VERSION 5.8 ;
BUSBITCHARS "[]" ;
DIVIDERCHAR "/" ;
UNITS
    DATABASE MICRONS 1000 ;
END UNITS

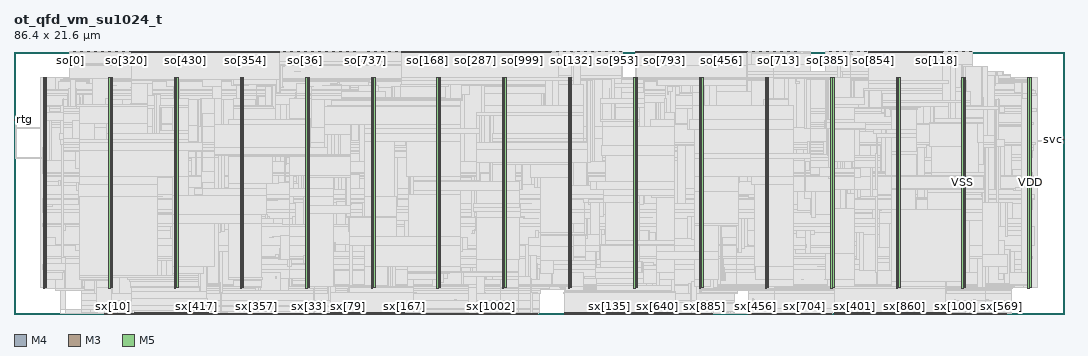
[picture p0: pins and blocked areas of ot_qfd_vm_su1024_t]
MACRO ot_qfd_vm_su1024_t
  FOREIGN ot_qfd_vm_su1024_t 0 0 ;
  CLASS BLOCK ;
  SIZE 86.4 BY 21.6 ;
  PIN clk
    DIRECTION INPUT ;
    USE SIGNAL ;
    PORT
      LAYER M4 ;
        RECT  0 15.888 0.084 15.912 ;
    END
  END clk
  PIN rtg
    DIRECTION INPUT ;
    USE SIGNAL ;
    PORT
      LAYER M4 ;
        RECT  0 15.984 0.084 16.008 ;
    END
  END rtg
  PIN so[0]
    DIRECTION OUTPUT ;
    USE SIGNAL ;
    PORT
      LAYER M3 ;
        RECT  4.644 21.563 4.662 21.6 ;
    END
  END so[0]
  PIN so[1000]
    DIRECTION OUTPUT ;
    USE SIGNAL ;
    PORT
      LAYER M5 ;
        RECT  41.904 21.516 41.928 21.6 ;
    END
  END so[1000]
  PIN so[1001]
    DIRECTION OUTPUT ;
    USE SIGNAL ;
    PORT
      LAYER M5 ;
        RECT  42 21.516 42.024 21.6 ;
    END
  END so[1001]
  PIN so[1002]
    DIRECTION OUTPUT ;
    USE SIGNAL ;
    PORT
      LAYER M5 ;
        RECT  42.096 21.516 42.12 21.6 ;
    END
  END so[1002]
  PIN so[1003]
    DIRECTION OUTPUT ;
    USE SIGNAL ;
    PORT
      LAYER M5 ;
        RECT  42.192 21.516 42.216 21.6 ;
    END
  END so[1003]
  PIN so[1004]
    DIRECTION OUTPUT ;
    USE SIGNAL ;
    PORT
      LAYER M5 ;
        RECT  42.288 21.516 42.312 21.6 ;
    END
  END so[1004]
  PIN so[1005]
    DIRECTION OUTPUT ;
    USE SIGNAL ;
    PORT
      LAYER M5 ;
        RECT  42.384 21.516 42.408 21.6 ;
    END
  END so[1005]
  PIN so[1006]
    DIRECTION OUTPUT ;
    USE SIGNAL ;
    PORT
      LAYER M5 ;
        RECT  42.48 21.516 42.504 21.6 ;
    END
  END so[1006]
  PIN so[1007]
    DIRECTION OUTPUT ;
    USE SIGNAL ;
    PORT
      LAYER M5 ;
        RECT  42.576 21.516 42.6 21.6 ;
    END
  END so[1007]
  PIN so[1008]
    DIRECTION OUTPUT ;
    USE SIGNAL ;
    PORT
      LAYER M5 ;
        RECT  42.672 21.516 42.696 21.6 ;
    END
  END so[1008]
  PIN so[1009]
    DIRECTION OUTPUT ;
    USE SIGNAL ;
    PORT
      LAYER M5 ;
        RECT  42.768 21.516 42.792 21.6 ;
    END
  END so[1009]
  PIN so[100]
    DIRECTION OUTPUT ;
    USE SIGNAL ;
    PORT
      LAYER M3 ;
        RECT  74.628 21.563 74.646 21.6 ;
    END
  END so[100]
  PIN so[1010]
    DIRECTION OUTPUT ;
    USE SIGNAL ;
    PORT
      LAYER M5 ;
        RECT  42.864 21.516 42.888 21.6 ;
    END
  END so[1010]
  PIN so[1011]
    DIRECTION OUTPUT ;
    USE SIGNAL ;
    PORT
      LAYER M5 ;
        RECT  42.96 21.516 42.984 21.6 ;
    END
  END so[1011]
  PIN so[1012]
    DIRECTION OUTPUT ;
    USE SIGNAL ;
    PORT
      LAYER M5 ;
        RECT  43.056 21.516 43.08 21.6 ;
    END
  END so[1012]
  PIN so[1013]
    DIRECTION OUTPUT ;
    USE SIGNAL ;
    PORT
      LAYER M5 ;
        RECT  43.152 21.516 43.176 21.6 ;
    END
  END so[1013]
  PIN so[1014]
    DIRECTION OUTPUT ;
    USE SIGNAL ;
    PORT
      LAYER M5 ;
        RECT  43.248 21.516 43.272 21.6 ;
    END
  END so[1014]
  PIN so[1015]
    DIRECTION OUTPUT ;
    USE SIGNAL ;
    PORT
      LAYER M5 ;
        RECT  43.344 21.516 43.368 21.6 ;
    END
  END so[1015]
  PIN so[1016]
    DIRECTION OUTPUT ;
    USE SIGNAL ;
    PORT
      LAYER M5 ;
        RECT  43.44 21.516 43.464 21.6 ;
    END
  END so[1016]
  PIN so[1017]
    DIRECTION OUTPUT ;
    USE SIGNAL ;
    PORT
      LAYER M5 ;
        RECT  43.536 21.516 43.56 21.6 ;
    END
  END so[1017]
  PIN so[1018]
    DIRECTION OUTPUT ;
    USE SIGNAL ;
    PORT
      LAYER M5 ;
        RECT  43.632 21.516 43.656 21.6 ;
    END
  END so[1018]
  PIN so[1019]
    DIRECTION OUTPUT ;
    USE SIGNAL ;
    PORT
      LAYER M5 ;
        RECT  43.728 21.516 43.752 21.6 ;
    END
  END so[1019]
  PIN so[101]
    DIRECTION OUTPUT ;
    USE SIGNAL ;
    PORT
      LAYER M3 ;
        RECT  74.7 21.563 74.718 21.6 ;
    END
  END so[101]
  PIN so[1020]
    DIRECTION OUTPUT ;
    USE SIGNAL ;
    PORT
      LAYER M5 ;
        RECT  43.824 21.516 43.848 21.6 ;
    END
  END so[1020]
  PIN so[1021]
    DIRECTION OUTPUT ;
    USE SIGNAL ;
    PORT
      LAYER M5 ;
        RECT  43.92 21.516 43.944 21.6 ;
    END
  END so[1021]
  PIN so[1022]
    DIRECTION OUTPUT ;
    USE SIGNAL ;
    PORT
      LAYER M5 ;
        RECT  44.016 21.516 44.04 21.6 ;
    END
  END so[1022]
  PIN so[1023]
    DIRECTION OUTPUT ;
    USE SIGNAL ;
    PORT
      LAYER M5 ;
        RECT  44.112 21.516 44.136 21.6 ;
    END
  END so[1023]
  PIN so[102]
    DIRECTION OUTPUT ;
    USE SIGNAL ;
    PORT
      LAYER M3 ;
        RECT  74.772 21.563 74.79 21.6 ;
    END
  END so[102]
  PIN so[103]
    DIRECTION OUTPUT ;
    USE SIGNAL ;
    PORT
      LAYER M3 ;
        RECT  74.844 21.563 74.862 21.6 ;
    END
  END so[103]
  PIN so[104]
    DIRECTION OUTPUT ;
    USE SIGNAL ;
    PORT
      LAYER M3 ;
        RECT  74.916 21.563 74.934 21.6 ;
    END
  END so[104]
  PIN so[105]
    DIRECTION OUTPUT ;
    USE SIGNAL ;
    PORT
      LAYER M3 ;
        RECT  74.988 21.563 75.006 21.6 ;
    END
  END so[105]
  PIN so[106]
    DIRECTION OUTPUT ;
    USE SIGNAL ;
    PORT
      LAYER M3 ;
        RECT  75.06 21.563 75.078 21.6 ;
    END
  END so[106]
  PIN so[107]
    DIRECTION OUTPUT ;
    USE SIGNAL ;
    PORT
      LAYER M3 ;
        RECT  75.132 21.563 75.15 21.6 ;
    END
  END so[107]
  PIN so[108]
    DIRECTION OUTPUT ;
    USE SIGNAL ;
    PORT
      LAYER M3 ;
        RECT  75.204 21.563 75.222 21.6 ;
    END
  END so[108]
  PIN so[109]
    DIRECTION OUTPUT ;
    USE SIGNAL ;
    PORT
      LAYER M3 ;
        RECT  75.276 21.563 75.294 21.6 ;
    END
  END so[109]
  PIN so[10]
    DIRECTION OUTPUT ;
    USE SIGNAL ;
    PORT
      LAYER M3 ;
        RECT  5.364 21.563 5.382 21.6 ;
    END
  END so[10]
  PIN so[110]
    DIRECTION OUTPUT ;
    USE SIGNAL ;
    PORT
      LAYER M3 ;
        RECT  75.348 21.563 75.366 21.6 ;
    END
  END so[110]
  PIN so[111]
    DIRECTION OUTPUT ;
    USE SIGNAL ;
    PORT
      LAYER M3 ;
        RECT  75.42 21.563 75.438 21.6 ;
    END
  END so[111]
  PIN so[112]
    DIRECTION OUTPUT ;
    USE SIGNAL ;
    PORT
      LAYER M3 ;
        RECT  75.492 21.563 75.51 21.6 ;
    END
  END so[112]
  PIN so[113]
    DIRECTION OUTPUT ;
    USE SIGNAL ;
    PORT
      LAYER M3 ;
        RECT  75.564 21.563 75.582 21.6 ;
    END
  END so[113]
  PIN so[114]
    DIRECTION OUTPUT ;
    USE SIGNAL ;
    PORT
      LAYER M3 ;
        RECT  75.636 21.563 75.654 21.6 ;
    END
  END so[114]
  PIN so[115]
    DIRECTION OUTPUT ;
    USE SIGNAL ;
    PORT
      LAYER M3 ;
        RECT  75.708 21.563 75.726 21.6 ;
    END
  END so[115]
  PIN so[116]
    DIRECTION OUTPUT ;
    USE SIGNAL ;
    PORT
      LAYER M3 ;
        RECT  75.78 21.563 75.798 21.6 ;
    END
  END so[116]
  PIN so[117]
    DIRECTION OUTPUT ;
    USE SIGNAL ;
    PORT
      LAYER M3 ;
        RECT  75.852 21.563 75.87 21.6 ;
    END
  END so[117]
  PIN so[118]
    DIRECTION OUTPUT ;
    USE SIGNAL ;
    PORT
      LAYER M3 ;
        RECT  75.924 21.563 75.942 21.6 ;
    END
  END so[118]
  PIN so[119]
    DIRECTION OUTPUT ;
    USE SIGNAL ;
    PORT
      LAYER M3 ;
        RECT  75.996 21.563 76.014 21.6 ;
    END
  END so[119]
  PIN so[11]
    DIRECTION OUTPUT ;
    USE SIGNAL ;
    PORT
      LAYER M3 ;
        RECT  5.436 21.563 5.454 21.6 ;
    END
  END so[11]
  PIN so[120]
    DIRECTION OUTPUT ;
    USE SIGNAL ;
    PORT
      LAYER M3 ;
        RECT  76.068 21.563 76.086 21.6 ;
    END
  END so[120]
  PIN so[121]
    DIRECTION OUTPUT ;
    USE SIGNAL ;
    PORT
      LAYER M3 ;
        RECT  76.14 21.563 76.158 21.6 ;
    END
  END so[121]
  PIN so[122]
    DIRECTION OUTPUT ;
    USE SIGNAL ;
    PORT
      LAYER M3 ;
        RECT  76.212 21.563 76.23 21.6 ;
    END
  END so[122]
  PIN so[123]
    DIRECTION OUTPUT ;
    USE SIGNAL ;
    PORT
      LAYER M3 ;
        RECT  76.284 21.563 76.302 21.6 ;
    END
  END so[123]
  PIN so[124]
    DIRECTION OUTPUT ;
    USE SIGNAL ;
    PORT
      LAYER M3 ;
        RECT  76.356 21.563 76.374 21.6 ;
    END
  END so[124]
  PIN so[125]
    DIRECTION OUTPUT ;
    USE SIGNAL ;
    PORT
      LAYER M3 ;
        RECT  76.428 21.563 76.446 21.6 ;
    END
  END so[125]
  PIN so[126]
    DIRECTION OUTPUT ;
    USE SIGNAL ;
    PORT
      LAYER M3 ;
        RECT  76.5 21.563 76.518 21.6 ;
    END
  END so[126]
  PIN so[127]
    DIRECTION OUTPUT ;
    USE SIGNAL ;
    PORT
      LAYER M3 ;
        RECT  76.572 21.563 76.59 21.6 ;
    END
  END so[127]
  PIN so[128]
    DIRECTION OUTPUT ;
    USE SIGNAL ;
    PORT
      LAYER M3 ;
        RECT  45.54 21.563 45.558 21.6 ;
    END
  END so[128]
  PIN so[129]
    DIRECTION OUTPUT ;
    USE SIGNAL ;
    PORT
      LAYER M3 ;
        RECT  45.612 21.563 45.63 21.6 ;
    END
  END so[129]
  PIN so[12]
    DIRECTION OUTPUT ;
    USE SIGNAL ;
    PORT
      LAYER M3 ;
        RECT  5.508 21.563 5.526 21.6 ;
    END
  END so[12]
  PIN so[130]
    DIRECTION OUTPUT ;
    USE SIGNAL ;
    PORT
      LAYER M3 ;
        RECT  45.684 21.563 45.702 21.6 ;
    END
  END so[130]
  PIN so[131]
    DIRECTION OUTPUT ;
    USE SIGNAL ;
    PORT
      LAYER M3 ;
        RECT  45.756 21.563 45.774 21.6 ;
    END
  END so[131]
  PIN so[132]
    DIRECTION OUTPUT ;
    USE SIGNAL ;
    PORT
      LAYER M3 ;
        RECT  45.828 21.563 45.846 21.6 ;
    END
  END so[132]
  PIN so[133]
    DIRECTION OUTPUT ;
    USE SIGNAL ;
    PORT
      LAYER M3 ;
        RECT  45.9 21.563 45.918 21.6 ;
    END
  END so[133]
  PIN so[134]
    DIRECTION OUTPUT ;
    USE SIGNAL ;
    PORT
      LAYER M3 ;
        RECT  45.972 21.563 45.99 21.6 ;
    END
  END so[134]
  PIN so[135]
    DIRECTION OUTPUT ;
    USE SIGNAL ;
    PORT
      LAYER M3 ;
        RECT  46.044 21.563 46.062 21.6 ;
    END
  END so[135]
  PIN so[136]
    DIRECTION OUTPUT ;
    USE SIGNAL ;
    PORT
      LAYER M3 ;
        RECT  46.116 21.563 46.134 21.6 ;
    END
  END so[136]
  PIN so[137]
    DIRECTION OUTPUT ;
    USE SIGNAL ;
    PORT
      LAYER M3 ;
        RECT  46.188 21.563 46.206 21.6 ;
    END
  END so[137]
  PIN so[138]
    DIRECTION OUTPUT ;
    USE SIGNAL ;
    PORT
      LAYER M3 ;
        RECT  46.26 21.563 46.278 21.6 ;
    END
  END so[138]
  PIN so[139]
    DIRECTION OUTPUT ;
    USE SIGNAL ;
    PORT
      LAYER M3 ;
        RECT  46.332 21.563 46.35 21.6 ;
    END
  END so[139]
  PIN so[13]
    DIRECTION OUTPUT ;
    USE SIGNAL ;
    PORT
      LAYER M3 ;
        RECT  5.58 21.563 5.598 21.6 ;
    END
  END so[13]
  PIN so[140]
    DIRECTION OUTPUT ;
    USE SIGNAL ;
    PORT
      LAYER M3 ;
        RECT  46.404 21.563 46.422 21.6 ;
    END
  END so[140]
  PIN so[141]
    DIRECTION OUTPUT ;
    USE SIGNAL ;
    PORT
      LAYER M3 ;
        RECT  46.476 21.563 46.494 21.6 ;
    END
  END so[141]
  PIN so[142]
    DIRECTION OUTPUT ;
    USE SIGNAL ;
    PORT
      LAYER M3 ;
        RECT  46.548 21.563 46.566 21.6 ;
    END
  END so[142]
  PIN so[143]
    DIRECTION OUTPUT ;
    USE SIGNAL ;
    PORT
      LAYER M3 ;
        RECT  46.62 21.563 46.638 21.6 ;
    END
  END so[143]
  PIN so[144]
    DIRECTION OUTPUT ;
    USE SIGNAL ;
    PORT
      LAYER M3 ;
        RECT  46.692 21.563 46.71 21.6 ;
    END
  END so[144]
  PIN so[145]
    DIRECTION OUTPUT ;
    USE SIGNAL ;
    PORT
      LAYER M3 ;
        RECT  46.764 21.563 46.782 21.6 ;
    END
  END so[145]
  PIN so[146]
    DIRECTION OUTPUT ;
    USE SIGNAL ;
    PORT
      LAYER M3 ;
        RECT  46.836 21.563 46.854 21.6 ;
    END
  END so[146]
  PIN so[147]
    DIRECTION OUTPUT ;
    USE SIGNAL ;
    PORT
      LAYER M3 ;
        RECT  46.908 21.563 46.926 21.6 ;
    END
  END so[147]
  PIN so[148]
    DIRECTION OUTPUT ;
    USE SIGNAL ;
    PORT
      LAYER M3 ;
        RECT  46.98 21.563 46.998 21.6 ;
    END
  END so[148]
  PIN so[149]
    DIRECTION OUTPUT ;
    USE SIGNAL ;
    PORT
      LAYER M3 ;
        RECT  47.052 21.563 47.07 21.6 ;
    END
  END so[149]
  PIN so[14]
    DIRECTION OUTPUT ;
    USE SIGNAL ;
    PORT
      LAYER M3 ;
        RECT  5.652 21.563 5.67 21.6 ;
    END
  END so[14]
  PIN so[150]
    DIRECTION OUTPUT ;
    USE SIGNAL ;
    PORT
      LAYER M3 ;
        RECT  47.124 21.563 47.142 21.6 ;
    END
  END so[150]
  PIN so[151]
    DIRECTION OUTPUT ;
    USE SIGNAL ;
    PORT
      LAYER M3 ;
        RECT  47.196 21.563 47.214 21.6 ;
    END
  END so[151]
  PIN so[152]
    DIRECTION OUTPUT ;
    USE SIGNAL ;
    PORT
      LAYER M3 ;
        RECT  47.268 21.563 47.286 21.6 ;
    END
  END so[152]
  PIN so[153]
    DIRECTION OUTPUT ;
    USE SIGNAL ;
    PORT
      LAYER M3 ;
        RECT  47.34 21.563 47.358 21.6 ;
    END
  END so[153]
  PIN so[154]
    DIRECTION OUTPUT ;
    USE SIGNAL ;
    PORT
      LAYER M3 ;
        RECT  47.412 21.563 47.43 21.6 ;
    END
  END so[154]
  PIN so[155]
    DIRECTION OUTPUT ;
    USE SIGNAL ;
    PORT
      LAYER M3 ;
        RECT  47.484 21.563 47.502 21.6 ;
    END
  END so[155]
  PIN so[156]
    DIRECTION OUTPUT ;
    USE SIGNAL ;
    PORT
      LAYER M3 ;
        RECT  47.556 21.563 47.574 21.6 ;
    END
  END so[156]
  PIN so[157]
    DIRECTION OUTPUT ;
    USE SIGNAL ;
    PORT
      LAYER M3 ;
        RECT  47.628 21.563 47.646 21.6 ;
    END
  END so[157]
  PIN so[158]
    DIRECTION OUTPUT ;
    USE SIGNAL ;
    PORT
      LAYER M3 ;
        RECT  47.7 21.563 47.718 21.6 ;
    END
  END so[158]
  PIN so[159]
    DIRECTION OUTPUT ;
    USE SIGNAL ;
    PORT
      LAYER M3 ;
        RECT  47.772 21.563 47.79 21.6 ;
    END
  END so[159]
  PIN so[15]
    DIRECTION OUTPUT ;
    USE SIGNAL ;
    PORT
      LAYER M3 ;
        RECT  5.724 21.563 5.742 21.6 ;
    END
  END so[15]
  PIN so[160]
    DIRECTION OUTPUT ;
    USE SIGNAL ;
    PORT
      LAYER M3 ;
        RECT  33.444 21.563 33.462 21.6 ;
    END
  END so[160]
  PIN so[161]
    DIRECTION OUTPUT ;
    USE SIGNAL ;
    PORT
      LAYER M3 ;
        RECT  33.516 21.563 33.534 21.6 ;
    END
  END so[161]
  PIN so[162]
    DIRECTION OUTPUT ;
    USE SIGNAL ;
    PORT
      LAYER M3 ;
        RECT  33.588 21.563 33.606 21.6 ;
    END
  END so[162]
  PIN so[163]
    DIRECTION OUTPUT ;
    USE SIGNAL ;
    PORT
      LAYER M3 ;
        RECT  33.66 21.563 33.678 21.6 ;
    END
  END so[163]
  PIN so[164]
    DIRECTION OUTPUT ;
    USE SIGNAL ;
    PORT
      LAYER M3 ;
        RECT  33.732 21.563 33.75 21.6 ;
    END
  END so[164]
  PIN so[165]
    DIRECTION OUTPUT ;
    USE SIGNAL ;
    PORT
      LAYER M3 ;
        RECT  33.804 21.563 33.822 21.6 ;
    END
  END so[165]
  PIN so[166]
    DIRECTION OUTPUT ;
    USE SIGNAL ;
    PORT
      LAYER M3 ;
        RECT  33.876 21.563 33.894 21.6 ;
    END
  END so[166]
  PIN so[167]
    DIRECTION OUTPUT ;
    USE SIGNAL ;
    PORT
      LAYER M3 ;
        RECT  33.948 21.563 33.966 21.6 ;
    END
  END so[167]
  PIN so[168]
    DIRECTION OUTPUT ;
    USE SIGNAL ;
    PORT
      LAYER M3 ;
        RECT  34.02 21.563 34.038 21.6 ;
    END
  END so[168]
  PIN so[169]
    DIRECTION OUTPUT ;
    USE SIGNAL ;
    PORT
      LAYER M3 ;
        RECT  34.092 21.563 34.11 21.6 ;
    END
  END so[169]
  PIN so[16]
    DIRECTION OUTPUT ;
    USE SIGNAL ;
    PORT
      LAYER M3 ;
        RECT  5.796 21.563 5.814 21.6 ;
    END
  END so[16]
  PIN so[170]
    DIRECTION OUTPUT ;
    USE SIGNAL ;
    PORT
      LAYER M3 ;
        RECT  34.164 21.563 34.182 21.6 ;
    END
  END so[170]
  PIN so[171]
    DIRECTION OUTPUT ;
    USE SIGNAL ;
    PORT
      LAYER M3 ;
        RECT  34.236 21.563 34.254 21.6 ;
    END
  END so[171]
  PIN so[172]
    DIRECTION OUTPUT ;
    USE SIGNAL ;
    PORT
      LAYER M3 ;
        RECT  34.308 21.563 34.326 21.6 ;
    END
  END so[172]
  PIN so[173]
    DIRECTION OUTPUT ;
    USE SIGNAL ;
    PORT
      LAYER M3 ;
        RECT  34.38 21.563 34.398 21.6 ;
    END
  END so[173]
  PIN so[174]
    DIRECTION OUTPUT ;
    USE SIGNAL ;
    PORT
      LAYER M3 ;
        RECT  34.452 21.563 34.47 21.6 ;
    END
  END so[174]
  PIN so[175]
    DIRECTION OUTPUT ;
    USE SIGNAL ;
    PORT
      LAYER M3 ;
        RECT  34.524 21.563 34.542 21.6 ;
    END
  END so[175]
  PIN so[176]
    DIRECTION OUTPUT ;
    USE SIGNAL ;
    PORT
      LAYER M3 ;
        RECT  34.596 21.563 34.614 21.6 ;
    END
  END so[176]
  PIN so[177]
    DIRECTION OUTPUT ;
    USE SIGNAL ;
    PORT
      LAYER M3 ;
        RECT  34.668 21.563 34.686 21.6 ;
    END
  END so[177]
  PIN so[178]
    DIRECTION OUTPUT ;
    USE SIGNAL ;
    PORT
      LAYER M3 ;
        RECT  34.74 21.563 34.758 21.6 ;
    END
  END so[178]
  PIN so[179]
    DIRECTION OUTPUT ;
    USE SIGNAL ;
    PORT
      LAYER M3 ;
        RECT  34.812 21.563 34.83 21.6 ;
    END
  END so[179]
  PIN so[17]
    DIRECTION OUTPUT ;
    USE SIGNAL ;
    PORT
      LAYER M3 ;
        RECT  5.868 21.563 5.886 21.6 ;
    END
  END so[17]
  PIN so[180]
    DIRECTION OUTPUT ;
    USE SIGNAL ;
    PORT
      LAYER M3 ;
        RECT  34.884 21.563 34.902 21.6 ;
    END
  END so[180]
  PIN so[181]
    DIRECTION OUTPUT ;
    USE SIGNAL ;
    PORT
      LAYER M3 ;
        RECT  34.956 21.563 34.974 21.6 ;
    END
  END so[181]
  PIN so[182]
    DIRECTION OUTPUT ;
    USE SIGNAL ;
    PORT
      LAYER M3 ;
        RECT  35.028 21.563 35.046 21.6 ;
    END
  END so[182]
  PIN so[183]
    DIRECTION OUTPUT ;
    USE SIGNAL ;
    PORT
      LAYER M3 ;
        RECT  35.1 21.563 35.118 21.6 ;
    END
  END so[183]
  PIN so[184]
    DIRECTION OUTPUT ;
    USE SIGNAL ;
    PORT
      LAYER M3 ;
        RECT  35.172 21.563 35.19 21.6 ;
    END
  END so[184]
  PIN so[185]
    DIRECTION OUTPUT ;
    USE SIGNAL ;
    PORT
      LAYER M3 ;
        RECT  35.244 21.563 35.262 21.6 ;
    END
  END so[185]
  PIN so[186]
    DIRECTION OUTPUT ;
    USE SIGNAL ;
    PORT
      LAYER M3 ;
        RECT  35.316 21.563 35.334 21.6 ;
    END
  END so[186]
  PIN so[187]
    DIRECTION OUTPUT ;
    USE SIGNAL ;
    PORT
      LAYER M3 ;
        RECT  35.388 21.563 35.406 21.6 ;
    END
  END so[187]
  PIN so[188]
    DIRECTION OUTPUT ;
    USE SIGNAL ;
    PORT
      LAYER M3 ;
        RECT  35.46 21.563 35.478 21.6 ;
    END
  END so[188]
  PIN so[189]
    DIRECTION OUTPUT ;
    USE SIGNAL ;
    PORT
      LAYER M3 ;
        RECT  35.532 21.563 35.55 21.6 ;
    END
  END so[189]
  PIN so[18]
    DIRECTION OUTPUT ;
    USE SIGNAL ;
    PORT
      LAYER M3 ;
        RECT  5.94 21.563 5.958 21.6 ;
    END
  END so[18]
  PIN so[190]
    DIRECTION OUTPUT ;
    USE SIGNAL ;
    PORT
      LAYER M3 ;
        RECT  35.604 21.563 35.622 21.6 ;
    END
  END so[190]
  PIN so[191]
    DIRECTION OUTPUT ;
    USE SIGNAL ;
    PORT
      LAYER M3 ;
        RECT  35.676 21.563 35.694 21.6 ;
    END
  END so[191]
  PIN so[192]
    DIRECTION OUTPUT ;
    USE SIGNAL ;
    PORT
      LAYER M5 ;
        RECT  70.32 21.516 70.344 21.6 ;
    END
  END so[192]
  PIN so[193]
    DIRECTION OUTPUT ;
    USE SIGNAL ;
    PORT
      LAYER M5 ;
        RECT  70.416 21.516 70.44 21.6 ;
    END
  END so[193]
  PIN so[194]
    DIRECTION OUTPUT ;
    USE SIGNAL ;
    PORT
      LAYER M5 ;
        RECT  70.512 21.516 70.536 21.6 ;
    END
  END so[194]
  PIN so[195]
    DIRECTION OUTPUT ;
    USE SIGNAL ;
    PORT
      LAYER M5 ;
        RECT  70.608 21.516 70.632 21.6 ;
    END
  END so[195]
  PIN so[196]
    DIRECTION OUTPUT ;
    USE SIGNAL ;
    PORT
      LAYER M5 ;
        RECT  70.704 21.516 70.728 21.6 ;
    END
  END so[196]
  PIN so[197]
    DIRECTION OUTPUT ;
    USE SIGNAL ;
    PORT
      LAYER M5 ;
        RECT  70.8 21.516 70.824 21.6 ;
    END
  END so[197]
  PIN so[198]
    DIRECTION OUTPUT ;
    USE SIGNAL ;
    PORT
      LAYER M5 ;
        RECT  70.896 21.516 70.92 21.6 ;
    END
  END so[198]
  PIN so[199]
    DIRECTION OUTPUT ;
    USE SIGNAL ;
    PORT
      LAYER M5 ;
        RECT  70.992 21.516 71.016 21.6 ;
    END
  END so[199]
  PIN so[19]
    DIRECTION OUTPUT ;
    USE SIGNAL ;
    PORT
      LAYER M3 ;
        RECT  6.012 21.563 6.03 21.6 ;
    END
  END so[19]
  PIN so[1]
    DIRECTION OUTPUT ;
    USE SIGNAL ;
    PORT
      LAYER M3 ;
        RECT  4.716 21.563 4.734 21.6 ;
    END
  END so[1]
  PIN so[200]
    DIRECTION OUTPUT ;
    USE SIGNAL ;
    PORT
      LAYER M5 ;
        RECT  71.088 21.516 71.112 21.6 ;
    END
  END so[200]
  PIN so[201]
    DIRECTION OUTPUT ;
    USE SIGNAL ;
    PORT
      LAYER M5 ;
        RECT  71.184 21.516 71.208 21.6 ;
    END
  END so[201]
  PIN so[202]
    DIRECTION OUTPUT ;
    USE SIGNAL ;
    PORT
      LAYER M5 ;
        RECT  71.28 21.516 71.304 21.6 ;
    END
  END so[202]
  PIN so[203]
    DIRECTION OUTPUT ;
    USE SIGNAL ;
    PORT
      LAYER M5 ;
        RECT  71.376 21.516 71.4 21.6 ;
    END
  END so[203]
  PIN so[204]
    DIRECTION OUTPUT ;
    USE SIGNAL ;
    PORT
      LAYER M5 ;
        RECT  71.472 21.516 71.496 21.6 ;
    END
  END so[204]
  PIN so[205]
    DIRECTION OUTPUT ;
    USE SIGNAL ;
    PORT
      LAYER M5 ;
        RECT  71.568 21.516 71.592 21.6 ;
    END
  END so[205]
  PIN so[206]
    DIRECTION OUTPUT ;
    USE SIGNAL ;
    PORT
      LAYER M5 ;
        RECT  71.664 21.516 71.688 21.6 ;
    END
  END so[206]
  PIN so[207]
    DIRECTION OUTPUT ;
    USE SIGNAL ;
    PORT
      LAYER M5 ;
        RECT  71.76 21.516 71.784 21.6 ;
    END
  END so[207]
  PIN so[208]
    DIRECTION OUTPUT ;
    USE SIGNAL ;
    PORT
      LAYER M5 ;
        RECT  71.856 21.516 71.88 21.6 ;
    END
  END so[208]
  PIN so[209]
    DIRECTION OUTPUT ;
    USE SIGNAL ;
    PORT
      LAYER M5 ;
        RECT  71.952 21.516 71.976 21.6 ;
    END
  END so[209]
  PIN so[20]
    DIRECTION OUTPUT ;
    USE SIGNAL ;
    PORT
      LAYER M3 ;
        RECT  6.084 21.563 6.102 21.6 ;
    END
  END so[20]
  PIN so[210]
    DIRECTION OUTPUT ;
    USE SIGNAL ;
    PORT
      LAYER M5 ;
        RECT  72.048 21.516 72.072 21.6 ;
    END
  END so[210]
  PIN so[211]
    DIRECTION OUTPUT ;
    USE SIGNAL ;
    PORT
      LAYER M5 ;
        RECT  72.144 21.516 72.168 21.6 ;
    END
  END so[211]
  PIN so[212]
    DIRECTION OUTPUT ;
    USE SIGNAL ;
    PORT
      LAYER M5 ;
        RECT  72.24 21.516 72.264 21.6 ;
    END
  END so[212]
  PIN so[213]
    DIRECTION OUTPUT ;
    USE SIGNAL ;
    PORT
      LAYER M5 ;
        RECT  72.336 21.516 72.36 21.6 ;
    END
  END so[213]
  PIN so[214]
    DIRECTION OUTPUT ;
    USE SIGNAL ;
    PORT
      LAYER M5 ;
        RECT  72.432 21.516 72.456 21.6 ;
    END
  END so[214]
  PIN so[215]
    DIRECTION OUTPUT ;
    USE SIGNAL ;
    PORT
      LAYER M5 ;
        RECT  72.528 21.516 72.552 21.6 ;
    END
  END so[215]
  PIN so[216]
    DIRECTION OUTPUT ;
    USE SIGNAL ;
    PORT
      LAYER M5 ;
        RECT  72.624 21.516 72.648 21.6 ;
    END
  END so[216]
  PIN so[217]
    DIRECTION OUTPUT ;
    USE SIGNAL ;
    PORT
      LAYER M5 ;
        RECT  72.72 21.516 72.744 21.6 ;
    END
  END so[217]
  PIN so[218]
    DIRECTION OUTPUT ;
    USE SIGNAL ;
    PORT
      LAYER M5 ;
        RECT  72.816 21.516 72.84 21.6 ;
    END
  END so[218]
  PIN so[219]
    DIRECTION OUTPUT ;
    USE SIGNAL ;
    PORT
      LAYER M5 ;
        RECT  72.912 21.516 72.936 21.6 ;
    END
  END so[219]
  PIN so[21]
    DIRECTION OUTPUT ;
    USE SIGNAL ;
    PORT
      LAYER M3 ;
        RECT  6.156 21.563 6.174 21.6 ;
    END
  END so[21]
  PIN so[220]
    DIRECTION OUTPUT ;
    USE SIGNAL ;
    PORT
      LAYER M5 ;
        RECT  73.008 21.516 73.032 21.6 ;
    END
  END so[220]
  PIN so[221]
    DIRECTION OUTPUT ;
    USE SIGNAL ;
    PORT
      LAYER M5 ;
        RECT  73.104 21.516 73.128 21.6 ;
    END
  END so[221]
  PIN so[222]
    DIRECTION OUTPUT ;
    USE SIGNAL ;
    PORT
      LAYER M5 ;
        RECT  73.2 21.516 73.224 21.6 ;
    END
  END so[222]
  PIN so[223]
    DIRECTION OUTPUT ;
    USE SIGNAL ;
    PORT
      LAYER M5 ;
        RECT  73.296 21.516 73.32 21.6 ;
    END
  END so[223]
  PIN so[224]
    DIRECTION OUTPUT ;
    USE SIGNAL ;
    PORT
      LAYER M5 ;
        RECT  31.92 21.516 31.944 21.6 ;
    END
  END so[224]
  PIN so[225]
    DIRECTION OUTPUT ;
    USE SIGNAL ;
    PORT
      LAYER M5 ;
        RECT  32.016 21.516 32.04 21.6 ;
    END
  END so[225]
  PIN so[226]
    DIRECTION OUTPUT ;
    USE SIGNAL ;
    PORT
      LAYER M5 ;
        RECT  32.112 21.516 32.136 21.6 ;
    END
  END so[226]
  PIN so[227]
    DIRECTION OUTPUT ;
    USE SIGNAL ;
    PORT
      LAYER M5 ;
        RECT  32.208 21.516 32.232 21.6 ;
    END
  END so[227]
  PIN so[228]
    DIRECTION OUTPUT ;
    USE SIGNAL ;
    PORT
      LAYER M5 ;
        RECT  32.304 21.516 32.328 21.6 ;
    END
  END so[228]
  PIN so[229]
    DIRECTION OUTPUT ;
    USE SIGNAL ;
    PORT
      LAYER M5 ;
        RECT  32.4 21.516 32.424 21.6 ;
    END
  END so[229]
  PIN so[22]
    DIRECTION OUTPUT ;
    USE SIGNAL ;
    PORT
      LAYER M3 ;
        RECT  6.228 21.563 6.246 21.6 ;
    END
  END so[22]
  PIN so[230]
    DIRECTION OUTPUT ;
    USE SIGNAL ;
    PORT
      LAYER M5 ;
        RECT  32.496 21.516 32.52 21.6 ;
    END
  END so[230]
  PIN so[231]
    DIRECTION OUTPUT ;
    USE SIGNAL ;
    PORT
      LAYER M5 ;
        RECT  32.592 21.516 32.616 21.6 ;
    END
  END so[231]
  PIN so[232]
    DIRECTION OUTPUT ;
    USE SIGNAL ;
    PORT
      LAYER M5 ;
        RECT  32.688 21.516 32.712 21.6 ;
    END
  END so[232]
  PIN so[233]
    DIRECTION OUTPUT ;
    USE SIGNAL ;
    PORT
      LAYER M5 ;
        RECT  32.784 21.516 32.808 21.6 ;
    END
  END so[233]
  PIN so[234]
    DIRECTION OUTPUT ;
    USE SIGNAL ;
    PORT
      LAYER M5 ;
        RECT  32.88 21.516 32.904 21.6 ;
    END
  END so[234]
  PIN so[235]
    DIRECTION OUTPUT ;
    USE SIGNAL ;
    PORT
      LAYER M5 ;
        RECT  32.976 21.516 33 21.6 ;
    END
  END so[235]
  PIN so[236]
    DIRECTION OUTPUT ;
    USE SIGNAL ;
    PORT
      LAYER M5 ;
        RECT  33.072 21.516 33.096 21.6 ;
    END
  END so[236]
  PIN so[237]
    DIRECTION OUTPUT ;
    USE SIGNAL ;
    PORT
      LAYER M5 ;
        RECT  33.168 21.516 33.192 21.6 ;
    END
  END so[237]
  PIN so[238]
    DIRECTION OUTPUT ;
    USE SIGNAL ;
    PORT
      LAYER M5 ;
        RECT  33.264 21.516 33.288 21.6 ;
    END
  END so[238]
  PIN so[239]
    DIRECTION OUTPUT ;
    USE SIGNAL ;
    PORT
      LAYER M5 ;
        RECT  33.36 21.516 33.384 21.6 ;
    END
  END so[239]
  PIN so[23]
    DIRECTION OUTPUT ;
    USE SIGNAL ;
    PORT
      LAYER M3 ;
        RECT  6.3 21.563 6.318 21.6 ;
    END
  END so[23]
  PIN so[240]
    DIRECTION OUTPUT ;
    USE SIGNAL ;
    PORT
      LAYER M5 ;
        RECT  33.456 21.516 33.48 21.6 ;
    END
  END so[240]
  PIN so[241]
    DIRECTION OUTPUT ;
    USE SIGNAL ;
    PORT
      LAYER M5 ;
        RECT  33.552 21.516 33.576 21.6 ;
    END
  END so[241]
  PIN so[242]
    DIRECTION OUTPUT ;
    USE SIGNAL ;
    PORT
      LAYER M5 ;
        RECT  33.648 21.516 33.672 21.6 ;
    END
  END so[242]
  PIN so[243]
    DIRECTION OUTPUT ;
    USE SIGNAL ;
    PORT
      LAYER M5 ;
        RECT  33.744 21.516 33.768 21.6 ;
    END
  END so[243]
  PIN so[244]
    DIRECTION OUTPUT ;
    USE SIGNAL ;
    PORT
      LAYER M5 ;
        RECT  33.84 21.516 33.864 21.6 ;
    END
  END so[244]
  PIN so[245]
    DIRECTION OUTPUT ;
    USE SIGNAL ;
    PORT
      LAYER M5 ;
        RECT  33.936 21.516 33.96 21.6 ;
    END
  END so[245]
  PIN so[246]
    DIRECTION OUTPUT ;
    USE SIGNAL ;
    PORT
      LAYER M5 ;
        RECT  34.032 21.516 34.056 21.6 ;
    END
  END so[246]
  PIN so[247]
    DIRECTION OUTPUT ;
    USE SIGNAL ;
    PORT
      LAYER M5 ;
        RECT  34.128 21.516 34.152 21.6 ;
    END
  END so[247]
  PIN so[248]
    DIRECTION OUTPUT ;
    USE SIGNAL ;
    PORT
      LAYER M5 ;
        RECT  34.224 21.516 34.248 21.6 ;
    END
  END so[248]
  PIN so[249]
    DIRECTION OUTPUT ;
    USE SIGNAL ;
    PORT
      LAYER M5 ;
        RECT  34.32 21.516 34.344 21.6 ;
    END
  END so[249]
  PIN so[24]
    DIRECTION OUTPUT ;
    USE SIGNAL ;
    PORT
      LAYER M3 ;
        RECT  6.372 21.563 6.39 21.6 ;
    END
  END so[24]
  PIN so[250]
    DIRECTION OUTPUT ;
    USE SIGNAL ;
    PORT
      LAYER M5 ;
        RECT  34.416 21.516 34.44 21.6 ;
    END
  END so[250]
  PIN so[251]
    DIRECTION OUTPUT ;
    USE SIGNAL ;
    PORT
      LAYER M5 ;
        RECT  34.512 21.516 34.536 21.6 ;
    END
  END so[251]
  PIN so[252]
    DIRECTION OUTPUT ;
    USE SIGNAL ;
    PORT
      LAYER M5 ;
        RECT  34.608 21.516 34.632 21.6 ;
    END
  END so[252]
  PIN so[253]
    DIRECTION OUTPUT ;
    USE SIGNAL ;
    PORT
      LAYER M5 ;
        RECT  34.704 21.516 34.728 21.6 ;
    END
  END so[253]
  PIN so[254]
    DIRECTION OUTPUT ;
    USE SIGNAL ;
    PORT
      LAYER M5 ;
        RECT  34.8 21.516 34.824 21.6 ;
    END
  END so[254]
  PIN so[255]
    DIRECTION OUTPUT ;
    USE SIGNAL ;
    PORT
      LAYER M5 ;
        RECT  34.896 21.516 34.92 21.6 ;
    END
  END so[255]
  PIN so[256]
    DIRECTION OUTPUT ;
    USE SIGNAL ;
    PORT
      LAYER M5 ;
        RECT  34.992 21.516 35.016 21.6 ;
    END
  END so[256]
  PIN so[257]
    DIRECTION OUTPUT ;
    USE SIGNAL ;
    PORT
      LAYER M5 ;
        RECT  35.088 21.516 35.112 21.6 ;
    END
  END so[257]
  PIN so[258]
    DIRECTION OUTPUT ;
    USE SIGNAL ;
    PORT
      LAYER M5 ;
        RECT  35.184 21.516 35.208 21.6 ;
    END
  END so[258]
  PIN so[259]
    DIRECTION OUTPUT ;
    USE SIGNAL ;
    PORT
      LAYER M5 ;
        RECT  35.28 21.516 35.304 21.6 ;
    END
  END so[259]
  PIN so[25]
    DIRECTION OUTPUT ;
    USE SIGNAL ;
    PORT
      LAYER M3 ;
        RECT  6.444 21.563 6.462 21.6 ;
    END
  END so[25]
  PIN so[260]
    DIRECTION OUTPUT ;
    USE SIGNAL ;
    PORT
      LAYER M5 ;
        RECT  35.376 21.516 35.4 21.6 ;
    END
  END so[260]
  PIN so[261]
    DIRECTION OUTPUT ;
    USE SIGNAL ;
    PORT
      LAYER M5 ;
        RECT  35.472 21.516 35.496 21.6 ;
    END
  END so[261]
  PIN so[262]
    DIRECTION OUTPUT ;
    USE SIGNAL ;
    PORT
      LAYER M5 ;
        RECT  35.568 21.516 35.592 21.6 ;
    END
  END so[262]
  PIN so[263]
    DIRECTION OUTPUT ;
    USE SIGNAL ;
    PORT
      LAYER M5 ;
        RECT  35.664 21.516 35.688 21.6 ;
    END
  END so[263]
  PIN so[264]
    DIRECTION OUTPUT ;
    USE SIGNAL ;
    PORT
      LAYER M5 ;
        RECT  35.76 21.516 35.784 21.6 ;
    END
  END so[264]
  PIN so[265]
    DIRECTION OUTPUT ;
    USE SIGNAL ;
    PORT
      LAYER M5 ;
        RECT  35.856 21.516 35.88 21.6 ;
    END
  END so[265]
  PIN so[266]
    DIRECTION OUTPUT ;
    USE SIGNAL ;
    PORT
      LAYER M5 ;
        RECT  35.952 21.516 35.976 21.6 ;
    END
  END so[266]
  PIN so[267]
    DIRECTION OUTPUT ;
    USE SIGNAL ;
    PORT
      LAYER M5 ;
        RECT  36.048 21.516 36.072 21.6 ;
    END
  END so[267]
  PIN so[268]
    DIRECTION OUTPUT ;
    USE SIGNAL ;
    PORT
      LAYER M5 ;
        RECT  36.144 21.516 36.168 21.6 ;
    END
  END so[268]
  PIN so[269]
    DIRECTION OUTPUT ;
    USE SIGNAL ;
    PORT
      LAYER M5 ;
        RECT  36.24 21.516 36.264 21.6 ;
    END
  END so[269]
  PIN so[26]
    DIRECTION OUTPUT ;
    USE SIGNAL ;
    PORT
      LAYER M3 ;
        RECT  6.516 21.563 6.534 21.6 ;
    END
  END so[26]
  PIN so[270]
    DIRECTION OUTPUT ;
    USE SIGNAL ;
    PORT
      LAYER M5 ;
        RECT  36.336 21.516 36.36 21.6 ;
    END
  END so[270]
  PIN so[271]
    DIRECTION OUTPUT ;
    USE SIGNAL ;
    PORT
      LAYER M5 ;
        RECT  36.432 21.516 36.456 21.6 ;
    END
  END so[271]
  PIN so[272]
    DIRECTION OUTPUT ;
    USE SIGNAL ;
    PORT
      LAYER M5 ;
        RECT  36.528 21.516 36.552 21.6 ;
    END
  END so[272]
  PIN so[273]
    DIRECTION OUTPUT ;
    USE SIGNAL ;
    PORT
      LAYER M5 ;
        RECT  36.624 21.516 36.648 21.6 ;
    END
  END so[273]
  PIN so[274]
    DIRECTION OUTPUT ;
    USE SIGNAL ;
    PORT
      LAYER M5 ;
        RECT  36.72 21.516 36.744 21.6 ;
    END
  END so[274]
  PIN so[275]
    DIRECTION OUTPUT ;
    USE SIGNAL ;
    PORT
      LAYER M5 ;
        RECT  36.816 21.516 36.84 21.6 ;
    END
  END so[275]
  PIN so[276]
    DIRECTION OUTPUT ;
    USE SIGNAL ;
    PORT
      LAYER M5 ;
        RECT  36.912 21.516 36.936 21.6 ;
    END
  END so[276]
  PIN so[277]
    DIRECTION OUTPUT ;
    USE SIGNAL ;
    PORT
      LAYER M5 ;
        RECT  37.008 21.516 37.032 21.6 ;
    END
  END so[277]
  PIN so[278]
    DIRECTION OUTPUT ;
    USE SIGNAL ;
    PORT
      LAYER M5 ;
        RECT  37.104 21.516 37.128 21.6 ;
    END
  END so[278]
  PIN so[279]
    DIRECTION OUTPUT ;
    USE SIGNAL ;
    PORT
      LAYER M5 ;
        RECT  37.2 21.516 37.224 21.6 ;
    END
  END so[279]
  PIN so[27]
    DIRECTION OUTPUT ;
    USE SIGNAL ;
    PORT
      LAYER M3 ;
        RECT  6.588 21.563 6.606 21.6 ;
    END
  END so[27]
  PIN so[280]
    DIRECTION OUTPUT ;
    USE SIGNAL ;
    PORT
      LAYER M5 ;
        RECT  37.296 21.516 37.32 21.6 ;
    END
  END so[280]
  PIN so[281]
    DIRECTION OUTPUT ;
    USE SIGNAL ;
    PORT
      LAYER M5 ;
        RECT  37.392 21.516 37.416 21.6 ;
    END
  END so[281]
  PIN so[282]
    DIRECTION OUTPUT ;
    USE SIGNAL ;
    PORT
      LAYER M5 ;
        RECT  37.488 21.516 37.512 21.6 ;
    END
  END so[282]
  PIN so[283]
    DIRECTION OUTPUT ;
    USE SIGNAL ;
    PORT
      LAYER M5 ;
        RECT  37.584 21.516 37.608 21.6 ;
    END
  END so[283]
  PIN so[284]
    DIRECTION OUTPUT ;
    USE SIGNAL ;
    PORT
      LAYER M5 ;
        RECT  37.68 21.516 37.704 21.6 ;
    END
  END so[284]
  PIN so[285]
    DIRECTION OUTPUT ;
    USE SIGNAL ;
    PORT
      LAYER M5 ;
        RECT  37.776 21.516 37.8 21.6 ;
    END
  END so[285]
  PIN so[286]
    DIRECTION OUTPUT ;
    USE SIGNAL ;
    PORT
      LAYER M5 ;
        RECT  37.872 21.516 37.896 21.6 ;
    END
  END so[286]
  PIN so[287]
    DIRECTION OUTPUT ;
    USE SIGNAL ;
    PORT
      LAYER M5 ;
        RECT  37.968 21.516 37.992 21.6 ;
    END
  END so[287]
  PIN so[288]
    DIRECTION OUTPUT ;
    USE SIGNAL ;
    PORT
      LAYER M3 ;
        RECT  43.236 21.563 43.254 21.6 ;
    END
  END so[288]
  PIN so[289]
    DIRECTION OUTPUT ;
    USE SIGNAL ;
    PORT
      LAYER M3 ;
        RECT  43.308 21.563 43.326 21.6 ;
    END
  END so[289]
  PIN so[28]
    DIRECTION OUTPUT ;
    USE SIGNAL ;
    PORT
      LAYER M3 ;
        RECT  6.66 21.563 6.678 21.6 ;
    END
  END so[28]
  PIN so[290]
    DIRECTION OUTPUT ;
    USE SIGNAL ;
    PORT
      LAYER M3 ;
        RECT  43.38 21.563 43.398 21.6 ;
    END
  END so[290]
  PIN so[291]
    DIRECTION OUTPUT ;
    USE SIGNAL ;
    PORT
      LAYER M3 ;
        RECT  43.452 21.563 43.47 21.6 ;
    END
  END so[291]
  PIN so[292]
    DIRECTION OUTPUT ;
    USE SIGNAL ;
    PORT
      LAYER M3 ;
        RECT  43.524 21.563 43.542 21.6 ;
    END
  END so[292]
  PIN so[293]
    DIRECTION OUTPUT ;
    USE SIGNAL ;
    PORT
      LAYER M3 ;
        RECT  43.596 21.563 43.614 21.6 ;
    END
  END so[293]
  PIN so[294]
    DIRECTION OUTPUT ;
    USE SIGNAL ;
    PORT
      LAYER M3 ;
        RECT  43.668 21.563 43.686 21.6 ;
    END
  END so[294]
  PIN so[295]
    DIRECTION OUTPUT ;
    USE SIGNAL ;
    PORT
      LAYER M3 ;
        RECT  43.74 21.563 43.758 21.6 ;
    END
  END so[295]
  PIN so[296]
    DIRECTION OUTPUT ;
    USE SIGNAL ;
    PORT
      LAYER M3 ;
        RECT  43.812 21.563 43.83 21.6 ;
    END
  END so[296]
  PIN so[297]
    DIRECTION OUTPUT ;
    USE SIGNAL ;
    PORT
      LAYER M3 ;
        RECT  43.884 21.563 43.902 21.6 ;
    END
  END so[297]
  PIN so[298]
    DIRECTION OUTPUT ;
    USE SIGNAL ;
    PORT
      LAYER M3 ;
        RECT  43.956 21.563 43.974 21.6 ;
    END
  END so[298]
  PIN so[299]
    DIRECTION OUTPUT ;
    USE SIGNAL ;
    PORT
      LAYER M3 ;
        RECT  44.028 21.563 44.046 21.6 ;
    END
  END so[299]
  PIN so[29]
    DIRECTION OUTPUT ;
    USE SIGNAL ;
    PORT
      LAYER M3 ;
        RECT  6.732 21.563 6.75 21.6 ;
    END
  END so[29]
  PIN so[2]
    DIRECTION OUTPUT ;
    USE SIGNAL ;
    PORT
      LAYER M3 ;
        RECT  4.788 21.563 4.806 21.6 ;
    END
  END so[2]
  PIN so[300]
    DIRECTION OUTPUT ;
    USE SIGNAL ;
    PORT
      LAYER M3 ;
        RECT  44.1 21.563 44.118 21.6 ;
    END
  END so[300]
  PIN so[301]
    DIRECTION OUTPUT ;
    USE SIGNAL ;
    PORT
      LAYER M3 ;
        RECT  44.172 21.563 44.19 21.6 ;
    END
  END so[301]
  PIN so[302]
    DIRECTION OUTPUT ;
    USE SIGNAL ;
    PORT
      LAYER M3 ;
        RECT  44.244 21.563 44.262 21.6 ;
    END
  END so[302]
  PIN so[303]
    DIRECTION OUTPUT ;
    USE SIGNAL ;
    PORT
      LAYER M3 ;
        RECT  44.316 21.563 44.334 21.6 ;
    END
  END so[303]
  PIN so[304]
    DIRECTION OUTPUT ;
    USE SIGNAL ;
    PORT
      LAYER M3 ;
        RECT  44.388 21.563 44.406 21.6 ;
    END
  END so[304]
  PIN so[305]
    DIRECTION OUTPUT ;
    USE SIGNAL ;
    PORT
      LAYER M3 ;
        RECT  44.46 21.563 44.478 21.6 ;
    END
  END so[305]
  PIN so[306]
    DIRECTION OUTPUT ;
    USE SIGNAL ;
    PORT
      LAYER M3 ;
        RECT  44.532 21.563 44.55 21.6 ;
    END
  END so[306]
  PIN so[307]
    DIRECTION OUTPUT ;
    USE SIGNAL ;
    PORT
      LAYER M3 ;
        RECT  44.604 21.563 44.622 21.6 ;
    END
  END so[307]
  PIN so[308]
    DIRECTION OUTPUT ;
    USE SIGNAL ;
    PORT
      LAYER M3 ;
        RECT  44.676 21.563 44.694 21.6 ;
    END
  END so[308]
  PIN so[309]
    DIRECTION OUTPUT ;
    USE SIGNAL ;
    PORT
      LAYER M3 ;
        RECT  44.748 21.563 44.766 21.6 ;
    END
  END so[309]
  PIN so[30]
    DIRECTION OUTPUT ;
    USE SIGNAL ;
    PORT
      LAYER M3 ;
        RECT  6.804 21.563 6.822 21.6 ;
    END
  END so[30]
  PIN so[310]
    DIRECTION OUTPUT ;
    USE SIGNAL ;
    PORT
      LAYER M3 ;
        RECT  44.82 21.563 44.838 21.6 ;
    END
  END so[310]
  PIN so[311]
    DIRECTION OUTPUT ;
    USE SIGNAL ;
    PORT
      LAYER M3 ;
        RECT  44.892 21.563 44.91 21.6 ;
    END
  END so[311]
  PIN so[312]
    DIRECTION OUTPUT ;
    USE SIGNAL ;
    PORT
      LAYER M3 ;
        RECT  44.964 21.563 44.982 21.6 ;
    END
  END so[312]
  PIN so[313]
    DIRECTION OUTPUT ;
    USE SIGNAL ;
    PORT
      LAYER M3 ;
        RECT  45.036 21.563 45.054 21.6 ;
    END
  END so[313]
  PIN so[314]
    DIRECTION OUTPUT ;
    USE SIGNAL ;
    PORT
      LAYER M3 ;
        RECT  45.108 21.563 45.126 21.6 ;
    END
  END so[314]
  PIN so[315]
    DIRECTION OUTPUT ;
    USE SIGNAL ;
    PORT
      LAYER M3 ;
        RECT  45.18 21.563 45.198 21.6 ;
    END
  END so[315]
  PIN so[316]
    DIRECTION OUTPUT ;
    USE SIGNAL ;
    PORT
      LAYER M3 ;
        RECT  45.252 21.563 45.27 21.6 ;
    END
  END so[316]
  PIN so[317]
    DIRECTION OUTPUT ;
    USE SIGNAL ;
    PORT
      LAYER M3 ;
        RECT  45.324 21.563 45.342 21.6 ;
    END
  END so[317]
  PIN so[318]
    DIRECTION OUTPUT ;
    USE SIGNAL ;
    PORT
      LAYER M3 ;
        RECT  45.396 21.563 45.414 21.6 ;
    END
  END so[318]
  PIN so[319]
    DIRECTION OUTPUT ;
    USE SIGNAL ;
    PORT
      LAYER M3 ;
        RECT  45.468 21.563 45.486 21.6 ;
    END
  END so[319]
  PIN so[31]
    DIRECTION OUTPUT ;
    USE SIGNAL ;
    PORT
      LAYER M3 ;
        RECT  6.876 21.563 6.894 21.6 ;
    END
  END so[31]
  PIN so[320]
    DIRECTION OUTPUT ;
    USE SIGNAL ;
    PORT
      LAYER M3 ;
        RECT  9.252 21.563 9.27 21.6 ;
    END
  END so[320]
  PIN so[321]
    DIRECTION OUTPUT ;
    USE SIGNAL ;
    PORT
      LAYER M3 ;
        RECT  9.324 21.563 9.342 21.6 ;
    END
  END so[321]
  PIN so[322]
    DIRECTION OUTPUT ;
    USE SIGNAL ;
    PORT
      LAYER M3 ;
        RECT  9.396 21.563 9.414 21.6 ;
    END
  END so[322]
  PIN so[323]
    DIRECTION OUTPUT ;
    USE SIGNAL ;
    PORT
      LAYER M3 ;
        RECT  9.468 21.563 9.486 21.6 ;
    END
  END so[323]
  PIN so[324]
    DIRECTION OUTPUT ;
    USE SIGNAL ;
    PORT
      LAYER M3 ;
        RECT  9.54 21.563 9.558 21.6 ;
    END
  END so[324]
  PIN so[325]
    DIRECTION OUTPUT ;
    USE SIGNAL ;
    PORT
      LAYER M3 ;
        RECT  9.612 21.563 9.63 21.6 ;
    END
  END so[325]
  PIN so[326]
    DIRECTION OUTPUT ;
    USE SIGNAL ;
    PORT
      LAYER M3 ;
        RECT  9.684 21.563 9.702 21.6 ;
    END
  END so[326]
  PIN so[327]
    DIRECTION OUTPUT ;
    USE SIGNAL ;
    PORT
      LAYER M3 ;
        RECT  9.756 21.563 9.774 21.6 ;
    END
  END so[327]
  PIN so[328]
    DIRECTION OUTPUT ;
    USE SIGNAL ;
    PORT
      LAYER M3 ;
        RECT  9.828 21.563 9.846 21.6 ;
    END
  END so[328]
  PIN so[329]
    DIRECTION OUTPUT ;
    USE SIGNAL ;
    PORT
      LAYER M3 ;
        RECT  9.9 21.563 9.918 21.6 ;
    END
  END so[329]
  PIN so[32]
    DIRECTION OUTPUT ;
    USE SIGNAL ;
    PORT
      LAYER M3 ;
        RECT  23.652 21.563 23.67 21.6 ;
    END
  END so[32]
  PIN so[330]
    DIRECTION OUTPUT ;
    USE SIGNAL ;
    PORT
      LAYER M3 ;
        RECT  9.972 21.563 9.99 21.6 ;
    END
  END so[330]
  PIN so[331]
    DIRECTION OUTPUT ;
    USE SIGNAL ;
    PORT
      LAYER M3 ;
        RECT  10.044 21.563 10.062 21.6 ;
    END
  END so[331]
  PIN so[332]
    DIRECTION OUTPUT ;
    USE SIGNAL ;
    PORT
      LAYER M3 ;
        RECT  10.116 21.563 10.134 21.6 ;
    END
  END so[332]
  PIN so[333]
    DIRECTION OUTPUT ;
    USE SIGNAL ;
    PORT
      LAYER M3 ;
        RECT  10.188 21.563 10.206 21.6 ;
    END
  END so[333]
  PIN so[334]
    DIRECTION OUTPUT ;
    USE SIGNAL ;
    PORT
      LAYER M3 ;
        RECT  10.26 21.563 10.278 21.6 ;
    END
  END so[334]
  PIN so[335]
    DIRECTION OUTPUT ;
    USE SIGNAL ;
    PORT
      LAYER M3 ;
        RECT  10.332 21.563 10.35 21.6 ;
    END
  END so[335]
  PIN so[336]
    DIRECTION OUTPUT ;
    USE SIGNAL ;
    PORT
      LAYER M3 ;
        RECT  10.404 21.563 10.422 21.6 ;
    END
  END so[336]
  PIN so[337]
    DIRECTION OUTPUT ;
    USE SIGNAL ;
    PORT
      LAYER M3 ;
        RECT  10.476 21.563 10.494 21.6 ;
    END
  END so[337]
  PIN so[338]
    DIRECTION OUTPUT ;
    USE SIGNAL ;
    PORT
      LAYER M3 ;
        RECT  10.548 21.563 10.566 21.6 ;
    END
  END so[338]
  PIN so[339]
    DIRECTION OUTPUT ;
    USE SIGNAL ;
    PORT
      LAYER M3 ;
        RECT  10.62 21.563 10.638 21.6 ;
    END
  END so[339]
  PIN so[33]
    DIRECTION OUTPUT ;
    USE SIGNAL ;
    PORT
      LAYER M3 ;
        RECT  23.724 21.563 23.742 21.6 ;
    END
  END so[33]
  PIN so[340]
    DIRECTION OUTPUT ;
    USE SIGNAL ;
    PORT
      LAYER M3 ;
        RECT  10.692 21.563 10.71 21.6 ;
    END
  END so[340]
  PIN so[341]
    DIRECTION OUTPUT ;
    USE SIGNAL ;
    PORT
      LAYER M3 ;
        RECT  10.764 21.563 10.782 21.6 ;
    END
  END so[341]
  PIN so[342]
    DIRECTION OUTPUT ;
    USE SIGNAL ;
    PORT
      LAYER M3 ;
        RECT  10.836 21.563 10.854 21.6 ;
    END
  END so[342]
  PIN so[343]
    DIRECTION OUTPUT ;
    USE SIGNAL ;
    PORT
      LAYER M3 ;
        RECT  10.908 21.563 10.926 21.6 ;
    END
  END so[343]
  PIN so[344]
    DIRECTION OUTPUT ;
    USE SIGNAL ;
    PORT
      LAYER M3 ;
        RECT  10.98 21.563 10.998 21.6 ;
    END
  END so[344]
  PIN so[345]
    DIRECTION OUTPUT ;
    USE SIGNAL ;
    PORT
      LAYER M3 ;
        RECT  11.052 21.563 11.07 21.6 ;
    END
  END so[345]
  PIN so[346]
    DIRECTION OUTPUT ;
    USE SIGNAL ;
    PORT
      LAYER M3 ;
        RECT  11.124 21.563 11.142 21.6 ;
    END
  END so[346]
  PIN so[347]
    DIRECTION OUTPUT ;
    USE SIGNAL ;
    PORT
      LAYER M3 ;
        RECT  11.196 21.563 11.214 21.6 ;
    END
  END so[347]
  PIN so[348]
    DIRECTION OUTPUT ;
    USE SIGNAL ;
    PORT
      LAYER M3 ;
        RECT  11.268 21.563 11.286 21.6 ;
    END
  END so[348]
  PIN so[349]
    DIRECTION OUTPUT ;
    USE SIGNAL ;
    PORT
      LAYER M3 ;
        RECT  11.34 21.563 11.358 21.6 ;
    END
  END so[349]
  PIN so[34]
    DIRECTION OUTPUT ;
    USE SIGNAL ;
    PORT
      LAYER M3 ;
        RECT  23.796 21.563 23.814 21.6 ;
    END
  END so[34]
  PIN so[350]
    DIRECTION OUTPUT ;
    USE SIGNAL ;
    PORT
      LAYER M3 ;
        RECT  11.412 21.563 11.43 21.6 ;
    END
  END so[350]
  PIN so[351]
    DIRECTION OUTPUT ;
    USE SIGNAL ;
    PORT
      LAYER M3 ;
        RECT  11.484 21.563 11.502 21.6 ;
    END
  END so[351]
  PIN so[352]
    DIRECTION OUTPUT ;
    USE SIGNAL ;
    PORT
      LAYER M5 ;
        RECT  18.864 21.516 18.888 21.6 ;
    END
  END so[352]
  PIN so[353]
    DIRECTION OUTPUT ;
    USE SIGNAL ;
    PORT
      LAYER M5 ;
        RECT  18.96 21.516 18.984 21.6 ;
    END
  END so[353]
  PIN so[354]
    DIRECTION OUTPUT ;
    USE SIGNAL ;
    PORT
      LAYER M5 ;
        RECT  19.056 21.516 19.08 21.6 ;
    END
  END so[354]
  PIN so[355]
    DIRECTION OUTPUT ;
    USE SIGNAL ;
    PORT
      LAYER M5 ;
        RECT  19.152 21.516 19.176 21.6 ;
    END
  END so[355]
  PIN so[356]
    DIRECTION OUTPUT ;
    USE SIGNAL ;
    PORT
      LAYER M5 ;
        RECT  19.248 21.516 19.272 21.6 ;
    END
  END so[356]
  PIN so[357]
    DIRECTION OUTPUT ;
    USE SIGNAL ;
    PORT
      LAYER M5 ;
        RECT  19.344 21.516 19.368 21.6 ;
    END
  END so[357]
  PIN so[358]
    DIRECTION OUTPUT ;
    USE SIGNAL ;
    PORT
      LAYER M5 ;
        RECT  19.44 21.516 19.464 21.6 ;
    END
  END so[358]
  PIN so[359]
    DIRECTION OUTPUT ;
    USE SIGNAL ;
    PORT
      LAYER M5 ;
        RECT  19.536 21.516 19.56 21.6 ;
    END
  END so[359]
  PIN so[35]
    DIRECTION OUTPUT ;
    USE SIGNAL ;
    PORT
      LAYER M3 ;
        RECT  23.868 21.563 23.886 21.6 ;
    END
  END so[35]
  PIN so[360]
    DIRECTION OUTPUT ;
    USE SIGNAL ;
    PORT
      LAYER M5 ;
        RECT  19.632 21.516 19.656 21.6 ;
    END
  END so[360]
  PIN so[361]
    DIRECTION OUTPUT ;
    USE SIGNAL ;
    PORT
      LAYER M5 ;
        RECT  19.728 21.516 19.752 21.6 ;
    END
  END so[361]
  PIN so[362]
    DIRECTION OUTPUT ;
    USE SIGNAL ;
    PORT
      LAYER M5 ;
        RECT  19.824 21.516 19.848 21.6 ;
    END
  END so[362]
  PIN so[363]
    DIRECTION OUTPUT ;
    USE SIGNAL ;
    PORT
      LAYER M5 ;
        RECT  19.92 21.516 19.944 21.6 ;
    END
  END so[363]
  PIN so[364]
    DIRECTION OUTPUT ;
    USE SIGNAL ;
    PORT
      LAYER M5 ;
        RECT  20.016 21.516 20.04 21.6 ;
    END
  END so[364]
  PIN so[365]
    DIRECTION OUTPUT ;
    USE SIGNAL ;
    PORT
      LAYER M5 ;
        RECT  20.112 21.516 20.136 21.6 ;
    END
  END so[365]
  PIN so[366]
    DIRECTION OUTPUT ;
    USE SIGNAL ;
    PORT
      LAYER M5 ;
        RECT  20.208 21.516 20.232 21.6 ;
    END
  END so[366]
  PIN so[367]
    DIRECTION OUTPUT ;
    USE SIGNAL ;
    PORT
      LAYER M5 ;
        RECT  20.304 21.516 20.328 21.6 ;
    END
  END so[367]
  PIN so[368]
    DIRECTION OUTPUT ;
    USE SIGNAL ;
    PORT
      LAYER M5 ;
        RECT  20.4 21.516 20.424 21.6 ;
    END
  END so[368]
  PIN so[369]
    DIRECTION OUTPUT ;
    USE SIGNAL ;
    PORT
      LAYER M5 ;
        RECT  20.496 21.516 20.52 21.6 ;
    END
  END so[369]
  PIN so[36]
    DIRECTION OUTPUT ;
    USE SIGNAL ;
    PORT
      LAYER M3 ;
        RECT  23.94 21.563 23.958 21.6 ;
    END
  END so[36]
  PIN so[370]
    DIRECTION OUTPUT ;
    USE SIGNAL ;
    PORT
      LAYER M5 ;
        RECT  20.592 21.516 20.616 21.6 ;
    END
  END so[370]
  PIN so[371]
    DIRECTION OUTPUT ;
    USE SIGNAL ;
    PORT
      LAYER M5 ;
        RECT  20.688 21.516 20.712 21.6 ;
    END
  END so[371]
  PIN so[372]
    DIRECTION OUTPUT ;
    USE SIGNAL ;
    PORT
      LAYER M5 ;
        RECT  20.784 21.516 20.808 21.6 ;
    END
  END so[372]
  PIN so[373]
    DIRECTION OUTPUT ;
    USE SIGNAL ;
    PORT
      LAYER M5 ;
        RECT  20.88 21.516 20.904 21.6 ;
    END
  END so[373]
  PIN so[374]
    DIRECTION OUTPUT ;
    USE SIGNAL ;
    PORT
      LAYER M5 ;
        RECT  20.976 21.516 21 21.6 ;
    END
  END so[374]
  PIN so[375]
    DIRECTION OUTPUT ;
    USE SIGNAL ;
    PORT
      LAYER M5 ;
        RECT  21.072 21.516 21.096 21.6 ;
    END
  END so[375]
  PIN so[376]
    DIRECTION OUTPUT ;
    USE SIGNAL ;
    PORT
      LAYER M5 ;
        RECT  21.168 21.516 21.192 21.6 ;
    END
  END so[376]
  PIN so[377]
    DIRECTION OUTPUT ;
    USE SIGNAL ;
    PORT
      LAYER M5 ;
        RECT  21.264 21.516 21.288 21.6 ;
    END
  END so[377]
  PIN so[378]
    DIRECTION OUTPUT ;
    USE SIGNAL ;
    PORT
      LAYER M5 ;
        RECT  21.36 21.516 21.384 21.6 ;
    END
  END so[378]
  PIN so[379]
    DIRECTION OUTPUT ;
    USE SIGNAL ;
    PORT
      LAYER M5 ;
        RECT  21.456 21.516 21.48 21.6 ;
    END
  END so[379]
  PIN so[37]
    DIRECTION OUTPUT ;
    USE SIGNAL ;
    PORT
      LAYER M3 ;
        RECT  24.012 21.563 24.03 21.6 ;
    END
  END so[37]
  PIN so[380]
    DIRECTION OUTPUT ;
    USE SIGNAL ;
    PORT
      LAYER M5 ;
        RECT  21.552 21.516 21.576 21.6 ;
    END
  END so[380]
  PIN so[381]
    DIRECTION OUTPUT ;
    USE SIGNAL ;
    PORT
      LAYER M5 ;
        RECT  21.648 21.516 21.672 21.6 ;
    END
  END so[381]
  PIN so[382]
    DIRECTION OUTPUT ;
    USE SIGNAL ;
    PORT
      LAYER M5 ;
        RECT  21.744 21.516 21.768 21.6 ;
    END
  END so[382]
  PIN so[383]
    DIRECTION OUTPUT ;
    USE SIGNAL ;
    PORT
      LAYER M5 ;
        RECT  21.84 21.516 21.864 21.6 ;
    END
  END so[383]
  PIN so[384]
    DIRECTION OUTPUT ;
    USE SIGNAL ;
    PORT
      LAYER M3 ;
        RECT  66.852 21.563 66.87 21.6 ;
    END
  END so[384]
  PIN so[385]
    DIRECTION OUTPUT ;
    USE SIGNAL ;
    PORT
      LAYER M3 ;
        RECT  66.924 21.563 66.942 21.6 ;
    END
  END so[385]
  PIN so[386]
    DIRECTION OUTPUT ;
    USE SIGNAL ;
    PORT
      LAYER M3 ;
        RECT  66.996 21.563 67.014 21.6 ;
    END
  END so[386]
  PIN so[387]
    DIRECTION OUTPUT ;
    USE SIGNAL ;
    PORT
      LAYER M3 ;
        RECT  67.068 21.563 67.086 21.6 ;
    END
  END so[387]
  PIN so[388]
    DIRECTION OUTPUT ;
    USE SIGNAL ;
    PORT
      LAYER M3 ;
        RECT  67.14 21.563 67.158 21.6 ;
    END
  END so[388]
  PIN so[389]
    DIRECTION OUTPUT ;
    USE SIGNAL ;
    PORT
      LAYER M3 ;
        RECT  67.212 21.563 67.23 21.6 ;
    END
  END so[389]
  PIN so[38]
    DIRECTION OUTPUT ;
    USE SIGNAL ;
    PORT
      LAYER M3 ;
        RECT  24.084 21.563 24.102 21.6 ;
    END
  END so[38]
  PIN so[390]
    DIRECTION OUTPUT ;
    USE SIGNAL ;
    PORT
      LAYER M3 ;
        RECT  67.284 21.563 67.302 21.6 ;
    END
  END so[390]
  PIN so[391]
    DIRECTION OUTPUT ;
    USE SIGNAL ;
    PORT
      LAYER M3 ;
        RECT  67.356 21.563 67.374 21.6 ;
    END
  END so[391]
  PIN so[392]
    DIRECTION OUTPUT ;
    USE SIGNAL ;
    PORT
      LAYER M3 ;
        RECT  67.428 21.563 67.446 21.6 ;
    END
  END so[392]
  PIN so[393]
    DIRECTION OUTPUT ;
    USE SIGNAL ;
    PORT
      LAYER M3 ;
        RECT  67.5 21.563 67.518 21.6 ;
    END
  END so[393]
  PIN so[394]
    DIRECTION OUTPUT ;
    USE SIGNAL ;
    PORT
      LAYER M3 ;
        RECT  67.572 21.563 67.59 21.6 ;
    END
  END so[394]
  PIN so[395]
    DIRECTION OUTPUT ;
    USE SIGNAL ;
    PORT
      LAYER M3 ;
        RECT  67.644 21.563 67.662 21.6 ;
    END
  END so[395]
  PIN so[396]
    DIRECTION OUTPUT ;
    USE SIGNAL ;
    PORT
      LAYER M3 ;
        RECT  67.716 21.563 67.734 21.6 ;
    END
  END so[396]
  PIN so[397]
    DIRECTION OUTPUT ;
    USE SIGNAL ;
    PORT
      LAYER M3 ;
        RECT  67.788 21.563 67.806 21.6 ;
    END
  END so[397]
  PIN so[398]
    DIRECTION OUTPUT ;
    USE SIGNAL ;
    PORT
      LAYER M3 ;
        RECT  67.86 21.563 67.878 21.6 ;
    END
  END so[398]
  PIN so[399]
    DIRECTION OUTPUT ;
    USE SIGNAL ;
    PORT
      LAYER M3 ;
        RECT  67.932 21.563 67.95 21.6 ;
    END
  END so[399]
  PIN so[39]
    DIRECTION OUTPUT ;
    USE SIGNAL ;
    PORT
      LAYER M3 ;
        RECT  24.156 21.563 24.174 21.6 ;
    END
  END so[39]
  PIN so[3]
    DIRECTION OUTPUT ;
    USE SIGNAL ;
    PORT
      LAYER M3 ;
        RECT  4.86 21.563 4.878 21.6 ;
    END
  END so[3]
  PIN so[400]
    DIRECTION OUTPUT ;
    USE SIGNAL ;
    PORT
      LAYER M3 ;
        RECT  68.004 21.563 68.022 21.6 ;
    END
  END so[400]
  PIN so[401]
    DIRECTION OUTPUT ;
    USE SIGNAL ;
    PORT
      LAYER M3 ;
        RECT  68.076 21.563 68.094 21.6 ;
    END
  END so[401]
  PIN so[402]
    DIRECTION OUTPUT ;
    USE SIGNAL ;
    PORT
      LAYER M3 ;
        RECT  68.148 21.563 68.166 21.6 ;
    END
  END so[402]
  PIN so[403]
    DIRECTION OUTPUT ;
    USE SIGNAL ;
    PORT
      LAYER M3 ;
        RECT  68.22 21.563 68.238 21.6 ;
    END
  END so[403]
  PIN so[404]
    DIRECTION OUTPUT ;
    USE SIGNAL ;
    PORT
      LAYER M3 ;
        RECT  68.292 21.563 68.31 21.6 ;
    END
  END so[404]
  PIN so[405]
    DIRECTION OUTPUT ;
    USE SIGNAL ;
    PORT
      LAYER M3 ;
        RECT  68.364 21.563 68.382 21.6 ;
    END
  END so[405]
  PIN so[406]
    DIRECTION OUTPUT ;
    USE SIGNAL ;
    PORT
      LAYER M3 ;
        RECT  68.436 21.563 68.454 21.6 ;
    END
  END so[406]
  PIN so[407]
    DIRECTION OUTPUT ;
    USE SIGNAL ;
    PORT
      LAYER M3 ;
        RECT  68.508 21.563 68.526 21.6 ;
    END
  END so[407]
  PIN so[408]
    DIRECTION OUTPUT ;
    USE SIGNAL ;
    PORT
      LAYER M3 ;
        RECT  68.58 21.563 68.598 21.6 ;
    END
  END so[408]
  PIN so[409]
    DIRECTION OUTPUT ;
    USE SIGNAL ;
    PORT
      LAYER M3 ;
        RECT  68.652 21.563 68.67 21.6 ;
    END
  END so[409]
  PIN so[40]
    DIRECTION OUTPUT ;
    USE SIGNAL ;
    PORT
      LAYER M3 ;
        RECT  24.228 21.563 24.246 21.6 ;
    END
  END so[40]
  PIN so[410]
    DIRECTION OUTPUT ;
    USE SIGNAL ;
    PORT
      LAYER M3 ;
        RECT  68.724 21.563 68.742 21.6 ;
    END
  END so[410]
  PIN so[411]
    DIRECTION OUTPUT ;
    USE SIGNAL ;
    PORT
      LAYER M3 ;
        RECT  68.796 21.563 68.814 21.6 ;
    END
  END so[411]
  PIN so[412]
    DIRECTION OUTPUT ;
    USE SIGNAL ;
    PORT
      LAYER M3 ;
        RECT  68.868 21.563 68.886 21.6 ;
    END
  END so[412]
  PIN so[413]
    DIRECTION OUTPUT ;
    USE SIGNAL ;
    PORT
      LAYER M3 ;
        RECT  68.94 21.563 68.958 21.6 ;
    END
  END so[413]
  PIN so[414]
    DIRECTION OUTPUT ;
    USE SIGNAL ;
    PORT
      LAYER M3 ;
        RECT  69.012 21.563 69.03 21.6 ;
    END
  END so[414]
  PIN so[415]
    DIRECTION OUTPUT ;
    USE SIGNAL ;
    PORT
      LAYER M3 ;
        RECT  69.084 21.563 69.102 21.6 ;
    END
  END so[415]
  PIN so[416]
    DIRECTION OUTPUT ;
    USE SIGNAL ;
    PORT
      LAYER M5 ;
        RECT  12.72 21.516 12.744 21.6 ;
    END
  END so[416]
  PIN so[417]
    DIRECTION OUTPUT ;
    USE SIGNAL ;
    PORT
      LAYER M5 ;
        RECT  12.816 21.516 12.84 21.6 ;
    END
  END so[417]
  PIN so[418]
    DIRECTION OUTPUT ;
    USE SIGNAL ;
    PORT
      LAYER M5 ;
        RECT  12.912 21.516 12.936 21.6 ;
    END
  END so[418]
  PIN so[419]
    DIRECTION OUTPUT ;
    USE SIGNAL ;
    PORT
      LAYER M5 ;
        RECT  13.008 21.516 13.032 21.6 ;
    END
  END so[419]
  PIN so[41]
    DIRECTION OUTPUT ;
    USE SIGNAL ;
    PORT
      LAYER M3 ;
        RECT  24.3 21.563 24.318 21.6 ;
    END
  END so[41]
  PIN so[420]
    DIRECTION OUTPUT ;
    USE SIGNAL ;
    PORT
      LAYER M5 ;
        RECT  13.104 21.516 13.128 21.6 ;
    END
  END so[420]
  PIN so[421]
    DIRECTION OUTPUT ;
    USE SIGNAL ;
    PORT
      LAYER M5 ;
        RECT  13.2 21.516 13.224 21.6 ;
    END
  END so[421]
  PIN so[422]
    DIRECTION OUTPUT ;
    USE SIGNAL ;
    PORT
      LAYER M5 ;
        RECT  13.296 21.516 13.32 21.6 ;
    END
  END so[422]
  PIN so[423]
    DIRECTION OUTPUT ;
    USE SIGNAL ;
    PORT
      LAYER M5 ;
        RECT  13.392 21.516 13.416 21.6 ;
    END
  END so[423]
  PIN so[424]
    DIRECTION OUTPUT ;
    USE SIGNAL ;
    PORT
      LAYER M5 ;
        RECT  13.488 21.516 13.512 21.6 ;
    END
  END so[424]
  PIN so[425]
    DIRECTION OUTPUT ;
    USE SIGNAL ;
    PORT
      LAYER M5 ;
        RECT  13.584 21.516 13.608 21.6 ;
    END
  END so[425]
  PIN so[426]
    DIRECTION OUTPUT ;
    USE SIGNAL ;
    PORT
      LAYER M5 ;
        RECT  13.68 21.516 13.704 21.6 ;
    END
  END so[426]
  PIN so[427]
    DIRECTION OUTPUT ;
    USE SIGNAL ;
    PORT
      LAYER M5 ;
        RECT  13.776 21.516 13.8 21.6 ;
    END
  END so[427]
  PIN so[428]
    DIRECTION OUTPUT ;
    USE SIGNAL ;
    PORT
      LAYER M5 ;
        RECT  13.872 21.516 13.896 21.6 ;
    END
  END so[428]
  PIN so[429]
    DIRECTION OUTPUT ;
    USE SIGNAL ;
    PORT
      LAYER M5 ;
        RECT  13.968 21.516 13.992 21.6 ;
    END
  END so[429]
  PIN so[42]
    DIRECTION OUTPUT ;
    USE SIGNAL ;
    PORT
      LAYER M3 ;
        RECT  24.372 21.563 24.39 21.6 ;
    END
  END so[42]
  PIN so[430]
    DIRECTION OUTPUT ;
    USE SIGNAL ;
    PORT
      LAYER M5 ;
        RECT  14.064 21.516 14.088 21.6 ;
    END
  END so[430]
  PIN so[431]
    DIRECTION OUTPUT ;
    USE SIGNAL ;
    PORT
      LAYER M5 ;
        RECT  14.16 21.516 14.184 21.6 ;
    END
  END so[431]
  PIN so[432]
    DIRECTION OUTPUT ;
    USE SIGNAL ;
    PORT
      LAYER M5 ;
        RECT  14.256 21.516 14.28 21.6 ;
    END
  END so[432]
  PIN so[433]
    DIRECTION OUTPUT ;
    USE SIGNAL ;
    PORT
      LAYER M5 ;
        RECT  14.352 21.516 14.376 21.6 ;
    END
  END so[433]
  PIN so[434]
    DIRECTION OUTPUT ;
    USE SIGNAL ;
    PORT
      LAYER M5 ;
        RECT  14.448 21.516 14.472 21.6 ;
    END
  END so[434]
  PIN so[435]
    DIRECTION OUTPUT ;
    USE SIGNAL ;
    PORT
      LAYER M5 ;
        RECT  14.544 21.516 14.568 21.6 ;
    END
  END so[435]
  PIN so[436]
    DIRECTION OUTPUT ;
    USE SIGNAL ;
    PORT
      LAYER M5 ;
        RECT  14.64 21.516 14.664 21.6 ;
    END
  END so[436]
  PIN so[437]
    DIRECTION OUTPUT ;
    USE SIGNAL ;
    PORT
      LAYER M5 ;
        RECT  14.736 21.516 14.76 21.6 ;
    END
  END so[437]
  PIN so[438]
    DIRECTION OUTPUT ;
    USE SIGNAL ;
    PORT
      LAYER M5 ;
        RECT  14.832 21.516 14.856 21.6 ;
    END
  END so[438]
  PIN so[439]
    DIRECTION OUTPUT ;
    USE SIGNAL ;
    PORT
      LAYER M5 ;
        RECT  14.928 21.516 14.952 21.6 ;
    END
  END so[439]
  PIN so[43]
    DIRECTION OUTPUT ;
    USE SIGNAL ;
    PORT
      LAYER M3 ;
        RECT  24.444 21.563 24.462 21.6 ;
    END
  END so[43]
  PIN so[440]
    DIRECTION OUTPUT ;
    USE SIGNAL ;
    PORT
      LAYER M5 ;
        RECT  15.024 21.516 15.048 21.6 ;
    END
  END so[440]
  PIN so[441]
    DIRECTION OUTPUT ;
    USE SIGNAL ;
    PORT
      LAYER M5 ;
        RECT  15.12 21.516 15.144 21.6 ;
    END
  END so[441]
  PIN so[442]
    DIRECTION OUTPUT ;
    USE SIGNAL ;
    PORT
      LAYER M5 ;
        RECT  15.216 21.516 15.24 21.6 ;
    END
  END so[442]
  PIN so[443]
    DIRECTION OUTPUT ;
    USE SIGNAL ;
    PORT
      LAYER M5 ;
        RECT  15.312 21.516 15.336 21.6 ;
    END
  END so[443]
  PIN so[444]
    DIRECTION OUTPUT ;
    USE SIGNAL ;
    PORT
      LAYER M5 ;
        RECT  15.408 21.516 15.432 21.6 ;
    END
  END so[444]
  PIN so[445]
    DIRECTION OUTPUT ;
    USE SIGNAL ;
    PORT
      LAYER M5 ;
        RECT  15.504 21.516 15.528 21.6 ;
    END
  END so[445]
  PIN so[446]
    DIRECTION OUTPUT ;
    USE SIGNAL ;
    PORT
      LAYER M5 ;
        RECT  15.6 21.516 15.624 21.6 ;
    END
  END so[446]
  PIN so[447]
    DIRECTION OUTPUT ;
    USE SIGNAL ;
    PORT
      LAYER M5 ;
        RECT  15.696 21.516 15.72 21.6 ;
    END
  END so[447]
  PIN so[448]
    DIRECTION OUTPUT ;
    USE SIGNAL ;
    PORT
      LAYER M3 ;
        RECT  57.636 21.563 57.654 21.6 ;
    END
  END so[448]
  PIN so[449]
    DIRECTION OUTPUT ;
    USE SIGNAL ;
    PORT
      LAYER M3 ;
        RECT  57.708 21.563 57.726 21.6 ;
    END
  END so[449]
  PIN so[44]
    DIRECTION OUTPUT ;
    USE SIGNAL ;
    PORT
      LAYER M3 ;
        RECT  24.516 21.563 24.534 21.6 ;
    END
  END so[44]
  PIN so[450]
    DIRECTION OUTPUT ;
    USE SIGNAL ;
    PORT
      LAYER M3 ;
        RECT  57.78 21.563 57.798 21.6 ;
    END
  END so[450]
  PIN so[451]
    DIRECTION OUTPUT ;
    USE SIGNAL ;
    PORT
      LAYER M3 ;
        RECT  57.852 21.563 57.87 21.6 ;
    END
  END so[451]
  PIN so[452]
    DIRECTION OUTPUT ;
    USE SIGNAL ;
    PORT
      LAYER M3 ;
        RECT  57.924 21.563 57.942 21.6 ;
    END
  END so[452]
  PIN so[453]
    DIRECTION OUTPUT ;
    USE SIGNAL ;
    PORT
      LAYER M3 ;
        RECT  57.996 21.563 58.014 21.6 ;
    END
  END so[453]
  PIN so[454]
    DIRECTION OUTPUT ;
    USE SIGNAL ;
    PORT
      LAYER M3 ;
        RECT  58.068 21.563 58.086 21.6 ;
    END
  END so[454]
  PIN so[455]
    DIRECTION OUTPUT ;
    USE SIGNAL ;
    PORT
      LAYER M3 ;
        RECT  58.14 21.563 58.158 21.6 ;
    END
  END so[455]
  PIN so[456]
    DIRECTION OUTPUT ;
    USE SIGNAL ;
    PORT
      LAYER M3 ;
        RECT  58.212 21.563 58.23 21.6 ;
    END
  END so[456]
  PIN so[457]
    DIRECTION OUTPUT ;
    USE SIGNAL ;
    PORT
      LAYER M3 ;
        RECT  58.284 21.563 58.302 21.6 ;
    END
  END so[457]
  PIN so[458]
    DIRECTION OUTPUT ;
    USE SIGNAL ;
    PORT
      LAYER M3 ;
        RECT  58.356 21.563 58.374 21.6 ;
    END
  END so[458]
  PIN so[459]
    DIRECTION OUTPUT ;
    USE SIGNAL ;
    PORT
      LAYER M3 ;
        RECT  58.428 21.563 58.446 21.6 ;
    END
  END so[459]
  PIN so[45]
    DIRECTION OUTPUT ;
    USE SIGNAL ;
    PORT
      LAYER M3 ;
        RECT  24.588 21.563 24.606 21.6 ;
    END
  END so[45]
  PIN so[460]
    DIRECTION OUTPUT ;
    USE SIGNAL ;
    PORT
      LAYER M3 ;
        RECT  58.5 21.563 58.518 21.6 ;
    END
  END so[460]
  PIN so[461]
    DIRECTION OUTPUT ;
    USE SIGNAL ;
    PORT
      LAYER M3 ;
        RECT  58.572 21.563 58.59 21.6 ;
    END
  END so[461]
  PIN so[462]
    DIRECTION OUTPUT ;
    USE SIGNAL ;
    PORT
      LAYER M3 ;
        RECT  58.644 21.563 58.662 21.6 ;
    END
  END so[462]
  PIN so[463]
    DIRECTION OUTPUT ;
    USE SIGNAL ;
    PORT
      LAYER M3 ;
        RECT  58.716 21.563 58.734 21.6 ;
    END
  END so[463]
  PIN so[464]
    DIRECTION OUTPUT ;
    USE SIGNAL ;
    PORT
      LAYER M3 ;
        RECT  58.788 21.563 58.806 21.6 ;
    END
  END so[464]
  PIN so[465]
    DIRECTION OUTPUT ;
    USE SIGNAL ;
    PORT
      LAYER M3 ;
        RECT  58.86 21.563 58.878 21.6 ;
    END
  END so[465]
  PIN so[466]
    DIRECTION OUTPUT ;
    USE SIGNAL ;
    PORT
      LAYER M3 ;
        RECT  58.932 21.563 58.95 21.6 ;
    END
  END so[466]
  PIN so[467]
    DIRECTION OUTPUT ;
    USE SIGNAL ;
    PORT
      LAYER M3 ;
        RECT  59.004 21.563 59.022 21.6 ;
    END
  END so[467]
  PIN so[468]
    DIRECTION OUTPUT ;
    USE SIGNAL ;
    PORT
      LAYER M3 ;
        RECT  59.076 21.563 59.094 21.6 ;
    END
  END so[468]
  PIN so[469]
    DIRECTION OUTPUT ;
    USE SIGNAL ;
    PORT
      LAYER M3 ;
        RECT  59.148 21.563 59.166 21.6 ;
    END
  END so[469]
  PIN so[46]
    DIRECTION OUTPUT ;
    USE SIGNAL ;
    PORT
      LAYER M3 ;
        RECT  24.66 21.563 24.678 21.6 ;
    END
  END so[46]
  PIN so[470]
    DIRECTION OUTPUT ;
    USE SIGNAL ;
    PORT
      LAYER M3 ;
        RECT  59.22 21.563 59.238 21.6 ;
    END
  END so[470]
  PIN so[471]
    DIRECTION OUTPUT ;
    USE SIGNAL ;
    PORT
      LAYER M3 ;
        RECT  59.292 21.563 59.31 21.6 ;
    END
  END so[471]
  PIN so[472]
    DIRECTION OUTPUT ;
    USE SIGNAL ;
    PORT
      LAYER M3 ;
        RECT  59.364 21.563 59.382 21.6 ;
    END
  END so[472]
  PIN so[473]
    DIRECTION OUTPUT ;
    USE SIGNAL ;
    PORT
      LAYER M3 ;
        RECT  59.436 21.563 59.454 21.6 ;
    END
  END so[473]
  PIN so[474]
    DIRECTION OUTPUT ;
    USE SIGNAL ;
    PORT
      LAYER M3 ;
        RECT  59.508 21.563 59.526 21.6 ;
    END
  END so[474]
  PIN so[475]
    DIRECTION OUTPUT ;
    USE SIGNAL ;
    PORT
      LAYER M3 ;
        RECT  59.58 21.563 59.598 21.6 ;
    END
  END so[475]
  PIN so[476]
    DIRECTION OUTPUT ;
    USE SIGNAL ;
    PORT
      LAYER M3 ;
        RECT  59.652 21.563 59.67 21.6 ;
    END
  END so[476]
  PIN so[477]
    DIRECTION OUTPUT ;
    USE SIGNAL ;
    PORT
      LAYER M3 ;
        RECT  59.724 21.563 59.742 21.6 ;
    END
  END so[477]
  PIN so[478]
    DIRECTION OUTPUT ;
    USE SIGNAL ;
    PORT
      LAYER M3 ;
        RECT  59.796 21.563 59.814 21.6 ;
    END
  END so[478]
  PIN so[479]
    DIRECTION OUTPUT ;
    USE SIGNAL ;
    PORT
      LAYER M3 ;
        RECT  59.868 21.563 59.886 21.6 ;
    END
  END so[479]
  PIN so[47]
    DIRECTION OUTPUT ;
    USE SIGNAL ;
    PORT
      LAYER M3 ;
        RECT  24.732 21.563 24.75 21.6 ;
    END
  END so[47]
  PIN so[480]
    DIRECTION OUTPUT ;
    USE SIGNAL ;
    PORT
      LAYER M5 ;
        RECT  38.064 21.516 38.088 21.6 ;
    END
  END so[480]
  PIN so[481]
    DIRECTION OUTPUT ;
    USE SIGNAL ;
    PORT
      LAYER M5 ;
        RECT  38.16 21.516 38.184 21.6 ;
    END
  END so[481]
  PIN so[482]
    DIRECTION OUTPUT ;
    USE SIGNAL ;
    PORT
      LAYER M5 ;
        RECT  38.256 21.516 38.28 21.6 ;
    END
  END so[482]
  PIN so[483]
    DIRECTION OUTPUT ;
    USE SIGNAL ;
    PORT
      LAYER M5 ;
        RECT  38.352 21.516 38.376 21.6 ;
    END
  END so[483]
  PIN so[484]
    DIRECTION OUTPUT ;
    USE SIGNAL ;
    PORT
      LAYER M5 ;
        RECT  38.448 21.516 38.472 21.6 ;
    END
  END so[484]
  PIN so[485]
    DIRECTION OUTPUT ;
    USE SIGNAL ;
    PORT
      LAYER M5 ;
        RECT  38.544 21.516 38.568 21.6 ;
    END
  END so[485]
  PIN so[486]
    DIRECTION OUTPUT ;
    USE SIGNAL ;
    PORT
      LAYER M5 ;
        RECT  38.64 21.516 38.664 21.6 ;
    END
  END so[486]
  PIN so[487]
    DIRECTION OUTPUT ;
    USE SIGNAL ;
    PORT
      LAYER M5 ;
        RECT  38.736 21.516 38.76 21.6 ;
    END
  END so[487]
  PIN so[488]
    DIRECTION OUTPUT ;
    USE SIGNAL ;
    PORT
      LAYER M5 ;
        RECT  38.832 21.516 38.856 21.6 ;
    END
  END so[488]
  PIN so[489]
    DIRECTION OUTPUT ;
    USE SIGNAL ;
    PORT
      LAYER M5 ;
        RECT  38.928 21.516 38.952 21.6 ;
    END
  END so[489]
  PIN so[48]
    DIRECTION OUTPUT ;
    USE SIGNAL ;
    PORT
      LAYER M3 ;
        RECT  24.804 21.563 24.822 21.6 ;
    END
  END so[48]
  PIN so[490]
    DIRECTION OUTPUT ;
    USE SIGNAL ;
    PORT
      LAYER M5 ;
        RECT  39.024 21.516 39.048 21.6 ;
    END
  END so[490]
  PIN so[491]
    DIRECTION OUTPUT ;
    USE SIGNAL ;
    PORT
      LAYER M5 ;
        RECT  39.12 21.516 39.144 21.6 ;
    END
  END so[491]
  PIN so[492]
    DIRECTION OUTPUT ;
    USE SIGNAL ;
    PORT
      LAYER M5 ;
        RECT  39.216 21.516 39.24 21.6 ;
    END
  END so[492]
  PIN so[493]
    DIRECTION OUTPUT ;
    USE SIGNAL ;
    PORT
      LAYER M5 ;
        RECT  39.312 21.516 39.336 21.6 ;
    END
  END so[493]
  PIN so[494]
    DIRECTION OUTPUT ;
    USE SIGNAL ;
    PORT
      LAYER M5 ;
        RECT  39.408 21.516 39.432 21.6 ;
    END
  END so[494]
  PIN so[495]
    DIRECTION OUTPUT ;
    USE SIGNAL ;
    PORT
      LAYER M5 ;
        RECT  39.504 21.516 39.528 21.6 ;
    END
  END so[495]
  PIN so[496]
    DIRECTION OUTPUT ;
    USE SIGNAL ;
    PORT
      LAYER M5 ;
        RECT  39.6 21.516 39.624 21.6 ;
    END
  END so[496]
  PIN so[497]
    DIRECTION OUTPUT ;
    USE SIGNAL ;
    PORT
      LAYER M5 ;
        RECT  39.696 21.516 39.72 21.6 ;
    END
  END so[497]
  PIN so[498]
    DIRECTION OUTPUT ;
    USE SIGNAL ;
    PORT
      LAYER M5 ;
        RECT  39.792 21.516 39.816 21.6 ;
    END
  END so[498]
  PIN so[499]
    DIRECTION OUTPUT ;
    USE SIGNAL ;
    PORT
      LAYER M5 ;
        RECT  39.888 21.516 39.912 21.6 ;
    END
  END so[499]
  PIN so[49]
    DIRECTION OUTPUT ;
    USE SIGNAL ;
    PORT
      LAYER M3 ;
        RECT  24.876 21.563 24.894 21.6 ;
    END
  END so[49]
  PIN so[4]
    DIRECTION OUTPUT ;
    USE SIGNAL ;
    PORT
      LAYER M3 ;
        RECT  4.932 21.563 4.95 21.6 ;
    END
  END so[4]
  PIN so[500]
    DIRECTION OUTPUT ;
    USE SIGNAL ;
    PORT
      LAYER M5 ;
        RECT  39.984 21.516 40.008 21.6 ;
    END
  END so[500]
  PIN so[501]
    DIRECTION OUTPUT ;
    USE SIGNAL ;
    PORT
      LAYER M5 ;
        RECT  40.08 21.516 40.104 21.6 ;
    END
  END so[501]
  PIN so[502]
    DIRECTION OUTPUT ;
    USE SIGNAL ;
    PORT
      LAYER M5 ;
        RECT  40.176 21.516 40.2 21.6 ;
    END
  END so[502]
  PIN so[503]
    DIRECTION OUTPUT ;
    USE SIGNAL ;
    PORT
      LAYER M5 ;
        RECT  40.272 21.516 40.296 21.6 ;
    END
  END so[503]
  PIN so[504]
    DIRECTION OUTPUT ;
    USE SIGNAL ;
    PORT
      LAYER M5 ;
        RECT  40.368 21.516 40.392 21.6 ;
    END
  END so[504]
  PIN so[505]
    DIRECTION OUTPUT ;
    USE SIGNAL ;
    PORT
      LAYER M5 ;
        RECT  40.464 21.516 40.488 21.6 ;
    END
  END so[505]
  PIN so[506]
    DIRECTION OUTPUT ;
    USE SIGNAL ;
    PORT
      LAYER M5 ;
        RECT  40.56 21.516 40.584 21.6 ;
    END
  END so[506]
  PIN so[507]
    DIRECTION OUTPUT ;
    USE SIGNAL ;
    PORT
      LAYER M5 ;
        RECT  40.656 21.516 40.68 21.6 ;
    END
  END so[507]
  PIN so[508]
    DIRECTION OUTPUT ;
    USE SIGNAL ;
    PORT
      LAYER M5 ;
        RECT  40.752 21.516 40.776 21.6 ;
    END
  END so[508]
  PIN so[509]
    DIRECTION OUTPUT ;
    USE SIGNAL ;
    PORT
      LAYER M5 ;
        RECT  40.848 21.516 40.872 21.6 ;
    END
  END so[509]
  PIN so[50]
    DIRECTION OUTPUT ;
    USE SIGNAL ;
    PORT
      LAYER M3 ;
        RECT  24.948 21.563 24.966 21.6 ;
    END
  END so[50]
  PIN so[510]
    DIRECTION OUTPUT ;
    USE SIGNAL ;
    PORT
      LAYER M5 ;
        RECT  40.944 21.516 40.968 21.6 ;
    END
  END so[510]
  PIN so[511]
    DIRECTION OUTPUT ;
    USE SIGNAL ;
    PORT
      LAYER M5 ;
        RECT  41.04 21.516 41.064 21.6 ;
    END
  END so[511]
  PIN so[512]
    DIRECTION OUTPUT ;
    USE SIGNAL ;
    PORT
      LAYER M3 ;
        RECT  59.94 21.563 59.958 21.6 ;
    END
  END so[512]
  PIN so[513]
    DIRECTION OUTPUT ;
    USE SIGNAL ;
    PORT
      LAYER M3 ;
        RECT  60.012 21.563 60.03 21.6 ;
    END
  END so[513]
  PIN so[514]
    DIRECTION OUTPUT ;
    USE SIGNAL ;
    PORT
      LAYER M3 ;
        RECT  60.084 21.563 60.102 21.6 ;
    END
  END so[514]
  PIN so[515]
    DIRECTION OUTPUT ;
    USE SIGNAL ;
    PORT
      LAYER M3 ;
        RECT  60.156 21.563 60.174 21.6 ;
    END
  END so[515]
  PIN so[516]
    DIRECTION OUTPUT ;
    USE SIGNAL ;
    PORT
      LAYER M3 ;
        RECT  60.228 21.563 60.246 21.6 ;
    END
  END so[516]
  PIN so[517]
    DIRECTION OUTPUT ;
    USE SIGNAL ;
    PORT
      LAYER M3 ;
        RECT  60.3 21.563 60.318 21.6 ;
    END
  END so[517]
  PIN so[518]
    DIRECTION OUTPUT ;
    USE SIGNAL ;
    PORT
      LAYER M3 ;
        RECT  60.372 21.563 60.39 21.6 ;
    END
  END so[518]
  PIN so[519]
    DIRECTION OUTPUT ;
    USE SIGNAL ;
    PORT
      LAYER M3 ;
        RECT  60.444 21.563 60.462 21.6 ;
    END
  END so[519]
  PIN so[51]
    DIRECTION OUTPUT ;
    USE SIGNAL ;
    PORT
      LAYER M3 ;
        RECT  25.02 21.563 25.038 21.6 ;
    END
  END so[51]
  PIN so[520]
    DIRECTION OUTPUT ;
    USE SIGNAL ;
    PORT
      LAYER M3 ;
        RECT  60.516 21.563 60.534 21.6 ;
    END
  END so[520]
  PIN so[521]
    DIRECTION OUTPUT ;
    USE SIGNAL ;
    PORT
      LAYER M3 ;
        RECT  60.588 21.563 60.606 21.6 ;
    END
  END so[521]
  PIN so[522]
    DIRECTION OUTPUT ;
    USE SIGNAL ;
    PORT
      LAYER M3 ;
        RECT  60.66 21.563 60.678 21.6 ;
    END
  END so[522]
  PIN so[523]
    DIRECTION OUTPUT ;
    USE SIGNAL ;
    PORT
      LAYER M3 ;
        RECT  60.732 21.563 60.75 21.6 ;
    END
  END so[523]
  PIN so[524]
    DIRECTION OUTPUT ;
    USE SIGNAL ;
    PORT
      LAYER M3 ;
        RECT  60.804 21.563 60.822 21.6 ;
    END
  END so[524]
  PIN so[525]
    DIRECTION OUTPUT ;
    USE SIGNAL ;
    PORT
      LAYER M3 ;
        RECT  60.876 21.563 60.894 21.6 ;
    END
  END so[525]
  PIN so[526]
    DIRECTION OUTPUT ;
    USE SIGNAL ;
    PORT
      LAYER M3 ;
        RECT  60.948 21.563 60.966 21.6 ;
    END
  END so[526]
  PIN so[527]
    DIRECTION OUTPUT ;
    USE SIGNAL ;
    PORT
      LAYER M3 ;
        RECT  61.02 21.563 61.038 21.6 ;
    END
  END so[527]
  PIN so[528]
    DIRECTION OUTPUT ;
    USE SIGNAL ;
    PORT
      LAYER M3 ;
        RECT  61.092 21.563 61.11 21.6 ;
    END
  END so[528]
  PIN so[529]
    DIRECTION OUTPUT ;
    USE SIGNAL ;
    PORT
      LAYER M3 ;
        RECT  61.164 21.563 61.182 21.6 ;
    END
  END so[529]
  PIN so[52]
    DIRECTION OUTPUT ;
    USE SIGNAL ;
    PORT
      LAYER M3 ;
        RECT  25.092 21.563 25.11 21.6 ;
    END
  END so[52]
  PIN so[530]
    DIRECTION OUTPUT ;
    USE SIGNAL ;
    PORT
      LAYER M3 ;
        RECT  61.236 21.563 61.254 21.6 ;
    END
  END so[530]
  PIN so[531]
    DIRECTION OUTPUT ;
    USE SIGNAL ;
    PORT
      LAYER M3 ;
        RECT  61.308 21.563 61.326 21.6 ;
    END
  END so[531]
  PIN so[532]
    DIRECTION OUTPUT ;
    USE SIGNAL ;
    PORT
      LAYER M3 ;
        RECT  61.38 21.563 61.398 21.6 ;
    END
  END so[532]
  PIN so[533]
    DIRECTION OUTPUT ;
    USE SIGNAL ;
    PORT
      LAYER M3 ;
        RECT  61.452 21.563 61.47 21.6 ;
    END
  END so[533]
  PIN so[534]
    DIRECTION OUTPUT ;
    USE SIGNAL ;
    PORT
      LAYER M3 ;
        RECT  61.524 21.563 61.542 21.6 ;
    END
  END so[534]
  PIN so[535]
    DIRECTION OUTPUT ;
    USE SIGNAL ;
    PORT
      LAYER M3 ;
        RECT  61.596 21.563 61.614 21.6 ;
    END
  END so[535]
  PIN so[536]
    DIRECTION OUTPUT ;
    USE SIGNAL ;
    PORT
      LAYER M3 ;
        RECT  61.668 21.563 61.686 21.6 ;
    END
  END so[536]
  PIN so[537]
    DIRECTION OUTPUT ;
    USE SIGNAL ;
    PORT
      LAYER M3 ;
        RECT  61.74 21.563 61.758 21.6 ;
    END
  END so[537]
  PIN so[538]
    DIRECTION OUTPUT ;
    USE SIGNAL ;
    PORT
      LAYER M3 ;
        RECT  61.812 21.563 61.83 21.6 ;
    END
  END so[538]
  PIN so[539]
    DIRECTION OUTPUT ;
    USE SIGNAL ;
    PORT
      LAYER M3 ;
        RECT  61.884 21.563 61.902 21.6 ;
    END
  END so[539]
  PIN so[53]
    DIRECTION OUTPUT ;
    USE SIGNAL ;
    PORT
      LAYER M3 ;
        RECT  25.164 21.563 25.182 21.6 ;
    END
  END so[53]
  PIN so[540]
    DIRECTION OUTPUT ;
    USE SIGNAL ;
    PORT
      LAYER M3 ;
        RECT  61.956 21.563 61.974 21.6 ;
    END
  END so[540]
  PIN so[541]
    DIRECTION OUTPUT ;
    USE SIGNAL ;
    PORT
      LAYER M3 ;
        RECT  62.028 21.563 62.046 21.6 ;
    END
  END so[541]
  PIN so[542]
    DIRECTION OUTPUT ;
    USE SIGNAL ;
    PORT
      LAYER M3 ;
        RECT  62.1 21.563 62.118 21.6 ;
    END
  END so[542]
  PIN so[543]
    DIRECTION OUTPUT ;
    USE SIGNAL ;
    PORT
      LAYER M3 ;
        RECT  62.172 21.563 62.19 21.6 ;
    END
  END so[543]
  PIN so[544]
    DIRECTION OUTPUT ;
    USE SIGNAL ;
    PORT
      LAYER M3 ;
        RECT  76.644 21.563 76.662 21.6 ;
    END
  END so[544]
  PIN so[545]
    DIRECTION OUTPUT ;
    USE SIGNAL ;
    PORT
      LAYER M3 ;
        RECT  76.716 21.563 76.734 21.6 ;
    END
  END so[545]
  PIN so[546]
    DIRECTION OUTPUT ;
    USE SIGNAL ;
    PORT
      LAYER M3 ;
        RECT  76.788 21.563 76.806 21.6 ;
    END
  END so[546]
  PIN so[547]
    DIRECTION OUTPUT ;
    USE SIGNAL ;
    PORT
      LAYER M3 ;
        RECT  76.86 21.563 76.878 21.6 ;
    END
  END so[547]
  PIN so[548]
    DIRECTION OUTPUT ;
    USE SIGNAL ;
    PORT
      LAYER M3 ;
        RECT  76.932 21.563 76.95 21.6 ;
    END
  END so[548]
  PIN so[549]
    DIRECTION OUTPUT ;
    USE SIGNAL ;
    PORT
      LAYER M3 ;
        RECT  77.004 21.563 77.022 21.6 ;
    END
  END so[549]
  PIN so[54]
    DIRECTION OUTPUT ;
    USE SIGNAL ;
    PORT
      LAYER M3 ;
        RECT  25.236 21.563 25.254 21.6 ;
    END
  END so[54]
  PIN so[550]
    DIRECTION OUTPUT ;
    USE SIGNAL ;
    PORT
      LAYER M3 ;
        RECT  77.076 21.563 77.094 21.6 ;
    END
  END so[550]
  PIN so[551]
    DIRECTION OUTPUT ;
    USE SIGNAL ;
    PORT
      LAYER M3 ;
        RECT  77.148 21.563 77.166 21.6 ;
    END
  END so[551]
  PIN so[552]
    DIRECTION OUTPUT ;
    USE SIGNAL ;
    PORT
      LAYER M3 ;
        RECT  77.22 21.563 77.238 21.6 ;
    END
  END so[552]
  PIN so[553]
    DIRECTION OUTPUT ;
    USE SIGNAL ;
    PORT
      LAYER M3 ;
        RECT  77.292 21.563 77.31 21.6 ;
    END
  END so[553]
  PIN so[554]
    DIRECTION OUTPUT ;
    USE SIGNAL ;
    PORT
      LAYER M3 ;
        RECT  77.364 21.563 77.382 21.6 ;
    END
  END so[554]
  PIN so[555]
    DIRECTION OUTPUT ;
    USE SIGNAL ;
    PORT
      LAYER M3 ;
        RECT  77.436 21.563 77.454 21.6 ;
    END
  END so[555]
  PIN so[556]
    DIRECTION OUTPUT ;
    USE SIGNAL ;
    PORT
      LAYER M3 ;
        RECT  77.508 21.563 77.526 21.6 ;
    END
  END so[556]
  PIN so[557]
    DIRECTION OUTPUT ;
    USE SIGNAL ;
    PORT
      LAYER M3 ;
        RECT  77.58 21.563 77.598 21.6 ;
    END
  END so[557]
  PIN so[558]
    DIRECTION OUTPUT ;
    USE SIGNAL ;
    PORT
      LAYER M3 ;
        RECT  77.652 21.563 77.67 21.6 ;
    END
  END so[558]
  PIN so[559]
    DIRECTION OUTPUT ;
    USE SIGNAL ;
    PORT
      LAYER M3 ;
        RECT  77.724 21.563 77.742 21.6 ;
    END
  END so[559]
  PIN so[55]
    DIRECTION OUTPUT ;
    USE SIGNAL ;
    PORT
      LAYER M3 ;
        RECT  25.308 21.563 25.326 21.6 ;
    END
  END so[55]
  PIN so[560]
    DIRECTION OUTPUT ;
    USE SIGNAL ;
    PORT
      LAYER M3 ;
        RECT  77.796 21.563 77.814 21.6 ;
    END
  END so[560]
  PIN so[561]
    DIRECTION OUTPUT ;
    USE SIGNAL ;
    PORT
      LAYER M3 ;
        RECT  77.868 21.563 77.886 21.6 ;
    END
  END so[561]
  PIN so[562]
    DIRECTION OUTPUT ;
    USE SIGNAL ;
    PORT
      LAYER M3 ;
        RECT  77.94 21.563 77.958 21.6 ;
    END
  END so[562]
  PIN so[563]
    DIRECTION OUTPUT ;
    USE SIGNAL ;
    PORT
      LAYER M3 ;
        RECT  78.012 21.563 78.03 21.6 ;
    END
  END so[563]
  PIN so[564]
    DIRECTION OUTPUT ;
    USE SIGNAL ;
    PORT
      LAYER M3 ;
        RECT  78.084 21.563 78.102 21.6 ;
    END
  END so[564]
  PIN so[565]
    DIRECTION OUTPUT ;
    USE SIGNAL ;
    PORT
      LAYER M3 ;
        RECT  78.156 21.563 78.174 21.6 ;
    END
  END so[565]
  PIN so[566]
    DIRECTION OUTPUT ;
    USE SIGNAL ;
    PORT
      LAYER M3 ;
        RECT  78.228 21.563 78.246 21.6 ;
    END
  END so[566]
  PIN so[567]
    DIRECTION OUTPUT ;
    USE SIGNAL ;
    PORT
      LAYER M3 ;
        RECT  78.3 21.563 78.318 21.6 ;
    END
  END so[567]
  PIN so[568]
    DIRECTION OUTPUT ;
    USE SIGNAL ;
    PORT
      LAYER M3 ;
        RECT  78.372 21.563 78.39 21.6 ;
    END
  END so[568]
  PIN so[569]
    DIRECTION OUTPUT ;
    USE SIGNAL ;
    PORT
      LAYER M3 ;
        RECT  78.444 21.563 78.462 21.6 ;
    END
  END so[569]
  PIN so[56]
    DIRECTION OUTPUT ;
    USE SIGNAL ;
    PORT
      LAYER M3 ;
        RECT  25.38 21.563 25.398 21.6 ;
    END
  END so[56]
  PIN so[570]
    DIRECTION OUTPUT ;
    USE SIGNAL ;
    PORT
      LAYER M3 ;
        RECT  78.516 21.563 78.534 21.6 ;
    END
  END so[570]
  PIN so[571]
    DIRECTION OUTPUT ;
    USE SIGNAL ;
    PORT
      LAYER M3 ;
        RECT  78.588 21.563 78.606 21.6 ;
    END
  END so[571]
  PIN so[572]
    DIRECTION OUTPUT ;
    USE SIGNAL ;
    PORT
      LAYER M3 ;
        RECT  78.66 21.563 78.678 21.6 ;
    END
  END so[572]
  PIN so[573]
    DIRECTION OUTPUT ;
    USE SIGNAL ;
    PORT
      LAYER M3 ;
        RECT  78.732 21.563 78.75 21.6 ;
    END
  END so[573]
  PIN so[574]
    DIRECTION OUTPUT ;
    USE SIGNAL ;
    PORT
      LAYER M3 ;
        RECT  78.804 21.563 78.822 21.6 ;
    END
  END so[574]
  PIN so[575]
    DIRECTION OUTPUT ;
    USE SIGNAL ;
    PORT
      LAYER M3 ;
        RECT  78.876 21.563 78.894 21.6 ;
    END
  END so[575]
  PIN so[576]
    DIRECTION OUTPUT ;
    USE SIGNAL ;
    PORT
      LAYER M5 ;
        RECT  73.392 21.516 73.416 21.6 ;
    END
  END so[576]
  PIN so[577]
    DIRECTION OUTPUT ;
    USE SIGNAL ;
    PORT
      LAYER M5 ;
        RECT  73.488 21.516 73.512 21.6 ;
    END
  END so[577]
  PIN so[578]
    DIRECTION OUTPUT ;
    USE SIGNAL ;
    PORT
      LAYER M5 ;
        RECT  73.584 21.516 73.608 21.6 ;
    END
  END so[578]
  PIN so[579]
    DIRECTION OUTPUT ;
    USE SIGNAL ;
    PORT
      LAYER M5 ;
        RECT  73.68 21.516 73.704 21.6 ;
    END
  END so[579]
  PIN so[57]
    DIRECTION OUTPUT ;
    USE SIGNAL ;
    PORT
      LAYER M3 ;
        RECT  25.452 21.563 25.47 21.6 ;
    END
  END so[57]
  PIN so[580]
    DIRECTION OUTPUT ;
    USE SIGNAL ;
    PORT
      LAYER M5 ;
        RECT  73.776 21.516 73.8 21.6 ;
    END
  END so[580]
  PIN so[581]
    DIRECTION OUTPUT ;
    USE SIGNAL ;
    PORT
      LAYER M5 ;
        RECT  73.872 21.516 73.896 21.6 ;
    END
  END so[581]
  PIN so[582]
    DIRECTION OUTPUT ;
    USE SIGNAL ;
    PORT
      LAYER M5 ;
        RECT  73.968 21.516 73.992 21.6 ;
    END
  END so[582]
  PIN so[583]
    DIRECTION OUTPUT ;
    USE SIGNAL ;
    PORT
      LAYER M5 ;
        RECT  74.064 21.516 74.088 21.6 ;
    END
  END so[583]
  PIN so[584]
    DIRECTION OUTPUT ;
    USE SIGNAL ;
    PORT
      LAYER M5 ;
        RECT  74.16 21.516 74.184 21.6 ;
    END
  END so[584]
  PIN so[585]
    DIRECTION OUTPUT ;
    USE SIGNAL ;
    PORT
      LAYER M5 ;
        RECT  74.256 21.516 74.28 21.6 ;
    END
  END so[585]
  PIN so[586]
    DIRECTION OUTPUT ;
    USE SIGNAL ;
    PORT
      LAYER M5 ;
        RECT  74.352 21.516 74.376 21.6 ;
    END
  END so[586]
  PIN so[587]
    DIRECTION OUTPUT ;
    USE SIGNAL ;
    PORT
      LAYER M5 ;
        RECT  74.448 21.516 74.472 21.6 ;
    END
  END so[587]
  PIN so[588]
    DIRECTION OUTPUT ;
    USE SIGNAL ;
    PORT
      LAYER M5 ;
        RECT  74.544 21.516 74.568 21.6 ;
    END
  END so[588]
  PIN so[589]
    DIRECTION OUTPUT ;
    USE SIGNAL ;
    PORT
      LAYER M5 ;
        RECT  74.64 21.516 74.664 21.6 ;
    END
  END so[589]
  PIN so[58]
    DIRECTION OUTPUT ;
    USE SIGNAL ;
    PORT
      LAYER M3 ;
        RECT  25.524 21.563 25.542 21.6 ;
    END
  END so[58]
  PIN so[590]
    DIRECTION OUTPUT ;
    USE SIGNAL ;
    PORT
      LAYER M5 ;
        RECT  74.736 21.516 74.76 21.6 ;
    END
  END so[590]
  PIN so[591]
    DIRECTION OUTPUT ;
    USE SIGNAL ;
    PORT
      LAYER M5 ;
        RECT  74.832 21.516 74.856 21.6 ;
    END
  END so[591]
  PIN so[592]
    DIRECTION OUTPUT ;
    USE SIGNAL ;
    PORT
      LAYER M5 ;
        RECT  74.928 21.516 74.952 21.6 ;
    END
  END so[592]
  PIN so[593]
    DIRECTION OUTPUT ;
    USE SIGNAL ;
    PORT
      LAYER M5 ;
        RECT  75.024 21.516 75.048 21.6 ;
    END
  END so[593]
  PIN so[594]
    DIRECTION OUTPUT ;
    USE SIGNAL ;
    PORT
      LAYER M5 ;
        RECT  75.12 21.516 75.144 21.6 ;
    END
  END so[594]
  PIN so[595]
    DIRECTION OUTPUT ;
    USE SIGNAL ;
    PORT
      LAYER M5 ;
        RECT  75.216 21.516 75.24 21.6 ;
    END
  END so[595]
  PIN so[596]
    DIRECTION OUTPUT ;
    USE SIGNAL ;
    PORT
      LAYER M5 ;
        RECT  75.312 21.516 75.336 21.6 ;
    END
  END so[596]
  PIN so[597]
    DIRECTION OUTPUT ;
    USE SIGNAL ;
    PORT
      LAYER M5 ;
        RECT  75.408 21.516 75.432 21.6 ;
    END
  END so[597]
  PIN so[598]
    DIRECTION OUTPUT ;
    USE SIGNAL ;
    PORT
      LAYER M5 ;
        RECT  75.504 21.516 75.528 21.6 ;
    END
  END so[598]
  PIN so[599]
    DIRECTION OUTPUT ;
    USE SIGNAL ;
    PORT
      LAYER M5 ;
        RECT  75.6 21.516 75.624 21.6 ;
    END
  END so[599]
  PIN so[59]
    DIRECTION OUTPUT ;
    USE SIGNAL ;
    PORT
      LAYER M3 ;
        RECT  25.596 21.563 25.614 21.6 ;
    END
  END so[59]
  PIN so[5]
    DIRECTION OUTPUT ;
    USE SIGNAL ;
    PORT
      LAYER M3 ;
        RECT  5.004 21.563 5.022 21.6 ;
    END
  END so[5]
  PIN so[600]
    DIRECTION OUTPUT ;
    USE SIGNAL ;
    PORT
      LAYER M5 ;
        RECT  75.696 21.516 75.72 21.6 ;
    END
  END so[600]
  PIN so[601]
    DIRECTION OUTPUT ;
    USE SIGNAL ;
    PORT
      LAYER M5 ;
        RECT  75.792 21.516 75.816 21.6 ;
    END
  END so[601]
  PIN so[602]
    DIRECTION OUTPUT ;
    USE SIGNAL ;
    PORT
      LAYER M5 ;
        RECT  75.888 21.516 75.912 21.6 ;
    END
  END so[602]
  PIN so[603]
    DIRECTION OUTPUT ;
    USE SIGNAL ;
    PORT
      LAYER M5 ;
        RECT  75.984 21.516 76.008 21.6 ;
    END
  END so[603]
  PIN so[604]
    DIRECTION OUTPUT ;
    USE SIGNAL ;
    PORT
      LAYER M5 ;
        RECT  76.08 21.516 76.104 21.6 ;
    END
  END so[604]
  PIN so[605]
    DIRECTION OUTPUT ;
    USE SIGNAL ;
    PORT
      LAYER M5 ;
        RECT  76.176 21.516 76.2 21.6 ;
    END
  END so[605]
  PIN so[606]
    DIRECTION OUTPUT ;
    USE SIGNAL ;
    PORT
      LAYER M5 ;
        RECT  76.272 21.516 76.296 21.6 ;
    END
  END so[606]
  PIN so[607]
    DIRECTION OUTPUT ;
    USE SIGNAL ;
    PORT
      LAYER M5 ;
        RECT  76.368 21.516 76.392 21.6 ;
    END
  END so[607]
  PIN so[608]
    DIRECTION OUTPUT ;
    USE SIGNAL ;
    PORT
      LAYER M5 ;
        RECT  9.648 21.516 9.672 21.6 ;
    END
  END so[608]
  PIN so[609]
    DIRECTION OUTPUT ;
    USE SIGNAL ;
    PORT
      LAYER M5 ;
        RECT  9.744 21.516 9.768 21.6 ;
    END
  END so[609]
  PIN so[60]
    DIRECTION OUTPUT ;
    USE SIGNAL ;
    PORT
      LAYER M3 ;
        RECT  25.668 21.563 25.686 21.6 ;
    END
  END so[60]
  PIN so[610]
    DIRECTION OUTPUT ;
    USE SIGNAL ;
    PORT
      LAYER M5 ;
        RECT  9.84 21.516 9.864 21.6 ;
    END
  END so[610]
  PIN so[611]
    DIRECTION OUTPUT ;
    USE SIGNAL ;
    PORT
      LAYER M5 ;
        RECT  9.936 21.516 9.96 21.6 ;
    END
  END so[611]
  PIN so[612]
    DIRECTION OUTPUT ;
    USE SIGNAL ;
    PORT
      LAYER M5 ;
        RECT  10.032 21.516 10.056 21.6 ;
    END
  END so[612]
  PIN so[613]
    DIRECTION OUTPUT ;
    USE SIGNAL ;
    PORT
      LAYER M5 ;
        RECT  10.128 21.516 10.152 21.6 ;
    END
  END so[613]
  PIN so[614]
    DIRECTION OUTPUT ;
    USE SIGNAL ;
    PORT
      LAYER M5 ;
        RECT  10.224 21.516 10.248 21.6 ;
    END
  END so[614]
  PIN so[615]
    DIRECTION OUTPUT ;
    USE SIGNAL ;
    PORT
      LAYER M5 ;
        RECT  10.32 21.516 10.344 21.6 ;
    END
  END so[615]
  PIN so[616]
    DIRECTION OUTPUT ;
    USE SIGNAL ;
    PORT
      LAYER M5 ;
        RECT  10.416 21.516 10.44 21.6 ;
    END
  END so[616]
  PIN so[617]
    DIRECTION OUTPUT ;
    USE SIGNAL ;
    PORT
      LAYER M5 ;
        RECT  10.512 21.516 10.536 21.6 ;
    END
  END so[617]
  PIN so[618]
    DIRECTION OUTPUT ;
    USE SIGNAL ;
    PORT
      LAYER M5 ;
        RECT  10.608 21.516 10.632 21.6 ;
    END
  END so[618]
  PIN so[619]
    DIRECTION OUTPUT ;
    USE SIGNAL ;
    PORT
      LAYER M5 ;
        RECT  10.704 21.516 10.728 21.6 ;
    END
  END so[619]
  PIN so[61]
    DIRECTION OUTPUT ;
    USE SIGNAL ;
    PORT
      LAYER M3 ;
        RECT  25.74 21.563 25.758 21.6 ;
    END
  END so[61]
  PIN so[620]
    DIRECTION OUTPUT ;
    USE SIGNAL ;
    PORT
      LAYER M5 ;
        RECT  10.8 21.516 10.824 21.6 ;
    END
  END so[620]
  PIN so[621]
    DIRECTION OUTPUT ;
    USE SIGNAL ;
    PORT
      LAYER M5 ;
        RECT  10.896 21.516 10.92 21.6 ;
    END
  END so[621]
  PIN so[622]
    DIRECTION OUTPUT ;
    USE SIGNAL ;
    PORT
      LAYER M5 ;
        RECT  10.992 21.516 11.016 21.6 ;
    END
  END so[622]
  PIN so[623]
    DIRECTION OUTPUT ;
    USE SIGNAL ;
    PORT
      LAYER M5 ;
        RECT  11.088 21.516 11.112 21.6 ;
    END
  END so[623]
  PIN so[624]
    DIRECTION OUTPUT ;
    USE SIGNAL ;
    PORT
      LAYER M5 ;
        RECT  11.184 21.516 11.208 21.6 ;
    END
  END so[624]
  PIN so[625]
    DIRECTION OUTPUT ;
    USE SIGNAL ;
    PORT
      LAYER M5 ;
        RECT  11.28 21.516 11.304 21.6 ;
    END
  END so[625]
  PIN so[626]
    DIRECTION OUTPUT ;
    USE SIGNAL ;
    PORT
      LAYER M5 ;
        RECT  11.376 21.516 11.4 21.6 ;
    END
  END so[626]
  PIN so[627]
    DIRECTION OUTPUT ;
    USE SIGNAL ;
    PORT
      LAYER M5 ;
        RECT  11.472 21.516 11.496 21.6 ;
    END
  END so[627]
  PIN so[628]
    DIRECTION OUTPUT ;
    USE SIGNAL ;
    PORT
      LAYER M5 ;
        RECT  11.568 21.516 11.592 21.6 ;
    END
  END so[628]
  PIN so[629]
    DIRECTION OUTPUT ;
    USE SIGNAL ;
    PORT
      LAYER M5 ;
        RECT  11.664 21.516 11.688 21.6 ;
    END
  END so[629]
  PIN so[62]
    DIRECTION OUTPUT ;
    USE SIGNAL ;
    PORT
      LAYER M3 ;
        RECT  25.812 21.563 25.83 21.6 ;
    END
  END so[62]
  PIN so[630]
    DIRECTION OUTPUT ;
    USE SIGNAL ;
    PORT
      LAYER M5 ;
        RECT  11.76 21.516 11.784 21.6 ;
    END
  END so[630]
  PIN so[631]
    DIRECTION OUTPUT ;
    USE SIGNAL ;
    PORT
      LAYER M5 ;
        RECT  11.856 21.516 11.88 21.6 ;
    END
  END so[631]
  PIN so[632]
    DIRECTION OUTPUT ;
    USE SIGNAL ;
    PORT
      LAYER M5 ;
        RECT  11.952 21.516 11.976 21.6 ;
    END
  END so[632]
  PIN so[633]
    DIRECTION OUTPUT ;
    USE SIGNAL ;
    PORT
      LAYER M5 ;
        RECT  12.048 21.516 12.072 21.6 ;
    END
  END so[633]
  PIN so[634]
    DIRECTION OUTPUT ;
    USE SIGNAL ;
    PORT
      LAYER M5 ;
        RECT  12.144 21.516 12.168 21.6 ;
    END
  END so[634]
  PIN so[635]
    DIRECTION OUTPUT ;
    USE SIGNAL ;
    PORT
      LAYER M5 ;
        RECT  12.24 21.516 12.264 21.6 ;
    END
  END so[635]
  PIN so[636]
    DIRECTION OUTPUT ;
    USE SIGNAL ;
    PORT
      LAYER M5 ;
        RECT  12.336 21.516 12.36 21.6 ;
    END
  END so[636]
  PIN so[637]
    DIRECTION OUTPUT ;
    USE SIGNAL ;
    PORT
      LAYER M5 ;
        RECT  12.432 21.516 12.456 21.6 ;
    END
  END so[637]
  PIN so[638]
    DIRECTION OUTPUT ;
    USE SIGNAL ;
    PORT
      LAYER M5 ;
        RECT  12.528 21.516 12.552 21.6 ;
    END
  END so[638]
  PIN so[639]
    DIRECTION OUTPUT ;
    USE SIGNAL ;
    PORT
      LAYER M5 ;
        RECT  12.624 21.516 12.648 21.6 ;
    END
  END so[639]
  PIN so[63]
    DIRECTION OUTPUT ;
    USE SIGNAL ;
    PORT
      LAYER M3 ;
        RECT  25.884 21.563 25.902 21.6 ;
    END
  END so[63]
  PIN so[640]
    DIRECTION OUTPUT ;
    USE SIGNAL ;
    PORT
      LAYER M5 ;
        RECT  54.192 21.516 54.216 21.6 ;
    END
  END so[640]
  PIN so[641]
    DIRECTION OUTPUT ;
    USE SIGNAL ;
    PORT
      LAYER M5 ;
        RECT  54.288 21.516 54.312 21.6 ;
    END
  END so[641]
  PIN so[642]
    DIRECTION OUTPUT ;
    USE SIGNAL ;
    PORT
      LAYER M5 ;
        RECT  54.384 21.516 54.408 21.6 ;
    END
  END so[642]
  PIN so[643]
    DIRECTION OUTPUT ;
    USE SIGNAL ;
    PORT
      LAYER M5 ;
        RECT  54.48 21.516 54.504 21.6 ;
    END
  END so[643]
  PIN so[644]
    DIRECTION OUTPUT ;
    USE SIGNAL ;
    PORT
      LAYER M5 ;
        RECT  54.576 21.516 54.6 21.6 ;
    END
  END so[644]
  PIN so[645]
    DIRECTION OUTPUT ;
    USE SIGNAL ;
    PORT
      LAYER M5 ;
        RECT  54.672 21.516 54.696 21.6 ;
    END
  END so[645]
  PIN so[646]
    DIRECTION OUTPUT ;
    USE SIGNAL ;
    PORT
      LAYER M5 ;
        RECT  54.768 21.516 54.792 21.6 ;
    END
  END so[646]
  PIN so[647]
    DIRECTION OUTPUT ;
    USE SIGNAL ;
    PORT
      LAYER M5 ;
        RECT  54.864 21.516 54.888 21.6 ;
    END
  END so[647]
  PIN so[648]
    DIRECTION OUTPUT ;
    USE SIGNAL ;
    PORT
      LAYER M5 ;
        RECT  54.96 21.516 54.984 21.6 ;
    END
  END so[648]
  PIN so[649]
    DIRECTION OUTPUT ;
    USE SIGNAL ;
    PORT
      LAYER M5 ;
        RECT  55.056 21.516 55.08 21.6 ;
    END
  END so[649]
  PIN so[64]
    DIRECTION OUTPUT ;
    USE SIGNAL ;
    PORT
      LAYER M3 ;
        RECT  25.956 21.563 25.974 21.6 ;
    END
  END so[64]
  PIN so[650]
    DIRECTION OUTPUT ;
    USE SIGNAL ;
    PORT
      LAYER M5 ;
        RECT  55.152 21.516 55.176 21.6 ;
    END
  END so[650]
  PIN so[651]
    DIRECTION OUTPUT ;
    USE SIGNAL ;
    PORT
      LAYER M5 ;
        RECT  55.248 21.516 55.272 21.6 ;
    END
  END so[651]
  PIN so[652]
    DIRECTION OUTPUT ;
    USE SIGNAL ;
    PORT
      LAYER M5 ;
        RECT  55.344 21.516 55.368 21.6 ;
    END
  END so[652]
  PIN so[653]
    DIRECTION OUTPUT ;
    USE SIGNAL ;
    PORT
      LAYER M5 ;
        RECT  55.44 21.516 55.464 21.6 ;
    END
  END so[653]
  PIN so[654]
    DIRECTION OUTPUT ;
    USE SIGNAL ;
    PORT
      LAYER M5 ;
        RECT  55.536 21.516 55.56 21.6 ;
    END
  END so[654]
  PIN so[655]
    DIRECTION OUTPUT ;
    USE SIGNAL ;
    PORT
      LAYER M5 ;
        RECT  55.632 21.516 55.656 21.6 ;
    END
  END so[655]
  PIN so[656]
    DIRECTION OUTPUT ;
    USE SIGNAL ;
    PORT
      LAYER M5 ;
        RECT  55.728 21.516 55.752 21.6 ;
    END
  END so[656]
  PIN so[657]
    DIRECTION OUTPUT ;
    USE SIGNAL ;
    PORT
      LAYER M5 ;
        RECT  55.824 21.516 55.848 21.6 ;
    END
  END so[657]
  PIN so[658]
    DIRECTION OUTPUT ;
    USE SIGNAL ;
    PORT
      LAYER M5 ;
        RECT  55.92 21.516 55.944 21.6 ;
    END
  END so[658]
  PIN so[659]
    DIRECTION OUTPUT ;
    USE SIGNAL ;
    PORT
      LAYER M5 ;
        RECT  56.016 21.516 56.04 21.6 ;
    END
  END so[659]
  PIN so[65]
    DIRECTION OUTPUT ;
    USE SIGNAL ;
    PORT
      LAYER M3 ;
        RECT  26.028 21.563 26.046 21.6 ;
    END
  END so[65]
  PIN so[660]
    DIRECTION OUTPUT ;
    USE SIGNAL ;
    PORT
      LAYER M5 ;
        RECT  56.112 21.516 56.136 21.6 ;
    END
  END so[660]
  PIN so[661]
    DIRECTION OUTPUT ;
    USE SIGNAL ;
    PORT
      LAYER M5 ;
        RECT  56.208 21.516 56.232 21.6 ;
    END
  END so[661]
  PIN so[662]
    DIRECTION OUTPUT ;
    USE SIGNAL ;
    PORT
      LAYER M5 ;
        RECT  56.304 21.516 56.328 21.6 ;
    END
  END so[662]
  PIN so[663]
    DIRECTION OUTPUT ;
    USE SIGNAL ;
    PORT
      LAYER M5 ;
        RECT  56.4 21.516 56.424 21.6 ;
    END
  END so[663]
  PIN so[664]
    DIRECTION OUTPUT ;
    USE SIGNAL ;
    PORT
      LAYER M5 ;
        RECT  56.496 21.516 56.52 21.6 ;
    END
  END so[664]
  PIN so[665]
    DIRECTION OUTPUT ;
    USE SIGNAL ;
    PORT
      LAYER M5 ;
        RECT  56.592 21.516 56.616 21.6 ;
    END
  END so[665]
  PIN so[666]
    DIRECTION OUTPUT ;
    USE SIGNAL ;
    PORT
      LAYER M5 ;
        RECT  56.688 21.516 56.712 21.6 ;
    END
  END so[666]
  PIN so[667]
    DIRECTION OUTPUT ;
    USE SIGNAL ;
    PORT
      LAYER M5 ;
        RECT  56.784 21.516 56.808 21.6 ;
    END
  END so[667]
  PIN so[668]
    DIRECTION OUTPUT ;
    USE SIGNAL ;
    PORT
      LAYER M5 ;
        RECT  56.88 21.516 56.904 21.6 ;
    END
  END so[668]
  PIN so[669]
    DIRECTION OUTPUT ;
    USE SIGNAL ;
    PORT
      LAYER M5 ;
        RECT  56.976 21.516 57 21.6 ;
    END
  END so[669]
  PIN so[66]
    DIRECTION OUTPUT ;
    USE SIGNAL ;
    PORT
      LAYER M3 ;
        RECT  26.1 21.563 26.118 21.6 ;
    END
  END so[66]
  PIN so[670]
    DIRECTION OUTPUT ;
    USE SIGNAL ;
    PORT
      LAYER M5 ;
        RECT  57.072 21.516 57.096 21.6 ;
    END
  END so[670]
  PIN so[671]
    DIRECTION OUTPUT ;
    USE SIGNAL ;
    PORT
      LAYER M5 ;
        RECT  57.168 21.516 57.192 21.6 ;
    END
  END so[671]
  PIN so[672]
    DIRECTION OUTPUT ;
    USE SIGNAL ;
    PORT
      LAYER M3 ;
        RECT  6.948 21.563 6.966 21.6 ;
    END
  END so[672]
  PIN so[673]
    DIRECTION OUTPUT ;
    USE SIGNAL ;
    PORT
      LAYER M3 ;
        RECT  7.02 21.563 7.038 21.6 ;
    END
  END so[673]
  PIN so[674]
    DIRECTION OUTPUT ;
    USE SIGNAL ;
    PORT
      LAYER M3 ;
        RECT  7.092 21.563 7.11 21.6 ;
    END
  END so[674]
  PIN so[675]
    DIRECTION OUTPUT ;
    USE SIGNAL ;
    PORT
      LAYER M3 ;
        RECT  7.164 21.563 7.182 21.6 ;
    END
  END so[675]
  PIN so[676]
    DIRECTION OUTPUT ;
    USE SIGNAL ;
    PORT
      LAYER M3 ;
        RECT  7.236 21.563 7.254 21.6 ;
    END
  END so[676]
  PIN so[677]
    DIRECTION OUTPUT ;
    USE SIGNAL ;
    PORT
      LAYER M3 ;
        RECT  7.308 21.563 7.326 21.6 ;
    END
  END so[677]
  PIN so[678]
    DIRECTION OUTPUT ;
    USE SIGNAL ;
    PORT
      LAYER M3 ;
        RECT  7.38 21.563 7.398 21.6 ;
    END
  END so[678]
  PIN so[679]
    DIRECTION OUTPUT ;
    USE SIGNAL ;
    PORT
      LAYER M3 ;
        RECT  7.452 21.563 7.47 21.6 ;
    END
  END so[679]
  PIN so[67]
    DIRECTION OUTPUT ;
    USE SIGNAL ;
    PORT
      LAYER M3 ;
        RECT  26.172 21.563 26.19 21.6 ;
    END
  END so[67]
  PIN so[680]
    DIRECTION OUTPUT ;
    USE SIGNAL ;
    PORT
      LAYER M3 ;
        RECT  7.524 21.563 7.542 21.6 ;
    END
  END so[680]
  PIN so[681]
    DIRECTION OUTPUT ;
    USE SIGNAL ;
    PORT
      LAYER M3 ;
        RECT  7.596 21.563 7.614 21.6 ;
    END
  END so[681]
  PIN so[682]
    DIRECTION OUTPUT ;
    USE SIGNAL ;
    PORT
      LAYER M3 ;
        RECT  7.668 21.563 7.686 21.6 ;
    END
  END so[682]
  PIN so[683]
    DIRECTION OUTPUT ;
    USE SIGNAL ;
    PORT
      LAYER M3 ;
        RECT  7.74 21.563 7.758 21.6 ;
    END
  END so[683]
  PIN so[684]
    DIRECTION OUTPUT ;
    USE SIGNAL ;
    PORT
      LAYER M3 ;
        RECT  7.812 21.563 7.83 21.6 ;
    END
  END so[684]
  PIN so[685]
    DIRECTION OUTPUT ;
    USE SIGNAL ;
    PORT
      LAYER M3 ;
        RECT  7.884 21.563 7.902 21.6 ;
    END
  END so[685]
  PIN so[686]
    DIRECTION OUTPUT ;
    USE SIGNAL ;
    PORT
      LAYER M3 ;
        RECT  7.956 21.563 7.974 21.6 ;
    END
  END so[686]
  PIN so[687]
    DIRECTION OUTPUT ;
    USE SIGNAL ;
    PORT
      LAYER M3 ;
        RECT  8.028 21.563 8.046 21.6 ;
    END
  END so[687]
  PIN so[688]
    DIRECTION OUTPUT ;
    USE SIGNAL ;
    PORT
      LAYER M3 ;
        RECT  8.1 21.563 8.118 21.6 ;
    END
  END so[688]
  PIN so[689]
    DIRECTION OUTPUT ;
    USE SIGNAL ;
    PORT
      LAYER M3 ;
        RECT  8.172 21.563 8.19 21.6 ;
    END
  END so[689]
  PIN so[68]
    DIRECTION OUTPUT ;
    USE SIGNAL ;
    PORT
      LAYER M3 ;
        RECT  26.244 21.563 26.262 21.6 ;
    END
  END so[68]
  PIN so[690]
    DIRECTION OUTPUT ;
    USE SIGNAL ;
    PORT
      LAYER M3 ;
        RECT  8.244 21.563 8.262 21.6 ;
    END
  END so[690]
  PIN so[691]
    DIRECTION OUTPUT ;
    USE SIGNAL ;
    PORT
      LAYER M3 ;
        RECT  8.316 21.563 8.334 21.6 ;
    END
  END so[691]
  PIN so[692]
    DIRECTION OUTPUT ;
    USE SIGNAL ;
    PORT
      LAYER M3 ;
        RECT  8.388 21.563 8.406 21.6 ;
    END
  END so[692]
  PIN so[693]
    DIRECTION OUTPUT ;
    USE SIGNAL ;
    PORT
      LAYER M3 ;
        RECT  8.46 21.563 8.478 21.6 ;
    END
  END so[693]
  PIN so[694]
    DIRECTION OUTPUT ;
    USE SIGNAL ;
    PORT
      LAYER M3 ;
        RECT  8.532 21.563 8.55 21.6 ;
    END
  END so[694]
  PIN so[695]
    DIRECTION OUTPUT ;
    USE SIGNAL ;
    PORT
      LAYER M3 ;
        RECT  8.604 21.563 8.622 21.6 ;
    END
  END so[695]
  PIN so[696]
    DIRECTION OUTPUT ;
    USE SIGNAL ;
    PORT
      LAYER M3 ;
        RECT  8.676 21.563 8.694 21.6 ;
    END
  END so[696]
  PIN so[697]
    DIRECTION OUTPUT ;
    USE SIGNAL ;
    PORT
      LAYER M3 ;
        RECT  8.748 21.563 8.766 21.6 ;
    END
  END so[697]
  PIN so[698]
    DIRECTION OUTPUT ;
    USE SIGNAL ;
    PORT
      LAYER M3 ;
        RECT  8.82 21.563 8.838 21.6 ;
    END
  END so[698]
  PIN so[699]
    DIRECTION OUTPUT ;
    USE SIGNAL ;
    PORT
      LAYER M3 ;
        RECT  8.892 21.563 8.91 21.6 ;
    END
  END so[699]
  PIN so[69]
    DIRECTION OUTPUT ;
    USE SIGNAL ;
    PORT
      LAYER M3 ;
        RECT  26.316 21.563 26.334 21.6 ;
    END
  END so[69]
  PIN so[6]
    DIRECTION OUTPUT ;
    USE SIGNAL ;
    PORT
      LAYER M3 ;
        RECT  5.076 21.563 5.094 21.6 ;
    END
  END so[6]
  PIN so[700]
    DIRECTION OUTPUT ;
    USE SIGNAL ;
    PORT
      LAYER M3 ;
        RECT  8.964 21.563 8.982 21.6 ;
    END
  END so[700]
  PIN so[701]
    DIRECTION OUTPUT ;
    USE SIGNAL ;
    PORT
      LAYER M3 ;
        RECT  9.036 21.563 9.054 21.6 ;
    END
  END so[701]
  PIN so[702]
    DIRECTION OUTPUT ;
    USE SIGNAL ;
    PORT
      LAYER M3 ;
        RECT  9.108 21.563 9.126 21.6 ;
    END
  END so[702]
  PIN so[703]
    DIRECTION OUTPUT ;
    USE SIGNAL ;
    PORT
      LAYER M3 ;
        RECT  9.18 21.563 9.198 21.6 ;
    END
  END so[703]
  PIN so[704]
    DIRECTION OUTPUT ;
    USE SIGNAL ;
    PORT
      LAYER M3 ;
        RECT  62.244 21.563 62.262 21.6 ;
    END
  END so[704]
  PIN so[705]
    DIRECTION OUTPUT ;
    USE SIGNAL ;
    PORT
      LAYER M3 ;
        RECT  62.316 21.563 62.334 21.6 ;
    END
  END so[705]
  PIN so[706]
    DIRECTION OUTPUT ;
    USE SIGNAL ;
    PORT
      LAYER M3 ;
        RECT  62.388 21.563 62.406 21.6 ;
    END
  END so[706]
  PIN so[707]
    DIRECTION OUTPUT ;
    USE SIGNAL ;
    PORT
      LAYER M3 ;
        RECT  62.46 21.563 62.478 21.6 ;
    END
  END so[707]
  PIN so[708]
    DIRECTION OUTPUT ;
    USE SIGNAL ;
    PORT
      LAYER M3 ;
        RECT  62.532 21.563 62.55 21.6 ;
    END
  END so[708]
  PIN so[709]
    DIRECTION OUTPUT ;
    USE SIGNAL ;
    PORT
      LAYER M3 ;
        RECT  62.604 21.563 62.622 21.6 ;
    END
  END so[709]
  PIN so[70]
    DIRECTION OUTPUT ;
    USE SIGNAL ;
    PORT
      LAYER M3 ;
        RECT  26.388 21.563 26.406 21.6 ;
    END
  END so[70]
  PIN so[710]
    DIRECTION OUTPUT ;
    USE SIGNAL ;
    PORT
      LAYER M3 ;
        RECT  62.676 21.563 62.694 21.6 ;
    END
  END so[710]
  PIN so[711]
    DIRECTION OUTPUT ;
    USE SIGNAL ;
    PORT
      LAYER M3 ;
        RECT  62.748 21.563 62.766 21.6 ;
    END
  END so[711]
  PIN so[712]
    DIRECTION OUTPUT ;
    USE SIGNAL ;
    PORT
      LAYER M3 ;
        RECT  62.82 21.563 62.838 21.6 ;
    END
  END so[712]
  PIN so[713]
    DIRECTION OUTPUT ;
    USE SIGNAL ;
    PORT
      LAYER M3 ;
        RECT  62.892 21.563 62.91 21.6 ;
    END
  END so[713]
  PIN so[714]
    DIRECTION OUTPUT ;
    USE SIGNAL ;
    PORT
      LAYER M3 ;
        RECT  62.964 21.563 62.982 21.6 ;
    END
  END so[714]
  PIN so[715]
    DIRECTION OUTPUT ;
    USE SIGNAL ;
    PORT
      LAYER M3 ;
        RECT  63.036 21.563 63.054 21.6 ;
    END
  END so[715]
  PIN so[716]
    DIRECTION OUTPUT ;
    USE SIGNAL ;
    PORT
      LAYER M3 ;
        RECT  63.108 21.563 63.126 21.6 ;
    END
  END so[716]
  PIN so[717]
    DIRECTION OUTPUT ;
    USE SIGNAL ;
    PORT
      LAYER M3 ;
        RECT  63.18 21.563 63.198 21.6 ;
    END
  END so[717]
  PIN so[718]
    DIRECTION OUTPUT ;
    USE SIGNAL ;
    PORT
      LAYER M3 ;
        RECT  63.252 21.563 63.27 21.6 ;
    END
  END so[718]
  PIN so[719]
    DIRECTION OUTPUT ;
    USE SIGNAL ;
    PORT
      LAYER M3 ;
        RECT  63.324 21.563 63.342 21.6 ;
    END
  END so[719]
  PIN so[71]
    DIRECTION OUTPUT ;
    USE SIGNAL ;
    PORT
      LAYER M3 ;
        RECT  26.46 21.563 26.478 21.6 ;
    END
  END so[71]
  PIN so[720]
    DIRECTION OUTPUT ;
    USE SIGNAL ;
    PORT
      LAYER M3 ;
        RECT  63.396 21.563 63.414 21.6 ;
    END
  END so[720]
  PIN so[721]
    DIRECTION OUTPUT ;
    USE SIGNAL ;
    PORT
      LAYER M3 ;
        RECT  63.468 21.563 63.486 21.6 ;
    END
  END so[721]
  PIN so[722]
    DIRECTION OUTPUT ;
    USE SIGNAL ;
    PORT
      LAYER M3 ;
        RECT  63.54 21.563 63.558 21.6 ;
    END
  END so[722]
  PIN so[723]
    DIRECTION OUTPUT ;
    USE SIGNAL ;
    PORT
      LAYER M3 ;
        RECT  63.612 21.563 63.63 21.6 ;
    END
  END so[723]
  PIN so[724]
    DIRECTION OUTPUT ;
    USE SIGNAL ;
    PORT
      LAYER M3 ;
        RECT  63.684 21.563 63.702 21.6 ;
    END
  END so[724]
  PIN so[725]
    DIRECTION OUTPUT ;
    USE SIGNAL ;
    PORT
      LAYER M3 ;
        RECT  63.756 21.563 63.774 21.6 ;
    END
  END so[725]
  PIN so[726]
    DIRECTION OUTPUT ;
    USE SIGNAL ;
    PORT
      LAYER M3 ;
        RECT  63.828 21.563 63.846 21.6 ;
    END
  END so[726]
  PIN so[727]
    DIRECTION OUTPUT ;
    USE SIGNAL ;
    PORT
      LAYER M3 ;
        RECT  63.9 21.563 63.918 21.6 ;
    END
  END so[727]
  PIN so[728]
    DIRECTION OUTPUT ;
    USE SIGNAL ;
    PORT
      LAYER M3 ;
        RECT  63.972 21.563 63.99 21.6 ;
    END
  END so[728]
  PIN so[729]
    DIRECTION OUTPUT ;
    USE SIGNAL ;
    PORT
      LAYER M3 ;
        RECT  64.044 21.563 64.062 21.6 ;
    END
  END so[729]
  PIN so[72]
    DIRECTION OUTPUT ;
    USE SIGNAL ;
    PORT
      LAYER M3 ;
        RECT  26.532 21.563 26.55 21.6 ;
    END
  END so[72]
  PIN so[730]
    DIRECTION OUTPUT ;
    USE SIGNAL ;
    PORT
      LAYER M3 ;
        RECT  64.116 21.563 64.134 21.6 ;
    END
  END so[730]
  PIN so[731]
    DIRECTION OUTPUT ;
    USE SIGNAL ;
    PORT
      LAYER M3 ;
        RECT  64.188 21.563 64.206 21.6 ;
    END
  END so[731]
  PIN so[732]
    DIRECTION OUTPUT ;
    USE SIGNAL ;
    PORT
      LAYER M3 ;
        RECT  64.26 21.563 64.278 21.6 ;
    END
  END so[732]
  PIN so[733]
    DIRECTION OUTPUT ;
    USE SIGNAL ;
    PORT
      LAYER M3 ;
        RECT  64.332 21.563 64.35 21.6 ;
    END
  END so[733]
  PIN so[734]
    DIRECTION OUTPUT ;
    USE SIGNAL ;
    PORT
      LAYER M3 ;
        RECT  64.404 21.563 64.422 21.6 ;
    END
  END so[734]
  PIN so[735]
    DIRECTION OUTPUT ;
    USE SIGNAL ;
    PORT
      LAYER M3 ;
        RECT  64.476 21.563 64.494 21.6 ;
    END
  END so[735]
  PIN so[736]
    DIRECTION OUTPUT ;
    USE SIGNAL ;
    PORT
      LAYER M3 ;
        RECT  28.836 21.563 28.854 21.6 ;
    END
  END so[736]
  PIN so[737]
    DIRECTION OUTPUT ;
    USE SIGNAL ;
    PORT
      LAYER M3 ;
        RECT  28.908 21.563 28.926 21.6 ;
    END
  END so[737]
  PIN so[738]
    DIRECTION OUTPUT ;
    USE SIGNAL ;
    PORT
      LAYER M3 ;
        RECT  28.98 21.563 28.998 21.6 ;
    END
  END so[738]
  PIN so[739]
    DIRECTION OUTPUT ;
    USE SIGNAL ;
    PORT
      LAYER M3 ;
        RECT  29.052 21.563 29.07 21.6 ;
    END
  END so[739]
  PIN so[73]
    DIRECTION OUTPUT ;
    USE SIGNAL ;
    PORT
      LAYER M3 ;
        RECT  26.604 21.563 26.622 21.6 ;
    END
  END so[73]
  PIN so[740]
    DIRECTION OUTPUT ;
    USE SIGNAL ;
    PORT
      LAYER M3 ;
        RECT  29.124 21.563 29.142 21.6 ;
    END
  END so[740]
  PIN so[741]
    DIRECTION OUTPUT ;
    USE SIGNAL ;
    PORT
      LAYER M3 ;
        RECT  29.196 21.563 29.214 21.6 ;
    END
  END so[741]
  PIN so[742]
    DIRECTION OUTPUT ;
    USE SIGNAL ;
    PORT
      LAYER M3 ;
        RECT  29.268 21.563 29.286 21.6 ;
    END
  END so[742]
  PIN so[743]
    DIRECTION OUTPUT ;
    USE SIGNAL ;
    PORT
      LAYER M3 ;
        RECT  29.34 21.563 29.358 21.6 ;
    END
  END so[743]
  PIN so[744]
    DIRECTION OUTPUT ;
    USE SIGNAL ;
    PORT
      LAYER M3 ;
        RECT  29.412 21.563 29.43 21.6 ;
    END
  END so[744]
  PIN so[745]
    DIRECTION OUTPUT ;
    USE SIGNAL ;
    PORT
      LAYER M3 ;
        RECT  29.484 21.563 29.502 21.6 ;
    END
  END so[745]
  PIN so[746]
    DIRECTION OUTPUT ;
    USE SIGNAL ;
    PORT
      LAYER M3 ;
        RECT  29.556 21.563 29.574 21.6 ;
    END
  END so[746]
  PIN so[747]
    DIRECTION OUTPUT ;
    USE SIGNAL ;
    PORT
      LAYER M3 ;
        RECT  29.628 21.563 29.646 21.6 ;
    END
  END so[747]
  PIN so[748]
    DIRECTION OUTPUT ;
    USE SIGNAL ;
    PORT
      LAYER M3 ;
        RECT  29.7 21.563 29.718 21.6 ;
    END
  END so[748]
  PIN so[749]
    DIRECTION OUTPUT ;
    USE SIGNAL ;
    PORT
      LAYER M3 ;
        RECT  29.772 21.563 29.79 21.6 ;
    END
  END so[749]
  PIN so[74]
    DIRECTION OUTPUT ;
    USE SIGNAL ;
    PORT
      LAYER M3 ;
        RECT  26.676 21.563 26.694 21.6 ;
    END
  END so[74]
  PIN so[750]
    DIRECTION OUTPUT ;
    USE SIGNAL ;
    PORT
      LAYER M3 ;
        RECT  29.844 21.563 29.862 21.6 ;
    END
  END so[750]
  PIN so[751]
    DIRECTION OUTPUT ;
    USE SIGNAL ;
    PORT
      LAYER M3 ;
        RECT  29.916 21.563 29.934 21.6 ;
    END
  END so[751]
  PIN so[752]
    DIRECTION OUTPUT ;
    USE SIGNAL ;
    PORT
      LAYER M3 ;
        RECT  29.988 21.563 30.006 21.6 ;
    END
  END so[752]
  PIN so[753]
    DIRECTION OUTPUT ;
    USE SIGNAL ;
    PORT
      LAYER M3 ;
        RECT  30.06 21.563 30.078 21.6 ;
    END
  END so[753]
  PIN so[754]
    DIRECTION OUTPUT ;
    USE SIGNAL ;
    PORT
      LAYER M3 ;
        RECT  30.132 21.563 30.15 21.6 ;
    END
  END so[754]
  PIN so[755]
    DIRECTION OUTPUT ;
    USE SIGNAL ;
    PORT
      LAYER M3 ;
        RECT  30.204 21.563 30.222 21.6 ;
    END
  END so[755]
  PIN so[756]
    DIRECTION OUTPUT ;
    USE SIGNAL ;
    PORT
      LAYER M3 ;
        RECT  30.276 21.563 30.294 21.6 ;
    END
  END so[756]
  PIN so[757]
    DIRECTION OUTPUT ;
    USE SIGNAL ;
    PORT
      LAYER M3 ;
        RECT  30.348 21.563 30.366 21.6 ;
    END
  END so[757]
  PIN so[758]
    DIRECTION OUTPUT ;
    USE SIGNAL ;
    PORT
      LAYER M3 ;
        RECT  30.42 21.563 30.438 21.6 ;
    END
  END so[758]
  PIN so[759]
    DIRECTION OUTPUT ;
    USE SIGNAL ;
    PORT
      LAYER M3 ;
        RECT  30.492 21.563 30.51 21.6 ;
    END
  END so[759]
  PIN so[75]
    DIRECTION OUTPUT ;
    USE SIGNAL ;
    PORT
      LAYER M3 ;
        RECT  26.748 21.563 26.766 21.6 ;
    END
  END so[75]
  PIN so[760]
    DIRECTION OUTPUT ;
    USE SIGNAL ;
    PORT
      LAYER M3 ;
        RECT  30.564 21.563 30.582 21.6 ;
    END
  END so[760]
  PIN so[761]
    DIRECTION OUTPUT ;
    USE SIGNAL ;
    PORT
      LAYER M3 ;
        RECT  30.636 21.563 30.654 21.6 ;
    END
  END so[761]
  PIN so[762]
    DIRECTION OUTPUT ;
    USE SIGNAL ;
    PORT
      LAYER M3 ;
        RECT  30.708 21.563 30.726 21.6 ;
    END
  END so[762]
  PIN so[763]
    DIRECTION OUTPUT ;
    USE SIGNAL ;
    PORT
      LAYER M3 ;
        RECT  30.78 21.563 30.798 21.6 ;
    END
  END so[763]
  PIN so[764]
    DIRECTION OUTPUT ;
    USE SIGNAL ;
    PORT
      LAYER M3 ;
        RECT  30.852 21.563 30.87 21.6 ;
    END
  END so[764]
  PIN so[765]
    DIRECTION OUTPUT ;
    USE SIGNAL ;
    PORT
      LAYER M3 ;
        RECT  30.924 21.563 30.942 21.6 ;
    END
  END so[765]
  PIN so[766]
    DIRECTION OUTPUT ;
    USE SIGNAL ;
    PORT
      LAYER M3 ;
        RECT  30.996 21.563 31.014 21.6 ;
    END
  END so[766]
  PIN so[767]
    DIRECTION OUTPUT ;
    USE SIGNAL ;
    PORT
      LAYER M3 ;
        RECT  31.068 21.563 31.086 21.6 ;
    END
  END so[767]
  PIN so[768]
    DIRECTION OUTPUT ;
    USE SIGNAL ;
    PORT
      LAYER M5 ;
        RECT  51.12 21.516 51.144 21.6 ;
    END
  END so[768]
  PIN so[769]
    DIRECTION OUTPUT ;
    USE SIGNAL ;
    PORT
      LAYER M5 ;
        RECT  51.216 21.516 51.24 21.6 ;
    END
  END so[769]
  PIN so[76]
    DIRECTION OUTPUT ;
    USE SIGNAL ;
    PORT
      LAYER M3 ;
        RECT  26.82 21.563 26.838 21.6 ;
    END
  END so[76]
  PIN so[770]
    DIRECTION OUTPUT ;
    USE SIGNAL ;
    PORT
      LAYER M5 ;
        RECT  51.312 21.516 51.336 21.6 ;
    END
  END so[770]
  PIN so[771]
    DIRECTION OUTPUT ;
    USE SIGNAL ;
    PORT
      LAYER M5 ;
        RECT  51.408 21.516 51.432 21.6 ;
    END
  END so[771]
  PIN so[772]
    DIRECTION OUTPUT ;
    USE SIGNAL ;
    PORT
      LAYER M5 ;
        RECT  51.504 21.516 51.528 21.6 ;
    END
  END so[772]
  PIN so[773]
    DIRECTION OUTPUT ;
    USE SIGNAL ;
    PORT
      LAYER M5 ;
        RECT  51.6 21.516 51.624 21.6 ;
    END
  END so[773]
  PIN so[774]
    DIRECTION OUTPUT ;
    USE SIGNAL ;
    PORT
      LAYER M5 ;
        RECT  51.696 21.516 51.72 21.6 ;
    END
  END so[774]
  PIN so[775]
    DIRECTION OUTPUT ;
    USE SIGNAL ;
    PORT
      LAYER M5 ;
        RECT  51.792 21.516 51.816 21.6 ;
    END
  END so[775]
  PIN so[776]
    DIRECTION OUTPUT ;
    USE SIGNAL ;
    PORT
      LAYER M5 ;
        RECT  51.888 21.516 51.912 21.6 ;
    END
  END so[776]
  PIN so[777]
    DIRECTION OUTPUT ;
    USE SIGNAL ;
    PORT
      LAYER M5 ;
        RECT  51.984 21.516 52.008 21.6 ;
    END
  END so[777]
  PIN so[778]
    DIRECTION OUTPUT ;
    USE SIGNAL ;
    PORT
      LAYER M5 ;
        RECT  52.08 21.516 52.104 21.6 ;
    END
  END so[778]
  PIN so[779]
    DIRECTION OUTPUT ;
    USE SIGNAL ;
    PORT
      LAYER M5 ;
        RECT  52.176 21.516 52.2 21.6 ;
    END
  END so[779]
  PIN so[77]
    DIRECTION OUTPUT ;
    USE SIGNAL ;
    PORT
      LAYER M3 ;
        RECT  26.892 21.563 26.91 21.6 ;
    END
  END so[77]
  PIN so[780]
    DIRECTION OUTPUT ;
    USE SIGNAL ;
    PORT
      LAYER M5 ;
        RECT  52.272 21.516 52.296 21.6 ;
    END
  END so[780]
  PIN so[781]
    DIRECTION OUTPUT ;
    USE SIGNAL ;
    PORT
      LAYER M5 ;
        RECT  52.368 21.516 52.392 21.6 ;
    END
  END so[781]
  PIN so[782]
    DIRECTION OUTPUT ;
    USE SIGNAL ;
    PORT
      LAYER M5 ;
        RECT  52.464 21.516 52.488 21.6 ;
    END
  END so[782]
  PIN so[783]
    DIRECTION OUTPUT ;
    USE SIGNAL ;
    PORT
      LAYER M5 ;
        RECT  52.56 21.516 52.584 21.6 ;
    END
  END so[783]
  PIN so[784]
    DIRECTION OUTPUT ;
    USE SIGNAL ;
    PORT
      LAYER M5 ;
        RECT  52.656 21.516 52.68 21.6 ;
    END
  END so[784]
  PIN so[785]
    DIRECTION OUTPUT ;
    USE SIGNAL ;
    PORT
      LAYER M5 ;
        RECT  52.752 21.516 52.776 21.6 ;
    END
  END so[785]
  PIN so[786]
    DIRECTION OUTPUT ;
    USE SIGNAL ;
    PORT
      LAYER M5 ;
        RECT  52.848 21.516 52.872 21.6 ;
    END
  END so[786]
  PIN so[787]
    DIRECTION OUTPUT ;
    USE SIGNAL ;
    PORT
      LAYER M5 ;
        RECT  52.944 21.516 52.968 21.6 ;
    END
  END so[787]
  PIN so[788]
    DIRECTION OUTPUT ;
    USE SIGNAL ;
    PORT
      LAYER M5 ;
        RECT  53.04 21.516 53.064 21.6 ;
    END
  END so[788]
  PIN so[789]
    DIRECTION OUTPUT ;
    USE SIGNAL ;
    PORT
      LAYER M5 ;
        RECT  53.136 21.516 53.16 21.6 ;
    END
  END so[789]
  PIN so[78]
    DIRECTION OUTPUT ;
    USE SIGNAL ;
    PORT
      LAYER M3 ;
        RECT  26.964 21.563 26.982 21.6 ;
    END
  END so[78]
  PIN so[790]
    DIRECTION OUTPUT ;
    USE SIGNAL ;
    PORT
      LAYER M5 ;
        RECT  53.232 21.516 53.256 21.6 ;
    END
  END so[790]
  PIN so[791]
    DIRECTION OUTPUT ;
    USE SIGNAL ;
    PORT
      LAYER M5 ;
        RECT  53.328 21.516 53.352 21.6 ;
    END
  END so[791]
  PIN so[792]
    DIRECTION OUTPUT ;
    USE SIGNAL ;
    PORT
      LAYER M5 ;
        RECT  53.424 21.516 53.448 21.6 ;
    END
  END so[792]
  PIN so[793]
    DIRECTION OUTPUT ;
    USE SIGNAL ;
    PORT
      LAYER M5 ;
        RECT  53.52 21.516 53.544 21.6 ;
    END
  END so[793]
  PIN so[794]
    DIRECTION OUTPUT ;
    USE SIGNAL ;
    PORT
      LAYER M5 ;
        RECT  53.616 21.516 53.64 21.6 ;
    END
  END so[794]
  PIN so[795]
    DIRECTION OUTPUT ;
    USE SIGNAL ;
    PORT
      LAYER M5 ;
        RECT  53.712 21.516 53.736 21.6 ;
    END
  END so[795]
  PIN so[796]
    DIRECTION OUTPUT ;
    USE SIGNAL ;
    PORT
      LAYER M5 ;
        RECT  53.808 21.516 53.832 21.6 ;
    END
  END so[796]
  PIN so[797]
    DIRECTION OUTPUT ;
    USE SIGNAL ;
    PORT
      LAYER M5 ;
        RECT  53.904 21.516 53.928 21.6 ;
    END
  END so[797]
  PIN so[798]
    DIRECTION OUTPUT ;
    USE SIGNAL ;
    PORT
      LAYER M5 ;
        RECT  54 21.516 54.024 21.6 ;
    END
  END so[798]
  PIN so[799]
    DIRECTION OUTPUT ;
    USE SIGNAL ;
    PORT
      LAYER M5 ;
        RECT  54.096 21.516 54.12 21.6 ;
    END
  END so[799]
  PIN so[79]
    DIRECTION OUTPUT ;
    USE SIGNAL ;
    PORT
      LAYER M3 ;
        RECT  27.036 21.563 27.054 21.6 ;
    END
  END so[79]
  PIN so[7]
    DIRECTION OUTPUT ;
    USE SIGNAL ;
    PORT
      LAYER M3 ;
        RECT  5.148 21.563 5.166 21.6 ;
    END
  END so[7]
  PIN so[800]
    DIRECTION OUTPUT ;
    USE SIGNAL ;
    PORT
      LAYER M3 ;
        RECT  21.348 21.563 21.366 21.6 ;
    END
  END so[800]
  PIN so[801]
    DIRECTION OUTPUT ;
    USE SIGNAL ;
    PORT
      LAYER M3 ;
        RECT  21.42 21.563 21.438 21.6 ;
    END
  END so[801]
  PIN so[802]
    DIRECTION OUTPUT ;
    USE SIGNAL ;
    PORT
      LAYER M3 ;
        RECT  21.492 21.563 21.51 21.6 ;
    END
  END so[802]
  PIN so[803]
    DIRECTION OUTPUT ;
    USE SIGNAL ;
    PORT
      LAYER M3 ;
        RECT  21.564 21.563 21.582 21.6 ;
    END
  END so[803]
  PIN so[804]
    DIRECTION OUTPUT ;
    USE SIGNAL ;
    PORT
      LAYER M3 ;
        RECT  21.636 21.563 21.654 21.6 ;
    END
  END so[804]
  PIN so[805]
    DIRECTION OUTPUT ;
    USE SIGNAL ;
    PORT
      LAYER M3 ;
        RECT  21.708 21.563 21.726 21.6 ;
    END
  END so[805]
  PIN so[806]
    DIRECTION OUTPUT ;
    USE SIGNAL ;
    PORT
      LAYER M3 ;
        RECT  21.78 21.563 21.798 21.6 ;
    END
  END so[806]
  PIN so[807]
    DIRECTION OUTPUT ;
    USE SIGNAL ;
    PORT
      LAYER M3 ;
        RECT  21.852 21.563 21.87 21.6 ;
    END
  END so[807]
  PIN so[808]
    DIRECTION OUTPUT ;
    USE SIGNAL ;
    PORT
      LAYER M3 ;
        RECT  21.924 21.563 21.942 21.6 ;
    END
  END so[808]
  PIN so[809]
    DIRECTION OUTPUT ;
    USE SIGNAL ;
    PORT
      LAYER M3 ;
        RECT  21.996 21.563 22.014 21.6 ;
    END
  END so[809]
  PIN so[80]
    DIRECTION OUTPUT ;
    USE SIGNAL ;
    PORT
      LAYER M3 ;
        RECT  27.108 21.563 27.126 21.6 ;
    END
  END so[80]
  PIN so[810]
    DIRECTION OUTPUT ;
    USE SIGNAL ;
    PORT
      LAYER M3 ;
        RECT  22.068 21.563 22.086 21.6 ;
    END
  END so[810]
  PIN so[811]
    DIRECTION OUTPUT ;
    USE SIGNAL ;
    PORT
      LAYER M3 ;
        RECT  22.14 21.563 22.158 21.6 ;
    END
  END so[811]
  PIN so[812]
    DIRECTION OUTPUT ;
    USE SIGNAL ;
    PORT
      LAYER M3 ;
        RECT  22.212 21.563 22.23 21.6 ;
    END
  END so[812]
  PIN so[813]
    DIRECTION OUTPUT ;
    USE SIGNAL ;
    PORT
      LAYER M3 ;
        RECT  22.284 21.563 22.302 21.6 ;
    END
  END so[813]
  PIN so[814]
    DIRECTION OUTPUT ;
    USE SIGNAL ;
    PORT
      LAYER M3 ;
        RECT  22.356 21.563 22.374 21.6 ;
    END
  END so[814]
  PIN so[815]
    DIRECTION OUTPUT ;
    USE SIGNAL ;
    PORT
      LAYER M3 ;
        RECT  22.428 21.563 22.446 21.6 ;
    END
  END so[815]
  PIN so[816]
    DIRECTION OUTPUT ;
    USE SIGNAL ;
    PORT
      LAYER M3 ;
        RECT  22.5 21.563 22.518 21.6 ;
    END
  END so[816]
  PIN so[817]
    DIRECTION OUTPUT ;
    USE SIGNAL ;
    PORT
      LAYER M3 ;
        RECT  22.572 21.563 22.59 21.6 ;
    END
  END so[817]
  PIN so[818]
    DIRECTION OUTPUT ;
    USE SIGNAL ;
    PORT
      LAYER M3 ;
        RECT  22.644 21.563 22.662 21.6 ;
    END
  END so[818]
  PIN so[819]
    DIRECTION OUTPUT ;
    USE SIGNAL ;
    PORT
      LAYER M3 ;
        RECT  22.716 21.563 22.734 21.6 ;
    END
  END so[819]
  PIN so[81]
    DIRECTION OUTPUT ;
    USE SIGNAL ;
    PORT
      LAYER M3 ;
        RECT  27.18 21.563 27.198 21.6 ;
    END
  END so[81]
  PIN so[820]
    DIRECTION OUTPUT ;
    USE SIGNAL ;
    PORT
      LAYER M3 ;
        RECT  22.788 21.563 22.806 21.6 ;
    END
  END so[820]
  PIN so[821]
    DIRECTION OUTPUT ;
    USE SIGNAL ;
    PORT
      LAYER M3 ;
        RECT  22.86 21.563 22.878 21.6 ;
    END
  END so[821]
  PIN so[822]
    DIRECTION OUTPUT ;
    USE SIGNAL ;
    PORT
      LAYER M3 ;
        RECT  22.932 21.563 22.95 21.6 ;
    END
  END so[822]
  PIN so[823]
    DIRECTION OUTPUT ;
    USE SIGNAL ;
    PORT
      LAYER M3 ;
        RECT  23.004 21.563 23.022 21.6 ;
    END
  END so[823]
  PIN so[824]
    DIRECTION OUTPUT ;
    USE SIGNAL ;
    PORT
      LAYER M3 ;
        RECT  23.076 21.563 23.094 21.6 ;
    END
  END so[824]
  PIN so[825]
    DIRECTION OUTPUT ;
    USE SIGNAL ;
    PORT
      LAYER M3 ;
        RECT  23.148 21.563 23.166 21.6 ;
    END
  END so[825]
  PIN so[826]
    DIRECTION OUTPUT ;
    USE SIGNAL ;
    PORT
      LAYER M3 ;
        RECT  23.22 21.563 23.238 21.6 ;
    END
  END so[826]
  PIN so[827]
    DIRECTION OUTPUT ;
    USE SIGNAL ;
    PORT
      LAYER M3 ;
        RECT  23.292 21.563 23.31 21.6 ;
    END
  END so[827]
  PIN so[828]
    DIRECTION OUTPUT ;
    USE SIGNAL ;
    PORT
      LAYER M3 ;
        RECT  23.364 21.563 23.382 21.6 ;
    END
  END so[828]
  PIN so[829]
    DIRECTION OUTPUT ;
    USE SIGNAL ;
    PORT
      LAYER M3 ;
        RECT  23.436 21.563 23.454 21.6 ;
    END
  END so[829]
  PIN so[82]
    DIRECTION OUTPUT ;
    USE SIGNAL ;
    PORT
      LAYER M3 ;
        RECT  27.252 21.563 27.27 21.6 ;
    END
  END so[82]
  PIN so[830]
    DIRECTION OUTPUT ;
    USE SIGNAL ;
    PORT
      LAYER M3 ;
        RECT  23.508 21.563 23.526 21.6 ;
    END
  END so[830]
  PIN so[831]
    DIRECTION OUTPUT ;
    USE SIGNAL ;
    PORT
      LAYER M3 ;
        RECT  23.58 21.563 23.598 21.6 ;
    END
  END so[831]
  PIN so[832]
    DIRECTION OUTPUT ;
    USE SIGNAL ;
    PORT
      LAYER M3 ;
        RECT  69.156 21.563 69.174 21.6 ;
    END
  END so[832]
  PIN so[833]
    DIRECTION OUTPUT ;
    USE SIGNAL ;
    PORT
      LAYER M3 ;
        RECT  69.228 21.563 69.246 21.6 ;
    END
  END so[833]
  PIN so[834]
    DIRECTION OUTPUT ;
    USE SIGNAL ;
    PORT
      LAYER M3 ;
        RECT  69.3 21.563 69.318 21.6 ;
    END
  END so[834]
  PIN so[835]
    DIRECTION OUTPUT ;
    USE SIGNAL ;
    PORT
      LAYER M3 ;
        RECT  69.372 21.563 69.39 21.6 ;
    END
  END so[835]
  PIN so[836]
    DIRECTION OUTPUT ;
    USE SIGNAL ;
    PORT
      LAYER M3 ;
        RECT  69.444 21.563 69.462 21.6 ;
    END
  END so[836]
  PIN so[837]
    DIRECTION OUTPUT ;
    USE SIGNAL ;
    PORT
      LAYER M3 ;
        RECT  69.516 21.563 69.534 21.6 ;
    END
  END so[837]
  PIN so[838]
    DIRECTION OUTPUT ;
    USE SIGNAL ;
    PORT
      LAYER M3 ;
        RECT  69.588 21.563 69.606 21.6 ;
    END
  END so[838]
  PIN so[839]
    DIRECTION OUTPUT ;
    USE SIGNAL ;
    PORT
      LAYER M3 ;
        RECT  69.66 21.563 69.678 21.6 ;
    END
  END so[839]
  PIN so[83]
    DIRECTION OUTPUT ;
    USE SIGNAL ;
    PORT
      LAYER M3 ;
        RECT  27.324 21.563 27.342 21.6 ;
    END
  END so[83]
  PIN so[840]
    DIRECTION OUTPUT ;
    USE SIGNAL ;
    PORT
      LAYER M3 ;
        RECT  69.732 21.563 69.75 21.6 ;
    END
  END so[840]
  PIN so[841]
    DIRECTION OUTPUT ;
    USE SIGNAL ;
    PORT
      LAYER M3 ;
        RECT  69.804 21.563 69.822 21.6 ;
    END
  END so[841]
  PIN so[842]
    DIRECTION OUTPUT ;
    USE SIGNAL ;
    PORT
      LAYER M3 ;
        RECT  69.876 21.563 69.894 21.6 ;
    END
  END so[842]
  PIN so[843]
    DIRECTION OUTPUT ;
    USE SIGNAL ;
    PORT
      LAYER M3 ;
        RECT  69.948 21.563 69.966 21.6 ;
    END
  END so[843]
  PIN so[844]
    DIRECTION OUTPUT ;
    USE SIGNAL ;
    PORT
      LAYER M3 ;
        RECT  70.02 21.563 70.038 21.6 ;
    END
  END so[844]
  PIN so[845]
    DIRECTION OUTPUT ;
    USE SIGNAL ;
    PORT
      LAYER M3 ;
        RECT  70.092 21.563 70.11 21.6 ;
    END
  END so[845]
  PIN so[846]
    DIRECTION OUTPUT ;
    USE SIGNAL ;
    PORT
      LAYER M3 ;
        RECT  70.164 21.563 70.182 21.6 ;
    END
  END so[846]
  PIN so[847]
    DIRECTION OUTPUT ;
    USE SIGNAL ;
    PORT
      LAYER M3 ;
        RECT  70.236 21.563 70.254 21.6 ;
    END
  END so[847]
  PIN so[848]
    DIRECTION OUTPUT ;
    USE SIGNAL ;
    PORT
      LAYER M3 ;
        RECT  70.308 21.563 70.326 21.6 ;
    END
  END so[848]
  PIN so[849]
    DIRECTION OUTPUT ;
    USE SIGNAL ;
    PORT
      LAYER M3 ;
        RECT  70.38 21.563 70.398 21.6 ;
    END
  END so[849]
  PIN so[84]
    DIRECTION OUTPUT ;
    USE SIGNAL ;
    PORT
      LAYER M3 ;
        RECT  27.396 21.563 27.414 21.6 ;
    END
  END so[84]
  PIN so[850]
    DIRECTION OUTPUT ;
    USE SIGNAL ;
    PORT
      LAYER M3 ;
        RECT  70.452 21.563 70.47 21.6 ;
    END
  END so[850]
  PIN so[851]
    DIRECTION OUTPUT ;
    USE SIGNAL ;
    PORT
      LAYER M3 ;
        RECT  70.524 21.563 70.542 21.6 ;
    END
  END so[851]
  PIN so[852]
    DIRECTION OUTPUT ;
    USE SIGNAL ;
    PORT
      LAYER M3 ;
        RECT  70.596 21.563 70.614 21.6 ;
    END
  END so[852]
  PIN so[853]
    DIRECTION OUTPUT ;
    USE SIGNAL ;
    PORT
      LAYER M3 ;
        RECT  70.668 21.563 70.686 21.6 ;
    END
  END so[853]
  PIN so[854]
    DIRECTION OUTPUT ;
    USE SIGNAL ;
    PORT
      LAYER M3 ;
        RECT  70.74 21.563 70.758 21.6 ;
    END
  END so[854]
  PIN so[855]
    DIRECTION OUTPUT ;
    USE SIGNAL ;
    PORT
      LAYER M3 ;
        RECT  70.812 21.563 70.83 21.6 ;
    END
  END so[855]
  PIN so[856]
    DIRECTION OUTPUT ;
    USE SIGNAL ;
    PORT
      LAYER M3 ;
        RECT  70.884 21.563 70.902 21.6 ;
    END
  END so[856]
  PIN so[857]
    DIRECTION OUTPUT ;
    USE SIGNAL ;
    PORT
      LAYER M3 ;
        RECT  70.956 21.563 70.974 21.6 ;
    END
  END so[857]
  PIN so[858]
    DIRECTION OUTPUT ;
    USE SIGNAL ;
    PORT
      LAYER M3 ;
        RECT  71.028 21.563 71.046 21.6 ;
    END
  END so[858]
  PIN so[859]
    DIRECTION OUTPUT ;
    USE SIGNAL ;
    PORT
      LAYER M3 ;
        RECT  71.1 21.563 71.118 21.6 ;
    END
  END so[859]
  PIN so[85]
    DIRECTION OUTPUT ;
    USE SIGNAL ;
    PORT
      LAYER M3 ;
        RECT  27.468 21.563 27.486 21.6 ;
    END
  END so[85]
  PIN so[860]
    DIRECTION OUTPUT ;
    USE SIGNAL ;
    PORT
      LAYER M3 ;
        RECT  71.172 21.563 71.19 21.6 ;
    END
  END so[860]
  PIN so[861]
    DIRECTION OUTPUT ;
    USE SIGNAL ;
    PORT
      LAYER M3 ;
        RECT  71.244 21.563 71.262 21.6 ;
    END
  END so[861]
  PIN so[862]
    DIRECTION OUTPUT ;
    USE SIGNAL ;
    PORT
      LAYER M3 ;
        RECT  71.316 21.563 71.334 21.6 ;
    END
  END so[862]
  PIN so[863]
    DIRECTION OUTPUT ;
    USE SIGNAL ;
    PORT
      LAYER M3 ;
        RECT  71.388 21.563 71.406 21.6 ;
    END
  END so[863]
  PIN so[864]
    DIRECTION OUTPUT ;
    USE SIGNAL ;
    PORT
      LAYER M5 ;
        RECT  57.264 21.516 57.288 21.6 ;
    END
  END so[864]
  PIN so[865]
    DIRECTION OUTPUT ;
    USE SIGNAL ;
    PORT
      LAYER M5 ;
        RECT  57.36 21.516 57.384 21.6 ;
    END
  END so[865]
  PIN so[866]
    DIRECTION OUTPUT ;
    USE SIGNAL ;
    PORT
      LAYER M5 ;
        RECT  57.456 21.516 57.48 21.6 ;
    END
  END so[866]
  PIN so[867]
    DIRECTION OUTPUT ;
    USE SIGNAL ;
    PORT
      LAYER M5 ;
        RECT  57.552 21.516 57.576 21.6 ;
    END
  END so[867]
  PIN so[868]
    DIRECTION OUTPUT ;
    USE SIGNAL ;
    PORT
      LAYER M5 ;
        RECT  57.648 21.516 57.672 21.6 ;
    END
  END so[868]
  PIN so[869]
    DIRECTION OUTPUT ;
    USE SIGNAL ;
    PORT
      LAYER M5 ;
        RECT  57.744 21.516 57.768 21.6 ;
    END
  END so[869]
  PIN so[86]
    DIRECTION OUTPUT ;
    USE SIGNAL ;
    PORT
      LAYER M3 ;
        RECT  27.54 21.563 27.558 21.6 ;
    END
  END so[86]
  PIN so[870]
    DIRECTION OUTPUT ;
    USE SIGNAL ;
    PORT
      LAYER M5 ;
        RECT  57.84 21.516 57.864 21.6 ;
    END
  END so[870]
  PIN so[871]
    DIRECTION OUTPUT ;
    USE SIGNAL ;
    PORT
      LAYER M5 ;
        RECT  57.936 21.516 57.96 21.6 ;
    END
  END so[871]
  PIN so[872]
    DIRECTION OUTPUT ;
    USE SIGNAL ;
    PORT
      LAYER M5 ;
        RECT  58.032 21.516 58.056 21.6 ;
    END
  END so[872]
  PIN so[873]
    DIRECTION OUTPUT ;
    USE SIGNAL ;
    PORT
      LAYER M5 ;
        RECT  58.128 21.516 58.152 21.6 ;
    END
  END so[873]
  PIN so[874]
    DIRECTION OUTPUT ;
    USE SIGNAL ;
    PORT
      LAYER M5 ;
        RECT  58.224 21.516 58.248 21.6 ;
    END
  END so[874]
  PIN so[875]
    DIRECTION OUTPUT ;
    USE SIGNAL ;
    PORT
      LAYER M5 ;
        RECT  58.32 21.516 58.344 21.6 ;
    END
  END so[875]
  PIN so[876]
    DIRECTION OUTPUT ;
    USE SIGNAL ;
    PORT
      LAYER M5 ;
        RECT  58.416 21.516 58.44 21.6 ;
    END
  END so[876]
  PIN so[877]
    DIRECTION OUTPUT ;
    USE SIGNAL ;
    PORT
      LAYER M5 ;
        RECT  58.512 21.516 58.536 21.6 ;
    END
  END so[877]
  PIN so[878]
    DIRECTION OUTPUT ;
    USE SIGNAL ;
    PORT
      LAYER M5 ;
        RECT  58.608 21.516 58.632 21.6 ;
    END
  END so[878]
  PIN so[879]
    DIRECTION OUTPUT ;
    USE SIGNAL ;
    PORT
      LAYER M5 ;
        RECT  58.704 21.516 58.728 21.6 ;
    END
  END so[879]
  PIN so[87]
    DIRECTION OUTPUT ;
    USE SIGNAL ;
    PORT
      LAYER M3 ;
        RECT  27.612 21.563 27.63 21.6 ;
    END
  END so[87]
  PIN so[880]
    DIRECTION OUTPUT ;
    USE SIGNAL ;
    PORT
      LAYER M5 ;
        RECT  58.8 21.516 58.824 21.6 ;
    END
  END so[880]
  PIN so[881]
    DIRECTION OUTPUT ;
    USE SIGNAL ;
    PORT
      LAYER M5 ;
        RECT  58.896 21.516 58.92 21.6 ;
    END
  END so[881]
  PIN so[882]
    DIRECTION OUTPUT ;
    USE SIGNAL ;
    PORT
      LAYER M5 ;
        RECT  58.992 21.516 59.016 21.6 ;
    END
  END so[882]
  PIN so[883]
    DIRECTION OUTPUT ;
    USE SIGNAL ;
    PORT
      LAYER M5 ;
        RECT  59.088 21.516 59.112 21.6 ;
    END
  END so[883]
  PIN so[884]
    DIRECTION OUTPUT ;
    USE SIGNAL ;
    PORT
      LAYER M5 ;
        RECT  59.184 21.516 59.208 21.6 ;
    END
  END so[884]
  PIN so[885]
    DIRECTION OUTPUT ;
    USE SIGNAL ;
    PORT
      LAYER M5 ;
        RECT  59.28 21.516 59.304 21.6 ;
    END
  END so[885]
  PIN so[886]
    DIRECTION OUTPUT ;
    USE SIGNAL ;
    PORT
      LAYER M5 ;
        RECT  59.376 21.516 59.4 21.6 ;
    END
  END so[886]
  PIN so[887]
    DIRECTION OUTPUT ;
    USE SIGNAL ;
    PORT
      LAYER M5 ;
        RECT  59.472 21.516 59.496 21.6 ;
    END
  END so[887]
  PIN so[888]
    DIRECTION OUTPUT ;
    USE SIGNAL ;
    PORT
      LAYER M5 ;
        RECT  59.568 21.516 59.592 21.6 ;
    END
  END so[888]
  PIN so[889]
    DIRECTION OUTPUT ;
    USE SIGNAL ;
    PORT
      LAYER M5 ;
        RECT  59.664 21.516 59.688 21.6 ;
    END
  END so[889]
  PIN so[88]
    DIRECTION OUTPUT ;
    USE SIGNAL ;
    PORT
      LAYER M3 ;
        RECT  27.684 21.563 27.702 21.6 ;
    END
  END so[88]
  PIN so[890]
    DIRECTION OUTPUT ;
    USE SIGNAL ;
    PORT
      LAYER M5 ;
        RECT  59.76 21.516 59.784 21.6 ;
    END
  END so[890]
  PIN so[891]
    DIRECTION OUTPUT ;
    USE SIGNAL ;
    PORT
      LAYER M5 ;
        RECT  59.856 21.516 59.88 21.6 ;
    END
  END so[891]
  PIN so[892]
    DIRECTION OUTPUT ;
    USE SIGNAL ;
    PORT
      LAYER M5 ;
        RECT  59.952 21.516 59.976 21.6 ;
    END
  END so[892]
  PIN so[893]
    DIRECTION OUTPUT ;
    USE SIGNAL ;
    PORT
      LAYER M5 ;
        RECT  60.048 21.516 60.072 21.6 ;
    END
  END so[893]
  PIN so[894]
    DIRECTION OUTPUT ;
    USE SIGNAL ;
    PORT
      LAYER M5 ;
        RECT  60.144 21.516 60.168 21.6 ;
    END
  END so[894]
  PIN so[895]
    DIRECTION OUTPUT ;
    USE SIGNAL ;
    PORT
      LAYER M5 ;
        RECT  60.24 21.516 60.264 21.6 ;
    END
  END so[895]
  PIN so[896]
    DIRECTION OUTPUT ;
    USE SIGNAL ;
    PORT
      LAYER M3 ;
        RECT  31.14 21.563 31.158 21.6 ;
    END
  END so[896]
  PIN so[897]
    DIRECTION OUTPUT ;
    USE SIGNAL ;
    PORT
      LAYER M3 ;
        RECT  31.212 21.563 31.23 21.6 ;
    END
  END so[897]
  PIN so[898]
    DIRECTION OUTPUT ;
    USE SIGNAL ;
    PORT
      LAYER M3 ;
        RECT  31.284 21.563 31.302 21.6 ;
    END
  END so[898]
  PIN so[899]
    DIRECTION OUTPUT ;
    USE SIGNAL ;
    PORT
      LAYER M3 ;
        RECT  31.356 21.563 31.374 21.6 ;
    END
  END so[899]
  PIN so[89]
    DIRECTION OUTPUT ;
    USE SIGNAL ;
    PORT
      LAYER M3 ;
        RECT  27.756 21.563 27.774 21.6 ;
    END
  END so[89]
  PIN so[8]
    DIRECTION OUTPUT ;
    USE SIGNAL ;
    PORT
      LAYER M3 ;
        RECT  5.22 21.563 5.238 21.6 ;
    END
  END so[8]
  PIN so[900]
    DIRECTION OUTPUT ;
    USE SIGNAL ;
    PORT
      LAYER M3 ;
        RECT  31.428 21.563 31.446 21.6 ;
    END
  END so[900]
  PIN so[901]
    DIRECTION OUTPUT ;
    USE SIGNAL ;
    PORT
      LAYER M3 ;
        RECT  31.5 21.563 31.518 21.6 ;
    END
  END so[901]
  PIN so[902]
    DIRECTION OUTPUT ;
    USE SIGNAL ;
    PORT
      LAYER M3 ;
        RECT  31.572 21.563 31.59 21.6 ;
    END
  END so[902]
  PIN so[903]
    DIRECTION OUTPUT ;
    USE SIGNAL ;
    PORT
      LAYER M3 ;
        RECT  31.644 21.563 31.662 21.6 ;
    END
  END so[903]
  PIN so[904]
    DIRECTION OUTPUT ;
    USE SIGNAL ;
    PORT
      LAYER M3 ;
        RECT  31.716 21.563 31.734 21.6 ;
    END
  END so[904]
  PIN so[905]
    DIRECTION OUTPUT ;
    USE SIGNAL ;
    PORT
      LAYER M3 ;
        RECT  31.788 21.563 31.806 21.6 ;
    END
  END so[905]
  PIN so[906]
    DIRECTION OUTPUT ;
    USE SIGNAL ;
    PORT
      LAYER M3 ;
        RECT  31.86 21.563 31.878 21.6 ;
    END
  END so[906]
  PIN so[907]
    DIRECTION OUTPUT ;
    USE SIGNAL ;
    PORT
      LAYER M3 ;
        RECT  31.932 21.563 31.95 21.6 ;
    END
  END so[907]
  PIN so[908]
    DIRECTION OUTPUT ;
    USE SIGNAL ;
    PORT
      LAYER M3 ;
        RECT  32.004 21.563 32.022 21.6 ;
    END
  END so[908]
  PIN so[909]
    DIRECTION OUTPUT ;
    USE SIGNAL ;
    PORT
      LAYER M3 ;
        RECT  32.076 21.563 32.094 21.6 ;
    END
  END so[909]
  PIN so[90]
    DIRECTION OUTPUT ;
    USE SIGNAL ;
    PORT
      LAYER M3 ;
        RECT  27.828 21.563 27.846 21.6 ;
    END
  END so[90]
  PIN so[910]
    DIRECTION OUTPUT ;
    USE SIGNAL ;
    PORT
      LAYER M3 ;
        RECT  32.148 21.563 32.166 21.6 ;
    END
  END so[910]
  PIN so[911]
    DIRECTION OUTPUT ;
    USE SIGNAL ;
    PORT
      LAYER M3 ;
        RECT  32.22 21.563 32.238 21.6 ;
    END
  END so[911]
  PIN so[912]
    DIRECTION OUTPUT ;
    USE SIGNAL ;
    PORT
      LAYER M3 ;
        RECT  32.292 21.563 32.31 21.6 ;
    END
  END so[912]
  PIN so[913]
    DIRECTION OUTPUT ;
    USE SIGNAL ;
    PORT
      LAYER M3 ;
        RECT  32.364 21.563 32.382 21.6 ;
    END
  END so[913]
  PIN so[914]
    DIRECTION OUTPUT ;
    USE SIGNAL ;
    PORT
      LAYER M3 ;
        RECT  32.436 21.563 32.454 21.6 ;
    END
  END so[914]
  PIN so[915]
    DIRECTION OUTPUT ;
    USE SIGNAL ;
    PORT
      LAYER M3 ;
        RECT  32.508 21.563 32.526 21.6 ;
    END
  END so[915]
  PIN so[916]
    DIRECTION OUTPUT ;
    USE SIGNAL ;
    PORT
      LAYER M3 ;
        RECT  32.58 21.563 32.598 21.6 ;
    END
  END so[916]
  PIN so[917]
    DIRECTION OUTPUT ;
    USE SIGNAL ;
    PORT
      LAYER M3 ;
        RECT  32.652 21.563 32.67 21.6 ;
    END
  END so[917]
  PIN so[918]
    DIRECTION OUTPUT ;
    USE SIGNAL ;
    PORT
      LAYER M3 ;
        RECT  32.724 21.563 32.742 21.6 ;
    END
  END so[918]
  PIN so[919]
    DIRECTION OUTPUT ;
    USE SIGNAL ;
    PORT
      LAYER M3 ;
        RECT  32.796 21.563 32.814 21.6 ;
    END
  END so[919]
  PIN so[91]
    DIRECTION OUTPUT ;
    USE SIGNAL ;
    PORT
      LAYER M3 ;
        RECT  27.9 21.563 27.918 21.6 ;
    END
  END so[91]
  PIN so[920]
    DIRECTION OUTPUT ;
    USE SIGNAL ;
    PORT
      LAYER M3 ;
        RECT  32.868 21.563 32.886 21.6 ;
    END
  END so[920]
  PIN so[921]
    DIRECTION OUTPUT ;
    USE SIGNAL ;
    PORT
      LAYER M3 ;
        RECT  32.94 21.563 32.958 21.6 ;
    END
  END so[921]
  PIN so[922]
    DIRECTION OUTPUT ;
    USE SIGNAL ;
    PORT
      LAYER M3 ;
        RECT  33.012 21.563 33.03 21.6 ;
    END
  END so[922]
  PIN so[923]
    DIRECTION OUTPUT ;
    USE SIGNAL ;
    PORT
      LAYER M3 ;
        RECT  33.084 21.563 33.102 21.6 ;
    END
  END so[923]
  PIN so[924]
    DIRECTION OUTPUT ;
    USE SIGNAL ;
    PORT
      LAYER M3 ;
        RECT  33.156 21.563 33.174 21.6 ;
    END
  END so[924]
  PIN so[925]
    DIRECTION OUTPUT ;
    USE SIGNAL ;
    PORT
      LAYER M3 ;
        RECT  33.228 21.563 33.246 21.6 ;
    END
  END so[925]
  PIN so[926]
    DIRECTION OUTPUT ;
    USE SIGNAL ;
    PORT
      LAYER M3 ;
        RECT  33.3 21.563 33.318 21.6 ;
    END
  END so[926]
  PIN so[927]
    DIRECTION OUTPUT ;
    USE SIGNAL ;
    PORT
      LAYER M3 ;
        RECT  33.372 21.563 33.39 21.6 ;
    END
  END so[927]
  PIN so[928]
    DIRECTION OUTPUT ;
    USE SIGNAL ;
    PORT
      LAYER M3 ;
        RECT  47.844 21.563 47.862 21.6 ;
    END
  END so[928]
  PIN so[929]
    DIRECTION OUTPUT ;
    USE SIGNAL ;
    PORT
      LAYER M3 ;
        RECT  47.916 21.563 47.934 21.6 ;
    END
  END so[929]
  PIN so[92]
    DIRECTION OUTPUT ;
    USE SIGNAL ;
    PORT
      LAYER M3 ;
        RECT  27.972 21.563 27.99 21.6 ;
    END
  END so[92]
  PIN so[930]
    DIRECTION OUTPUT ;
    USE SIGNAL ;
    PORT
      LAYER M3 ;
        RECT  47.988 21.563 48.006 21.6 ;
    END
  END so[930]
  PIN so[931]
    DIRECTION OUTPUT ;
    USE SIGNAL ;
    PORT
      LAYER M3 ;
        RECT  48.06 21.563 48.078 21.6 ;
    END
  END so[931]
  PIN so[932]
    DIRECTION OUTPUT ;
    USE SIGNAL ;
    PORT
      LAYER M3 ;
        RECT  48.132 21.563 48.15 21.6 ;
    END
  END so[932]
  PIN so[933]
    DIRECTION OUTPUT ;
    USE SIGNAL ;
    PORT
      LAYER M3 ;
        RECT  48.204 21.563 48.222 21.6 ;
    END
  END so[933]
  PIN so[934]
    DIRECTION OUTPUT ;
    USE SIGNAL ;
    PORT
      LAYER M3 ;
        RECT  48.276 21.563 48.294 21.6 ;
    END
  END so[934]
  PIN so[935]
    DIRECTION OUTPUT ;
    USE SIGNAL ;
    PORT
      LAYER M3 ;
        RECT  48.348 21.563 48.366 21.6 ;
    END
  END so[935]
  PIN so[936]
    DIRECTION OUTPUT ;
    USE SIGNAL ;
    PORT
      LAYER M3 ;
        RECT  48.42 21.563 48.438 21.6 ;
    END
  END so[936]
  PIN so[937]
    DIRECTION OUTPUT ;
    USE SIGNAL ;
    PORT
      LAYER M3 ;
        RECT  48.492 21.563 48.51 21.6 ;
    END
  END so[937]
  PIN so[938]
    DIRECTION OUTPUT ;
    USE SIGNAL ;
    PORT
      LAYER M3 ;
        RECT  48.564 21.563 48.582 21.6 ;
    END
  END so[938]
  PIN so[939]
    DIRECTION OUTPUT ;
    USE SIGNAL ;
    PORT
      LAYER M3 ;
        RECT  48.636 21.563 48.654 21.6 ;
    END
  END so[939]
  PIN so[93]
    DIRECTION OUTPUT ;
    USE SIGNAL ;
    PORT
      LAYER M3 ;
        RECT  28.044 21.563 28.062 21.6 ;
    END
  END so[93]
  PIN so[940]
    DIRECTION OUTPUT ;
    USE SIGNAL ;
    PORT
      LAYER M3 ;
        RECT  48.708 21.563 48.726 21.6 ;
    END
  END so[940]
  PIN so[941]
    DIRECTION OUTPUT ;
    USE SIGNAL ;
    PORT
      LAYER M3 ;
        RECT  48.78 21.563 48.798 21.6 ;
    END
  END so[941]
  PIN so[942]
    DIRECTION OUTPUT ;
    USE SIGNAL ;
    PORT
      LAYER M3 ;
        RECT  48.852 21.563 48.87 21.6 ;
    END
  END so[942]
  PIN so[943]
    DIRECTION OUTPUT ;
    USE SIGNAL ;
    PORT
      LAYER M3 ;
        RECT  48.924 21.563 48.942 21.6 ;
    END
  END so[943]
  PIN so[944]
    DIRECTION OUTPUT ;
    USE SIGNAL ;
    PORT
      LAYER M3 ;
        RECT  48.996 21.563 49.014 21.6 ;
    END
  END so[944]
  PIN so[945]
    DIRECTION OUTPUT ;
    USE SIGNAL ;
    PORT
      LAYER M3 ;
        RECT  49.068 21.563 49.086 21.6 ;
    END
  END so[945]
  PIN so[946]
    DIRECTION OUTPUT ;
    USE SIGNAL ;
    PORT
      LAYER M3 ;
        RECT  49.14 21.563 49.158 21.6 ;
    END
  END so[946]
  PIN so[947]
    DIRECTION OUTPUT ;
    USE SIGNAL ;
    PORT
      LAYER M3 ;
        RECT  49.212 21.563 49.23 21.6 ;
    END
  END so[947]
  PIN so[948]
    DIRECTION OUTPUT ;
    USE SIGNAL ;
    PORT
      LAYER M3 ;
        RECT  49.284 21.563 49.302 21.6 ;
    END
  END so[948]
  PIN so[949]
    DIRECTION OUTPUT ;
    USE SIGNAL ;
    PORT
      LAYER M3 ;
        RECT  49.356 21.563 49.374 21.6 ;
    END
  END so[949]
  PIN so[94]
    DIRECTION OUTPUT ;
    USE SIGNAL ;
    PORT
      LAYER M3 ;
        RECT  28.116 21.563 28.134 21.6 ;
    END
  END so[94]
  PIN so[950]
    DIRECTION OUTPUT ;
    USE SIGNAL ;
    PORT
      LAYER M3 ;
        RECT  49.428 21.563 49.446 21.6 ;
    END
  END so[950]
  PIN so[951]
    DIRECTION OUTPUT ;
    USE SIGNAL ;
    PORT
      LAYER M3 ;
        RECT  49.5 21.563 49.518 21.6 ;
    END
  END so[951]
  PIN so[952]
    DIRECTION OUTPUT ;
    USE SIGNAL ;
    PORT
      LAYER M3 ;
        RECT  49.572 21.563 49.59 21.6 ;
    END
  END so[952]
  PIN so[953]
    DIRECTION OUTPUT ;
    USE SIGNAL ;
    PORT
      LAYER M3 ;
        RECT  49.644 21.563 49.662 21.6 ;
    END
  END so[953]
  PIN so[954]
    DIRECTION OUTPUT ;
    USE SIGNAL ;
    PORT
      LAYER M3 ;
        RECT  49.716 21.563 49.734 21.6 ;
    END
  END so[954]
  PIN so[955]
    DIRECTION OUTPUT ;
    USE SIGNAL ;
    PORT
      LAYER M3 ;
        RECT  49.788 21.563 49.806 21.6 ;
    END
  END so[955]
  PIN so[956]
    DIRECTION OUTPUT ;
    USE SIGNAL ;
    PORT
      LAYER M3 ;
        RECT  49.86 21.563 49.878 21.6 ;
    END
  END so[956]
  PIN so[957]
    DIRECTION OUTPUT ;
    USE SIGNAL ;
    PORT
      LAYER M3 ;
        RECT  49.932 21.563 49.95 21.6 ;
    END
  END so[957]
  PIN so[958]
    DIRECTION OUTPUT ;
    USE SIGNAL ;
    PORT
      LAYER M3 ;
        RECT  50.004 21.563 50.022 21.6 ;
    END
  END so[958]
  PIN so[959]
    DIRECTION OUTPUT ;
    USE SIGNAL ;
    PORT
      LAYER M3 ;
        RECT  50.076 21.563 50.094 21.6 ;
    END
  END so[959]
  PIN so[95]
    DIRECTION OUTPUT ;
    USE SIGNAL ;
    PORT
      LAYER M3 ;
        RECT  28.188 21.563 28.206 21.6 ;
    END
  END so[95]
  PIN so[960]
    DIRECTION OUTPUT ;
    USE SIGNAL ;
    PORT
      LAYER M5 ;
        RECT  15.792 21.516 15.816 21.6 ;
    END
  END so[960]
  PIN so[961]
    DIRECTION OUTPUT ;
    USE SIGNAL ;
    PORT
      LAYER M5 ;
        RECT  15.888 21.516 15.912 21.6 ;
    END
  END so[961]
  PIN so[962]
    DIRECTION OUTPUT ;
    USE SIGNAL ;
    PORT
      LAYER M5 ;
        RECT  15.984 21.516 16.008 21.6 ;
    END
  END so[962]
  PIN so[963]
    DIRECTION OUTPUT ;
    USE SIGNAL ;
    PORT
      LAYER M5 ;
        RECT  16.08 21.516 16.104 21.6 ;
    END
  END so[963]
  PIN so[964]
    DIRECTION OUTPUT ;
    USE SIGNAL ;
    PORT
      LAYER M5 ;
        RECT  16.176 21.516 16.2 21.6 ;
    END
  END so[964]
  PIN so[965]
    DIRECTION OUTPUT ;
    USE SIGNAL ;
    PORT
      LAYER M5 ;
        RECT  16.272 21.516 16.296 21.6 ;
    END
  END so[965]
  PIN so[966]
    DIRECTION OUTPUT ;
    USE SIGNAL ;
    PORT
      LAYER M5 ;
        RECT  16.368 21.516 16.392 21.6 ;
    END
  END so[966]
  PIN so[967]
    DIRECTION OUTPUT ;
    USE SIGNAL ;
    PORT
      LAYER M5 ;
        RECT  16.464 21.516 16.488 21.6 ;
    END
  END so[967]
  PIN so[968]
    DIRECTION OUTPUT ;
    USE SIGNAL ;
    PORT
      LAYER M5 ;
        RECT  16.56 21.516 16.584 21.6 ;
    END
  END so[968]
  PIN so[969]
    DIRECTION OUTPUT ;
    USE SIGNAL ;
    PORT
      LAYER M5 ;
        RECT  16.656 21.516 16.68 21.6 ;
    END
  END so[969]
  PIN so[96]
    DIRECTION OUTPUT ;
    USE SIGNAL ;
    PORT
      LAYER M3 ;
        RECT  74.34 21.563 74.358 21.6 ;
    END
  END so[96]
  PIN so[970]
    DIRECTION OUTPUT ;
    USE SIGNAL ;
    PORT
      LAYER M5 ;
        RECT  16.752 21.516 16.776 21.6 ;
    END
  END so[970]
  PIN so[971]
    DIRECTION OUTPUT ;
    USE SIGNAL ;
    PORT
      LAYER M5 ;
        RECT  16.848 21.516 16.872 21.6 ;
    END
  END so[971]
  PIN so[972]
    DIRECTION OUTPUT ;
    USE SIGNAL ;
    PORT
      LAYER M5 ;
        RECT  16.944 21.516 16.968 21.6 ;
    END
  END so[972]
  PIN so[973]
    DIRECTION OUTPUT ;
    USE SIGNAL ;
    PORT
      LAYER M5 ;
        RECT  17.04 21.516 17.064 21.6 ;
    END
  END so[973]
  PIN so[974]
    DIRECTION OUTPUT ;
    USE SIGNAL ;
    PORT
      LAYER M5 ;
        RECT  17.136 21.516 17.16 21.6 ;
    END
  END so[974]
  PIN so[975]
    DIRECTION OUTPUT ;
    USE SIGNAL ;
    PORT
      LAYER M5 ;
        RECT  17.232 21.516 17.256 21.6 ;
    END
  END so[975]
  PIN so[976]
    DIRECTION OUTPUT ;
    USE SIGNAL ;
    PORT
      LAYER M5 ;
        RECT  17.328 21.516 17.352 21.6 ;
    END
  END so[976]
  PIN so[977]
    DIRECTION OUTPUT ;
    USE SIGNAL ;
    PORT
      LAYER M5 ;
        RECT  17.424 21.516 17.448 21.6 ;
    END
  END so[977]
  PIN so[978]
    DIRECTION OUTPUT ;
    USE SIGNAL ;
    PORT
      LAYER M5 ;
        RECT  17.52 21.516 17.544 21.6 ;
    END
  END so[978]
  PIN so[979]
    DIRECTION OUTPUT ;
    USE SIGNAL ;
    PORT
      LAYER M5 ;
        RECT  17.616 21.516 17.64 21.6 ;
    END
  END so[979]
  PIN so[97]
    DIRECTION OUTPUT ;
    USE SIGNAL ;
    PORT
      LAYER M3 ;
        RECT  74.412 21.563 74.43 21.6 ;
    END
  END so[97]
  PIN so[980]
    DIRECTION OUTPUT ;
    USE SIGNAL ;
    PORT
      LAYER M5 ;
        RECT  17.712 21.516 17.736 21.6 ;
    END
  END so[980]
  PIN so[981]
    DIRECTION OUTPUT ;
    USE SIGNAL ;
    PORT
      LAYER M5 ;
        RECT  17.808 21.516 17.832 21.6 ;
    END
  END so[981]
  PIN so[982]
    DIRECTION OUTPUT ;
    USE SIGNAL ;
    PORT
      LAYER M5 ;
        RECT  17.904 21.516 17.928 21.6 ;
    END
  END so[982]
  PIN so[983]
    DIRECTION OUTPUT ;
    USE SIGNAL ;
    PORT
      LAYER M5 ;
        RECT  18 21.516 18.024 21.6 ;
    END
  END so[983]
  PIN so[984]
    DIRECTION OUTPUT ;
    USE SIGNAL ;
    PORT
      LAYER M5 ;
        RECT  18.096 21.516 18.12 21.6 ;
    END
  END so[984]
  PIN so[985]
    DIRECTION OUTPUT ;
    USE SIGNAL ;
    PORT
      LAYER M5 ;
        RECT  18.192 21.516 18.216 21.6 ;
    END
  END so[985]
  PIN so[986]
    DIRECTION OUTPUT ;
    USE SIGNAL ;
    PORT
      LAYER M5 ;
        RECT  18.288 21.516 18.312 21.6 ;
    END
  END so[986]
  PIN so[987]
    DIRECTION OUTPUT ;
    USE SIGNAL ;
    PORT
      LAYER M5 ;
        RECT  18.384 21.516 18.408 21.6 ;
    END
  END so[987]
  PIN so[988]
    DIRECTION OUTPUT ;
    USE SIGNAL ;
    PORT
      LAYER M5 ;
        RECT  18.48 21.516 18.504 21.6 ;
    END
  END so[988]
  PIN so[989]
    DIRECTION OUTPUT ;
    USE SIGNAL ;
    PORT
      LAYER M5 ;
        RECT  18.576 21.516 18.6 21.6 ;
    END
  END so[989]
  PIN so[98]
    DIRECTION OUTPUT ;
    USE SIGNAL ;
    PORT
      LAYER M3 ;
        RECT  74.484 21.563 74.502 21.6 ;
    END
  END so[98]
  PIN so[990]
    DIRECTION OUTPUT ;
    USE SIGNAL ;
    PORT
      LAYER M5 ;
        RECT  18.672 21.516 18.696 21.6 ;
    END
  END so[990]
  PIN so[991]
    DIRECTION OUTPUT ;
    USE SIGNAL ;
    PORT
      LAYER M5 ;
        RECT  18.768 21.516 18.792 21.6 ;
    END
  END so[991]
  PIN so[992]
    DIRECTION OUTPUT ;
    USE SIGNAL ;
    PORT
      LAYER M5 ;
        RECT  41.136 21.516 41.16 21.6 ;
    END
  END so[992]
  PIN so[993]
    DIRECTION OUTPUT ;
    USE SIGNAL ;
    PORT
      LAYER M5 ;
        RECT  41.232 21.516 41.256 21.6 ;
    END
  END so[993]
  PIN so[994]
    DIRECTION OUTPUT ;
    USE SIGNAL ;
    PORT
      LAYER M5 ;
        RECT  41.328 21.516 41.352 21.6 ;
    END
  END so[994]
  PIN so[995]
    DIRECTION OUTPUT ;
    USE SIGNAL ;
    PORT
      LAYER M5 ;
        RECT  41.424 21.516 41.448 21.6 ;
    END
  END so[995]
  PIN so[996]
    DIRECTION OUTPUT ;
    USE SIGNAL ;
    PORT
      LAYER M5 ;
        RECT  41.52 21.516 41.544 21.6 ;
    END
  END so[996]
  PIN so[997]
    DIRECTION OUTPUT ;
    USE SIGNAL ;
    PORT
      LAYER M5 ;
        RECT  41.616 21.516 41.64 21.6 ;
    END
  END so[997]
  PIN so[998]
    DIRECTION OUTPUT ;
    USE SIGNAL ;
    PORT
      LAYER M5 ;
        RECT  41.712 21.516 41.736 21.6 ;
    END
  END so[998]
  PIN so[999]
    DIRECTION OUTPUT ;
    USE SIGNAL ;
    PORT
      LAYER M5 ;
        RECT  41.808 21.516 41.832 21.6 ;
    END
  END so[999]
  PIN so[99]
    DIRECTION OUTPUT ;
    USE SIGNAL ;
    PORT
      LAYER M3 ;
        RECT  74.556 21.563 74.574 21.6 ;
    END
  END so[99]
  PIN so[9]
    DIRECTION OUTPUT ;
    USE SIGNAL ;
    PORT
      LAYER M3 ;
        RECT  5.292 21.563 5.31 21.6 ;
    END
  END so[9]
  PIN svc
    DIRECTION INPUT ;
    USE SIGNAL ;
    PORT
      LAYER M4 ;
        RECT  86.316 14.352 86.4 14.376 ;
    END
    PORT
      LAYER M4 ;
        RECT  85.489 14.352 86.364 14.376 ;
    END
  END svc
  PIN sx[0]
    DIRECTION INPUT ;
    USE SIGNAL ;
    PORT
      LAYER M3 ;
        RECT  7.452 0 7.47 0.037 ;
    END
  END sx[0]
  PIN sx[1000]
    DIRECTION INPUT ;
    USE SIGNAL ;
    PORT
      LAYER M3 ;
        RECT  39.132 0 39.15 0.037 ;
    END
  END sx[1000]
  PIN sx[1001]
    DIRECTION INPUT ;
    USE SIGNAL ;
    PORT
      LAYER M3 ;
        RECT  39.204 0 39.222 0.037 ;
    END
  END sx[1001]
  PIN sx[1002]
    DIRECTION INPUT ;
    USE SIGNAL ;
    PORT
      LAYER M3 ;
        RECT  39.276 0 39.294 0.037 ;
    END
  END sx[1002]
  PIN sx[1003]
    DIRECTION INPUT ;
    USE SIGNAL ;
    PORT
      LAYER M3 ;
        RECT  39.348 0 39.366 0.037 ;
    END
  END sx[1003]
  PIN sx[1004]
    DIRECTION INPUT ;
    USE SIGNAL ;
    PORT
      LAYER M3 ;
        RECT  39.42 0 39.438 0.037 ;
    END
  END sx[1004]
  PIN sx[1005]
    DIRECTION INPUT ;
    USE SIGNAL ;
    PORT
      LAYER M3 ;
        RECT  39.492 0 39.51 0.037 ;
    END
  END sx[1005]
  PIN sx[1006]
    DIRECTION INPUT ;
    USE SIGNAL ;
    PORT
      LAYER M3 ;
        RECT  39.564 0 39.582 0.037 ;
    END
  END sx[1006]
  PIN sx[1007]
    DIRECTION INPUT ;
    USE SIGNAL ;
    PORT
      LAYER M3 ;
        RECT  39.636 0 39.654 0.037 ;
    END
  END sx[1007]
  PIN sx[1008]
    DIRECTION INPUT ;
    USE SIGNAL ;
    PORT
      LAYER M3 ;
        RECT  39.708 0 39.726 0.037 ;
    END
  END sx[1008]
  PIN sx[1009]
    DIRECTION INPUT ;
    USE SIGNAL ;
    PORT
      LAYER M3 ;
        RECT  39.78 0 39.798 0.037 ;
    END
  END sx[1009]
  PIN sx[100]
    DIRECTION INPUT ;
    USE SIGNAL ;
    PORT
      LAYER M3 ;
        RECT  77.436 0 77.454 0.037 ;
    END
  END sx[100]
  PIN sx[1010]
    DIRECTION INPUT ;
    USE SIGNAL ;
    PORT
      LAYER M3 ;
        RECT  39.852 0 39.87 0.037 ;
    END
  END sx[1010]
  PIN sx[1011]
    DIRECTION INPUT ;
    USE SIGNAL ;
    PORT
      LAYER M3 ;
        RECT  39.924 0 39.942 0.037 ;
    END
  END sx[1011]
  PIN sx[1012]
    DIRECTION INPUT ;
    USE SIGNAL ;
    PORT
      LAYER M3 ;
        RECT  39.996 0 40.014 0.037 ;
    END
  END sx[1012]
  PIN sx[1013]
    DIRECTION INPUT ;
    USE SIGNAL ;
    PORT
      LAYER M3 ;
        RECT  40.068 0 40.086 0.037 ;
    END
  END sx[1013]
  PIN sx[1014]
    DIRECTION INPUT ;
    USE SIGNAL ;
    PORT
      LAYER M3 ;
        RECT  40.14 0 40.158 0.037 ;
    END
  END sx[1014]
  PIN sx[1015]
    DIRECTION INPUT ;
    USE SIGNAL ;
    PORT
      LAYER M3 ;
        RECT  40.212 0 40.23 0.037 ;
    END
  END sx[1015]
  PIN sx[1016]
    DIRECTION INPUT ;
    USE SIGNAL ;
    PORT
      LAYER M3 ;
        RECT  40.284 0 40.302 0.037 ;
    END
  END sx[1016]
  PIN sx[1017]
    DIRECTION INPUT ;
    USE SIGNAL ;
    PORT
      LAYER M3 ;
        RECT  40.356 0 40.374 0.037 ;
    END
  END sx[1017]
  PIN sx[1018]
    DIRECTION INPUT ;
    USE SIGNAL ;
    PORT
      LAYER M3 ;
        RECT  40.428 0 40.446 0.037 ;
    END
  END sx[1018]
  PIN sx[1019]
    DIRECTION INPUT ;
    USE SIGNAL ;
    PORT
      LAYER M3 ;
        RECT  40.5 0 40.518 0.037 ;
    END
  END sx[1019]
  PIN sx[101]
    DIRECTION INPUT ;
    USE SIGNAL ;
    PORT
      LAYER M3 ;
        RECT  77.508 0 77.526 0.037 ;
    END
  END sx[101]
  PIN sx[1020]
    DIRECTION INPUT ;
    USE SIGNAL ;
    PORT
      LAYER M3 ;
        RECT  40.572 0 40.59 0.037 ;
    END
  END sx[1020]
  PIN sx[1021]
    DIRECTION INPUT ;
    USE SIGNAL ;
    PORT
      LAYER M3 ;
        RECT  40.644 0 40.662 0.037 ;
    END
  END sx[1021]
  PIN sx[1022]
    DIRECTION INPUT ;
    USE SIGNAL ;
    PORT
      LAYER M3 ;
        RECT  40.716 0 40.734 0.037 ;
    END
  END sx[1022]
  PIN sx[1023]
    DIRECTION INPUT ;
    USE SIGNAL ;
    PORT
      LAYER M3 ;
        RECT  40.788 0 40.806 0.037 ;
    END
  END sx[1023]
  PIN sx[102]
    DIRECTION INPUT ;
    USE SIGNAL ;
    PORT
      LAYER M3 ;
        RECT  77.58 0 77.598 0.037 ;
    END
  END sx[102]
  PIN sx[103]
    DIRECTION INPUT ;
    USE SIGNAL ;
    PORT
      LAYER M3 ;
        RECT  77.652 0 77.67 0.037 ;
    END
  END sx[103]
  PIN sx[104]
    DIRECTION INPUT ;
    USE SIGNAL ;
    PORT
      LAYER M3 ;
        RECT  77.724 0 77.742 0.037 ;
    END
  END sx[104]
  PIN sx[105]
    DIRECTION INPUT ;
    USE SIGNAL ;
    PORT
      LAYER M3 ;
        RECT  77.796 0 77.814 0.037 ;
    END
  END sx[105]
  PIN sx[106]
    DIRECTION INPUT ;
    USE SIGNAL ;
    PORT
      LAYER M3 ;
        RECT  77.868 0 77.886 0.037 ;
    END
  END sx[106]
  PIN sx[107]
    DIRECTION INPUT ;
    USE SIGNAL ;
    PORT
      LAYER M3 ;
        RECT  77.94 0 77.958 0.037 ;
    END
  END sx[107]
  PIN sx[108]
    DIRECTION INPUT ;
    USE SIGNAL ;
    PORT
      LAYER M3 ;
        RECT  78.012 0 78.03 0.037 ;
    END
  END sx[108]
  PIN sx[109]
    DIRECTION INPUT ;
    USE SIGNAL ;
    PORT
      LAYER M3 ;
        RECT  78.084 0 78.102 0.037 ;
    END
  END sx[109]
  PIN sx[10]
    DIRECTION INPUT ;
    USE SIGNAL ;
    PORT
      LAYER M3 ;
        RECT  8.172 0 8.19 0.037 ;
    END
  END sx[10]
  PIN sx[110]
    DIRECTION INPUT ;
    USE SIGNAL ;
    PORT
      LAYER M3 ;
        RECT  78.156 0 78.174 0.037 ;
    END
  END sx[110]
  PIN sx[111]
    DIRECTION INPUT ;
    USE SIGNAL ;
    PORT
      LAYER M3 ;
        RECT  78.228 0 78.246 0.037 ;
    END
  END sx[111]
  PIN sx[112]
    DIRECTION INPUT ;
    USE SIGNAL ;
    PORT
      LAYER M3 ;
        RECT  78.3 0 78.318 0.037 ;
    END
  END sx[112]
  PIN sx[113]
    DIRECTION INPUT ;
    USE SIGNAL ;
    PORT
      LAYER M3 ;
        RECT  78.372 0 78.39 0.037 ;
    END
  END sx[113]
  PIN sx[114]
    DIRECTION INPUT ;
    USE SIGNAL ;
    PORT
      LAYER M3 ;
        RECT  78.444 0 78.462 0.037 ;
    END
  END sx[114]
  PIN sx[115]
    DIRECTION INPUT ;
    USE SIGNAL ;
    PORT
      LAYER M3 ;
        RECT  78.516 0 78.534 0.037 ;
    END
  END sx[115]
  PIN sx[116]
    DIRECTION INPUT ;
    USE SIGNAL ;
    PORT
      LAYER M3 ;
        RECT  78.588 0 78.606 0.037 ;
    END
  END sx[116]
  PIN sx[117]
    DIRECTION INPUT ;
    USE SIGNAL ;
    PORT
      LAYER M3 ;
        RECT  78.66 0 78.678 0.037 ;
    END
  END sx[117]
  PIN sx[118]
    DIRECTION INPUT ;
    USE SIGNAL ;
    PORT
      LAYER M3 ;
        RECT  78.732 0 78.75 0.037 ;
    END
  END sx[118]
  PIN sx[119]
    DIRECTION INPUT ;
    USE SIGNAL ;
    PORT
      LAYER M3 ;
        RECT  78.804 0 78.822 0.037 ;
    END
  END sx[119]
  PIN sx[11]
    DIRECTION INPUT ;
    USE SIGNAL ;
    PORT
      LAYER M3 ;
        RECT  8.244 0 8.262 0.037 ;
    END
  END sx[11]
  PIN sx[120]
    DIRECTION INPUT ;
    USE SIGNAL ;
    PORT
      LAYER M3 ;
        RECT  78.876 0 78.894 0.037 ;
    END
  END sx[120]
  PIN sx[121]
    DIRECTION INPUT ;
    USE SIGNAL ;
    PORT
      LAYER M3 ;
        RECT  78.948 0 78.966 0.037 ;
    END
  END sx[121]
  PIN sx[122]
    DIRECTION INPUT ;
    USE SIGNAL ;
    PORT
      LAYER M3 ;
        RECT  79.02 0 79.038 0.037 ;
    END
  END sx[122]
  PIN sx[123]
    DIRECTION INPUT ;
    USE SIGNAL ;
    PORT
      LAYER M3 ;
        RECT  79.092 0 79.11 0.037 ;
    END
  END sx[123]
  PIN sx[124]
    DIRECTION INPUT ;
    USE SIGNAL ;
    PORT
      LAYER M3 ;
        RECT  79.164 0 79.182 0.037 ;
    END
  END sx[124]
  PIN sx[125]
    DIRECTION INPUT ;
    USE SIGNAL ;
    PORT
      LAYER M3 ;
        RECT  79.236 0 79.254 0.037 ;
    END
  END sx[125]
  PIN sx[126]
    DIRECTION INPUT ;
    USE SIGNAL ;
    PORT
      LAYER M3 ;
        RECT  79.308 0 79.326 0.037 ;
    END
  END sx[126]
  PIN sx[127]
    DIRECTION INPUT ;
    USE SIGNAL ;
    PORT
      LAYER M3 ;
        RECT  79.38 0 79.398 0.037 ;
    END
  END sx[127]
  PIN sx[128]
    DIRECTION INPUT ;
    USE SIGNAL ;
    PORT
      LAYER M5 ;
        RECT  48.336 0 48.36 0.084 ;
    END
  END sx[128]
  PIN sx[129]
    DIRECTION INPUT ;
    USE SIGNAL ;
    PORT
      LAYER M5 ;
        RECT  48.432 0 48.456 0.084 ;
    END
  END sx[129]
  PIN sx[12]
    DIRECTION INPUT ;
    USE SIGNAL ;
    PORT
      LAYER M3 ;
        RECT  8.316 0 8.334 0.037 ;
    END
  END sx[12]
  PIN sx[130]
    DIRECTION INPUT ;
    USE SIGNAL ;
    PORT
      LAYER M5 ;
        RECT  48.528 0 48.552 0.084 ;
    END
  END sx[130]
  PIN sx[131]
    DIRECTION INPUT ;
    USE SIGNAL ;
    PORT
      LAYER M5 ;
        RECT  48.624 0 48.648 0.084 ;
    END
  END sx[131]
  PIN sx[132]
    DIRECTION INPUT ;
    USE SIGNAL ;
    PORT
      LAYER M5 ;
        RECT  48.72 0 48.744 0.084 ;
    END
  END sx[132]
  PIN sx[133]
    DIRECTION INPUT ;
    USE SIGNAL ;
    PORT
      LAYER M5 ;
        RECT  48.816 0 48.84 0.084 ;
    END
  END sx[133]
  PIN sx[134]
    DIRECTION INPUT ;
    USE SIGNAL ;
    PORT
      LAYER M5 ;
        RECT  48.912 0 48.936 0.084 ;
    END
  END sx[134]
  PIN sx[135]
    DIRECTION INPUT ;
    USE SIGNAL ;
    PORT
      LAYER M5 ;
        RECT  49.008 0 49.032 0.084 ;
    END
  END sx[135]
  PIN sx[136]
    DIRECTION INPUT ;
    USE SIGNAL ;
    PORT
      LAYER M5 ;
        RECT  49.104 0 49.128 0.084 ;
    END
  END sx[136]
  PIN sx[137]
    DIRECTION INPUT ;
    USE SIGNAL ;
    PORT
      LAYER M5 ;
        RECT  49.2 0 49.224 0.084 ;
    END
  END sx[137]
  PIN sx[138]
    DIRECTION INPUT ;
    USE SIGNAL ;
    PORT
      LAYER M5 ;
        RECT  49.296 0 49.32 0.084 ;
    END
  END sx[138]
  PIN sx[139]
    DIRECTION INPUT ;
    USE SIGNAL ;
    PORT
      LAYER M5 ;
        RECT  49.392 0 49.416 0.084 ;
    END
  END sx[139]
  PIN sx[13]
    DIRECTION INPUT ;
    USE SIGNAL ;
    PORT
      LAYER M3 ;
        RECT  8.388 0 8.406 0.037 ;
    END
  END sx[13]
  PIN sx[140]
    DIRECTION INPUT ;
    USE SIGNAL ;
    PORT
      LAYER M5 ;
        RECT  49.488 0 49.512 0.084 ;
    END
  END sx[140]
  PIN sx[141]
    DIRECTION INPUT ;
    USE SIGNAL ;
    PORT
      LAYER M5 ;
        RECT  49.584 0 49.608 0.084 ;
    END
  END sx[141]
  PIN sx[142]
    DIRECTION INPUT ;
    USE SIGNAL ;
    PORT
      LAYER M5 ;
        RECT  49.68 0 49.704 0.084 ;
    END
  END sx[142]
  PIN sx[143]
    DIRECTION INPUT ;
    USE SIGNAL ;
    PORT
      LAYER M5 ;
        RECT  49.776 0 49.8 0.084 ;
    END
  END sx[143]
  PIN sx[144]
    DIRECTION INPUT ;
    USE SIGNAL ;
    PORT
      LAYER M5 ;
        RECT  49.872 0 49.896 0.084 ;
    END
  END sx[144]
  PIN sx[145]
    DIRECTION INPUT ;
    USE SIGNAL ;
    PORT
      LAYER M5 ;
        RECT  49.968 0 49.992 0.084 ;
    END
  END sx[145]
  PIN sx[146]
    DIRECTION INPUT ;
    USE SIGNAL ;
    PORT
      LAYER M5 ;
        RECT  50.064 0 50.088 0.084 ;
    END
  END sx[146]
  PIN sx[147]
    DIRECTION INPUT ;
    USE SIGNAL ;
    PORT
      LAYER M5 ;
        RECT  50.16 0 50.184 0.084 ;
    END
  END sx[147]
  PIN sx[148]
    DIRECTION INPUT ;
    USE SIGNAL ;
    PORT
      LAYER M5 ;
        RECT  50.256 0 50.28 0.084 ;
    END
  END sx[148]
  PIN sx[149]
    DIRECTION INPUT ;
    USE SIGNAL ;
    PORT
      LAYER M5 ;
        RECT  50.352 0 50.376 0.084 ;
    END
  END sx[149]
  PIN sx[14]
    DIRECTION INPUT ;
    USE SIGNAL ;
    PORT
      LAYER M3 ;
        RECT  8.46 0 8.478 0.037 ;
    END
  END sx[14]
  PIN sx[150]
    DIRECTION INPUT ;
    USE SIGNAL ;
    PORT
      LAYER M5 ;
        RECT  50.448 0 50.472 0.084 ;
    END
  END sx[150]
  PIN sx[151]
    DIRECTION INPUT ;
    USE SIGNAL ;
    PORT
      LAYER M5 ;
        RECT  50.544 0 50.568 0.084 ;
    END
  END sx[151]
  PIN sx[152]
    DIRECTION INPUT ;
    USE SIGNAL ;
    PORT
      LAYER M5 ;
        RECT  50.64 0 50.664 0.084 ;
    END
  END sx[152]
  PIN sx[153]
    DIRECTION INPUT ;
    USE SIGNAL ;
    PORT
      LAYER M5 ;
        RECT  50.736 0 50.76 0.084 ;
    END
  END sx[153]
  PIN sx[154]
    DIRECTION INPUT ;
    USE SIGNAL ;
    PORT
      LAYER M5 ;
        RECT  50.832 0 50.856 0.084 ;
    END
  END sx[154]
  PIN sx[155]
    DIRECTION INPUT ;
    USE SIGNAL ;
    PORT
      LAYER M5 ;
        RECT  50.928 0 50.952 0.084 ;
    END
  END sx[155]
  PIN sx[156]
    DIRECTION INPUT ;
    USE SIGNAL ;
    PORT
      LAYER M5 ;
        RECT  51.024 0 51.048 0.084 ;
    END
  END sx[156]
  PIN sx[157]
    DIRECTION INPUT ;
    USE SIGNAL ;
    PORT
      LAYER M5 ;
        RECT  51.12 0 51.144 0.084 ;
    END
  END sx[157]
  PIN sx[158]
    DIRECTION INPUT ;
    USE SIGNAL ;
    PORT
      LAYER M5 ;
        RECT  51.216 0 51.24 0.084 ;
    END
  END sx[158]
  PIN sx[159]
    DIRECTION INPUT ;
    USE SIGNAL ;
    PORT
      LAYER M5 ;
        RECT  51.312 0 51.336 0.084 ;
    END
  END sx[159]
  PIN sx[15]
    DIRECTION INPUT ;
    USE SIGNAL ;
    PORT
      LAYER M3 ;
        RECT  8.532 0 8.55 0.037 ;
    END
  END sx[15]
  PIN sx[160]
    DIRECTION INPUT ;
    USE SIGNAL ;
    PORT
      LAYER M3 ;
        RECT  31.644 0 31.662 0.037 ;
    END
  END sx[160]
  PIN sx[161]
    DIRECTION INPUT ;
    USE SIGNAL ;
    PORT
      LAYER M3 ;
        RECT  31.716 0 31.734 0.037 ;
    END
  END sx[161]
  PIN sx[162]
    DIRECTION INPUT ;
    USE SIGNAL ;
    PORT
      LAYER M3 ;
        RECT  31.788 0 31.806 0.037 ;
    END
  END sx[162]
  PIN sx[163]
    DIRECTION INPUT ;
    USE SIGNAL ;
    PORT
      LAYER M3 ;
        RECT  31.86 0 31.878 0.037 ;
    END
  END sx[163]
  PIN sx[164]
    DIRECTION INPUT ;
    USE SIGNAL ;
    PORT
      LAYER M3 ;
        RECT  31.932 0 31.95 0.037 ;
    END
  END sx[164]
  PIN sx[165]
    DIRECTION INPUT ;
    USE SIGNAL ;
    PORT
      LAYER M3 ;
        RECT  32.004 0 32.022 0.037 ;
    END
  END sx[165]
  PIN sx[166]
    DIRECTION INPUT ;
    USE SIGNAL ;
    PORT
      LAYER M3 ;
        RECT  32.076 0 32.094 0.037 ;
    END
  END sx[166]
  PIN sx[167]
    DIRECTION INPUT ;
    USE SIGNAL ;
    PORT
      LAYER M3 ;
        RECT  32.148 0 32.166 0.037 ;
    END
  END sx[167]
  PIN sx[168]
    DIRECTION INPUT ;
    USE SIGNAL ;
    PORT
      LAYER M3 ;
        RECT  32.22 0 32.238 0.037 ;
    END
  END sx[168]
  PIN sx[169]
    DIRECTION INPUT ;
    USE SIGNAL ;
    PORT
      LAYER M3 ;
        RECT  32.292 0 32.31 0.037 ;
    END
  END sx[169]
  PIN sx[16]
    DIRECTION INPUT ;
    USE SIGNAL ;
    PORT
      LAYER M3 ;
        RECT  8.604 0 8.622 0.037 ;
    END
  END sx[16]
  PIN sx[170]
    DIRECTION INPUT ;
    USE SIGNAL ;
    PORT
      LAYER M3 ;
        RECT  32.364 0 32.382 0.037 ;
    END
  END sx[170]
  PIN sx[171]
    DIRECTION INPUT ;
    USE SIGNAL ;
    PORT
      LAYER M3 ;
        RECT  32.436 0 32.454 0.037 ;
    END
  END sx[171]
  PIN sx[172]
    DIRECTION INPUT ;
    USE SIGNAL ;
    PORT
      LAYER M3 ;
        RECT  32.508 0 32.526 0.037 ;
    END
  END sx[172]
  PIN sx[173]
    DIRECTION INPUT ;
    USE SIGNAL ;
    PORT
      LAYER M3 ;
        RECT  32.58 0 32.598 0.037 ;
    END
  END sx[173]
  PIN sx[174]
    DIRECTION INPUT ;
    USE SIGNAL ;
    PORT
      LAYER M3 ;
        RECT  32.652 0 32.67 0.037 ;
    END
  END sx[174]
  PIN sx[175]
    DIRECTION INPUT ;
    USE SIGNAL ;
    PORT
      LAYER M3 ;
        RECT  32.724 0 32.742 0.037 ;
    END
  END sx[175]
  PIN sx[176]
    DIRECTION INPUT ;
    USE SIGNAL ;
    PORT
      LAYER M3 ;
        RECT  32.796 0 32.814 0.037 ;
    END
  END sx[176]
  PIN sx[177]
    DIRECTION INPUT ;
    USE SIGNAL ;
    PORT
      LAYER M3 ;
        RECT  32.868 0 32.886 0.037 ;
    END
  END sx[177]
  PIN sx[178]
    DIRECTION INPUT ;
    USE SIGNAL ;
    PORT
      LAYER M3 ;
        RECT  32.94 0 32.958 0.037 ;
    END
  END sx[178]
  PIN sx[179]
    DIRECTION INPUT ;
    USE SIGNAL ;
    PORT
      LAYER M3 ;
        RECT  33.012 0 33.03 0.037 ;
    END
  END sx[179]
  PIN sx[17]
    DIRECTION INPUT ;
    USE SIGNAL ;
    PORT
      LAYER M3 ;
        RECT  8.676 0 8.694 0.037 ;
    END
  END sx[17]
  PIN sx[180]
    DIRECTION INPUT ;
    USE SIGNAL ;
    PORT
      LAYER M3 ;
        RECT  33.084 0 33.102 0.037 ;
    END
  END sx[180]
  PIN sx[181]
    DIRECTION INPUT ;
    USE SIGNAL ;
    PORT
      LAYER M3 ;
        RECT  33.156 0 33.174 0.037 ;
    END
  END sx[181]
  PIN sx[182]
    DIRECTION INPUT ;
    USE SIGNAL ;
    PORT
      LAYER M3 ;
        RECT  33.228 0 33.246 0.037 ;
    END
  END sx[182]
  PIN sx[183]
    DIRECTION INPUT ;
    USE SIGNAL ;
    PORT
      LAYER M3 ;
        RECT  33.3 0 33.318 0.037 ;
    END
  END sx[183]
  PIN sx[184]
    DIRECTION INPUT ;
    USE SIGNAL ;
    PORT
      LAYER M3 ;
        RECT  33.372 0 33.39 0.037 ;
    END
  END sx[184]
  PIN sx[185]
    DIRECTION INPUT ;
    USE SIGNAL ;
    PORT
      LAYER M3 ;
        RECT  33.444 0 33.462 0.037 ;
    END
  END sx[185]
  PIN sx[186]
    DIRECTION INPUT ;
    USE SIGNAL ;
    PORT
      LAYER M3 ;
        RECT  33.516 0 33.534 0.037 ;
    END
  END sx[186]
  PIN sx[187]
    DIRECTION INPUT ;
    USE SIGNAL ;
    PORT
      LAYER M3 ;
        RECT  33.588 0 33.606 0.037 ;
    END
  END sx[187]
  PIN sx[188]
    DIRECTION INPUT ;
    USE SIGNAL ;
    PORT
      LAYER M3 ;
        RECT  33.66 0 33.678 0.037 ;
    END
  END sx[188]
  PIN sx[189]
    DIRECTION INPUT ;
    USE SIGNAL ;
    PORT
      LAYER M3 ;
        RECT  33.732 0 33.75 0.037 ;
    END
  END sx[189]
  PIN sx[18]
    DIRECTION INPUT ;
    USE SIGNAL ;
    PORT
      LAYER M3 ;
        RECT  8.748 0 8.766 0.037 ;
    END
  END sx[18]
  PIN sx[190]
    DIRECTION INPUT ;
    USE SIGNAL ;
    PORT
      LAYER M3 ;
        RECT  33.804 0 33.822 0.037 ;
    END
  END sx[190]
  PIN sx[191]
    DIRECTION INPUT ;
    USE SIGNAL ;
    PORT
      LAYER M3 ;
        RECT  33.876 0 33.894 0.037 ;
    END
  END sx[191]
  PIN sx[192]
    DIRECTION INPUT ;
    USE SIGNAL ;
    PORT
      LAYER M5 ;
        RECT  73.68 0 73.704 0.084 ;
    END
  END sx[192]
  PIN sx[193]
    DIRECTION INPUT ;
    USE SIGNAL ;
    PORT
      LAYER M5 ;
        RECT  73.776 0 73.8 0.084 ;
    END
  END sx[193]
  PIN sx[194]
    DIRECTION INPUT ;
    USE SIGNAL ;
    PORT
      LAYER M5 ;
        RECT  73.872 0 73.896 0.084 ;
    END
  END sx[194]
  PIN sx[195]
    DIRECTION INPUT ;
    USE SIGNAL ;
    PORT
      LAYER M5 ;
        RECT  73.968 0 73.992 0.084 ;
    END
  END sx[195]
  PIN sx[196]
    DIRECTION INPUT ;
    USE SIGNAL ;
    PORT
      LAYER M5 ;
        RECT  74.064 0 74.088 0.084 ;
    END
  END sx[196]
  PIN sx[197]
    DIRECTION INPUT ;
    USE SIGNAL ;
    PORT
      LAYER M5 ;
        RECT  74.16 0 74.184 0.084 ;
    END
  END sx[197]
  PIN sx[198]
    DIRECTION INPUT ;
    USE SIGNAL ;
    PORT
      LAYER M5 ;
        RECT  74.256 0 74.28 0.084 ;
    END
  END sx[198]
  PIN sx[199]
    DIRECTION INPUT ;
    USE SIGNAL ;
    PORT
      LAYER M5 ;
        RECT  74.352 0 74.376 0.084 ;
    END
  END sx[199]
  PIN sx[19]
    DIRECTION INPUT ;
    USE SIGNAL ;
    PORT
      LAYER M3 ;
        RECT  8.82 0 8.838 0.037 ;
    END
  END sx[19]
  PIN sx[1]
    DIRECTION INPUT ;
    USE SIGNAL ;
    PORT
      LAYER M3 ;
        RECT  7.524 0 7.542 0.037 ;
    END
  END sx[1]
  PIN sx[200]
    DIRECTION INPUT ;
    USE SIGNAL ;
    PORT
      LAYER M5 ;
        RECT  74.448 0 74.472 0.084 ;
    END
  END sx[200]
  PIN sx[201]
    DIRECTION INPUT ;
    USE SIGNAL ;
    PORT
      LAYER M5 ;
        RECT  74.544 0 74.568 0.084 ;
    END
  END sx[201]
  PIN sx[202]
    DIRECTION INPUT ;
    USE SIGNAL ;
    PORT
      LAYER M5 ;
        RECT  74.64 0 74.664 0.084 ;
    END
  END sx[202]
  PIN sx[203]
    DIRECTION INPUT ;
    USE SIGNAL ;
    PORT
      LAYER M5 ;
        RECT  74.736 0 74.76 0.084 ;
    END
  END sx[203]
  PIN sx[204]
    DIRECTION INPUT ;
    USE SIGNAL ;
    PORT
      LAYER M5 ;
        RECT  74.832 0 74.856 0.084 ;
    END
  END sx[204]
  PIN sx[205]
    DIRECTION INPUT ;
    USE SIGNAL ;
    PORT
      LAYER M5 ;
        RECT  74.928 0 74.952 0.084 ;
    END
  END sx[205]
  PIN sx[206]
    DIRECTION INPUT ;
    USE SIGNAL ;
    PORT
      LAYER M5 ;
        RECT  75.024 0 75.048 0.084 ;
    END
  END sx[206]
  PIN sx[207]
    DIRECTION INPUT ;
    USE SIGNAL ;
    PORT
      LAYER M5 ;
        RECT  75.12 0 75.144 0.084 ;
    END
  END sx[207]
  PIN sx[208]
    DIRECTION INPUT ;
    USE SIGNAL ;
    PORT
      LAYER M5 ;
        RECT  75.216 0 75.24 0.084 ;
    END
  END sx[208]
  PIN sx[209]
    DIRECTION INPUT ;
    USE SIGNAL ;
    PORT
      LAYER M5 ;
        RECT  75.312 0 75.336 0.084 ;
    END
  END sx[209]
  PIN sx[20]
    DIRECTION INPUT ;
    USE SIGNAL ;
    PORT
      LAYER M3 ;
        RECT  8.892 0 8.91 0.037 ;
    END
  END sx[20]
  PIN sx[210]
    DIRECTION INPUT ;
    USE SIGNAL ;
    PORT
      LAYER M5 ;
        RECT  75.408 0 75.432 0.084 ;
    END
  END sx[210]
  PIN sx[211]
    DIRECTION INPUT ;
    USE SIGNAL ;
    PORT
      LAYER M5 ;
        RECT  75.504 0 75.528 0.084 ;
    END
  END sx[211]
  PIN sx[212]
    DIRECTION INPUT ;
    USE SIGNAL ;
    PORT
      LAYER M5 ;
        RECT  75.6 0 75.624 0.084 ;
    END
  END sx[212]
  PIN sx[213]
    DIRECTION INPUT ;
    USE SIGNAL ;
    PORT
      LAYER M5 ;
        RECT  75.696 0 75.72 0.084 ;
    END
  END sx[213]
  PIN sx[214]
    DIRECTION INPUT ;
    USE SIGNAL ;
    PORT
      LAYER M5 ;
        RECT  75.792 0 75.816 0.084 ;
    END
  END sx[214]
  PIN sx[215]
    DIRECTION INPUT ;
    USE SIGNAL ;
    PORT
      LAYER M5 ;
        RECT  75.888 0 75.912 0.084 ;
    END
  END sx[215]
  PIN sx[216]
    DIRECTION INPUT ;
    USE SIGNAL ;
    PORT
      LAYER M5 ;
        RECT  75.984 0 76.008 0.084 ;
    END
  END sx[216]
  PIN sx[217]
    DIRECTION INPUT ;
    USE SIGNAL ;
    PORT
      LAYER M5 ;
        RECT  76.08 0 76.104 0.084 ;
    END
  END sx[217]
  PIN sx[218]
    DIRECTION INPUT ;
    USE SIGNAL ;
    PORT
      LAYER M5 ;
        RECT  76.176 0 76.2 0.084 ;
    END
  END sx[218]
  PIN sx[219]
    DIRECTION INPUT ;
    USE SIGNAL ;
    PORT
      LAYER M5 ;
        RECT  76.272 0 76.296 0.084 ;
    END
  END sx[219]
  PIN sx[21]
    DIRECTION INPUT ;
    USE SIGNAL ;
    PORT
      LAYER M3 ;
        RECT  8.964 0 8.982 0.037 ;
    END
  END sx[21]
  PIN sx[220]
    DIRECTION INPUT ;
    USE SIGNAL ;
    PORT
      LAYER M5 ;
        RECT  76.368 0 76.392 0.084 ;
    END
  END sx[220]
  PIN sx[221]
    DIRECTION INPUT ;
    USE SIGNAL ;
    PORT
      LAYER M5 ;
        RECT  76.464 0 76.488 0.084 ;
    END
  END sx[221]
  PIN sx[222]
    DIRECTION INPUT ;
    USE SIGNAL ;
    PORT
      LAYER M5 ;
        RECT  76.56 0 76.584 0.084 ;
    END
  END sx[222]
  PIN sx[223]
    DIRECTION INPUT ;
    USE SIGNAL ;
    PORT
      LAYER M5 ;
        RECT  76.656 0 76.68 0.084 ;
    END
  END sx[223]
  PIN sx[224]
    DIRECTION INPUT ;
    USE SIGNAL ;
    PORT
      LAYER M3 ;
        RECT  33.948 0 33.966 0.037 ;
    END
  END sx[224]
  PIN sx[225]
    DIRECTION INPUT ;
    USE SIGNAL ;
    PORT
      LAYER M3 ;
        RECT  34.02 0 34.038 0.037 ;
    END
  END sx[225]
  PIN sx[226]
    DIRECTION INPUT ;
    USE SIGNAL ;
    PORT
      LAYER M3 ;
        RECT  34.092 0 34.11 0.037 ;
    END
  END sx[226]
  PIN sx[227]
    DIRECTION INPUT ;
    USE SIGNAL ;
    PORT
      LAYER M3 ;
        RECT  34.164 0 34.182 0.037 ;
    END
  END sx[227]
  PIN sx[228]
    DIRECTION INPUT ;
    USE SIGNAL ;
    PORT
      LAYER M3 ;
        RECT  34.236 0 34.254 0.037 ;
    END
  END sx[228]
  PIN sx[229]
    DIRECTION INPUT ;
    USE SIGNAL ;
    PORT
      LAYER M3 ;
        RECT  34.308 0 34.326 0.037 ;
    END
  END sx[229]
  PIN sx[22]
    DIRECTION INPUT ;
    USE SIGNAL ;
    PORT
      LAYER M3 ;
        RECT  9.036 0 9.054 0.037 ;
    END
  END sx[22]
  PIN sx[230]
    DIRECTION INPUT ;
    USE SIGNAL ;
    PORT
      LAYER M3 ;
        RECT  34.38 0 34.398 0.037 ;
    END
  END sx[230]
  PIN sx[231]
    DIRECTION INPUT ;
    USE SIGNAL ;
    PORT
      LAYER M3 ;
        RECT  34.452 0 34.47 0.037 ;
    END
  END sx[231]
  PIN sx[232]
    DIRECTION INPUT ;
    USE SIGNAL ;
    PORT
      LAYER M3 ;
        RECT  34.524 0 34.542 0.037 ;
    END
  END sx[232]
  PIN sx[233]
    DIRECTION INPUT ;
    USE SIGNAL ;
    PORT
      LAYER M3 ;
        RECT  34.596 0 34.614 0.037 ;
    END
  END sx[233]
  PIN sx[234]
    DIRECTION INPUT ;
    USE SIGNAL ;
    PORT
      LAYER M3 ;
        RECT  34.668 0 34.686 0.037 ;
    END
  END sx[234]
  PIN sx[235]
    DIRECTION INPUT ;
    USE SIGNAL ;
    PORT
      LAYER M3 ;
        RECT  34.74 0 34.758 0.037 ;
    END
  END sx[235]
  PIN sx[236]
    DIRECTION INPUT ;
    USE SIGNAL ;
    PORT
      LAYER M3 ;
        RECT  34.812 0 34.83 0.037 ;
    END
  END sx[236]
  PIN sx[237]
    DIRECTION INPUT ;
    USE SIGNAL ;
    PORT
      LAYER M3 ;
        RECT  34.884 0 34.902 0.037 ;
    END
  END sx[237]
  PIN sx[238]
    DIRECTION INPUT ;
    USE SIGNAL ;
    PORT
      LAYER M3 ;
        RECT  34.956 0 34.974 0.037 ;
    END
  END sx[238]
  PIN sx[239]
    DIRECTION INPUT ;
    USE SIGNAL ;
    PORT
      LAYER M3 ;
        RECT  35.028 0 35.046 0.037 ;
    END
  END sx[239]
  PIN sx[23]
    DIRECTION INPUT ;
    USE SIGNAL ;
    PORT
      LAYER M3 ;
        RECT  9.108 0 9.126 0.037 ;
    END
  END sx[23]
  PIN sx[240]
    DIRECTION INPUT ;
    USE SIGNAL ;
    PORT
      LAYER M3 ;
        RECT  35.1 0 35.118 0.037 ;
    END
  END sx[240]
  PIN sx[241]
    DIRECTION INPUT ;
    USE SIGNAL ;
    PORT
      LAYER M3 ;
        RECT  35.172 0 35.19 0.037 ;
    END
  END sx[241]
  PIN sx[242]
    DIRECTION INPUT ;
    USE SIGNAL ;
    PORT
      LAYER M3 ;
        RECT  35.244 0 35.262 0.037 ;
    END
  END sx[242]
  PIN sx[243]
    DIRECTION INPUT ;
    USE SIGNAL ;
    PORT
      LAYER M3 ;
        RECT  35.316 0 35.334 0.037 ;
    END
  END sx[243]
  PIN sx[244]
    DIRECTION INPUT ;
    USE SIGNAL ;
    PORT
      LAYER M3 ;
        RECT  35.388 0 35.406 0.037 ;
    END
  END sx[244]
  PIN sx[245]
    DIRECTION INPUT ;
    USE SIGNAL ;
    PORT
      LAYER M3 ;
        RECT  35.46 0 35.478 0.037 ;
    END
  END sx[245]
  PIN sx[246]
    DIRECTION INPUT ;
    USE SIGNAL ;
    PORT
      LAYER M3 ;
        RECT  35.532 0 35.55 0.037 ;
    END
  END sx[246]
  PIN sx[247]
    DIRECTION INPUT ;
    USE SIGNAL ;
    PORT
      LAYER M3 ;
        RECT  35.604 0 35.622 0.037 ;
    END
  END sx[247]
  PIN sx[248]
    DIRECTION INPUT ;
    USE SIGNAL ;
    PORT
      LAYER M3 ;
        RECT  35.676 0 35.694 0.037 ;
    END
  END sx[248]
  PIN sx[249]
    DIRECTION INPUT ;
    USE SIGNAL ;
    PORT
      LAYER M3 ;
        RECT  35.748 0 35.766 0.037 ;
    END
  END sx[249]
  PIN sx[24]
    DIRECTION INPUT ;
    USE SIGNAL ;
    PORT
      LAYER M3 ;
        RECT  9.18 0 9.198 0.037 ;
    END
  END sx[24]
  PIN sx[250]
    DIRECTION INPUT ;
    USE SIGNAL ;
    PORT
      LAYER M3 ;
        RECT  35.82 0 35.838 0.037 ;
    END
  END sx[250]
  PIN sx[251]
    DIRECTION INPUT ;
    USE SIGNAL ;
    PORT
      LAYER M3 ;
        RECT  35.892 0 35.91 0.037 ;
    END
  END sx[251]
  PIN sx[252]
    DIRECTION INPUT ;
    USE SIGNAL ;
    PORT
      LAYER M3 ;
        RECT  35.964 0 35.982 0.037 ;
    END
  END sx[252]
  PIN sx[253]
    DIRECTION INPUT ;
    USE SIGNAL ;
    PORT
      LAYER M3 ;
        RECT  36.036 0 36.054 0.037 ;
    END
  END sx[253]
  PIN sx[254]
    DIRECTION INPUT ;
    USE SIGNAL ;
    PORT
      LAYER M3 ;
        RECT  36.108 0 36.126 0.037 ;
    END
  END sx[254]
  PIN sx[255]
    DIRECTION INPUT ;
    USE SIGNAL ;
    PORT
      LAYER M3 ;
        RECT  36.18 0 36.198 0.037 ;
    END
  END sx[255]
  PIN sx[256]
    DIRECTION INPUT ;
    USE SIGNAL ;
    PORT
      LAYER M3 ;
        RECT  36.252 0 36.27 0.037 ;
    END
  END sx[256]
  PIN sx[257]
    DIRECTION INPUT ;
    USE SIGNAL ;
    PORT
      LAYER M3 ;
        RECT  36.324 0 36.342 0.037 ;
    END
  END sx[257]
  PIN sx[258]
    DIRECTION INPUT ;
    USE SIGNAL ;
    PORT
      LAYER M3 ;
        RECT  36.396 0 36.414 0.037 ;
    END
  END sx[258]
  PIN sx[259]
    DIRECTION INPUT ;
    USE SIGNAL ;
    PORT
      LAYER M3 ;
        RECT  36.468 0 36.486 0.037 ;
    END
  END sx[259]
  PIN sx[25]
    DIRECTION INPUT ;
    USE SIGNAL ;
    PORT
      LAYER M3 ;
        RECT  9.252 0 9.27 0.037 ;
    END
  END sx[25]
  PIN sx[260]
    DIRECTION INPUT ;
    USE SIGNAL ;
    PORT
      LAYER M3 ;
        RECT  36.54 0 36.558 0.037 ;
    END
  END sx[260]
  PIN sx[261]
    DIRECTION INPUT ;
    USE SIGNAL ;
    PORT
      LAYER M3 ;
        RECT  36.612 0 36.63 0.037 ;
    END
  END sx[261]
  PIN sx[262]
    DIRECTION INPUT ;
    USE SIGNAL ;
    PORT
      LAYER M3 ;
        RECT  36.684 0 36.702 0.037 ;
    END
  END sx[262]
  PIN sx[263]
    DIRECTION INPUT ;
    USE SIGNAL ;
    PORT
      LAYER M3 ;
        RECT  36.756 0 36.774 0.037 ;
    END
  END sx[263]
  PIN sx[264]
    DIRECTION INPUT ;
    USE SIGNAL ;
    PORT
      LAYER M3 ;
        RECT  36.828 0 36.846 0.037 ;
    END
  END sx[264]
  PIN sx[265]
    DIRECTION INPUT ;
    USE SIGNAL ;
    PORT
      LAYER M3 ;
        RECT  36.9 0 36.918 0.037 ;
    END
  END sx[265]
  PIN sx[266]
    DIRECTION INPUT ;
    USE SIGNAL ;
    PORT
      LAYER M3 ;
        RECT  36.972 0 36.99 0.037 ;
    END
  END sx[266]
  PIN sx[267]
    DIRECTION INPUT ;
    USE SIGNAL ;
    PORT
      LAYER M3 ;
        RECT  37.044 0 37.062 0.037 ;
    END
  END sx[267]
  PIN sx[268]
    DIRECTION INPUT ;
    USE SIGNAL ;
    PORT
      LAYER M3 ;
        RECT  37.116 0 37.134 0.037 ;
    END
  END sx[268]
  PIN sx[269]
    DIRECTION INPUT ;
    USE SIGNAL ;
    PORT
      LAYER M3 ;
        RECT  37.188 0 37.206 0.037 ;
    END
  END sx[269]
  PIN sx[26]
    DIRECTION INPUT ;
    USE SIGNAL ;
    PORT
      LAYER M3 ;
        RECT  9.324 0 9.342 0.037 ;
    END
  END sx[26]
  PIN sx[270]
    DIRECTION INPUT ;
    USE SIGNAL ;
    PORT
      LAYER M3 ;
        RECT  37.26 0 37.278 0.037 ;
    END
  END sx[270]
  PIN sx[271]
    DIRECTION INPUT ;
    USE SIGNAL ;
    PORT
      LAYER M3 ;
        RECT  37.332 0 37.35 0.037 ;
    END
  END sx[271]
  PIN sx[272]
    DIRECTION INPUT ;
    USE SIGNAL ;
    PORT
      LAYER M3 ;
        RECT  37.404 0 37.422 0.037 ;
    END
  END sx[272]
  PIN sx[273]
    DIRECTION INPUT ;
    USE SIGNAL ;
    PORT
      LAYER M3 ;
        RECT  37.476 0 37.494 0.037 ;
    END
  END sx[273]
  PIN sx[274]
    DIRECTION INPUT ;
    USE SIGNAL ;
    PORT
      LAYER M3 ;
        RECT  37.548 0 37.566 0.037 ;
    END
  END sx[274]
  PIN sx[275]
    DIRECTION INPUT ;
    USE SIGNAL ;
    PORT
      LAYER M3 ;
        RECT  37.62 0 37.638 0.037 ;
    END
  END sx[275]
  PIN sx[276]
    DIRECTION INPUT ;
    USE SIGNAL ;
    PORT
      LAYER M3 ;
        RECT  37.692 0 37.71 0.037 ;
    END
  END sx[276]
  PIN sx[277]
    DIRECTION INPUT ;
    USE SIGNAL ;
    PORT
      LAYER M3 ;
        RECT  37.764 0 37.782 0.037 ;
    END
  END sx[277]
  PIN sx[278]
    DIRECTION INPUT ;
    USE SIGNAL ;
    PORT
      LAYER M3 ;
        RECT  37.836 0 37.854 0.037 ;
    END
  END sx[278]
  PIN sx[279]
    DIRECTION INPUT ;
    USE SIGNAL ;
    PORT
      LAYER M3 ;
        RECT  37.908 0 37.926 0.037 ;
    END
  END sx[279]
  PIN sx[27]
    DIRECTION INPUT ;
    USE SIGNAL ;
    PORT
      LAYER M3 ;
        RECT  9.396 0 9.414 0.037 ;
    END
  END sx[27]
  PIN sx[280]
    DIRECTION INPUT ;
    USE SIGNAL ;
    PORT
      LAYER M3 ;
        RECT  37.98 0 37.998 0.037 ;
    END
  END sx[280]
  PIN sx[281]
    DIRECTION INPUT ;
    USE SIGNAL ;
    PORT
      LAYER M3 ;
        RECT  38.052 0 38.07 0.037 ;
    END
  END sx[281]
  PIN sx[282]
    DIRECTION INPUT ;
    USE SIGNAL ;
    PORT
      LAYER M3 ;
        RECT  38.124 0 38.142 0.037 ;
    END
  END sx[282]
  PIN sx[283]
    DIRECTION INPUT ;
    USE SIGNAL ;
    PORT
      LAYER M3 ;
        RECT  38.196 0 38.214 0.037 ;
    END
  END sx[283]
  PIN sx[284]
    DIRECTION INPUT ;
    USE SIGNAL ;
    PORT
      LAYER M3 ;
        RECT  38.268 0 38.286 0.037 ;
    END
  END sx[284]
  PIN sx[285]
    DIRECTION INPUT ;
    USE SIGNAL ;
    PORT
      LAYER M3 ;
        RECT  38.34 0 38.358 0.037 ;
    END
  END sx[285]
  PIN sx[286]
    DIRECTION INPUT ;
    USE SIGNAL ;
    PORT
      LAYER M3 ;
        RECT  38.412 0 38.43 0.037 ;
    END
  END sx[286]
  PIN sx[287]
    DIRECTION INPUT ;
    USE SIGNAL ;
    PORT
      LAYER M3 ;
        RECT  38.484 0 38.502 0.037 ;
    END
  END sx[287]
  PIN sx[288]
    DIRECTION INPUT ;
    USE SIGNAL ;
    PORT
      LAYER M5 ;
        RECT  45.264 0 45.288 0.084 ;
    END
  END sx[288]
  PIN sx[289]
    DIRECTION INPUT ;
    USE SIGNAL ;
    PORT
      LAYER M5 ;
        RECT  45.36 0 45.384 0.084 ;
    END
  END sx[289]
  PIN sx[28]
    DIRECTION INPUT ;
    USE SIGNAL ;
    PORT
      LAYER M3 ;
        RECT  9.468 0 9.486 0.037 ;
    END
  END sx[28]
  PIN sx[290]
    DIRECTION INPUT ;
    USE SIGNAL ;
    PORT
      LAYER M5 ;
        RECT  45.456 0 45.48 0.084 ;
    END
  END sx[290]
  PIN sx[291]
    DIRECTION INPUT ;
    USE SIGNAL ;
    PORT
      LAYER M5 ;
        RECT  45.552 0 45.576 0.084 ;
    END
  END sx[291]
  PIN sx[292]
    DIRECTION INPUT ;
    USE SIGNAL ;
    PORT
      LAYER M5 ;
        RECT  45.648 0 45.672 0.084 ;
    END
  END sx[292]
  PIN sx[293]
    DIRECTION INPUT ;
    USE SIGNAL ;
    PORT
      LAYER M5 ;
        RECT  45.744 0 45.768 0.084 ;
    END
  END sx[293]
  PIN sx[294]
    DIRECTION INPUT ;
    USE SIGNAL ;
    PORT
      LAYER M5 ;
        RECT  45.84 0 45.864 0.084 ;
    END
  END sx[294]
  PIN sx[295]
    DIRECTION INPUT ;
    USE SIGNAL ;
    PORT
      LAYER M5 ;
        RECT  45.936 0 45.96 0.084 ;
    END
  END sx[295]
  PIN sx[296]
    DIRECTION INPUT ;
    USE SIGNAL ;
    PORT
      LAYER M5 ;
        RECT  46.032 0 46.056 0.084 ;
    END
  END sx[296]
  PIN sx[297]
    DIRECTION INPUT ;
    USE SIGNAL ;
    PORT
      LAYER M5 ;
        RECT  46.128 0 46.152 0.084 ;
    END
  END sx[297]
  PIN sx[298]
    DIRECTION INPUT ;
    USE SIGNAL ;
    PORT
      LAYER M5 ;
        RECT  46.224 0 46.248 0.084 ;
    END
  END sx[298]
  PIN sx[299]
    DIRECTION INPUT ;
    USE SIGNAL ;
    PORT
      LAYER M5 ;
        RECT  46.32 0 46.344 0.084 ;
    END
  END sx[299]
  PIN sx[29]
    DIRECTION INPUT ;
    USE SIGNAL ;
    PORT
      LAYER M3 ;
        RECT  9.54 0 9.558 0.037 ;
    END
  END sx[29]
  PIN sx[2]
    DIRECTION INPUT ;
    USE SIGNAL ;
    PORT
      LAYER M3 ;
        RECT  7.596 0 7.614 0.037 ;
    END
  END sx[2]
  PIN sx[300]
    DIRECTION INPUT ;
    USE SIGNAL ;
    PORT
      LAYER M5 ;
        RECT  46.416 0 46.44 0.084 ;
    END
  END sx[300]
  PIN sx[301]
    DIRECTION INPUT ;
    USE SIGNAL ;
    PORT
      LAYER M5 ;
        RECT  46.512 0 46.536 0.084 ;
    END
  END sx[301]
  PIN sx[302]
    DIRECTION INPUT ;
    USE SIGNAL ;
    PORT
      LAYER M5 ;
        RECT  46.608 0 46.632 0.084 ;
    END
  END sx[302]
  PIN sx[303]
    DIRECTION INPUT ;
    USE SIGNAL ;
    PORT
      LAYER M5 ;
        RECT  46.704 0 46.728 0.084 ;
    END
  END sx[303]
  PIN sx[304]
    DIRECTION INPUT ;
    USE SIGNAL ;
    PORT
      LAYER M5 ;
        RECT  46.8 0 46.824 0.084 ;
    END
  END sx[304]
  PIN sx[305]
    DIRECTION INPUT ;
    USE SIGNAL ;
    PORT
      LAYER M5 ;
        RECT  46.896 0 46.92 0.084 ;
    END
  END sx[305]
  PIN sx[306]
    DIRECTION INPUT ;
    USE SIGNAL ;
    PORT
      LAYER M5 ;
        RECT  46.992 0 47.016 0.084 ;
    END
  END sx[306]
  PIN sx[307]
    DIRECTION INPUT ;
    USE SIGNAL ;
    PORT
      LAYER M5 ;
        RECT  47.088 0 47.112 0.084 ;
    END
  END sx[307]
  PIN sx[308]
    DIRECTION INPUT ;
    USE SIGNAL ;
    PORT
      LAYER M5 ;
        RECT  47.184 0 47.208 0.084 ;
    END
  END sx[308]
  PIN sx[309]
    DIRECTION INPUT ;
    USE SIGNAL ;
    PORT
      LAYER M5 ;
        RECT  47.28 0 47.304 0.084 ;
    END
  END sx[309]
  PIN sx[30]
    DIRECTION INPUT ;
    USE SIGNAL ;
    PORT
      LAYER M3 ;
        RECT  9.612 0 9.63 0.037 ;
    END
  END sx[30]
  PIN sx[310]
    DIRECTION INPUT ;
    USE SIGNAL ;
    PORT
      LAYER M5 ;
        RECT  47.376 0 47.4 0.084 ;
    END
  END sx[310]
  PIN sx[311]
    DIRECTION INPUT ;
    USE SIGNAL ;
    PORT
      LAYER M5 ;
        RECT  47.472 0 47.496 0.084 ;
    END
  END sx[311]
  PIN sx[312]
    DIRECTION INPUT ;
    USE SIGNAL ;
    PORT
      LAYER M5 ;
        RECT  47.568 0 47.592 0.084 ;
    END
  END sx[312]
  PIN sx[313]
    DIRECTION INPUT ;
    USE SIGNAL ;
    PORT
      LAYER M5 ;
        RECT  47.664 0 47.688 0.084 ;
    END
  END sx[313]
  PIN sx[314]
    DIRECTION INPUT ;
    USE SIGNAL ;
    PORT
      LAYER M5 ;
        RECT  47.76 0 47.784 0.084 ;
    END
  END sx[314]
  PIN sx[315]
    DIRECTION INPUT ;
    USE SIGNAL ;
    PORT
      LAYER M5 ;
        RECT  47.856 0 47.88 0.084 ;
    END
  END sx[315]
  PIN sx[316]
    DIRECTION INPUT ;
    USE SIGNAL ;
    PORT
      LAYER M5 ;
        RECT  47.952 0 47.976 0.084 ;
    END
  END sx[316]
  PIN sx[317]
    DIRECTION INPUT ;
    USE SIGNAL ;
    PORT
      LAYER M5 ;
        RECT  48.048 0 48.072 0.084 ;
    END
  END sx[317]
  PIN sx[318]
    DIRECTION INPUT ;
    USE SIGNAL ;
    PORT
      LAYER M5 ;
        RECT  48.144 0 48.168 0.084 ;
    END
  END sx[318]
  PIN sx[319]
    DIRECTION INPUT ;
    USE SIGNAL ;
    PORT
      LAYER M5 ;
        RECT  48.24 0 48.264 0.084 ;
    END
  END sx[319]
  PIN sx[31]
    DIRECTION INPUT ;
    USE SIGNAL ;
    PORT
      LAYER M3 ;
        RECT  9.684 0 9.702 0.037 ;
    END
  END sx[31]
  PIN sx[320]
    DIRECTION INPUT ;
    USE SIGNAL ;
    PORT
      LAYER M5 ;
        RECT  9.936 0 9.96 0.084 ;
    END
  END sx[320]
  PIN sx[321]
    DIRECTION INPUT ;
    USE SIGNAL ;
    PORT
      LAYER M5 ;
        RECT  10.032 0 10.056 0.084 ;
    END
  END sx[321]
  PIN sx[322]
    DIRECTION INPUT ;
    USE SIGNAL ;
    PORT
      LAYER M5 ;
        RECT  10.128 0 10.152 0.084 ;
    END
  END sx[322]
  PIN sx[323]
    DIRECTION INPUT ;
    USE SIGNAL ;
    PORT
      LAYER M5 ;
        RECT  10.224 0 10.248 0.084 ;
    END
  END sx[323]
  PIN sx[324]
    DIRECTION INPUT ;
    USE SIGNAL ;
    PORT
      LAYER M5 ;
        RECT  10.32 0 10.344 0.084 ;
    END
  END sx[324]
  PIN sx[325]
    DIRECTION INPUT ;
    USE SIGNAL ;
    PORT
      LAYER M5 ;
        RECT  10.416 0 10.44 0.084 ;
    END
  END sx[325]
  PIN sx[326]
    DIRECTION INPUT ;
    USE SIGNAL ;
    PORT
      LAYER M5 ;
        RECT  10.512 0 10.536 0.084 ;
    END
  END sx[326]
  PIN sx[327]
    DIRECTION INPUT ;
    USE SIGNAL ;
    PORT
      LAYER M5 ;
        RECT  10.608 0 10.632 0.084 ;
    END
  END sx[327]
  PIN sx[328]
    DIRECTION INPUT ;
    USE SIGNAL ;
    PORT
      LAYER M5 ;
        RECT  10.704 0 10.728 0.084 ;
    END
  END sx[328]
  PIN sx[329]
    DIRECTION INPUT ;
    USE SIGNAL ;
    PORT
      LAYER M5 ;
        RECT  10.8 0 10.824 0.084 ;
    END
  END sx[329]
  PIN sx[32]
    DIRECTION INPUT ;
    USE SIGNAL ;
    PORT
      LAYER M3 ;
        RECT  24.156 0 24.174 0.037 ;
    END
  END sx[32]
  PIN sx[330]
    DIRECTION INPUT ;
    USE SIGNAL ;
    PORT
      LAYER M5 ;
        RECT  10.896 0 10.92 0.084 ;
    END
  END sx[330]
  PIN sx[331]
    DIRECTION INPUT ;
    USE SIGNAL ;
    PORT
      LAYER M5 ;
        RECT  10.992 0 11.016 0.084 ;
    END
  END sx[331]
  PIN sx[332]
    DIRECTION INPUT ;
    USE SIGNAL ;
    PORT
      LAYER M5 ;
        RECT  11.088 0 11.112 0.084 ;
    END
  END sx[332]
  PIN sx[333]
    DIRECTION INPUT ;
    USE SIGNAL ;
    PORT
      LAYER M5 ;
        RECT  11.184 0 11.208 0.084 ;
    END
  END sx[333]
  PIN sx[334]
    DIRECTION INPUT ;
    USE SIGNAL ;
    PORT
      LAYER M5 ;
        RECT  11.28 0 11.304 0.084 ;
    END
  END sx[334]
  PIN sx[335]
    DIRECTION INPUT ;
    USE SIGNAL ;
    PORT
      LAYER M5 ;
        RECT  11.376 0 11.4 0.084 ;
    END
  END sx[335]
  PIN sx[336]
    DIRECTION INPUT ;
    USE SIGNAL ;
    PORT
      LAYER M5 ;
        RECT  11.472 0 11.496 0.084 ;
    END
  END sx[336]
  PIN sx[337]
    DIRECTION INPUT ;
    USE SIGNAL ;
    PORT
      LAYER M5 ;
        RECT  11.568 0 11.592 0.084 ;
    END
  END sx[337]
  PIN sx[338]
    DIRECTION INPUT ;
    USE SIGNAL ;
    PORT
      LAYER M5 ;
        RECT  11.664 0 11.688 0.084 ;
    END
  END sx[338]
  PIN sx[339]
    DIRECTION INPUT ;
    USE SIGNAL ;
    PORT
      LAYER M5 ;
        RECT  11.76 0 11.784 0.084 ;
    END
  END sx[339]
  PIN sx[33]
    DIRECTION INPUT ;
    USE SIGNAL ;
    PORT
      LAYER M3 ;
        RECT  24.228 0 24.246 0.037 ;
    END
  END sx[33]
  PIN sx[340]
    DIRECTION INPUT ;
    USE SIGNAL ;
    PORT
      LAYER M5 ;
        RECT  11.856 0 11.88 0.084 ;
    END
  END sx[340]
  PIN sx[341]
    DIRECTION INPUT ;
    USE SIGNAL ;
    PORT
      LAYER M5 ;
        RECT  11.952 0 11.976 0.084 ;
    END
  END sx[341]
  PIN sx[342]
    DIRECTION INPUT ;
    USE SIGNAL ;
    PORT
      LAYER M5 ;
        RECT  12.048 0 12.072 0.084 ;
    END
  END sx[342]
  PIN sx[343]
    DIRECTION INPUT ;
    USE SIGNAL ;
    PORT
      LAYER M5 ;
        RECT  12.144 0 12.168 0.084 ;
    END
  END sx[343]
  PIN sx[344]
    DIRECTION INPUT ;
    USE SIGNAL ;
    PORT
      LAYER M5 ;
        RECT  12.24 0 12.264 0.084 ;
    END
  END sx[344]
  PIN sx[345]
    DIRECTION INPUT ;
    USE SIGNAL ;
    PORT
      LAYER M5 ;
        RECT  12.336 0 12.36 0.084 ;
    END
  END sx[345]
  PIN sx[346]
    DIRECTION INPUT ;
    USE SIGNAL ;
    PORT
      LAYER M5 ;
        RECT  12.432 0 12.456 0.084 ;
    END
  END sx[346]
  PIN sx[347]
    DIRECTION INPUT ;
    USE SIGNAL ;
    PORT
      LAYER M5 ;
        RECT  12.528 0 12.552 0.084 ;
    END
  END sx[347]
  PIN sx[348]
    DIRECTION INPUT ;
    USE SIGNAL ;
    PORT
      LAYER M5 ;
        RECT  12.624 0 12.648 0.084 ;
    END
  END sx[348]
  PIN sx[349]
    DIRECTION INPUT ;
    USE SIGNAL ;
    PORT
      LAYER M5 ;
        RECT  12.72 0 12.744 0.084 ;
    END
  END sx[349]
  PIN sx[34]
    DIRECTION INPUT ;
    USE SIGNAL ;
    PORT
      LAYER M3 ;
        RECT  24.3 0 24.318 0.037 ;
    END
  END sx[34]
  PIN sx[350]
    DIRECTION INPUT ;
    USE SIGNAL ;
    PORT
      LAYER M5 ;
        RECT  12.816 0 12.84 0.084 ;
    END
  END sx[350]
  PIN sx[351]
    DIRECTION INPUT ;
    USE SIGNAL ;
    PORT
      LAYER M5 ;
        RECT  12.912 0 12.936 0.084 ;
    END
  END sx[351]
  PIN sx[352]
    DIRECTION INPUT ;
    USE SIGNAL ;
    PORT
      LAYER M3 ;
        RECT  19.548 0 19.566 0.037 ;
    END
  END sx[352]
  PIN sx[353]
    DIRECTION INPUT ;
    USE SIGNAL ;
    PORT
      LAYER M3 ;
        RECT  19.62 0 19.638 0.037 ;
    END
  END sx[353]
  PIN sx[354]
    DIRECTION INPUT ;
    USE SIGNAL ;
    PORT
      LAYER M3 ;
        RECT  19.692 0 19.71 0.037 ;
    END
  END sx[354]
  PIN sx[355]
    DIRECTION INPUT ;
    USE SIGNAL ;
    PORT
      LAYER M3 ;
        RECT  19.764 0 19.782 0.037 ;
    END
  END sx[355]
  PIN sx[356]
    DIRECTION INPUT ;
    USE SIGNAL ;
    PORT
      LAYER M3 ;
        RECT  19.836 0 19.854 0.037 ;
    END
  END sx[356]
  PIN sx[357]
    DIRECTION INPUT ;
    USE SIGNAL ;
    PORT
      LAYER M3 ;
        RECT  19.908 0 19.926 0.037 ;
    END
  END sx[357]
  PIN sx[358]
    DIRECTION INPUT ;
    USE SIGNAL ;
    PORT
      LAYER M3 ;
        RECT  19.98 0 19.998 0.037 ;
    END
  END sx[358]
  PIN sx[359]
    DIRECTION INPUT ;
    USE SIGNAL ;
    PORT
      LAYER M3 ;
        RECT  20.052 0 20.07 0.037 ;
    END
  END sx[359]
  PIN sx[35]
    DIRECTION INPUT ;
    USE SIGNAL ;
    PORT
      LAYER M3 ;
        RECT  24.372 0 24.39 0.037 ;
    END
  END sx[35]
  PIN sx[360]
    DIRECTION INPUT ;
    USE SIGNAL ;
    PORT
      LAYER M3 ;
        RECT  20.124 0 20.142 0.037 ;
    END
  END sx[360]
  PIN sx[361]
    DIRECTION INPUT ;
    USE SIGNAL ;
    PORT
      LAYER M3 ;
        RECT  20.196 0 20.214 0.037 ;
    END
  END sx[361]
  PIN sx[362]
    DIRECTION INPUT ;
    USE SIGNAL ;
    PORT
      LAYER M3 ;
        RECT  20.268 0 20.286 0.037 ;
    END
  END sx[362]
  PIN sx[363]
    DIRECTION INPUT ;
    USE SIGNAL ;
    PORT
      LAYER M3 ;
        RECT  20.34 0 20.358 0.037 ;
    END
  END sx[363]
  PIN sx[364]
    DIRECTION INPUT ;
    USE SIGNAL ;
    PORT
      LAYER M3 ;
        RECT  20.412 0 20.43 0.037 ;
    END
  END sx[364]
  PIN sx[365]
    DIRECTION INPUT ;
    USE SIGNAL ;
    PORT
      LAYER M3 ;
        RECT  20.484 0 20.502 0.037 ;
    END
  END sx[365]
  PIN sx[366]
    DIRECTION INPUT ;
    USE SIGNAL ;
    PORT
      LAYER M3 ;
        RECT  20.556 0 20.574 0.037 ;
    END
  END sx[366]
  PIN sx[367]
    DIRECTION INPUT ;
    USE SIGNAL ;
    PORT
      LAYER M3 ;
        RECT  20.628 0 20.646 0.037 ;
    END
  END sx[367]
  PIN sx[368]
    DIRECTION INPUT ;
    USE SIGNAL ;
    PORT
      LAYER M3 ;
        RECT  20.7 0 20.718 0.037 ;
    END
  END sx[368]
  PIN sx[369]
    DIRECTION INPUT ;
    USE SIGNAL ;
    PORT
      LAYER M3 ;
        RECT  20.772 0 20.79 0.037 ;
    END
  END sx[369]
  PIN sx[36]
    DIRECTION INPUT ;
    USE SIGNAL ;
    PORT
      LAYER M3 ;
        RECT  24.444 0 24.462 0.037 ;
    END
  END sx[36]
  PIN sx[370]
    DIRECTION INPUT ;
    USE SIGNAL ;
    PORT
      LAYER M3 ;
        RECT  20.844 0 20.862 0.037 ;
    END
  END sx[370]
  PIN sx[371]
    DIRECTION INPUT ;
    USE SIGNAL ;
    PORT
      LAYER M3 ;
        RECT  20.916 0 20.934 0.037 ;
    END
  END sx[371]
  PIN sx[372]
    DIRECTION INPUT ;
    USE SIGNAL ;
    PORT
      LAYER M3 ;
        RECT  20.988 0 21.006 0.037 ;
    END
  END sx[372]
  PIN sx[373]
    DIRECTION INPUT ;
    USE SIGNAL ;
    PORT
      LAYER M3 ;
        RECT  21.06 0 21.078 0.037 ;
    END
  END sx[373]
  PIN sx[374]
    DIRECTION INPUT ;
    USE SIGNAL ;
    PORT
      LAYER M3 ;
        RECT  21.132 0 21.15 0.037 ;
    END
  END sx[374]
  PIN sx[375]
    DIRECTION INPUT ;
    USE SIGNAL ;
    PORT
      LAYER M3 ;
        RECT  21.204 0 21.222 0.037 ;
    END
  END sx[375]
  PIN sx[376]
    DIRECTION INPUT ;
    USE SIGNAL ;
    PORT
      LAYER M3 ;
        RECT  21.276 0 21.294 0.037 ;
    END
  END sx[376]
  PIN sx[377]
    DIRECTION INPUT ;
    USE SIGNAL ;
    PORT
      LAYER M3 ;
        RECT  21.348 0 21.366 0.037 ;
    END
  END sx[377]
  PIN sx[378]
    DIRECTION INPUT ;
    USE SIGNAL ;
    PORT
      LAYER M3 ;
        RECT  21.42 0 21.438 0.037 ;
    END
  END sx[378]
  PIN sx[379]
    DIRECTION INPUT ;
    USE SIGNAL ;
    PORT
      LAYER M3 ;
        RECT  21.492 0 21.51 0.037 ;
    END
  END sx[379]
  PIN sx[37]
    DIRECTION INPUT ;
    USE SIGNAL ;
    PORT
      LAYER M3 ;
        RECT  24.516 0 24.534 0.037 ;
    END
  END sx[37]
  PIN sx[380]
    DIRECTION INPUT ;
    USE SIGNAL ;
    PORT
      LAYER M3 ;
        RECT  21.564 0 21.582 0.037 ;
    END
  END sx[380]
  PIN sx[381]
    DIRECTION INPUT ;
    USE SIGNAL ;
    PORT
      LAYER M3 ;
        RECT  21.636 0 21.654 0.037 ;
    END
  END sx[381]
  PIN sx[382]
    DIRECTION INPUT ;
    USE SIGNAL ;
    PORT
      LAYER M3 ;
        RECT  21.708 0 21.726 0.037 ;
    END
  END sx[382]
  PIN sx[383]
    DIRECTION INPUT ;
    USE SIGNAL ;
    PORT
      LAYER M3 ;
        RECT  21.78 0 21.798 0.037 ;
    END
  END sx[383]
  PIN sx[384]
    DIRECTION INPUT ;
    USE SIGNAL ;
    PORT
      LAYER M5 ;
        RECT  67.536 0 67.56 0.084 ;
    END
  END sx[384]
  PIN sx[385]
    DIRECTION INPUT ;
    USE SIGNAL ;
    PORT
      LAYER M5 ;
        RECT  67.632 0 67.656 0.084 ;
    END
  END sx[385]
  PIN sx[386]
    DIRECTION INPUT ;
    USE SIGNAL ;
    PORT
      LAYER M5 ;
        RECT  67.728 0 67.752 0.084 ;
    END
  END sx[386]
  PIN sx[387]
    DIRECTION INPUT ;
    USE SIGNAL ;
    PORT
      LAYER M5 ;
        RECT  67.824 0 67.848 0.084 ;
    END
  END sx[387]
  PIN sx[388]
    DIRECTION INPUT ;
    USE SIGNAL ;
    PORT
      LAYER M5 ;
        RECT  67.92 0 67.944 0.084 ;
    END
  END sx[388]
  PIN sx[389]
    DIRECTION INPUT ;
    USE SIGNAL ;
    PORT
      LAYER M5 ;
        RECT  68.016 0 68.04 0.084 ;
    END
  END sx[389]
  PIN sx[38]
    DIRECTION INPUT ;
    USE SIGNAL ;
    PORT
      LAYER M3 ;
        RECT  24.588 0 24.606 0.037 ;
    END
  END sx[38]
  PIN sx[390]
    DIRECTION INPUT ;
    USE SIGNAL ;
    PORT
      LAYER M5 ;
        RECT  68.112 0 68.136 0.084 ;
    END
  END sx[390]
  PIN sx[391]
    DIRECTION INPUT ;
    USE SIGNAL ;
    PORT
      LAYER M5 ;
        RECT  68.208 0 68.232 0.084 ;
    END
  END sx[391]
  PIN sx[392]
    DIRECTION INPUT ;
    USE SIGNAL ;
    PORT
      LAYER M5 ;
        RECT  68.304 0 68.328 0.084 ;
    END
  END sx[392]
  PIN sx[393]
    DIRECTION INPUT ;
    USE SIGNAL ;
    PORT
      LAYER M5 ;
        RECT  68.4 0 68.424 0.084 ;
    END
  END sx[393]
  PIN sx[394]
    DIRECTION INPUT ;
    USE SIGNAL ;
    PORT
      LAYER M5 ;
        RECT  68.496 0 68.52 0.084 ;
    END
  END sx[394]
  PIN sx[395]
    DIRECTION INPUT ;
    USE SIGNAL ;
    PORT
      LAYER M5 ;
        RECT  68.592 0 68.616 0.084 ;
    END
  END sx[395]
  PIN sx[396]
    DIRECTION INPUT ;
    USE SIGNAL ;
    PORT
      LAYER M5 ;
        RECT  68.688 0 68.712 0.084 ;
    END
  END sx[396]
  PIN sx[397]
    DIRECTION INPUT ;
    USE SIGNAL ;
    PORT
      LAYER M5 ;
        RECT  68.784 0 68.808 0.084 ;
    END
  END sx[397]
  PIN sx[398]
    DIRECTION INPUT ;
    USE SIGNAL ;
    PORT
      LAYER M5 ;
        RECT  68.88 0 68.904 0.084 ;
    END
  END sx[398]
  PIN sx[399]
    DIRECTION INPUT ;
    USE SIGNAL ;
    PORT
      LAYER M5 ;
        RECT  68.976 0 69 0.084 ;
    END
  END sx[399]
  PIN sx[39]
    DIRECTION INPUT ;
    USE SIGNAL ;
    PORT
      LAYER M3 ;
        RECT  24.66 0 24.678 0.037 ;
    END
  END sx[39]
  PIN sx[3]
    DIRECTION INPUT ;
    USE SIGNAL ;
    PORT
      LAYER M3 ;
        RECT  7.668 0 7.686 0.037 ;
    END
  END sx[3]
  PIN sx[400]
    DIRECTION INPUT ;
    USE SIGNAL ;
    PORT
      LAYER M5 ;
        RECT  69.072 0 69.096 0.084 ;
    END
  END sx[400]
  PIN sx[401]
    DIRECTION INPUT ;
    USE SIGNAL ;
    PORT
      LAYER M5 ;
        RECT  69.168 0 69.192 0.084 ;
    END
  END sx[401]
  PIN sx[402]
    DIRECTION INPUT ;
    USE SIGNAL ;
    PORT
      LAYER M5 ;
        RECT  69.264 0 69.288 0.084 ;
    END
  END sx[402]
  PIN sx[403]
    DIRECTION INPUT ;
    USE SIGNAL ;
    PORT
      LAYER M5 ;
        RECT  69.36 0 69.384 0.084 ;
    END
  END sx[403]
  PIN sx[404]
    DIRECTION INPUT ;
    USE SIGNAL ;
    PORT
      LAYER M5 ;
        RECT  69.456 0 69.48 0.084 ;
    END
  END sx[404]
  PIN sx[405]
    DIRECTION INPUT ;
    USE SIGNAL ;
    PORT
      LAYER M5 ;
        RECT  69.552 0 69.576 0.084 ;
    END
  END sx[405]
  PIN sx[406]
    DIRECTION INPUT ;
    USE SIGNAL ;
    PORT
      LAYER M5 ;
        RECT  69.648 0 69.672 0.084 ;
    END
  END sx[406]
  PIN sx[407]
    DIRECTION INPUT ;
    USE SIGNAL ;
    PORT
      LAYER M5 ;
        RECT  69.744 0 69.768 0.084 ;
    END
  END sx[407]
  PIN sx[408]
    DIRECTION INPUT ;
    USE SIGNAL ;
    PORT
      LAYER M5 ;
        RECT  69.84 0 69.864 0.084 ;
    END
  END sx[408]
  PIN sx[409]
    DIRECTION INPUT ;
    USE SIGNAL ;
    PORT
      LAYER M5 ;
        RECT  69.936 0 69.96 0.084 ;
    END
  END sx[409]
  PIN sx[40]
    DIRECTION INPUT ;
    USE SIGNAL ;
    PORT
      LAYER M3 ;
        RECT  24.732 0 24.75 0.037 ;
    END
  END sx[40]
  PIN sx[410]
    DIRECTION INPUT ;
    USE SIGNAL ;
    PORT
      LAYER M5 ;
        RECT  70.032 0 70.056 0.084 ;
    END
  END sx[410]
  PIN sx[411]
    DIRECTION INPUT ;
    USE SIGNAL ;
    PORT
      LAYER M5 ;
        RECT  70.128 0 70.152 0.084 ;
    END
  END sx[411]
  PIN sx[412]
    DIRECTION INPUT ;
    USE SIGNAL ;
    PORT
      LAYER M5 ;
        RECT  70.224 0 70.248 0.084 ;
    END
  END sx[412]
  PIN sx[413]
    DIRECTION INPUT ;
    USE SIGNAL ;
    PORT
      LAYER M5 ;
        RECT  70.32 0 70.344 0.084 ;
    END
  END sx[413]
  PIN sx[414]
    DIRECTION INPUT ;
    USE SIGNAL ;
    PORT
      LAYER M5 ;
        RECT  70.416 0 70.44 0.084 ;
    END
  END sx[414]
  PIN sx[415]
    DIRECTION INPUT ;
    USE SIGNAL ;
    PORT
      LAYER M5 ;
        RECT  70.512 0 70.536 0.084 ;
    END
  END sx[415]
  PIN sx[416]
    DIRECTION INPUT ;
    USE SIGNAL ;
    PORT
      LAYER M3 ;
        RECT  14.94 0 14.958 0.037 ;
    END
  END sx[416]
  PIN sx[417]
    DIRECTION INPUT ;
    USE SIGNAL ;
    PORT
      LAYER M3 ;
        RECT  15.012 0 15.03 0.037 ;
    END
  END sx[417]
  PIN sx[418]
    DIRECTION INPUT ;
    USE SIGNAL ;
    PORT
      LAYER M3 ;
        RECT  15.084 0 15.102 0.037 ;
    END
  END sx[418]
  PIN sx[419]
    DIRECTION INPUT ;
    USE SIGNAL ;
    PORT
      LAYER M3 ;
        RECT  15.156 0 15.174 0.037 ;
    END
  END sx[419]
  PIN sx[41]
    DIRECTION INPUT ;
    USE SIGNAL ;
    PORT
      LAYER M3 ;
        RECT  24.804 0 24.822 0.037 ;
    END
  END sx[41]
  PIN sx[420]
    DIRECTION INPUT ;
    USE SIGNAL ;
    PORT
      LAYER M3 ;
        RECT  15.228 0 15.246 0.037 ;
    END
  END sx[420]
  PIN sx[421]
    DIRECTION INPUT ;
    USE SIGNAL ;
    PORT
      LAYER M3 ;
        RECT  15.3 0 15.318 0.037 ;
    END
  END sx[421]
  PIN sx[422]
    DIRECTION INPUT ;
    USE SIGNAL ;
    PORT
      LAYER M3 ;
        RECT  15.372 0 15.39 0.037 ;
    END
  END sx[422]
  PIN sx[423]
    DIRECTION INPUT ;
    USE SIGNAL ;
    PORT
      LAYER M3 ;
        RECT  15.444 0 15.462 0.037 ;
    END
  END sx[423]
  PIN sx[424]
    DIRECTION INPUT ;
    USE SIGNAL ;
    PORT
      LAYER M3 ;
        RECT  15.516 0 15.534 0.037 ;
    END
  END sx[424]
  PIN sx[425]
    DIRECTION INPUT ;
    USE SIGNAL ;
    PORT
      LAYER M3 ;
        RECT  15.588 0 15.606 0.037 ;
    END
  END sx[425]
  PIN sx[426]
    DIRECTION INPUT ;
    USE SIGNAL ;
    PORT
      LAYER M3 ;
        RECT  15.66 0 15.678 0.037 ;
    END
  END sx[426]
  PIN sx[427]
    DIRECTION INPUT ;
    USE SIGNAL ;
    PORT
      LAYER M3 ;
        RECT  15.732 0 15.75 0.037 ;
    END
  END sx[427]
  PIN sx[428]
    DIRECTION INPUT ;
    USE SIGNAL ;
    PORT
      LAYER M3 ;
        RECT  15.804 0 15.822 0.037 ;
    END
  END sx[428]
  PIN sx[429]
    DIRECTION INPUT ;
    USE SIGNAL ;
    PORT
      LAYER M3 ;
        RECT  15.876 0 15.894 0.037 ;
    END
  END sx[429]
  PIN sx[42]
    DIRECTION INPUT ;
    USE SIGNAL ;
    PORT
      LAYER M3 ;
        RECT  24.876 0 24.894 0.037 ;
    END
  END sx[42]
  PIN sx[430]
    DIRECTION INPUT ;
    USE SIGNAL ;
    PORT
      LAYER M3 ;
        RECT  15.948 0 15.966 0.037 ;
    END
  END sx[430]
  PIN sx[431]
    DIRECTION INPUT ;
    USE SIGNAL ;
    PORT
      LAYER M3 ;
        RECT  16.02 0 16.038 0.037 ;
    END
  END sx[431]
  PIN sx[432]
    DIRECTION INPUT ;
    USE SIGNAL ;
    PORT
      LAYER M3 ;
        RECT  16.092 0 16.11 0.037 ;
    END
  END sx[432]
  PIN sx[433]
    DIRECTION INPUT ;
    USE SIGNAL ;
    PORT
      LAYER M3 ;
        RECT  16.164 0 16.182 0.037 ;
    END
  END sx[433]
  PIN sx[434]
    DIRECTION INPUT ;
    USE SIGNAL ;
    PORT
      LAYER M3 ;
        RECT  16.236 0 16.254 0.037 ;
    END
  END sx[434]
  PIN sx[435]
    DIRECTION INPUT ;
    USE SIGNAL ;
    PORT
      LAYER M3 ;
        RECT  16.308 0 16.326 0.037 ;
    END
  END sx[435]
  PIN sx[436]
    DIRECTION INPUT ;
    USE SIGNAL ;
    PORT
      LAYER M3 ;
        RECT  16.38 0 16.398 0.037 ;
    END
  END sx[436]
  PIN sx[437]
    DIRECTION INPUT ;
    USE SIGNAL ;
    PORT
      LAYER M3 ;
        RECT  16.452 0 16.47 0.037 ;
    END
  END sx[437]
  PIN sx[438]
    DIRECTION INPUT ;
    USE SIGNAL ;
    PORT
      LAYER M3 ;
        RECT  16.524 0 16.542 0.037 ;
    END
  END sx[438]
  PIN sx[439]
    DIRECTION INPUT ;
    USE SIGNAL ;
    PORT
      LAYER M3 ;
        RECT  16.596 0 16.614 0.037 ;
    END
  END sx[439]
  PIN sx[43]
    DIRECTION INPUT ;
    USE SIGNAL ;
    PORT
      LAYER M3 ;
        RECT  24.948 0 24.966 0.037 ;
    END
  END sx[43]
  PIN sx[440]
    DIRECTION INPUT ;
    USE SIGNAL ;
    PORT
      LAYER M3 ;
        RECT  16.668 0 16.686 0.037 ;
    END
  END sx[440]
  PIN sx[441]
    DIRECTION INPUT ;
    USE SIGNAL ;
    PORT
      LAYER M3 ;
        RECT  16.74 0 16.758 0.037 ;
    END
  END sx[441]
  PIN sx[442]
    DIRECTION INPUT ;
    USE SIGNAL ;
    PORT
      LAYER M3 ;
        RECT  16.812 0 16.83 0.037 ;
    END
  END sx[442]
  PIN sx[443]
    DIRECTION INPUT ;
    USE SIGNAL ;
    PORT
      LAYER M3 ;
        RECT  16.884 0 16.902 0.037 ;
    END
  END sx[443]
  PIN sx[444]
    DIRECTION INPUT ;
    USE SIGNAL ;
    PORT
      LAYER M3 ;
        RECT  16.956 0 16.974 0.037 ;
    END
  END sx[444]
  PIN sx[445]
    DIRECTION INPUT ;
    USE SIGNAL ;
    PORT
      LAYER M3 ;
        RECT  17.028 0 17.046 0.037 ;
    END
  END sx[445]
  PIN sx[446]
    DIRECTION INPUT ;
    USE SIGNAL ;
    PORT
      LAYER M3 ;
        RECT  17.1 0 17.118 0.037 ;
    END
  END sx[446]
  PIN sx[447]
    DIRECTION INPUT ;
    USE SIGNAL ;
    PORT
      LAYER M3 ;
        RECT  17.172 0 17.19 0.037 ;
    END
  END sx[447]
  PIN sx[448]
    DIRECTION INPUT ;
    USE SIGNAL ;
    PORT
      LAYER M3 ;
        RECT  60.444 0 60.462 0.037 ;
    END
  END sx[448]
  PIN sx[449]
    DIRECTION INPUT ;
    USE SIGNAL ;
    PORT
      LAYER M3 ;
        RECT  60.516 0 60.534 0.037 ;
    END
  END sx[449]
  PIN sx[44]
    DIRECTION INPUT ;
    USE SIGNAL ;
    PORT
      LAYER M3 ;
        RECT  25.02 0 25.038 0.037 ;
    END
  END sx[44]
  PIN sx[450]
    DIRECTION INPUT ;
    USE SIGNAL ;
    PORT
      LAYER M3 ;
        RECT  60.588 0 60.606 0.037 ;
    END
  END sx[450]
  PIN sx[451]
    DIRECTION INPUT ;
    USE SIGNAL ;
    PORT
      LAYER M3 ;
        RECT  60.66 0 60.678 0.037 ;
    END
  END sx[451]
  PIN sx[452]
    DIRECTION INPUT ;
    USE SIGNAL ;
    PORT
      LAYER M3 ;
        RECT  60.732 0 60.75 0.037 ;
    END
  END sx[452]
  PIN sx[453]
    DIRECTION INPUT ;
    USE SIGNAL ;
    PORT
      LAYER M3 ;
        RECT  60.804 0 60.822 0.037 ;
    END
  END sx[453]
  PIN sx[454]
    DIRECTION INPUT ;
    USE SIGNAL ;
    PORT
      LAYER M3 ;
        RECT  60.876 0 60.894 0.037 ;
    END
  END sx[454]
  PIN sx[455]
    DIRECTION INPUT ;
    USE SIGNAL ;
    PORT
      LAYER M3 ;
        RECT  60.948 0 60.966 0.037 ;
    END
  END sx[455]
  PIN sx[456]
    DIRECTION INPUT ;
    USE SIGNAL ;
    PORT
      LAYER M3 ;
        RECT  61.02 0 61.038 0.037 ;
    END
  END sx[456]
  PIN sx[457]
    DIRECTION INPUT ;
    USE SIGNAL ;
    PORT
      LAYER M3 ;
        RECT  61.092 0 61.11 0.037 ;
    END
  END sx[457]
  PIN sx[458]
    DIRECTION INPUT ;
    USE SIGNAL ;
    PORT
      LAYER M3 ;
        RECT  61.164 0 61.182 0.037 ;
    END
  END sx[458]
  PIN sx[459]
    DIRECTION INPUT ;
    USE SIGNAL ;
    PORT
      LAYER M3 ;
        RECT  61.236 0 61.254 0.037 ;
    END
  END sx[459]
  PIN sx[45]
    DIRECTION INPUT ;
    USE SIGNAL ;
    PORT
      LAYER M3 ;
        RECT  25.092 0 25.11 0.037 ;
    END
  END sx[45]
  PIN sx[460]
    DIRECTION INPUT ;
    USE SIGNAL ;
    PORT
      LAYER M3 ;
        RECT  61.308 0 61.326 0.037 ;
    END
  END sx[460]
  PIN sx[461]
    DIRECTION INPUT ;
    USE SIGNAL ;
    PORT
      LAYER M3 ;
        RECT  61.38 0 61.398 0.037 ;
    END
  END sx[461]
  PIN sx[462]
    DIRECTION INPUT ;
    USE SIGNAL ;
    PORT
      LAYER M3 ;
        RECT  61.452 0 61.47 0.037 ;
    END
  END sx[462]
  PIN sx[463]
    DIRECTION INPUT ;
    USE SIGNAL ;
    PORT
      LAYER M3 ;
        RECT  61.524 0 61.542 0.037 ;
    END
  END sx[463]
  PIN sx[464]
    DIRECTION INPUT ;
    USE SIGNAL ;
    PORT
      LAYER M3 ;
        RECT  61.596 0 61.614 0.037 ;
    END
  END sx[464]
  PIN sx[465]
    DIRECTION INPUT ;
    USE SIGNAL ;
    PORT
      LAYER M3 ;
        RECT  61.668 0 61.686 0.037 ;
    END
  END sx[465]
  PIN sx[466]
    DIRECTION INPUT ;
    USE SIGNAL ;
    PORT
      LAYER M3 ;
        RECT  61.74 0 61.758 0.037 ;
    END
  END sx[466]
  PIN sx[467]
    DIRECTION INPUT ;
    USE SIGNAL ;
    PORT
      LAYER M3 ;
        RECT  61.812 0 61.83 0.037 ;
    END
  END sx[467]
  PIN sx[468]
    DIRECTION INPUT ;
    USE SIGNAL ;
    PORT
      LAYER M3 ;
        RECT  61.884 0 61.902 0.037 ;
    END
  END sx[468]
  PIN sx[469]
    DIRECTION INPUT ;
    USE SIGNAL ;
    PORT
      LAYER M3 ;
        RECT  61.956 0 61.974 0.037 ;
    END
  END sx[469]
  PIN sx[46]
    DIRECTION INPUT ;
    USE SIGNAL ;
    PORT
      LAYER M3 ;
        RECT  25.164 0 25.182 0.037 ;
    END
  END sx[46]
  PIN sx[470]
    DIRECTION INPUT ;
    USE SIGNAL ;
    PORT
      LAYER M3 ;
        RECT  62.028 0 62.046 0.037 ;
    END
  END sx[470]
  PIN sx[471]
    DIRECTION INPUT ;
    USE SIGNAL ;
    PORT
      LAYER M3 ;
        RECT  62.1 0 62.118 0.037 ;
    END
  END sx[471]
  PIN sx[472]
    DIRECTION INPUT ;
    USE SIGNAL ;
    PORT
      LAYER M3 ;
        RECT  62.172 0 62.19 0.037 ;
    END
  END sx[472]
  PIN sx[473]
    DIRECTION INPUT ;
    USE SIGNAL ;
    PORT
      LAYER M3 ;
        RECT  62.244 0 62.262 0.037 ;
    END
  END sx[473]
  PIN sx[474]
    DIRECTION INPUT ;
    USE SIGNAL ;
    PORT
      LAYER M3 ;
        RECT  62.316 0 62.334 0.037 ;
    END
  END sx[474]
  PIN sx[475]
    DIRECTION INPUT ;
    USE SIGNAL ;
    PORT
      LAYER M3 ;
        RECT  62.388 0 62.406 0.037 ;
    END
  END sx[475]
  PIN sx[476]
    DIRECTION INPUT ;
    USE SIGNAL ;
    PORT
      LAYER M3 ;
        RECT  62.46 0 62.478 0.037 ;
    END
  END sx[476]
  PIN sx[477]
    DIRECTION INPUT ;
    USE SIGNAL ;
    PORT
      LAYER M3 ;
        RECT  62.532 0 62.55 0.037 ;
    END
  END sx[477]
  PIN sx[478]
    DIRECTION INPUT ;
    USE SIGNAL ;
    PORT
      LAYER M3 ;
        RECT  62.604 0 62.622 0.037 ;
    END
  END sx[478]
  PIN sx[479]
    DIRECTION INPUT ;
    USE SIGNAL ;
    PORT
      LAYER M3 ;
        RECT  62.676 0 62.694 0.037 ;
    END
  END sx[479]
  PIN sx[47]
    DIRECTION INPUT ;
    USE SIGNAL ;
    PORT
      LAYER M3 ;
        RECT  25.236 0 25.254 0.037 ;
    END
  END sx[47]
  PIN sx[480]
    DIRECTION INPUT ;
    USE SIGNAL ;
    PORT
      LAYER M3 ;
        RECT  40.86 0 40.878 0.037 ;
    END
  END sx[480]
  PIN sx[481]
    DIRECTION INPUT ;
    USE SIGNAL ;
    PORT
      LAYER M3 ;
        RECT  40.932 0 40.95 0.037 ;
    END
  END sx[481]
  PIN sx[482]
    DIRECTION INPUT ;
    USE SIGNAL ;
    PORT
      LAYER M3 ;
        RECT  41.004 0 41.022 0.037 ;
    END
  END sx[482]
  PIN sx[483]
    DIRECTION INPUT ;
    USE SIGNAL ;
    PORT
      LAYER M3 ;
        RECT  41.076 0 41.094 0.037 ;
    END
  END sx[483]
  PIN sx[484]
    DIRECTION INPUT ;
    USE SIGNAL ;
    PORT
      LAYER M3 ;
        RECT  41.148 0 41.166 0.037 ;
    END
  END sx[484]
  PIN sx[485]
    DIRECTION INPUT ;
    USE SIGNAL ;
    PORT
      LAYER M3 ;
        RECT  41.22 0 41.238 0.037 ;
    END
  END sx[485]
  PIN sx[486]
    DIRECTION INPUT ;
    USE SIGNAL ;
    PORT
      LAYER M3 ;
        RECT  41.292 0 41.31 0.037 ;
    END
  END sx[486]
  PIN sx[487]
    DIRECTION INPUT ;
    USE SIGNAL ;
    PORT
      LAYER M3 ;
        RECT  41.364 0 41.382 0.037 ;
    END
  END sx[487]
  PIN sx[488]
    DIRECTION INPUT ;
    USE SIGNAL ;
    PORT
      LAYER M3 ;
        RECT  41.436 0 41.454 0.037 ;
    END
  END sx[488]
  PIN sx[489]
    DIRECTION INPUT ;
    USE SIGNAL ;
    PORT
      LAYER M3 ;
        RECT  41.508 0 41.526 0.037 ;
    END
  END sx[489]
  PIN sx[48]
    DIRECTION INPUT ;
    USE SIGNAL ;
    PORT
      LAYER M3 ;
        RECT  25.308 0 25.326 0.037 ;
    END
  END sx[48]
  PIN sx[490]
    DIRECTION INPUT ;
    USE SIGNAL ;
    PORT
      LAYER M3 ;
        RECT  41.58 0 41.598 0.037 ;
    END
  END sx[490]
  PIN sx[491]
    DIRECTION INPUT ;
    USE SIGNAL ;
    PORT
      LAYER M3 ;
        RECT  41.652 0 41.67 0.037 ;
    END
  END sx[491]
  PIN sx[492]
    DIRECTION INPUT ;
    USE SIGNAL ;
    PORT
      LAYER M3 ;
        RECT  41.724 0 41.742 0.037 ;
    END
  END sx[492]
  PIN sx[493]
    DIRECTION INPUT ;
    USE SIGNAL ;
    PORT
      LAYER M3 ;
        RECT  41.796 0 41.814 0.037 ;
    END
  END sx[493]
  PIN sx[494]
    DIRECTION INPUT ;
    USE SIGNAL ;
    PORT
      LAYER M3 ;
        RECT  41.868 0 41.886 0.037 ;
    END
  END sx[494]
  PIN sx[495]
    DIRECTION INPUT ;
    USE SIGNAL ;
    PORT
      LAYER M3 ;
        RECT  41.94 0 41.958 0.037 ;
    END
  END sx[495]
  PIN sx[496]
    DIRECTION INPUT ;
    USE SIGNAL ;
    PORT
      LAYER M3 ;
        RECT  42.012 0 42.03 0.037 ;
    END
  END sx[496]
  PIN sx[497]
    DIRECTION INPUT ;
    USE SIGNAL ;
    PORT
      LAYER M3 ;
        RECT  42.084 0 42.102 0.037 ;
    END
  END sx[497]
  PIN sx[498]
    DIRECTION INPUT ;
    USE SIGNAL ;
    PORT
      LAYER M3 ;
        RECT  42.156 0 42.174 0.037 ;
    END
  END sx[498]
  PIN sx[499]
    DIRECTION INPUT ;
    USE SIGNAL ;
    PORT
      LAYER M3 ;
        RECT  42.228 0 42.246 0.037 ;
    END
  END sx[499]
  PIN sx[49]
    DIRECTION INPUT ;
    USE SIGNAL ;
    PORT
      LAYER M3 ;
        RECT  25.38 0 25.398 0.037 ;
    END
  END sx[49]
  PIN sx[4]
    DIRECTION INPUT ;
    USE SIGNAL ;
    PORT
      LAYER M3 ;
        RECT  7.74 0 7.758 0.037 ;
    END
  END sx[4]
  PIN sx[500]
    DIRECTION INPUT ;
    USE SIGNAL ;
    PORT
      LAYER M3 ;
        RECT  42.3 0 42.318 0.037 ;
    END
  END sx[500]
  PIN sx[501]
    DIRECTION INPUT ;
    USE SIGNAL ;
    PORT
      LAYER M3 ;
        RECT  42.372 0 42.39 0.037 ;
    END
  END sx[501]
  PIN sx[502]
    DIRECTION INPUT ;
    USE SIGNAL ;
    PORT
      LAYER M3 ;
        RECT  42.444 0 42.462 0.037 ;
    END
  END sx[502]
  PIN sx[503]
    DIRECTION INPUT ;
    USE SIGNAL ;
    PORT
      LAYER M3 ;
        RECT  42.516 0 42.534 0.037 ;
    END
  END sx[503]
  PIN sx[504]
    DIRECTION INPUT ;
    USE SIGNAL ;
    PORT
      LAYER M3 ;
        RECT  42.588 0 42.606 0.037 ;
    END
  END sx[504]
  PIN sx[505]
    DIRECTION INPUT ;
    USE SIGNAL ;
    PORT
      LAYER M3 ;
        RECT  42.66 0 42.678 0.037 ;
    END
  END sx[505]
  PIN sx[506]
    DIRECTION INPUT ;
    USE SIGNAL ;
    PORT
      LAYER M3 ;
        RECT  42.732 0 42.75 0.037 ;
    END
  END sx[506]
  PIN sx[507]
    DIRECTION INPUT ;
    USE SIGNAL ;
    PORT
      LAYER M3 ;
        RECT  42.804 0 42.822 0.037 ;
    END
  END sx[507]
  PIN sx[508]
    DIRECTION INPUT ;
    USE SIGNAL ;
    PORT
      LAYER M3 ;
        RECT  42.876 0 42.894 0.037 ;
    END
  END sx[508]
  PIN sx[509]
    DIRECTION INPUT ;
    USE SIGNAL ;
    PORT
      LAYER M3 ;
        RECT  42.948 0 42.966 0.037 ;
    END
  END sx[509]
  PIN sx[50]
    DIRECTION INPUT ;
    USE SIGNAL ;
    PORT
      LAYER M3 ;
        RECT  25.452 0 25.47 0.037 ;
    END
  END sx[50]
  PIN sx[510]
    DIRECTION INPUT ;
    USE SIGNAL ;
    PORT
      LAYER M3 ;
        RECT  43.02 0 43.038 0.037 ;
    END
  END sx[510]
  PIN sx[511]
    DIRECTION INPUT ;
    USE SIGNAL ;
    PORT
      LAYER M3 ;
        RECT  43.092 0 43.11 0.037 ;
    END
  END sx[511]
  PIN sx[512]
    DIRECTION INPUT ;
    USE SIGNAL ;
    PORT
      LAYER M3 ;
        RECT  62.748 0 62.766 0.037 ;
    END
  END sx[512]
  PIN sx[513]
    DIRECTION INPUT ;
    USE SIGNAL ;
    PORT
      LAYER M3 ;
        RECT  62.82 0 62.838 0.037 ;
    END
  END sx[513]
  PIN sx[514]
    DIRECTION INPUT ;
    USE SIGNAL ;
    PORT
      LAYER M3 ;
        RECT  62.892 0 62.91 0.037 ;
    END
  END sx[514]
  PIN sx[515]
    DIRECTION INPUT ;
    USE SIGNAL ;
    PORT
      LAYER M3 ;
        RECT  62.964 0 62.982 0.037 ;
    END
  END sx[515]
  PIN sx[516]
    DIRECTION INPUT ;
    USE SIGNAL ;
    PORT
      LAYER M3 ;
        RECT  63.036 0 63.054 0.037 ;
    END
  END sx[516]
  PIN sx[517]
    DIRECTION INPUT ;
    USE SIGNAL ;
    PORT
      LAYER M3 ;
        RECT  63.108 0 63.126 0.037 ;
    END
  END sx[517]
  PIN sx[518]
    DIRECTION INPUT ;
    USE SIGNAL ;
    PORT
      LAYER M3 ;
        RECT  63.18 0 63.198 0.037 ;
    END
  END sx[518]
  PIN sx[519]
    DIRECTION INPUT ;
    USE SIGNAL ;
    PORT
      LAYER M3 ;
        RECT  63.252 0 63.27 0.037 ;
    END
  END sx[519]
  PIN sx[51]
    DIRECTION INPUT ;
    USE SIGNAL ;
    PORT
      LAYER M3 ;
        RECT  25.524 0 25.542 0.037 ;
    END
  END sx[51]
  PIN sx[520]
    DIRECTION INPUT ;
    USE SIGNAL ;
    PORT
      LAYER M3 ;
        RECT  63.324 0 63.342 0.037 ;
    END
  END sx[520]
  PIN sx[521]
    DIRECTION INPUT ;
    USE SIGNAL ;
    PORT
      LAYER M3 ;
        RECT  63.396 0 63.414 0.037 ;
    END
  END sx[521]
  PIN sx[522]
    DIRECTION INPUT ;
    USE SIGNAL ;
    PORT
      LAYER M3 ;
        RECT  63.468 0 63.486 0.037 ;
    END
  END sx[522]
  PIN sx[523]
    DIRECTION INPUT ;
    USE SIGNAL ;
    PORT
      LAYER M3 ;
        RECT  63.54 0 63.558 0.037 ;
    END
  END sx[523]
  PIN sx[524]
    DIRECTION INPUT ;
    USE SIGNAL ;
    PORT
      LAYER M3 ;
        RECT  63.612 0 63.63 0.037 ;
    END
  END sx[524]
  PIN sx[525]
    DIRECTION INPUT ;
    USE SIGNAL ;
    PORT
      LAYER M3 ;
        RECT  63.684 0 63.702 0.037 ;
    END
  END sx[525]
  PIN sx[526]
    DIRECTION INPUT ;
    USE SIGNAL ;
    PORT
      LAYER M3 ;
        RECT  63.756 0 63.774 0.037 ;
    END
  END sx[526]
  PIN sx[527]
    DIRECTION INPUT ;
    USE SIGNAL ;
    PORT
      LAYER M3 ;
        RECT  63.828 0 63.846 0.037 ;
    END
  END sx[527]
  PIN sx[528]
    DIRECTION INPUT ;
    USE SIGNAL ;
    PORT
      LAYER M3 ;
        RECT  63.9 0 63.918 0.037 ;
    END
  END sx[528]
  PIN sx[529]
    DIRECTION INPUT ;
    USE SIGNAL ;
    PORT
      LAYER M3 ;
        RECT  63.972 0 63.99 0.037 ;
    END
  END sx[529]
  PIN sx[52]
    DIRECTION INPUT ;
    USE SIGNAL ;
    PORT
      LAYER M3 ;
        RECT  25.596 0 25.614 0.037 ;
    END
  END sx[52]
  PIN sx[530]
    DIRECTION INPUT ;
    USE SIGNAL ;
    PORT
      LAYER M3 ;
        RECT  64.044 0 64.062 0.037 ;
    END
  END sx[530]
  PIN sx[531]
    DIRECTION INPUT ;
    USE SIGNAL ;
    PORT
      LAYER M3 ;
        RECT  64.116 0 64.134 0.037 ;
    END
  END sx[531]
  PIN sx[532]
    DIRECTION INPUT ;
    USE SIGNAL ;
    PORT
      LAYER M3 ;
        RECT  64.188 0 64.206 0.037 ;
    END
  END sx[532]
  PIN sx[533]
    DIRECTION INPUT ;
    USE SIGNAL ;
    PORT
      LAYER M3 ;
        RECT  64.26 0 64.278 0.037 ;
    END
  END sx[533]
  PIN sx[534]
    DIRECTION INPUT ;
    USE SIGNAL ;
    PORT
      LAYER M3 ;
        RECT  64.332 0 64.35 0.037 ;
    END
  END sx[534]
  PIN sx[535]
    DIRECTION INPUT ;
    USE SIGNAL ;
    PORT
      LAYER M3 ;
        RECT  64.404 0 64.422 0.037 ;
    END
  END sx[535]
  PIN sx[536]
    DIRECTION INPUT ;
    USE SIGNAL ;
    PORT
      LAYER M3 ;
        RECT  64.476 0 64.494 0.037 ;
    END
  END sx[536]
  PIN sx[537]
    DIRECTION INPUT ;
    USE SIGNAL ;
    PORT
      LAYER M3 ;
        RECT  64.548 0 64.566 0.037 ;
    END
  END sx[537]
  PIN sx[538]
    DIRECTION INPUT ;
    USE SIGNAL ;
    PORT
      LAYER M3 ;
        RECT  64.62 0 64.638 0.037 ;
    END
  END sx[538]
  PIN sx[539]
    DIRECTION INPUT ;
    USE SIGNAL ;
    PORT
      LAYER M3 ;
        RECT  64.692 0 64.71 0.037 ;
    END
  END sx[539]
  PIN sx[53]
    DIRECTION INPUT ;
    USE SIGNAL ;
    PORT
      LAYER M3 ;
        RECT  25.668 0 25.686 0.037 ;
    END
  END sx[53]
  PIN sx[540]
    DIRECTION INPUT ;
    USE SIGNAL ;
    PORT
      LAYER M3 ;
        RECT  64.764 0 64.782 0.037 ;
    END
  END sx[540]
  PIN sx[541]
    DIRECTION INPUT ;
    USE SIGNAL ;
    PORT
      LAYER M3 ;
        RECT  64.836 0 64.854 0.037 ;
    END
  END sx[541]
  PIN sx[542]
    DIRECTION INPUT ;
    USE SIGNAL ;
    PORT
      LAYER M3 ;
        RECT  64.908 0 64.926 0.037 ;
    END
  END sx[542]
  PIN sx[543]
    DIRECTION INPUT ;
    USE SIGNAL ;
    PORT
      LAYER M3 ;
        RECT  64.98 0 64.998 0.037 ;
    END
  END sx[543]
  PIN sx[544]
    DIRECTION INPUT ;
    USE SIGNAL ;
    PORT
      LAYER M3 ;
        RECT  79.452 0 79.47 0.037 ;
    END
  END sx[544]
  PIN sx[545]
    DIRECTION INPUT ;
    USE SIGNAL ;
    PORT
      LAYER M3 ;
        RECT  79.524 0 79.542 0.037 ;
    END
  END sx[545]
  PIN sx[546]
    DIRECTION INPUT ;
    USE SIGNAL ;
    PORT
      LAYER M3 ;
        RECT  79.596 0 79.614 0.037 ;
    END
  END sx[546]
  PIN sx[547]
    DIRECTION INPUT ;
    USE SIGNAL ;
    PORT
      LAYER M3 ;
        RECT  79.668 0 79.686 0.037 ;
    END
  END sx[547]
  PIN sx[548]
    DIRECTION INPUT ;
    USE SIGNAL ;
    PORT
      LAYER M3 ;
        RECT  79.74 0 79.758 0.037 ;
    END
  END sx[548]
  PIN sx[549]
    DIRECTION INPUT ;
    USE SIGNAL ;
    PORT
      LAYER M3 ;
        RECT  79.812 0 79.83 0.037 ;
    END
  END sx[549]
  PIN sx[54]
    DIRECTION INPUT ;
    USE SIGNAL ;
    PORT
      LAYER M3 ;
        RECT  25.74 0 25.758 0.037 ;
    END
  END sx[54]
  PIN sx[550]
    DIRECTION INPUT ;
    USE SIGNAL ;
    PORT
      LAYER M3 ;
        RECT  79.884 0 79.902 0.037 ;
    END
  END sx[550]
  PIN sx[551]
    DIRECTION INPUT ;
    USE SIGNAL ;
    PORT
      LAYER M3 ;
        RECT  79.956 0 79.974 0.037 ;
    END
  END sx[551]
  PIN sx[552]
    DIRECTION INPUT ;
    USE SIGNAL ;
    PORT
      LAYER M3 ;
        RECT  80.028 0 80.046 0.037 ;
    END
  END sx[552]
  PIN sx[553]
    DIRECTION INPUT ;
    USE SIGNAL ;
    PORT
      LAYER M3 ;
        RECT  80.1 0 80.118 0.037 ;
    END
  END sx[553]
  PIN sx[554]
    DIRECTION INPUT ;
    USE SIGNAL ;
    PORT
      LAYER M3 ;
        RECT  80.172 0 80.19 0.037 ;
    END
  END sx[554]
  PIN sx[555]
    DIRECTION INPUT ;
    USE SIGNAL ;
    PORT
      LAYER M3 ;
        RECT  80.244 0 80.262 0.037 ;
    END
  END sx[555]
  PIN sx[556]
    DIRECTION INPUT ;
    USE SIGNAL ;
    PORT
      LAYER M3 ;
        RECT  80.316 0 80.334 0.037 ;
    END
  END sx[556]
  PIN sx[557]
    DIRECTION INPUT ;
    USE SIGNAL ;
    PORT
      LAYER M3 ;
        RECT  80.388 0 80.406 0.037 ;
    END
  END sx[557]
  PIN sx[558]
    DIRECTION INPUT ;
    USE SIGNAL ;
    PORT
      LAYER M3 ;
        RECT  80.46 0 80.478 0.037 ;
    END
  END sx[558]
  PIN sx[559]
    DIRECTION INPUT ;
    USE SIGNAL ;
    PORT
      LAYER M3 ;
        RECT  80.532 0 80.55 0.037 ;
    END
  END sx[559]
  PIN sx[55]
    DIRECTION INPUT ;
    USE SIGNAL ;
    PORT
      LAYER M3 ;
        RECT  25.812 0 25.83 0.037 ;
    END
  END sx[55]
  PIN sx[560]
    DIRECTION INPUT ;
    USE SIGNAL ;
    PORT
      LAYER M3 ;
        RECT  80.604 0 80.622 0.037 ;
    END
  END sx[560]
  PIN sx[561]
    DIRECTION INPUT ;
    USE SIGNAL ;
    PORT
      LAYER M3 ;
        RECT  80.676 0 80.694 0.037 ;
    END
  END sx[561]
  PIN sx[562]
    DIRECTION INPUT ;
    USE SIGNAL ;
    PORT
      LAYER M3 ;
        RECT  80.748 0 80.766 0.037 ;
    END
  END sx[562]
  PIN sx[563]
    DIRECTION INPUT ;
    USE SIGNAL ;
    PORT
      LAYER M3 ;
        RECT  80.82 0 80.838 0.037 ;
    END
  END sx[563]
  PIN sx[564]
    DIRECTION INPUT ;
    USE SIGNAL ;
    PORT
      LAYER M3 ;
        RECT  80.892 0 80.91 0.037 ;
    END
  END sx[564]
  PIN sx[565]
    DIRECTION INPUT ;
    USE SIGNAL ;
    PORT
      LAYER M3 ;
        RECT  80.964 0 80.982 0.037 ;
    END
  END sx[565]
  PIN sx[566]
    DIRECTION INPUT ;
    USE SIGNAL ;
    PORT
      LAYER M3 ;
        RECT  81.036 0 81.054 0.037 ;
    END
  END sx[566]
  PIN sx[567]
    DIRECTION INPUT ;
    USE SIGNAL ;
    PORT
      LAYER M3 ;
        RECT  81.108 0 81.126 0.037 ;
    END
  END sx[567]
  PIN sx[568]
    DIRECTION INPUT ;
    USE SIGNAL ;
    PORT
      LAYER M3 ;
        RECT  81.18 0 81.198 0.037 ;
    END
  END sx[568]
  PIN sx[569]
    DIRECTION INPUT ;
    USE SIGNAL ;
    PORT
      LAYER M3 ;
        RECT  81.252 0 81.27 0.037 ;
    END
  END sx[569]
  PIN sx[56]
    DIRECTION INPUT ;
    USE SIGNAL ;
    PORT
      LAYER M3 ;
        RECT  25.884 0 25.902 0.037 ;
    END
  END sx[56]
  PIN sx[570]
    DIRECTION INPUT ;
    USE SIGNAL ;
    PORT
      LAYER M3 ;
        RECT  81.324 0 81.342 0.037 ;
    END
  END sx[570]
  PIN sx[571]
    DIRECTION INPUT ;
    USE SIGNAL ;
    PORT
      LAYER M3 ;
        RECT  81.396 0 81.414 0.037 ;
    END
  END sx[571]
  PIN sx[572]
    DIRECTION INPUT ;
    USE SIGNAL ;
    PORT
      LAYER M3 ;
        RECT  81.468 0 81.486 0.037 ;
    END
  END sx[572]
  PIN sx[573]
    DIRECTION INPUT ;
    USE SIGNAL ;
    PORT
      LAYER M3 ;
        RECT  81.54 0 81.558 0.037 ;
    END
  END sx[573]
  PIN sx[574]
    DIRECTION INPUT ;
    USE SIGNAL ;
    PORT
      LAYER M3 ;
        RECT  81.612 0 81.63 0.037 ;
    END
  END sx[574]
  PIN sx[575]
    DIRECTION INPUT ;
    USE SIGNAL ;
    PORT
      LAYER M3 ;
        RECT  81.684 0 81.702 0.037 ;
    END
  END sx[575]
  PIN sx[576]
    DIRECTION INPUT ;
    USE SIGNAL ;
    PORT
      LAYER M3 ;
        RECT  74.844 0 74.862 0.037 ;
    END
  END sx[576]
  PIN sx[577]
    DIRECTION INPUT ;
    USE SIGNAL ;
    PORT
      LAYER M3 ;
        RECT  74.916 0 74.934 0.037 ;
    END
  END sx[577]
  PIN sx[578]
    DIRECTION INPUT ;
    USE SIGNAL ;
    PORT
      LAYER M3 ;
        RECT  74.988 0 75.006 0.037 ;
    END
  END sx[578]
  PIN sx[579]
    DIRECTION INPUT ;
    USE SIGNAL ;
    PORT
      LAYER M3 ;
        RECT  75.06 0 75.078 0.037 ;
    END
  END sx[579]
  PIN sx[57]
    DIRECTION INPUT ;
    USE SIGNAL ;
    PORT
      LAYER M3 ;
        RECT  25.956 0 25.974 0.037 ;
    END
  END sx[57]
  PIN sx[580]
    DIRECTION INPUT ;
    USE SIGNAL ;
    PORT
      LAYER M3 ;
        RECT  75.132 0 75.15 0.037 ;
    END
  END sx[580]
  PIN sx[581]
    DIRECTION INPUT ;
    USE SIGNAL ;
    PORT
      LAYER M3 ;
        RECT  75.204 0 75.222 0.037 ;
    END
  END sx[581]
  PIN sx[582]
    DIRECTION INPUT ;
    USE SIGNAL ;
    PORT
      LAYER M3 ;
        RECT  75.276 0 75.294 0.037 ;
    END
  END sx[582]
  PIN sx[583]
    DIRECTION INPUT ;
    USE SIGNAL ;
    PORT
      LAYER M3 ;
        RECT  75.348 0 75.366 0.037 ;
    END
  END sx[583]
  PIN sx[584]
    DIRECTION INPUT ;
    USE SIGNAL ;
    PORT
      LAYER M3 ;
        RECT  75.42 0 75.438 0.037 ;
    END
  END sx[584]
  PIN sx[585]
    DIRECTION INPUT ;
    USE SIGNAL ;
    PORT
      LAYER M3 ;
        RECT  75.492 0 75.51 0.037 ;
    END
  END sx[585]
  PIN sx[586]
    DIRECTION INPUT ;
    USE SIGNAL ;
    PORT
      LAYER M3 ;
        RECT  75.564 0 75.582 0.037 ;
    END
  END sx[586]
  PIN sx[587]
    DIRECTION INPUT ;
    USE SIGNAL ;
    PORT
      LAYER M3 ;
        RECT  75.636 0 75.654 0.037 ;
    END
  END sx[587]
  PIN sx[588]
    DIRECTION INPUT ;
    USE SIGNAL ;
    PORT
      LAYER M3 ;
        RECT  75.708 0 75.726 0.037 ;
    END
  END sx[588]
  PIN sx[589]
    DIRECTION INPUT ;
    USE SIGNAL ;
    PORT
      LAYER M3 ;
        RECT  75.78 0 75.798 0.037 ;
    END
  END sx[589]
  PIN sx[58]
    DIRECTION INPUT ;
    USE SIGNAL ;
    PORT
      LAYER M3 ;
        RECT  26.028 0 26.046 0.037 ;
    END
  END sx[58]
  PIN sx[590]
    DIRECTION INPUT ;
    USE SIGNAL ;
    PORT
      LAYER M3 ;
        RECT  75.852 0 75.87 0.037 ;
    END
  END sx[590]
  PIN sx[591]
    DIRECTION INPUT ;
    USE SIGNAL ;
    PORT
      LAYER M3 ;
        RECT  75.924 0 75.942 0.037 ;
    END
  END sx[591]
  PIN sx[592]
    DIRECTION INPUT ;
    USE SIGNAL ;
    PORT
      LAYER M3 ;
        RECT  75.996 0 76.014 0.037 ;
    END
  END sx[592]
  PIN sx[593]
    DIRECTION INPUT ;
    USE SIGNAL ;
    PORT
      LAYER M3 ;
        RECT  76.068 0 76.086 0.037 ;
    END
  END sx[593]
  PIN sx[594]
    DIRECTION INPUT ;
    USE SIGNAL ;
    PORT
      LAYER M3 ;
        RECT  76.14 0 76.158 0.037 ;
    END
  END sx[594]
  PIN sx[595]
    DIRECTION INPUT ;
    USE SIGNAL ;
    PORT
      LAYER M3 ;
        RECT  76.212 0 76.23 0.037 ;
    END
  END sx[595]
  PIN sx[596]
    DIRECTION INPUT ;
    USE SIGNAL ;
    PORT
      LAYER M3 ;
        RECT  76.284 0 76.302 0.037 ;
    END
  END sx[596]
  PIN sx[597]
    DIRECTION INPUT ;
    USE SIGNAL ;
    PORT
      LAYER M3 ;
        RECT  76.356 0 76.374 0.037 ;
    END
  END sx[597]
  PIN sx[598]
    DIRECTION INPUT ;
    USE SIGNAL ;
    PORT
      LAYER M3 ;
        RECT  76.428 0 76.446 0.037 ;
    END
  END sx[598]
  PIN sx[599]
    DIRECTION INPUT ;
    USE SIGNAL ;
    PORT
      LAYER M3 ;
        RECT  76.5 0 76.518 0.037 ;
    END
  END sx[599]
  PIN sx[59]
    DIRECTION INPUT ;
    USE SIGNAL ;
    PORT
      LAYER M3 ;
        RECT  26.1 0 26.118 0.037 ;
    END
  END sx[59]
  PIN sx[5]
    DIRECTION INPUT ;
    USE SIGNAL ;
    PORT
      LAYER M3 ;
        RECT  7.812 0 7.83 0.037 ;
    END
  END sx[5]
  PIN sx[600]
    DIRECTION INPUT ;
    USE SIGNAL ;
    PORT
      LAYER M3 ;
        RECT  76.572 0 76.59 0.037 ;
    END
  END sx[600]
  PIN sx[601]
    DIRECTION INPUT ;
    USE SIGNAL ;
    PORT
      LAYER M3 ;
        RECT  76.644 0 76.662 0.037 ;
    END
  END sx[601]
  PIN sx[602]
    DIRECTION INPUT ;
    USE SIGNAL ;
    PORT
      LAYER M3 ;
        RECT  76.716 0 76.734 0.037 ;
    END
  END sx[602]
  PIN sx[603]
    DIRECTION INPUT ;
    USE SIGNAL ;
    PORT
      LAYER M3 ;
        RECT  76.788 0 76.806 0.037 ;
    END
  END sx[603]
  PIN sx[604]
    DIRECTION INPUT ;
    USE SIGNAL ;
    PORT
      LAYER M3 ;
        RECT  76.86 0 76.878 0.037 ;
    END
  END sx[604]
  PIN sx[605]
    DIRECTION INPUT ;
    USE SIGNAL ;
    PORT
      LAYER M3 ;
        RECT  76.932 0 76.95 0.037 ;
    END
  END sx[605]
  PIN sx[606]
    DIRECTION INPUT ;
    USE SIGNAL ;
    PORT
      LAYER M3 ;
        RECT  77.004 0 77.022 0.037 ;
    END
  END sx[606]
  PIN sx[607]
    DIRECTION INPUT ;
    USE SIGNAL ;
    PORT
      LAYER M3 ;
        RECT  77.076 0 77.094 0.037 ;
    END
  END sx[607]
  PIN sx[608]
    DIRECTION INPUT ;
    USE SIGNAL ;
    PORT
      LAYER M5 ;
        RECT  13.008 0 13.032 0.084 ;
    END
  END sx[608]
  PIN sx[609]
    DIRECTION INPUT ;
    USE SIGNAL ;
    PORT
      LAYER M5 ;
        RECT  13.104 0 13.128 0.084 ;
    END
  END sx[609]
  PIN sx[60]
    DIRECTION INPUT ;
    USE SIGNAL ;
    PORT
      LAYER M3 ;
        RECT  26.172 0 26.19 0.037 ;
    END
  END sx[60]
  PIN sx[610]
    DIRECTION INPUT ;
    USE SIGNAL ;
    PORT
      LAYER M5 ;
        RECT  13.2 0 13.224 0.084 ;
    END
  END sx[610]
  PIN sx[611]
    DIRECTION INPUT ;
    USE SIGNAL ;
    PORT
      LAYER M5 ;
        RECT  13.296 0 13.32 0.084 ;
    END
  END sx[611]
  PIN sx[612]
    DIRECTION INPUT ;
    USE SIGNAL ;
    PORT
      LAYER M5 ;
        RECT  13.392 0 13.416 0.084 ;
    END
  END sx[612]
  PIN sx[613]
    DIRECTION INPUT ;
    USE SIGNAL ;
    PORT
      LAYER M5 ;
        RECT  13.488 0 13.512 0.084 ;
    END
  END sx[613]
  PIN sx[614]
    DIRECTION INPUT ;
    USE SIGNAL ;
    PORT
      LAYER M5 ;
        RECT  13.584 0 13.608 0.084 ;
    END
  END sx[614]
  PIN sx[615]
    DIRECTION INPUT ;
    USE SIGNAL ;
    PORT
      LAYER M5 ;
        RECT  13.68 0 13.704 0.084 ;
    END
  END sx[615]
  PIN sx[616]
    DIRECTION INPUT ;
    USE SIGNAL ;
    PORT
      LAYER M5 ;
        RECT  13.776 0 13.8 0.084 ;
    END
  END sx[616]
  PIN sx[617]
    DIRECTION INPUT ;
    USE SIGNAL ;
    PORT
      LAYER M5 ;
        RECT  13.872 0 13.896 0.084 ;
    END
  END sx[617]
  PIN sx[618]
    DIRECTION INPUT ;
    USE SIGNAL ;
    PORT
      LAYER M5 ;
        RECT  13.968 0 13.992 0.084 ;
    END
  END sx[618]
  PIN sx[619]
    DIRECTION INPUT ;
    USE SIGNAL ;
    PORT
      LAYER M5 ;
        RECT  14.064 0 14.088 0.084 ;
    END
  END sx[619]
  PIN sx[61]
    DIRECTION INPUT ;
    USE SIGNAL ;
    PORT
      LAYER M3 ;
        RECT  26.244 0 26.262 0.037 ;
    END
  END sx[61]
  PIN sx[620]
    DIRECTION INPUT ;
    USE SIGNAL ;
    PORT
      LAYER M5 ;
        RECT  14.16 0 14.184 0.084 ;
    END
  END sx[620]
  PIN sx[621]
    DIRECTION INPUT ;
    USE SIGNAL ;
    PORT
      LAYER M5 ;
        RECT  14.256 0 14.28 0.084 ;
    END
  END sx[621]
  PIN sx[622]
    DIRECTION INPUT ;
    USE SIGNAL ;
    PORT
      LAYER M5 ;
        RECT  14.352 0 14.376 0.084 ;
    END
  END sx[622]
  PIN sx[623]
    DIRECTION INPUT ;
    USE SIGNAL ;
    PORT
      LAYER M5 ;
        RECT  14.448 0 14.472 0.084 ;
    END
  END sx[623]
  PIN sx[624]
    DIRECTION INPUT ;
    USE SIGNAL ;
    PORT
      LAYER M5 ;
        RECT  14.544 0 14.568 0.084 ;
    END
  END sx[624]
  PIN sx[625]
    DIRECTION INPUT ;
    USE SIGNAL ;
    PORT
      LAYER M5 ;
        RECT  14.64 0 14.664 0.084 ;
    END
  END sx[625]
  PIN sx[626]
    DIRECTION INPUT ;
    USE SIGNAL ;
    PORT
      LAYER M5 ;
        RECT  14.736 0 14.76 0.084 ;
    END
  END sx[626]
  PIN sx[627]
    DIRECTION INPUT ;
    USE SIGNAL ;
    PORT
      LAYER M5 ;
        RECT  14.832 0 14.856 0.084 ;
    END
  END sx[627]
  PIN sx[628]
    DIRECTION INPUT ;
    USE SIGNAL ;
    PORT
      LAYER M5 ;
        RECT  14.928 0 14.952 0.084 ;
    END
  END sx[628]
  PIN sx[629]
    DIRECTION INPUT ;
    USE SIGNAL ;
    PORT
      LAYER M5 ;
        RECT  15.024 0 15.048 0.084 ;
    END
  END sx[629]
  PIN sx[62]
    DIRECTION INPUT ;
    USE SIGNAL ;
    PORT
      LAYER M3 ;
        RECT  26.316 0 26.334 0.037 ;
    END
  END sx[62]
  PIN sx[630]
    DIRECTION INPUT ;
    USE SIGNAL ;
    PORT
      LAYER M5 ;
        RECT  15.12 0 15.144 0.084 ;
    END
  END sx[630]
  PIN sx[631]
    DIRECTION INPUT ;
    USE SIGNAL ;
    PORT
      LAYER M5 ;
        RECT  15.216 0 15.24 0.084 ;
    END
  END sx[631]
  PIN sx[632]
    DIRECTION INPUT ;
    USE SIGNAL ;
    PORT
      LAYER M5 ;
        RECT  15.312 0 15.336 0.084 ;
    END
  END sx[632]
  PIN sx[633]
    DIRECTION INPUT ;
    USE SIGNAL ;
    PORT
      LAYER M5 ;
        RECT  15.408 0 15.432 0.084 ;
    END
  END sx[633]
  PIN sx[634]
    DIRECTION INPUT ;
    USE SIGNAL ;
    PORT
      LAYER M5 ;
        RECT  15.504 0 15.528 0.084 ;
    END
  END sx[634]
  PIN sx[635]
    DIRECTION INPUT ;
    USE SIGNAL ;
    PORT
      LAYER M5 ;
        RECT  15.6 0 15.624 0.084 ;
    END
  END sx[635]
  PIN sx[636]
    DIRECTION INPUT ;
    USE SIGNAL ;
    PORT
      LAYER M5 ;
        RECT  15.696 0 15.72 0.084 ;
    END
  END sx[636]
  PIN sx[637]
    DIRECTION INPUT ;
    USE SIGNAL ;
    PORT
      LAYER M5 ;
        RECT  15.792 0 15.816 0.084 ;
    END
  END sx[637]
  PIN sx[638]
    DIRECTION INPUT ;
    USE SIGNAL ;
    PORT
      LAYER M5 ;
        RECT  15.888 0 15.912 0.084 ;
    END
  END sx[638]
  PIN sx[639]
    DIRECTION INPUT ;
    USE SIGNAL ;
    PORT
      LAYER M5 ;
        RECT  15.984 0 16.008 0.084 ;
    END
  END sx[639]
  PIN sx[63]
    DIRECTION INPUT ;
    USE SIGNAL ;
    PORT
      LAYER M3 ;
        RECT  26.388 0 26.406 0.037 ;
    END
  END sx[63]
  PIN sx[640]
    DIRECTION INPUT ;
    USE SIGNAL ;
    PORT
      LAYER M3 ;
        RECT  52.956 0 52.974 0.037 ;
    END
  END sx[640]
  PIN sx[641]
    DIRECTION INPUT ;
    USE SIGNAL ;
    PORT
      LAYER M3 ;
        RECT  53.028 0 53.046 0.037 ;
    END
  END sx[641]
  PIN sx[642]
    DIRECTION INPUT ;
    USE SIGNAL ;
    PORT
      LAYER M3 ;
        RECT  53.1 0 53.118 0.037 ;
    END
  END sx[642]
  PIN sx[643]
    DIRECTION INPUT ;
    USE SIGNAL ;
    PORT
      LAYER M3 ;
        RECT  53.172 0 53.19 0.037 ;
    END
  END sx[643]
  PIN sx[644]
    DIRECTION INPUT ;
    USE SIGNAL ;
    PORT
      LAYER M3 ;
        RECT  53.244 0 53.262 0.037 ;
    END
  END sx[644]
  PIN sx[645]
    DIRECTION INPUT ;
    USE SIGNAL ;
    PORT
      LAYER M3 ;
        RECT  53.316 0 53.334 0.037 ;
    END
  END sx[645]
  PIN sx[646]
    DIRECTION INPUT ;
    USE SIGNAL ;
    PORT
      LAYER M3 ;
        RECT  53.388 0 53.406 0.037 ;
    END
  END sx[646]
  PIN sx[647]
    DIRECTION INPUT ;
    USE SIGNAL ;
    PORT
      LAYER M3 ;
        RECT  53.46 0 53.478 0.037 ;
    END
  END sx[647]
  PIN sx[648]
    DIRECTION INPUT ;
    USE SIGNAL ;
    PORT
      LAYER M3 ;
        RECT  53.532 0 53.55 0.037 ;
    END
  END sx[648]
  PIN sx[649]
    DIRECTION INPUT ;
    USE SIGNAL ;
    PORT
      LAYER M3 ;
        RECT  53.604 0 53.622 0.037 ;
    END
  END sx[649]
  PIN sx[64]
    DIRECTION INPUT ;
    USE SIGNAL ;
    PORT
      LAYER M5 ;
        RECT  26.064 0 26.088 0.084 ;
    END
  END sx[64]
  PIN sx[650]
    DIRECTION INPUT ;
    USE SIGNAL ;
    PORT
      LAYER M3 ;
        RECT  53.676 0 53.694 0.037 ;
    END
  END sx[650]
  PIN sx[651]
    DIRECTION INPUT ;
    USE SIGNAL ;
    PORT
      LAYER M3 ;
        RECT  53.748 0 53.766 0.037 ;
    END
  END sx[651]
  PIN sx[652]
    DIRECTION INPUT ;
    USE SIGNAL ;
    PORT
      LAYER M3 ;
        RECT  53.82 0 53.838 0.037 ;
    END
  END sx[652]
  PIN sx[653]
    DIRECTION INPUT ;
    USE SIGNAL ;
    PORT
      LAYER M3 ;
        RECT  53.892 0 53.91 0.037 ;
    END
  END sx[653]
  PIN sx[654]
    DIRECTION INPUT ;
    USE SIGNAL ;
    PORT
      LAYER M3 ;
        RECT  53.964 0 53.982 0.037 ;
    END
  END sx[654]
  PIN sx[655]
    DIRECTION INPUT ;
    USE SIGNAL ;
    PORT
      LAYER M3 ;
        RECT  54.036 0 54.054 0.037 ;
    END
  END sx[655]
  PIN sx[656]
    DIRECTION INPUT ;
    USE SIGNAL ;
    PORT
      LAYER M3 ;
        RECT  54.108 0 54.126 0.037 ;
    END
  END sx[656]
  PIN sx[657]
    DIRECTION INPUT ;
    USE SIGNAL ;
    PORT
      LAYER M3 ;
        RECT  54.18 0 54.198 0.037 ;
    END
  END sx[657]
  PIN sx[658]
    DIRECTION INPUT ;
    USE SIGNAL ;
    PORT
      LAYER M3 ;
        RECT  54.252 0 54.27 0.037 ;
    END
  END sx[658]
  PIN sx[659]
    DIRECTION INPUT ;
    USE SIGNAL ;
    PORT
      LAYER M3 ;
        RECT  54.324 0 54.342 0.037 ;
    END
  END sx[659]
  PIN sx[65]
    DIRECTION INPUT ;
    USE SIGNAL ;
    PORT
      LAYER M5 ;
        RECT  26.16 0 26.184 0.084 ;
    END
  END sx[65]
  PIN sx[660]
    DIRECTION INPUT ;
    USE SIGNAL ;
    PORT
      LAYER M3 ;
        RECT  54.396 0 54.414 0.037 ;
    END
  END sx[660]
  PIN sx[661]
    DIRECTION INPUT ;
    USE SIGNAL ;
    PORT
      LAYER M3 ;
        RECT  54.468 0 54.486 0.037 ;
    END
  END sx[661]
  PIN sx[662]
    DIRECTION INPUT ;
    USE SIGNAL ;
    PORT
      LAYER M3 ;
        RECT  54.54 0 54.558 0.037 ;
    END
  END sx[662]
  PIN sx[663]
    DIRECTION INPUT ;
    USE SIGNAL ;
    PORT
      LAYER M3 ;
        RECT  54.612 0 54.63 0.037 ;
    END
  END sx[663]
  PIN sx[664]
    DIRECTION INPUT ;
    USE SIGNAL ;
    PORT
      LAYER M3 ;
        RECT  54.684 0 54.702 0.037 ;
    END
  END sx[664]
  PIN sx[665]
    DIRECTION INPUT ;
    USE SIGNAL ;
    PORT
      LAYER M3 ;
        RECT  54.756 0 54.774 0.037 ;
    END
  END sx[665]
  PIN sx[666]
    DIRECTION INPUT ;
    USE SIGNAL ;
    PORT
      LAYER M3 ;
        RECT  54.828 0 54.846 0.037 ;
    END
  END sx[666]
  PIN sx[667]
    DIRECTION INPUT ;
    USE SIGNAL ;
    PORT
      LAYER M3 ;
        RECT  54.9 0 54.918 0.037 ;
    END
  END sx[667]
  PIN sx[668]
    DIRECTION INPUT ;
    USE SIGNAL ;
    PORT
      LAYER M3 ;
        RECT  54.972 0 54.99 0.037 ;
    END
  END sx[668]
  PIN sx[669]
    DIRECTION INPUT ;
    USE SIGNAL ;
    PORT
      LAYER M3 ;
        RECT  55.044 0 55.062 0.037 ;
    END
  END sx[669]
  PIN sx[66]
    DIRECTION INPUT ;
    USE SIGNAL ;
    PORT
      LAYER M5 ;
        RECT  26.256 0 26.28 0.084 ;
    END
  END sx[66]
  PIN sx[670]
    DIRECTION INPUT ;
    USE SIGNAL ;
    PORT
      LAYER M3 ;
        RECT  55.116 0 55.134 0.037 ;
    END
  END sx[670]
  PIN sx[671]
    DIRECTION INPUT ;
    USE SIGNAL ;
    PORT
      LAYER M3 ;
        RECT  55.188 0 55.206 0.037 ;
    END
  END sx[671]
  PIN sx[672]
    DIRECTION INPUT ;
    USE SIGNAL ;
    PORT
      LAYER M3 ;
        RECT  9.756 0 9.774 0.037 ;
    END
  END sx[672]
  PIN sx[673]
    DIRECTION INPUT ;
    USE SIGNAL ;
    PORT
      LAYER M3 ;
        RECT  9.828 0 9.846 0.037 ;
    END
  END sx[673]
  PIN sx[674]
    DIRECTION INPUT ;
    USE SIGNAL ;
    PORT
      LAYER M3 ;
        RECT  9.9 0 9.918 0.037 ;
    END
  END sx[674]
  PIN sx[675]
    DIRECTION INPUT ;
    USE SIGNAL ;
    PORT
      LAYER M3 ;
        RECT  9.972 0 9.99 0.037 ;
    END
  END sx[675]
  PIN sx[676]
    DIRECTION INPUT ;
    USE SIGNAL ;
    PORT
      LAYER M3 ;
        RECT  10.044 0 10.062 0.037 ;
    END
  END sx[676]
  PIN sx[677]
    DIRECTION INPUT ;
    USE SIGNAL ;
    PORT
      LAYER M3 ;
        RECT  10.116 0 10.134 0.037 ;
    END
  END sx[677]
  PIN sx[678]
    DIRECTION INPUT ;
    USE SIGNAL ;
    PORT
      LAYER M3 ;
        RECT  10.188 0 10.206 0.037 ;
    END
  END sx[678]
  PIN sx[679]
    DIRECTION INPUT ;
    USE SIGNAL ;
    PORT
      LAYER M3 ;
        RECT  10.26 0 10.278 0.037 ;
    END
  END sx[679]
  PIN sx[67]
    DIRECTION INPUT ;
    USE SIGNAL ;
    PORT
      LAYER M5 ;
        RECT  26.352 0 26.376 0.084 ;
    END
  END sx[67]
  PIN sx[680]
    DIRECTION INPUT ;
    USE SIGNAL ;
    PORT
      LAYER M3 ;
        RECT  10.332 0 10.35 0.037 ;
    END
  END sx[680]
  PIN sx[681]
    DIRECTION INPUT ;
    USE SIGNAL ;
    PORT
      LAYER M3 ;
        RECT  10.404 0 10.422 0.037 ;
    END
  END sx[681]
  PIN sx[682]
    DIRECTION INPUT ;
    USE SIGNAL ;
    PORT
      LAYER M3 ;
        RECT  10.476 0 10.494 0.037 ;
    END
  END sx[682]
  PIN sx[683]
    DIRECTION INPUT ;
    USE SIGNAL ;
    PORT
      LAYER M3 ;
        RECT  10.548 0 10.566 0.037 ;
    END
  END sx[683]
  PIN sx[684]
    DIRECTION INPUT ;
    USE SIGNAL ;
    PORT
      LAYER M3 ;
        RECT  10.62 0 10.638 0.037 ;
    END
  END sx[684]
  PIN sx[685]
    DIRECTION INPUT ;
    USE SIGNAL ;
    PORT
      LAYER M3 ;
        RECT  10.692 0 10.71 0.037 ;
    END
  END sx[685]
  PIN sx[686]
    DIRECTION INPUT ;
    USE SIGNAL ;
    PORT
      LAYER M3 ;
        RECT  10.764 0 10.782 0.037 ;
    END
  END sx[686]
  PIN sx[687]
    DIRECTION INPUT ;
    USE SIGNAL ;
    PORT
      LAYER M3 ;
        RECT  10.836 0 10.854 0.037 ;
    END
  END sx[687]
  PIN sx[688]
    DIRECTION INPUT ;
    USE SIGNAL ;
    PORT
      LAYER M3 ;
        RECT  10.908 0 10.926 0.037 ;
    END
  END sx[688]
  PIN sx[689]
    DIRECTION INPUT ;
    USE SIGNAL ;
    PORT
      LAYER M3 ;
        RECT  10.98 0 10.998 0.037 ;
    END
  END sx[689]
  PIN sx[68]
    DIRECTION INPUT ;
    USE SIGNAL ;
    PORT
      LAYER M5 ;
        RECT  26.448 0 26.472 0.084 ;
    END
  END sx[68]
  PIN sx[690]
    DIRECTION INPUT ;
    USE SIGNAL ;
    PORT
      LAYER M3 ;
        RECT  11.052 0 11.07 0.037 ;
    END
  END sx[690]
  PIN sx[691]
    DIRECTION INPUT ;
    USE SIGNAL ;
    PORT
      LAYER M3 ;
        RECT  11.124 0 11.142 0.037 ;
    END
  END sx[691]
  PIN sx[692]
    DIRECTION INPUT ;
    USE SIGNAL ;
    PORT
      LAYER M3 ;
        RECT  11.196 0 11.214 0.037 ;
    END
  END sx[692]
  PIN sx[693]
    DIRECTION INPUT ;
    USE SIGNAL ;
    PORT
      LAYER M3 ;
        RECT  11.268 0 11.286 0.037 ;
    END
  END sx[693]
  PIN sx[694]
    DIRECTION INPUT ;
    USE SIGNAL ;
    PORT
      LAYER M3 ;
        RECT  11.34 0 11.358 0.037 ;
    END
  END sx[694]
  PIN sx[695]
    DIRECTION INPUT ;
    USE SIGNAL ;
    PORT
      LAYER M3 ;
        RECT  11.412 0 11.43 0.037 ;
    END
  END sx[695]
  PIN sx[696]
    DIRECTION INPUT ;
    USE SIGNAL ;
    PORT
      LAYER M3 ;
        RECT  11.484 0 11.502 0.037 ;
    END
  END sx[696]
  PIN sx[697]
    DIRECTION INPUT ;
    USE SIGNAL ;
    PORT
      LAYER M3 ;
        RECT  11.556 0 11.574 0.037 ;
    END
  END sx[697]
  PIN sx[698]
    DIRECTION INPUT ;
    USE SIGNAL ;
    PORT
      LAYER M3 ;
        RECT  11.628 0 11.646 0.037 ;
    END
  END sx[698]
  PIN sx[699]
    DIRECTION INPUT ;
    USE SIGNAL ;
    PORT
      LAYER M3 ;
        RECT  11.7 0 11.718 0.037 ;
    END
  END sx[699]
  PIN sx[69]
    DIRECTION INPUT ;
    USE SIGNAL ;
    PORT
      LAYER M5 ;
        RECT  26.544 0 26.568 0.084 ;
    END
  END sx[69]
  PIN sx[6]
    DIRECTION INPUT ;
    USE SIGNAL ;
    PORT
      LAYER M3 ;
        RECT  7.884 0 7.902 0.037 ;
    END
  END sx[6]
  PIN sx[700]
    DIRECTION INPUT ;
    USE SIGNAL ;
    PORT
      LAYER M3 ;
        RECT  11.772 0 11.79 0.037 ;
    END
  END sx[700]
  PIN sx[701]
    DIRECTION INPUT ;
    USE SIGNAL ;
    PORT
      LAYER M3 ;
        RECT  11.844 0 11.862 0.037 ;
    END
  END sx[701]
  PIN sx[702]
    DIRECTION INPUT ;
    USE SIGNAL ;
    PORT
      LAYER M3 ;
        RECT  11.916 0 11.934 0.037 ;
    END
  END sx[702]
  PIN sx[703]
    DIRECTION INPUT ;
    USE SIGNAL ;
    PORT
      LAYER M3 ;
        RECT  11.988 0 12.006 0.037 ;
    END
  END sx[703]
  PIN sx[704]
    DIRECTION INPUT ;
    USE SIGNAL ;
    PORT
      LAYER M3 ;
        RECT  65.052 0 65.07 0.037 ;
    END
  END sx[704]
  PIN sx[705]
    DIRECTION INPUT ;
    USE SIGNAL ;
    PORT
      LAYER M3 ;
        RECT  65.124 0 65.142 0.037 ;
    END
  END sx[705]
  PIN sx[706]
    DIRECTION INPUT ;
    USE SIGNAL ;
    PORT
      LAYER M3 ;
        RECT  65.196 0 65.214 0.037 ;
    END
  END sx[706]
  PIN sx[707]
    DIRECTION INPUT ;
    USE SIGNAL ;
    PORT
      LAYER M3 ;
        RECT  65.268 0 65.286 0.037 ;
    END
  END sx[707]
  PIN sx[708]
    DIRECTION INPUT ;
    USE SIGNAL ;
    PORT
      LAYER M3 ;
        RECT  65.34 0 65.358 0.037 ;
    END
  END sx[708]
  PIN sx[709]
    DIRECTION INPUT ;
    USE SIGNAL ;
    PORT
      LAYER M3 ;
        RECT  65.412 0 65.43 0.037 ;
    END
  END sx[709]
  PIN sx[70]
    DIRECTION INPUT ;
    USE SIGNAL ;
    PORT
      LAYER M5 ;
        RECT  26.64 0 26.664 0.084 ;
    END
  END sx[70]
  PIN sx[710]
    DIRECTION INPUT ;
    USE SIGNAL ;
    PORT
      LAYER M3 ;
        RECT  65.484 0 65.502 0.037 ;
    END
  END sx[710]
  PIN sx[711]
    DIRECTION INPUT ;
    USE SIGNAL ;
    PORT
      LAYER M3 ;
        RECT  65.556 0 65.574 0.037 ;
    END
  END sx[711]
  PIN sx[712]
    DIRECTION INPUT ;
    USE SIGNAL ;
    PORT
      LAYER M3 ;
        RECT  65.628 0 65.646 0.037 ;
    END
  END sx[712]
  PIN sx[713]
    DIRECTION INPUT ;
    USE SIGNAL ;
    PORT
      LAYER M3 ;
        RECT  65.7 0 65.718 0.037 ;
    END
  END sx[713]
  PIN sx[714]
    DIRECTION INPUT ;
    USE SIGNAL ;
    PORT
      LAYER M3 ;
        RECT  65.772 0 65.79 0.037 ;
    END
  END sx[714]
  PIN sx[715]
    DIRECTION INPUT ;
    USE SIGNAL ;
    PORT
      LAYER M3 ;
        RECT  65.844 0 65.862 0.037 ;
    END
  END sx[715]
  PIN sx[716]
    DIRECTION INPUT ;
    USE SIGNAL ;
    PORT
      LAYER M3 ;
        RECT  65.916 0 65.934 0.037 ;
    END
  END sx[716]
  PIN sx[717]
    DIRECTION INPUT ;
    USE SIGNAL ;
    PORT
      LAYER M3 ;
        RECT  65.988 0 66.006 0.037 ;
    END
  END sx[717]
  PIN sx[718]
    DIRECTION INPUT ;
    USE SIGNAL ;
    PORT
      LAYER M3 ;
        RECT  66.06 0 66.078 0.037 ;
    END
  END sx[718]
  PIN sx[719]
    DIRECTION INPUT ;
    USE SIGNAL ;
    PORT
      LAYER M3 ;
        RECT  66.132 0 66.15 0.037 ;
    END
  END sx[719]
  PIN sx[71]
    DIRECTION INPUT ;
    USE SIGNAL ;
    PORT
      LAYER M5 ;
        RECT  26.736 0 26.76 0.084 ;
    END
  END sx[71]
  PIN sx[720]
    DIRECTION INPUT ;
    USE SIGNAL ;
    PORT
      LAYER M3 ;
        RECT  66.204 0 66.222 0.037 ;
    END
  END sx[720]
  PIN sx[721]
    DIRECTION INPUT ;
    USE SIGNAL ;
    PORT
      LAYER M3 ;
        RECT  66.276 0 66.294 0.037 ;
    END
  END sx[721]
  PIN sx[722]
    DIRECTION INPUT ;
    USE SIGNAL ;
    PORT
      LAYER M3 ;
        RECT  66.348 0 66.366 0.037 ;
    END
  END sx[722]
  PIN sx[723]
    DIRECTION INPUT ;
    USE SIGNAL ;
    PORT
      LAYER M3 ;
        RECT  66.42 0 66.438 0.037 ;
    END
  END sx[723]
  PIN sx[724]
    DIRECTION INPUT ;
    USE SIGNAL ;
    PORT
      LAYER M3 ;
        RECT  66.492 0 66.51 0.037 ;
    END
  END sx[724]
  PIN sx[725]
    DIRECTION INPUT ;
    USE SIGNAL ;
    PORT
      LAYER M3 ;
        RECT  66.564 0 66.582 0.037 ;
    END
  END sx[725]
  PIN sx[726]
    DIRECTION INPUT ;
    USE SIGNAL ;
    PORT
      LAYER M3 ;
        RECT  66.636 0 66.654 0.037 ;
    END
  END sx[726]
  PIN sx[727]
    DIRECTION INPUT ;
    USE SIGNAL ;
    PORT
      LAYER M3 ;
        RECT  66.708 0 66.726 0.037 ;
    END
  END sx[727]
  PIN sx[728]
    DIRECTION INPUT ;
    USE SIGNAL ;
    PORT
      LAYER M3 ;
        RECT  66.78 0 66.798 0.037 ;
    END
  END sx[728]
  PIN sx[729]
    DIRECTION INPUT ;
    USE SIGNAL ;
    PORT
      LAYER M3 ;
        RECT  66.852 0 66.87 0.037 ;
    END
  END sx[729]
  PIN sx[72]
    DIRECTION INPUT ;
    USE SIGNAL ;
    PORT
      LAYER M5 ;
        RECT  26.832 0 26.856 0.084 ;
    END
  END sx[72]
  PIN sx[730]
    DIRECTION INPUT ;
    USE SIGNAL ;
    PORT
      LAYER M3 ;
        RECT  66.924 0 66.942 0.037 ;
    END
  END sx[730]
  PIN sx[731]
    DIRECTION INPUT ;
    USE SIGNAL ;
    PORT
      LAYER M3 ;
        RECT  66.996 0 67.014 0.037 ;
    END
  END sx[731]
  PIN sx[732]
    DIRECTION INPUT ;
    USE SIGNAL ;
    PORT
      LAYER M3 ;
        RECT  67.068 0 67.086 0.037 ;
    END
  END sx[732]
  PIN sx[733]
    DIRECTION INPUT ;
    USE SIGNAL ;
    PORT
      LAYER M3 ;
        RECT  67.14 0 67.158 0.037 ;
    END
  END sx[733]
  PIN sx[734]
    DIRECTION INPUT ;
    USE SIGNAL ;
    PORT
      LAYER M3 ;
        RECT  67.212 0 67.23 0.037 ;
    END
  END sx[734]
  PIN sx[735]
    DIRECTION INPUT ;
    USE SIGNAL ;
    PORT
      LAYER M3 ;
        RECT  67.284 0 67.302 0.037 ;
    END
  END sx[735]
  PIN sx[736]
    DIRECTION INPUT ;
    USE SIGNAL ;
    PORT
      LAYER M5 ;
        RECT  29.136 0 29.16 0.084 ;
    END
  END sx[736]
  PIN sx[737]
    DIRECTION INPUT ;
    USE SIGNAL ;
    PORT
      LAYER M5 ;
        RECT  29.232 0 29.256 0.084 ;
    END
  END sx[737]
  PIN sx[738]
    DIRECTION INPUT ;
    USE SIGNAL ;
    PORT
      LAYER M5 ;
        RECT  29.328 0 29.352 0.084 ;
    END
  END sx[738]
  PIN sx[739]
    DIRECTION INPUT ;
    USE SIGNAL ;
    PORT
      LAYER M5 ;
        RECT  29.424 0 29.448 0.084 ;
    END
  END sx[739]
  PIN sx[73]
    DIRECTION INPUT ;
    USE SIGNAL ;
    PORT
      LAYER M5 ;
        RECT  26.928 0 26.952 0.084 ;
    END
  END sx[73]
  PIN sx[740]
    DIRECTION INPUT ;
    USE SIGNAL ;
    PORT
      LAYER M5 ;
        RECT  29.52 0 29.544 0.084 ;
    END
  END sx[740]
  PIN sx[741]
    DIRECTION INPUT ;
    USE SIGNAL ;
    PORT
      LAYER M5 ;
        RECT  29.616 0 29.64 0.084 ;
    END
  END sx[741]
  PIN sx[742]
    DIRECTION INPUT ;
    USE SIGNAL ;
    PORT
      LAYER M5 ;
        RECT  29.712 0 29.736 0.084 ;
    END
  END sx[742]
  PIN sx[743]
    DIRECTION INPUT ;
    USE SIGNAL ;
    PORT
      LAYER M5 ;
        RECT  29.808 0 29.832 0.084 ;
    END
  END sx[743]
  PIN sx[744]
    DIRECTION INPUT ;
    USE SIGNAL ;
    PORT
      LAYER M5 ;
        RECT  29.904 0 29.928 0.084 ;
    END
  END sx[744]
  PIN sx[745]
    DIRECTION INPUT ;
    USE SIGNAL ;
    PORT
      LAYER M5 ;
        RECT  30 0 30.024 0.084 ;
    END
  END sx[745]
  PIN sx[746]
    DIRECTION INPUT ;
    USE SIGNAL ;
    PORT
      LAYER M5 ;
        RECT  30.096 0 30.12 0.084 ;
    END
  END sx[746]
  PIN sx[747]
    DIRECTION INPUT ;
    USE SIGNAL ;
    PORT
      LAYER M5 ;
        RECT  30.192 0 30.216 0.084 ;
    END
  END sx[747]
  PIN sx[748]
    DIRECTION INPUT ;
    USE SIGNAL ;
    PORT
      LAYER M5 ;
        RECT  30.288 0 30.312 0.084 ;
    END
  END sx[748]
  PIN sx[749]
    DIRECTION INPUT ;
    USE SIGNAL ;
    PORT
      LAYER M5 ;
        RECT  30.384 0 30.408 0.084 ;
    END
  END sx[749]
  PIN sx[74]
    DIRECTION INPUT ;
    USE SIGNAL ;
    PORT
      LAYER M5 ;
        RECT  27.024 0 27.048 0.084 ;
    END
  END sx[74]
  PIN sx[750]
    DIRECTION INPUT ;
    USE SIGNAL ;
    PORT
      LAYER M5 ;
        RECT  30.48 0 30.504 0.084 ;
    END
  END sx[750]
  PIN sx[751]
    DIRECTION INPUT ;
    USE SIGNAL ;
    PORT
      LAYER M5 ;
        RECT  30.576 0 30.6 0.084 ;
    END
  END sx[751]
  PIN sx[752]
    DIRECTION INPUT ;
    USE SIGNAL ;
    PORT
      LAYER M5 ;
        RECT  30.672 0 30.696 0.084 ;
    END
  END sx[752]
  PIN sx[753]
    DIRECTION INPUT ;
    USE SIGNAL ;
    PORT
      LAYER M5 ;
        RECT  30.768 0 30.792 0.084 ;
    END
  END sx[753]
  PIN sx[754]
    DIRECTION INPUT ;
    USE SIGNAL ;
    PORT
      LAYER M5 ;
        RECT  30.864 0 30.888 0.084 ;
    END
  END sx[754]
  PIN sx[755]
    DIRECTION INPUT ;
    USE SIGNAL ;
    PORT
      LAYER M5 ;
        RECT  30.96 0 30.984 0.084 ;
    END
  END sx[755]
  PIN sx[756]
    DIRECTION INPUT ;
    USE SIGNAL ;
    PORT
      LAYER M5 ;
        RECT  31.056 0 31.08 0.084 ;
    END
  END sx[756]
  PIN sx[757]
    DIRECTION INPUT ;
    USE SIGNAL ;
    PORT
      LAYER M5 ;
        RECT  31.152 0 31.176 0.084 ;
    END
  END sx[757]
  PIN sx[758]
    DIRECTION INPUT ;
    USE SIGNAL ;
    PORT
      LAYER M5 ;
        RECT  31.248 0 31.272 0.084 ;
    END
  END sx[758]
  PIN sx[759]
    DIRECTION INPUT ;
    USE SIGNAL ;
    PORT
      LAYER M5 ;
        RECT  31.344 0 31.368 0.084 ;
    END
  END sx[759]
  PIN sx[75]
    DIRECTION INPUT ;
    USE SIGNAL ;
    PORT
      LAYER M5 ;
        RECT  27.12 0 27.144 0.084 ;
    END
  END sx[75]
  PIN sx[760]
    DIRECTION INPUT ;
    USE SIGNAL ;
    PORT
      LAYER M5 ;
        RECT  31.44 0 31.464 0.084 ;
    END
  END sx[760]
  PIN sx[761]
    DIRECTION INPUT ;
    USE SIGNAL ;
    PORT
      LAYER M5 ;
        RECT  31.536 0 31.56 0.084 ;
    END
  END sx[761]
  PIN sx[762]
    DIRECTION INPUT ;
    USE SIGNAL ;
    PORT
      LAYER M5 ;
        RECT  31.632 0 31.656 0.084 ;
    END
  END sx[762]
  PIN sx[763]
    DIRECTION INPUT ;
    USE SIGNAL ;
    PORT
      LAYER M5 ;
        RECT  31.728 0 31.752 0.084 ;
    END
  END sx[763]
  PIN sx[764]
    DIRECTION INPUT ;
    USE SIGNAL ;
    PORT
      LAYER M5 ;
        RECT  31.824 0 31.848 0.084 ;
    END
  END sx[764]
  PIN sx[765]
    DIRECTION INPUT ;
    USE SIGNAL ;
    PORT
      LAYER M5 ;
        RECT  31.92 0 31.944 0.084 ;
    END
  END sx[765]
  PIN sx[766]
    DIRECTION INPUT ;
    USE SIGNAL ;
    PORT
      LAYER M5 ;
        RECT  32.016 0 32.04 0.084 ;
    END
  END sx[766]
  PIN sx[767]
    DIRECTION INPUT ;
    USE SIGNAL ;
    PORT
      LAYER M5 ;
        RECT  32.112 0 32.136 0.084 ;
    END
  END sx[767]
  PIN sx[768]
    DIRECTION INPUT ;
    USE SIGNAL ;
    PORT
      LAYER M3 ;
        RECT  50.652 0 50.67 0.037 ;
    END
  END sx[768]
  PIN sx[769]
    DIRECTION INPUT ;
    USE SIGNAL ;
    PORT
      LAYER M3 ;
        RECT  50.724 0 50.742 0.037 ;
    END
  END sx[769]
  PIN sx[76]
    DIRECTION INPUT ;
    USE SIGNAL ;
    PORT
      LAYER M5 ;
        RECT  27.216 0 27.24 0.084 ;
    END
  END sx[76]
  PIN sx[770]
    DIRECTION INPUT ;
    USE SIGNAL ;
    PORT
      LAYER M3 ;
        RECT  50.796 0 50.814 0.037 ;
    END
  END sx[770]
  PIN sx[771]
    DIRECTION INPUT ;
    USE SIGNAL ;
    PORT
      LAYER M3 ;
        RECT  50.868 0 50.886 0.037 ;
    END
  END sx[771]
  PIN sx[772]
    DIRECTION INPUT ;
    USE SIGNAL ;
    PORT
      LAYER M3 ;
        RECT  50.94 0 50.958 0.037 ;
    END
  END sx[772]
  PIN sx[773]
    DIRECTION INPUT ;
    USE SIGNAL ;
    PORT
      LAYER M3 ;
        RECT  51.012 0 51.03 0.037 ;
    END
  END sx[773]
  PIN sx[774]
    DIRECTION INPUT ;
    USE SIGNAL ;
    PORT
      LAYER M3 ;
        RECT  51.084 0 51.102 0.037 ;
    END
  END sx[774]
  PIN sx[775]
    DIRECTION INPUT ;
    USE SIGNAL ;
    PORT
      LAYER M3 ;
        RECT  51.156 0 51.174 0.037 ;
    END
  END sx[775]
  PIN sx[776]
    DIRECTION INPUT ;
    USE SIGNAL ;
    PORT
      LAYER M3 ;
        RECT  51.228 0 51.246 0.037 ;
    END
  END sx[776]
  PIN sx[777]
    DIRECTION INPUT ;
    USE SIGNAL ;
    PORT
      LAYER M3 ;
        RECT  51.3 0 51.318 0.037 ;
    END
  END sx[777]
  PIN sx[778]
    DIRECTION INPUT ;
    USE SIGNAL ;
    PORT
      LAYER M3 ;
        RECT  51.372 0 51.39 0.037 ;
    END
  END sx[778]
  PIN sx[779]
    DIRECTION INPUT ;
    USE SIGNAL ;
    PORT
      LAYER M3 ;
        RECT  51.444 0 51.462 0.037 ;
    END
  END sx[779]
  PIN sx[77]
    DIRECTION INPUT ;
    USE SIGNAL ;
    PORT
      LAYER M5 ;
        RECT  27.312 0 27.336 0.084 ;
    END
  END sx[77]
  PIN sx[780]
    DIRECTION INPUT ;
    USE SIGNAL ;
    PORT
      LAYER M3 ;
        RECT  51.516 0 51.534 0.037 ;
    END
  END sx[780]
  PIN sx[781]
    DIRECTION INPUT ;
    USE SIGNAL ;
    PORT
      LAYER M3 ;
        RECT  51.588 0 51.606 0.037 ;
    END
  END sx[781]
  PIN sx[782]
    DIRECTION INPUT ;
    USE SIGNAL ;
    PORT
      LAYER M3 ;
        RECT  51.66 0 51.678 0.037 ;
    END
  END sx[782]
  PIN sx[783]
    DIRECTION INPUT ;
    USE SIGNAL ;
    PORT
      LAYER M3 ;
        RECT  51.732 0 51.75 0.037 ;
    END
  END sx[783]
  PIN sx[784]
    DIRECTION INPUT ;
    USE SIGNAL ;
    PORT
      LAYER M3 ;
        RECT  51.804 0 51.822 0.037 ;
    END
  END sx[784]
  PIN sx[785]
    DIRECTION INPUT ;
    USE SIGNAL ;
    PORT
      LAYER M3 ;
        RECT  51.876 0 51.894 0.037 ;
    END
  END sx[785]
  PIN sx[786]
    DIRECTION INPUT ;
    USE SIGNAL ;
    PORT
      LAYER M3 ;
        RECT  51.948 0 51.966 0.037 ;
    END
  END sx[786]
  PIN sx[787]
    DIRECTION INPUT ;
    USE SIGNAL ;
    PORT
      LAYER M3 ;
        RECT  52.02 0 52.038 0.037 ;
    END
  END sx[787]
  PIN sx[788]
    DIRECTION INPUT ;
    USE SIGNAL ;
    PORT
      LAYER M3 ;
        RECT  52.092 0 52.11 0.037 ;
    END
  END sx[788]
  PIN sx[789]
    DIRECTION INPUT ;
    USE SIGNAL ;
    PORT
      LAYER M3 ;
        RECT  52.164 0 52.182 0.037 ;
    END
  END sx[789]
  PIN sx[78]
    DIRECTION INPUT ;
    USE SIGNAL ;
    PORT
      LAYER M5 ;
        RECT  27.408 0 27.432 0.084 ;
    END
  END sx[78]
  PIN sx[790]
    DIRECTION INPUT ;
    USE SIGNAL ;
    PORT
      LAYER M3 ;
        RECT  52.236 0 52.254 0.037 ;
    END
  END sx[790]
  PIN sx[791]
    DIRECTION INPUT ;
    USE SIGNAL ;
    PORT
      LAYER M3 ;
        RECT  52.308 0 52.326 0.037 ;
    END
  END sx[791]
  PIN sx[792]
    DIRECTION INPUT ;
    USE SIGNAL ;
    PORT
      LAYER M3 ;
        RECT  52.38 0 52.398 0.037 ;
    END
  END sx[792]
  PIN sx[793]
    DIRECTION INPUT ;
    USE SIGNAL ;
    PORT
      LAYER M3 ;
        RECT  52.452 0 52.47 0.037 ;
    END
  END sx[793]
  PIN sx[794]
    DIRECTION INPUT ;
    USE SIGNAL ;
    PORT
      LAYER M3 ;
        RECT  52.524 0 52.542 0.037 ;
    END
  END sx[794]
  PIN sx[795]
    DIRECTION INPUT ;
    USE SIGNAL ;
    PORT
      LAYER M3 ;
        RECT  52.596 0 52.614 0.037 ;
    END
  END sx[795]
  PIN sx[796]
    DIRECTION INPUT ;
    USE SIGNAL ;
    PORT
      LAYER M3 ;
        RECT  52.668 0 52.686 0.037 ;
    END
  END sx[796]
  PIN sx[797]
    DIRECTION INPUT ;
    USE SIGNAL ;
    PORT
      LAYER M3 ;
        RECT  52.74 0 52.758 0.037 ;
    END
  END sx[797]
  PIN sx[798]
    DIRECTION INPUT ;
    USE SIGNAL ;
    PORT
      LAYER M3 ;
        RECT  52.812 0 52.83 0.037 ;
    END
  END sx[798]
  PIN sx[799]
    DIRECTION INPUT ;
    USE SIGNAL ;
    PORT
      LAYER M3 ;
        RECT  52.884 0 52.902 0.037 ;
    END
  END sx[799]
  PIN sx[79]
    DIRECTION INPUT ;
    USE SIGNAL ;
    PORT
      LAYER M5 ;
        RECT  27.504 0 27.528 0.084 ;
    END
  END sx[79]
  PIN sx[7]
    DIRECTION INPUT ;
    USE SIGNAL ;
    PORT
      LAYER M3 ;
        RECT  7.956 0 7.974 0.037 ;
    END
  END sx[7]
  PIN sx[800]
    DIRECTION INPUT ;
    USE SIGNAL ;
    PORT
      LAYER M3 ;
        RECT  21.852 0 21.87 0.037 ;
    END
  END sx[800]
  PIN sx[801]
    DIRECTION INPUT ;
    USE SIGNAL ;
    PORT
      LAYER M3 ;
        RECT  21.924 0 21.942 0.037 ;
    END
  END sx[801]
  PIN sx[802]
    DIRECTION INPUT ;
    USE SIGNAL ;
    PORT
      LAYER M3 ;
        RECT  21.996 0 22.014 0.037 ;
    END
  END sx[802]
  PIN sx[803]
    DIRECTION INPUT ;
    USE SIGNAL ;
    PORT
      LAYER M3 ;
        RECT  22.068 0 22.086 0.037 ;
    END
  END sx[803]
  PIN sx[804]
    DIRECTION INPUT ;
    USE SIGNAL ;
    PORT
      LAYER M3 ;
        RECT  22.14 0 22.158 0.037 ;
    END
  END sx[804]
  PIN sx[805]
    DIRECTION INPUT ;
    USE SIGNAL ;
    PORT
      LAYER M3 ;
        RECT  22.212 0 22.23 0.037 ;
    END
  END sx[805]
  PIN sx[806]
    DIRECTION INPUT ;
    USE SIGNAL ;
    PORT
      LAYER M3 ;
        RECT  22.284 0 22.302 0.037 ;
    END
  END sx[806]
  PIN sx[807]
    DIRECTION INPUT ;
    USE SIGNAL ;
    PORT
      LAYER M3 ;
        RECT  22.356 0 22.374 0.037 ;
    END
  END sx[807]
  PIN sx[808]
    DIRECTION INPUT ;
    USE SIGNAL ;
    PORT
      LAYER M3 ;
        RECT  22.428 0 22.446 0.037 ;
    END
  END sx[808]
  PIN sx[809]
    DIRECTION INPUT ;
    USE SIGNAL ;
    PORT
      LAYER M3 ;
        RECT  22.5 0 22.518 0.037 ;
    END
  END sx[809]
  PIN sx[80]
    DIRECTION INPUT ;
    USE SIGNAL ;
    PORT
      LAYER M5 ;
        RECT  27.6 0 27.624 0.084 ;
    END
  END sx[80]
  PIN sx[810]
    DIRECTION INPUT ;
    USE SIGNAL ;
    PORT
      LAYER M3 ;
        RECT  22.572 0 22.59 0.037 ;
    END
  END sx[810]
  PIN sx[811]
    DIRECTION INPUT ;
    USE SIGNAL ;
    PORT
      LAYER M3 ;
        RECT  22.644 0 22.662 0.037 ;
    END
  END sx[811]
  PIN sx[812]
    DIRECTION INPUT ;
    USE SIGNAL ;
    PORT
      LAYER M3 ;
        RECT  22.716 0 22.734 0.037 ;
    END
  END sx[812]
  PIN sx[813]
    DIRECTION INPUT ;
    USE SIGNAL ;
    PORT
      LAYER M3 ;
        RECT  22.788 0 22.806 0.037 ;
    END
  END sx[813]
  PIN sx[814]
    DIRECTION INPUT ;
    USE SIGNAL ;
    PORT
      LAYER M3 ;
        RECT  22.86 0 22.878 0.037 ;
    END
  END sx[814]
  PIN sx[815]
    DIRECTION INPUT ;
    USE SIGNAL ;
    PORT
      LAYER M3 ;
        RECT  22.932 0 22.95 0.037 ;
    END
  END sx[815]
  PIN sx[816]
    DIRECTION INPUT ;
    USE SIGNAL ;
    PORT
      LAYER M3 ;
        RECT  23.004 0 23.022 0.037 ;
    END
  END sx[816]
  PIN sx[817]
    DIRECTION INPUT ;
    USE SIGNAL ;
    PORT
      LAYER M3 ;
        RECT  23.076 0 23.094 0.037 ;
    END
  END sx[817]
  PIN sx[818]
    DIRECTION INPUT ;
    USE SIGNAL ;
    PORT
      LAYER M3 ;
        RECT  23.148 0 23.166 0.037 ;
    END
  END sx[818]
  PIN sx[819]
    DIRECTION INPUT ;
    USE SIGNAL ;
    PORT
      LAYER M3 ;
        RECT  23.22 0 23.238 0.037 ;
    END
  END sx[819]
  PIN sx[81]
    DIRECTION INPUT ;
    USE SIGNAL ;
    PORT
      LAYER M5 ;
        RECT  27.696 0 27.72 0.084 ;
    END
  END sx[81]
  PIN sx[820]
    DIRECTION INPUT ;
    USE SIGNAL ;
    PORT
      LAYER M3 ;
        RECT  23.292 0 23.31 0.037 ;
    END
  END sx[820]
  PIN sx[821]
    DIRECTION INPUT ;
    USE SIGNAL ;
    PORT
      LAYER M3 ;
        RECT  23.364 0 23.382 0.037 ;
    END
  END sx[821]
  PIN sx[822]
    DIRECTION INPUT ;
    USE SIGNAL ;
    PORT
      LAYER M3 ;
        RECT  23.436 0 23.454 0.037 ;
    END
  END sx[822]
  PIN sx[823]
    DIRECTION INPUT ;
    USE SIGNAL ;
    PORT
      LAYER M3 ;
        RECT  23.508 0 23.526 0.037 ;
    END
  END sx[823]
  PIN sx[824]
    DIRECTION INPUT ;
    USE SIGNAL ;
    PORT
      LAYER M3 ;
        RECT  23.58 0 23.598 0.037 ;
    END
  END sx[824]
  PIN sx[825]
    DIRECTION INPUT ;
    USE SIGNAL ;
    PORT
      LAYER M3 ;
        RECT  23.652 0 23.67 0.037 ;
    END
  END sx[825]
  PIN sx[826]
    DIRECTION INPUT ;
    USE SIGNAL ;
    PORT
      LAYER M3 ;
        RECT  23.724 0 23.742 0.037 ;
    END
  END sx[826]
  PIN sx[827]
    DIRECTION INPUT ;
    USE SIGNAL ;
    PORT
      LAYER M3 ;
        RECT  23.796 0 23.814 0.037 ;
    END
  END sx[827]
  PIN sx[828]
    DIRECTION INPUT ;
    USE SIGNAL ;
    PORT
      LAYER M3 ;
        RECT  23.868 0 23.886 0.037 ;
    END
  END sx[828]
  PIN sx[829]
    DIRECTION INPUT ;
    USE SIGNAL ;
    PORT
      LAYER M3 ;
        RECT  23.94 0 23.958 0.037 ;
    END
  END sx[829]
  PIN sx[82]
    DIRECTION INPUT ;
    USE SIGNAL ;
    PORT
      LAYER M5 ;
        RECT  27.792 0 27.816 0.084 ;
    END
  END sx[82]
  PIN sx[830]
    DIRECTION INPUT ;
    USE SIGNAL ;
    PORT
      LAYER M3 ;
        RECT  24.012 0 24.03 0.037 ;
    END
  END sx[830]
  PIN sx[831]
    DIRECTION INPUT ;
    USE SIGNAL ;
    PORT
      LAYER M3 ;
        RECT  24.084 0 24.102 0.037 ;
    END
  END sx[831]
  PIN sx[832]
    DIRECTION INPUT ;
    USE SIGNAL ;
    PORT
      LAYER M5 ;
        RECT  70.608 0 70.632 0.084 ;
    END
  END sx[832]
  PIN sx[833]
    DIRECTION INPUT ;
    USE SIGNAL ;
    PORT
      LAYER M5 ;
        RECT  70.704 0 70.728 0.084 ;
    END
  END sx[833]
  PIN sx[834]
    DIRECTION INPUT ;
    USE SIGNAL ;
    PORT
      LAYER M5 ;
        RECT  70.8 0 70.824 0.084 ;
    END
  END sx[834]
  PIN sx[835]
    DIRECTION INPUT ;
    USE SIGNAL ;
    PORT
      LAYER M5 ;
        RECT  70.896 0 70.92 0.084 ;
    END
  END sx[835]
  PIN sx[836]
    DIRECTION INPUT ;
    USE SIGNAL ;
    PORT
      LAYER M5 ;
        RECT  70.992 0 71.016 0.084 ;
    END
  END sx[836]
  PIN sx[837]
    DIRECTION INPUT ;
    USE SIGNAL ;
    PORT
      LAYER M5 ;
        RECT  71.088 0 71.112 0.084 ;
    END
  END sx[837]
  PIN sx[838]
    DIRECTION INPUT ;
    USE SIGNAL ;
    PORT
      LAYER M5 ;
        RECT  71.184 0 71.208 0.084 ;
    END
  END sx[838]
  PIN sx[839]
    DIRECTION INPUT ;
    USE SIGNAL ;
    PORT
      LAYER M5 ;
        RECT  71.28 0 71.304 0.084 ;
    END
  END sx[839]
  PIN sx[83]
    DIRECTION INPUT ;
    USE SIGNAL ;
    PORT
      LAYER M5 ;
        RECT  27.888 0 27.912 0.084 ;
    END
  END sx[83]
  PIN sx[840]
    DIRECTION INPUT ;
    USE SIGNAL ;
    PORT
      LAYER M5 ;
        RECT  71.376 0 71.4 0.084 ;
    END
  END sx[840]
  PIN sx[841]
    DIRECTION INPUT ;
    USE SIGNAL ;
    PORT
      LAYER M5 ;
        RECT  71.472 0 71.496 0.084 ;
    END
  END sx[841]
  PIN sx[842]
    DIRECTION INPUT ;
    USE SIGNAL ;
    PORT
      LAYER M5 ;
        RECT  71.568 0 71.592 0.084 ;
    END
  END sx[842]
  PIN sx[843]
    DIRECTION INPUT ;
    USE SIGNAL ;
    PORT
      LAYER M5 ;
        RECT  71.664 0 71.688 0.084 ;
    END
  END sx[843]
  PIN sx[844]
    DIRECTION INPUT ;
    USE SIGNAL ;
    PORT
      LAYER M5 ;
        RECT  71.76 0 71.784 0.084 ;
    END
  END sx[844]
  PIN sx[845]
    DIRECTION INPUT ;
    USE SIGNAL ;
    PORT
      LAYER M5 ;
        RECT  71.856 0 71.88 0.084 ;
    END
  END sx[845]
  PIN sx[846]
    DIRECTION INPUT ;
    USE SIGNAL ;
    PORT
      LAYER M5 ;
        RECT  71.952 0 71.976 0.084 ;
    END
  END sx[846]
  PIN sx[847]
    DIRECTION INPUT ;
    USE SIGNAL ;
    PORT
      LAYER M5 ;
        RECT  72.048 0 72.072 0.084 ;
    END
  END sx[847]
  PIN sx[848]
    DIRECTION INPUT ;
    USE SIGNAL ;
    PORT
      LAYER M5 ;
        RECT  72.144 0 72.168 0.084 ;
    END
  END sx[848]
  PIN sx[849]
    DIRECTION INPUT ;
    USE SIGNAL ;
    PORT
      LAYER M5 ;
        RECT  72.24 0 72.264 0.084 ;
    END
  END sx[849]
  PIN sx[84]
    DIRECTION INPUT ;
    USE SIGNAL ;
    PORT
      LAYER M5 ;
        RECT  27.984 0 28.008 0.084 ;
    END
  END sx[84]
  PIN sx[850]
    DIRECTION INPUT ;
    USE SIGNAL ;
    PORT
      LAYER M5 ;
        RECT  72.336 0 72.36 0.084 ;
    END
  END sx[850]
  PIN sx[851]
    DIRECTION INPUT ;
    USE SIGNAL ;
    PORT
      LAYER M5 ;
        RECT  72.432 0 72.456 0.084 ;
    END
  END sx[851]
  PIN sx[852]
    DIRECTION INPUT ;
    USE SIGNAL ;
    PORT
      LAYER M5 ;
        RECT  72.528 0 72.552 0.084 ;
    END
  END sx[852]
  PIN sx[853]
    DIRECTION INPUT ;
    USE SIGNAL ;
    PORT
      LAYER M5 ;
        RECT  72.624 0 72.648 0.084 ;
    END
  END sx[853]
  PIN sx[854]
    DIRECTION INPUT ;
    USE SIGNAL ;
    PORT
      LAYER M5 ;
        RECT  72.72 0 72.744 0.084 ;
    END
  END sx[854]
  PIN sx[855]
    DIRECTION INPUT ;
    USE SIGNAL ;
    PORT
      LAYER M5 ;
        RECT  72.816 0 72.84 0.084 ;
    END
  END sx[855]
  PIN sx[856]
    DIRECTION INPUT ;
    USE SIGNAL ;
    PORT
      LAYER M5 ;
        RECT  72.912 0 72.936 0.084 ;
    END
  END sx[856]
  PIN sx[857]
    DIRECTION INPUT ;
    USE SIGNAL ;
    PORT
      LAYER M5 ;
        RECT  73.008 0 73.032 0.084 ;
    END
  END sx[857]
  PIN sx[858]
    DIRECTION INPUT ;
    USE SIGNAL ;
    PORT
      LAYER M5 ;
        RECT  73.104 0 73.128 0.084 ;
    END
  END sx[858]
  PIN sx[859]
    DIRECTION INPUT ;
    USE SIGNAL ;
    PORT
      LAYER M5 ;
        RECT  73.2 0 73.224 0.084 ;
    END
  END sx[859]
  PIN sx[85]
    DIRECTION INPUT ;
    USE SIGNAL ;
    PORT
      LAYER M5 ;
        RECT  28.08 0 28.104 0.084 ;
    END
  END sx[85]
  PIN sx[860]
    DIRECTION INPUT ;
    USE SIGNAL ;
    PORT
      LAYER M5 ;
        RECT  73.296 0 73.32 0.084 ;
    END
  END sx[860]
  PIN sx[861]
    DIRECTION INPUT ;
    USE SIGNAL ;
    PORT
      LAYER M5 ;
        RECT  73.392 0 73.416 0.084 ;
    END
  END sx[861]
  PIN sx[862]
    DIRECTION INPUT ;
    USE SIGNAL ;
    PORT
      LAYER M5 ;
        RECT  73.488 0 73.512 0.084 ;
    END
  END sx[862]
  PIN sx[863]
    DIRECTION INPUT ;
    USE SIGNAL ;
    PORT
      LAYER M5 ;
        RECT  73.584 0 73.608 0.084 ;
    END
  END sx[863]
  PIN sx[864]
    DIRECTION INPUT ;
    USE SIGNAL ;
    PORT
      LAYER M3 ;
        RECT  55.26 0 55.278 0.037 ;
    END
  END sx[864]
  PIN sx[865]
    DIRECTION INPUT ;
    USE SIGNAL ;
    PORT
      LAYER M3 ;
        RECT  55.332 0 55.35 0.037 ;
    END
  END sx[865]
  PIN sx[866]
    DIRECTION INPUT ;
    USE SIGNAL ;
    PORT
      LAYER M3 ;
        RECT  55.404 0 55.422 0.037 ;
    END
  END sx[866]
  PIN sx[867]
    DIRECTION INPUT ;
    USE SIGNAL ;
    PORT
      LAYER M3 ;
        RECT  55.476 0 55.494 0.037 ;
    END
  END sx[867]
  PIN sx[868]
    DIRECTION INPUT ;
    USE SIGNAL ;
    PORT
      LAYER M3 ;
        RECT  55.548 0 55.566 0.037 ;
    END
  END sx[868]
  PIN sx[869]
    DIRECTION INPUT ;
    USE SIGNAL ;
    PORT
      LAYER M3 ;
        RECT  55.62 0 55.638 0.037 ;
    END
  END sx[869]
  PIN sx[86]
    DIRECTION INPUT ;
    USE SIGNAL ;
    PORT
      LAYER M5 ;
        RECT  28.176 0 28.2 0.084 ;
    END
  END sx[86]
  PIN sx[870]
    DIRECTION INPUT ;
    USE SIGNAL ;
    PORT
      LAYER M3 ;
        RECT  55.692 0 55.71 0.037 ;
    END
  END sx[870]
  PIN sx[871]
    DIRECTION INPUT ;
    USE SIGNAL ;
    PORT
      LAYER M3 ;
        RECT  55.764 0 55.782 0.037 ;
    END
  END sx[871]
  PIN sx[872]
    DIRECTION INPUT ;
    USE SIGNAL ;
    PORT
      LAYER M3 ;
        RECT  55.836 0 55.854 0.037 ;
    END
  END sx[872]
  PIN sx[873]
    DIRECTION INPUT ;
    USE SIGNAL ;
    PORT
      LAYER M3 ;
        RECT  55.908 0 55.926 0.037 ;
    END
  END sx[873]
  PIN sx[874]
    DIRECTION INPUT ;
    USE SIGNAL ;
    PORT
      LAYER M3 ;
        RECT  55.98 0 55.998 0.037 ;
    END
  END sx[874]
  PIN sx[875]
    DIRECTION INPUT ;
    USE SIGNAL ;
    PORT
      LAYER M3 ;
        RECT  56.052 0 56.07 0.037 ;
    END
  END sx[875]
  PIN sx[876]
    DIRECTION INPUT ;
    USE SIGNAL ;
    PORT
      LAYER M3 ;
        RECT  56.124 0 56.142 0.037 ;
    END
  END sx[876]
  PIN sx[877]
    DIRECTION INPUT ;
    USE SIGNAL ;
    PORT
      LAYER M3 ;
        RECT  56.196 0 56.214 0.037 ;
    END
  END sx[877]
  PIN sx[878]
    DIRECTION INPUT ;
    USE SIGNAL ;
    PORT
      LAYER M3 ;
        RECT  56.268 0 56.286 0.037 ;
    END
  END sx[878]
  PIN sx[879]
    DIRECTION INPUT ;
    USE SIGNAL ;
    PORT
      LAYER M3 ;
        RECT  56.34 0 56.358 0.037 ;
    END
  END sx[879]
  PIN sx[87]
    DIRECTION INPUT ;
    USE SIGNAL ;
    PORT
      LAYER M5 ;
        RECT  28.272 0 28.296 0.084 ;
    END
  END sx[87]
  PIN sx[880]
    DIRECTION INPUT ;
    USE SIGNAL ;
    PORT
      LAYER M3 ;
        RECT  56.412 0 56.43 0.037 ;
    END
  END sx[880]
  PIN sx[881]
    DIRECTION INPUT ;
    USE SIGNAL ;
    PORT
      LAYER M3 ;
        RECT  56.484 0 56.502 0.037 ;
    END
  END sx[881]
  PIN sx[882]
    DIRECTION INPUT ;
    USE SIGNAL ;
    PORT
      LAYER M3 ;
        RECT  56.556 0 56.574 0.037 ;
    END
  END sx[882]
  PIN sx[883]
    DIRECTION INPUT ;
    USE SIGNAL ;
    PORT
      LAYER M3 ;
        RECT  56.628 0 56.646 0.037 ;
    END
  END sx[883]
  PIN sx[884]
    DIRECTION INPUT ;
    USE SIGNAL ;
    PORT
      LAYER M3 ;
        RECT  56.7 0 56.718 0.037 ;
    END
  END sx[884]
  PIN sx[885]
    DIRECTION INPUT ;
    USE SIGNAL ;
    PORT
      LAYER M3 ;
        RECT  56.772 0 56.79 0.037 ;
    END
  END sx[885]
  PIN sx[886]
    DIRECTION INPUT ;
    USE SIGNAL ;
    PORT
      LAYER M3 ;
        RECT  56.844 0 56.862 0.037 ;
    END
  END sx[886]
  PIN sx[887]
    DIRECTION INPUT ;
    USE SIGNAL ;
    PORT
      LAYER M3 ;
        RECT  56.916 0 56.934 0.037 ;
    END
  END sx[887]
  PIN sx[888]
    DIRECTION INPUT ;
    USE SIGNAL ;
    PORT
      LAYER M3 ;
        RECT  56.988 0 57.006 0.037 ;
    END
  END sx[888]
  PIN sx[889]
    DIRECTION INPUT ;
    USE SIGNAL ;
    PORT
      LAYER M3 ;
        RECT  57.06 0 57.078 0.037 ;
    END
  END sx[889]
  PIN sx[88]
    DIRECTION INPUT ;
    USE SIGNAL ;
    PORT
      LAYER M5 ;
        RECT  28.368 0 28.392 0.084 ;
    END
  END sx[88]
  PIN sx[890]
    DIRECTION INPUT ;
    USE SIGNAL ;
    PORT
      LAYER M3 ;
        RECT  57.132 0 57.15 0.037 ;
    END
  END sx[890]
  PIN sx[891]
    DIRECTION INPUT ;
    USE SIGNAL ;
    PORT
      LAYER M3 ;
        RECT  57.204 0 57.222 0.037 ;
    END
  END sx[891]
  PIN sx[892]
    DIRECTION INPUT ;
    USE SIGNAL ;
    PORT
      LAYER M3 ;
        RECT  57.276 0 57.294 0.037 ;
    END
  END sx[892]
  PIN sx[893]
    DIRECTION INPUT ;
    USE SIGNAL ;
    PORT
      LAYER M3 ;
        RECT  57.348 0 57.366 0.037 ;
    END
  END sx[893]
  PIN sx[894]
    DIRECTION INPUT ;
    USE SIGNAL ;
    PORT
      LAYER M3 ;
        RECT  57.42 0 57.438 0.037 ;
    END
  END sx[894]
  PIN sx[895]
    DIRECTION INPUT ;
    USE SIGNAL ;
    PORT
      LAYER M3 ;
        RECT  57.492 0 57.51 0.037 ;
    END
  END sx[895]
  PIN sx[896]
    DIRECTION INPUT ;
    USE SIGNAL ;
    PORT
      LAYER M3 ;
        RECT  29.34 0 29.358 0.037 ;
    END
  END sx[896]
  PIN sx[897]
    DIRECTION INPUT ;
    USE SIGNAL ;
    PORT
      LAYER M3 ;
        RECT  29.412 0 29.43 0.037 ;
    END
  END sx[897]
  PIN sx[898]
    DIRECTION INPUT ;
    USE SIGNAL ;
    PORT
      LAYER M3 ;
        RECT  29.484 0 29.502 0.037 ;
    END
  END sx[898]
  PIN sx[899]
    DIRECTION INPUT ;
    USE SIGNAL ;
    PORT
      LAYER M3 ;
        RECT  29.556 0 29.574 0.037 ;
    END
  END sx[899]
  PIN sx[89]
    DIRECTION INPUT ;
    USE SIGNAL ;
    PORT
      LAYER M5 ;
        RECT  28.464 0 28.488 0.084 ;
    END
  END sx[89]
  PIN sx[8]
    DIRECTION INPUT ;
    USE SIGNAL ;
    PORT
      LAYER M3 ;
        RECT  8.028 0 8.046 0.037 ;
    END
  END sx[8]
  PIN sx[900]
    DIRECTION INPUT ;
    USE SIGNAL ;
    PORT
      LAYER M3 ;
        RECT  29.628 0 29.646 0.037 ;
    END
  END sx[900]
  PIN sx[901]
    DIRECTION INPUT ;
    USE SIGNAL ;
    PORT
      LAYER M3 ;
        RECT  29.7 0 29.718 0.037 ;
    END
  END sx[901]
  PIN sx[902]
    DIRECTION INPUT ;
    USE SIGNAL ;
    PORT
      LAYER M3 ;
        RECT  29.772 0 29.79 0.037 ;
    END
  END sx[902]
  PIN sx[903]
    DIRECTION INPUT ;
    USE SIGNAL ;
    PORT
      LAYER M3 ;
        RECT  29.844 0 29.862 0.037 ;
    END
  END sx[903]
  PIN sx[904]
    DIRECTION INPUT ;
    USE SIGNAL ;
    PORT
      LAYER M3 ;
        RECT  29.916 0 29.934 0.037 ;
    END
  END sx[904]
  PIN sx[905]
    DIRECTION INPUT ;
    USE SIGNAL ;
    PORT
      LAYER M3 ;
        RECT  29.988 0 30.006 0.037 ;
    END
  END sx[905]
  PIN sx[906]
    DIRECTION INPUT ;
    USE SIGNAL ;
    PORT
      LAYER M3 ;
        RECT  30.06 0 30.078 0.037 ;
    END
  END sx[906]
  PIN sx[907]
    DIRECTION INPUT ;
    USE SIGNAL ;
    PORT
      LAYER M3 ;
        RECT  30.132 0 30.15 0.037 ;
    END
  END sx[907]
  PIN sx[908]
    DIRECTION INPUT ;
    USE SIGNAL ;
    PORT
      LAYER M3 ;
        RECT  30.204 0 30.222 0.037 ;
    END
  END sx[908]
  PIN sx[909]
    DIRECTION INPUT ;
    USE SIGNAL ;
    PORT
      LAYER M3 ;
        RECT  30.276 0 30.294 0.037 ;
    END
  END sx[909]
  PIN sx[90]
    DIRECTION INPUT ;
    USE SIGNAL ;
    PORT
      LAYER M5 ;
        RECT  28.56 0 28.584 0.084 ;
    END
  END sx[90]
  PIN sx[910]
    DIRECTION INPUT ;
    USE SIGNAL ;
    PORT
      LAYER M3 ;
        RECT  30.348 0 30.366 0.037 ;
    END
  END sx[910]
  PIN sx[911]
    DIRECTION INPUT ;
    USE SIGNAL ;
    PORT
      LAYER M3 ;
        RECT  30.42 0 30.438 0.037 ;
    END
  END sx[911]
  PIN sx[912]
    DIRECTION INPUT ;
    USE SIGNAL ;
    PORT
      LAYER M3 ;
        RECT  30.492 0 30.51 0.037 ;
    END
  END sx[912]
  PIN sx[913]
    DIRECTION INPUT ;
    USE SIGNAL ;
    PORT
      LAYER M3 ;
        RECT  30.564 0 30.582 0.037 ;
    END
  END sx[913]
  PIN sx[914]
    DIRECTION INPUT ;
    USE SIGNAL ;
    PORT
      LAYER M3 ;
        RECT  30.636 0 30.654 0.037 ;
    END
  END sx[914]
  PIN sx[915]
    DIRECTION INPUT ;
    USE SIGNAL ;
    PORT
      LAYER M3 ;
        RECT  30.708 0 30.726 0.037 ;
    END
  END sx[915]
  PIN sx[916]
    DIRECTION INPUT ;
    USE SIGNAL ;
    PORT
      LAYER M3 ;
        RECT  30.78 0 30.798 0.037 ;
    END
  END sx[916]
  PIN sx[917]
    DIRECTION INPUT ;
    USE SIGNAL ;
    PORT
      LAYER M3 ;
        RECT  30.852 0 30.87 0.037 ;
    END
  END sx[917]
  PIN sx[918]
    DIRECTION INPUT ;
    USE SIGNAL ;
    PORT
      LAYER M3 ;
        RECT  30.924 0 30.942 0.037 ;
    END
  END sx[918]
  PIN sx[919]
    DIRECTION INPUT ;
    USE SIGNAL ;
    PORT
      LAYER M3 ;
        RECT  30.996 0 31.014 0.037 ;
    END
  END sx[919]
  PIN sx[91]
    DIRECTION INPUT ;
    USE SIGNAL ;
    PORT
      LAYER M5 ;
        RECT  28.656 0 28.68 0.084 ;
    END
  END sx[91]
  PIN sx[920]
    DIRECTION INPUT ;
    USE SIGNAL ;
    PORT
      LAYER M3 ;
        RECT  31.068 0 31.086 0.037 ;
    END
  END sx[920]
  PIN sx[921]
    DIRECTION INPUT ;
    USE SIGNAL ;
    PORT
      LAYER M3 ;
        RECT  31.14 0 31.158 0.037 ;
    END
  END sx[921]
  PIN sx[922]
    DIRECTION INPUT ;
    USE SIGNAL ;
    PORT
      LAYER M3 ;
        RECT  31.212 0 31.23 0.037 ;
    END
  END sx[922]
  PIN sx[923]
    DIRECTION INPUT ;
    USE SIGNAL ;
    PORT
      LAYER M3 ;
        RECT  31.284 0 31.302 0.037 ;
    END
  END sx[923]
  PIN sx[924]
    DIRECTION INPUT ;
    USE SIGNAL ;
    PORT
      LAYER M3 ;
        RECT  31.356 0 31.374 0.037 ;
    END
  END sx[924]
  PIN sx[925]
    DIRECTION INPUT ;
    USE SIGNAL ;
    PORT
      LAYER M3 ;
        RECT  31.428 0 31.446 0.037 ;
    END
  END sx[925]
  PIN sx[926]
    DIRECTION INPUT ;
    USE SIGNAL ;
    PORT
      LAYER M3 ;
        RECT  31.5 0 31.518 0.037 ;
    END
  END sx[926]
  PIN sx[927]
    DIRECTION INPUT ;
    USE SIGNAL ;
    PORT
      LAYER M3 ;
        RECT  31.572 0 31.59 0.037 ;
    END
  END sx[927]
  PIN sx[928]
    DIRECTION INPUT ;
    USE SIGNAL ;
    PORT
      LAYER M5 ;
        RECT  51.408 0 51.432 0.084 ;
    END
  END sx[928]
  PIN sx[929]
    DIRECTION INPUT ;
    USE SIGNAL ;
    PORT
      LAYER M5 ;
        RECT  51.504 0 51.528 0.084 ;
    END
  END sx[929]
  PIN sx[92]
    DIRECTION INPUT ;
    USE SIGNAL ;
    PORT
      LAYER M5 ;
        RECT  28.752 0 28.776 0.084 ;
    END
  END sx[92]
  PIN sx[930]
    DIRECTION INPUT ;
    USE SIGNAL ;
    PORT
      LAYER M5 ;
        RECT  51.6 0 51.624 0.084 ;
    END
  END sx[930]
  PIN sx[931]
    DIRECTION INPUT ;
    USE SIGNAL ;
    PORT
      LAYER M5 ;
        RECT  51.696 0 51.72 0.084 ;
    END
  END sx[931]
  PIN sx[932]
    DIRECTION INPUT ;
    USE SIGNAL ;
    PORT
      LAYER M5 ;
        RECT  51.792 0 51.816 0.084 ;
    END
  END sx[932]
  PIN sx[933]
    DIRECTION INPUT ;
    USE SIGNAL ;
    PORT
      LAYER M5 ;
        RECT  51.888 0 51.912 0.084 ;
    END
  END sx[933]
  PIN sx[934]
    DIRECTION INPUT ;
    USE SIGNAL ;
    PORT
      LAYER M5 ;
        RECT  51.984 0 52.008 0.084 ;
    END
  END sx[934]
  PIN sx[935]
    DIRECTION INPUT ;
    USE SIGNAL ;
    PORT
      LAYER M5 ;
        RECT  52.08 0 52.104 0.084 ;
    END
  END sx[935]
  PIN sx[936]
    DIRECTION INPUT ;
    USE SIGNAL ;
    PORT
      LAYER M5 ;
        RECT  52.176 0 52.2 0.084 ;
    END
  END sx[936]
  PIN sx[937]
    DIRECTION INPUT ;
    USE SIGNAL ;
    PORT
      LAYER M5 ;
        RECT  52.272 0 52.296 0.084 ;
    END
  END sx[937]
  PIN sx[938]
    DIRECTION INPUT ;
    USE SIGNAL ;
    PORT
      LAYER M5 ;
        RECT  52.368 0 52.392 0.084 ;
    END
  END sx[938]
  PIN sx[939]
    DIRECTION INPUT ;
    USE SIGNAL ;
    PORT
      LAYER M5 ;
        RECT  52.464 0 52.488 0.084 ;
    END
  END sx[939]
  PIN sx[93]
    DIRECTION INPUT ;
    USE SIGNAL ;
    PORT
      LAYER M5 ;
        RECT  28.848 0 28.872 0.084 ;
    END
  END sx[93]
  PIN sx[940]
    DIRECTION INPUT ;
    USE SIGNAL ;
    PORT
      LAYER M5 ;
        RECT  52.56 0 52.584 0.084 ;
    END
  END sx[940]
  PIN sx[941]
    DIRECTION INPUT ;
    USE SIGNAL ;
    PORT
      LAYER M5 ;
        RECT  52.656 0 52.68 0.084 ;
    END
  END sx[941]
  PIN sx[942]
    DIRECTION INPUT ;
    USE SIGNAL ;
    PORT
      LAYER M5 ;
        RECT  52.752 0 52.776 0.084 ;
    END
  END sx[942]
  PIN sx[943]
    DIRECTION INPUT ;
    USE SIGNAL ;
    PORT
      LAYER M5 ;
        RECT  52.848 0 52.872 0.084 ;
    END
  END sx[943]
  PIN sx[944]
    DIRECTION INPUT ;
    USE SIGNAL ;
    PORT
      LAYER M5 ;
        RECT  52.944 0 52.968 0.084 ;
    END
  END sx[944]
  PIN sx[945]
    DIRECTION INPUT ;
    USE SIGNAL ;
    PORT
      LAYER M5 ;
        RECT  53.04 0 53.064 0.084 ;
    END
  END sx[945]
  PIN sx[946]
    DIRECTION INPUT ;
    USE SIGNAL ;
    PORT
      LAYER M5 ;
        RECT  53.136 0 53.16 0.084 ;
    END
  END sx[946]
  PIN sx[947]
    DIRECTION INPUT ;
    USE SIGNAL ;
    PORT
      LAYER M5 ;
        RECT  53.232 0 53.256 0.084 ;
    END
  END sx[947]
  PIN sx[948]
    DIRECTION INPUT ;
    USE SIGNAL ;
    PORT
      LAYER M5 ;
        RECT  53.328 0 53.352 0.084 ;
    END
  END sx[948]
  PIN sx[949]
    DIRECTION INPUT ;
    USE SIGNAL ;
    PORT
      LAYER M5 ;
        RECT  53.424 0 53.448 0.084 ;
    END
  END sx[949]
  PIN sx[94]
    DIRECTION INPUT ;
    USE SIGNAL ;
    PORT
      LAYER M5 ;
        RECT  28.944 0 28.968 0.084 ;
    END
  END sx[94]
  PIN sx[950]
    DIRECTION INPUT ;
    USE SIGNAL ;
    PORT
      LAYER M5 ;
        RECT  53.52 0 53.544 0.084 ;
    END
  END sx[950]
  PIN sx[951]
    DIRECTION INPUT ;
    USE SIGNAL ;
    PORT
      LAYER M5 ;
        RECT  53.616 0 53.64 0.084 ;
    END
  END sx[951]
  PIN sx[952]
    DIRECTION INPUT ;
    USE SIGNAL ;
    PORT
      LAYER M5 ;
        RECT  53.712 0 53.736 0.084 ;
    END
  END sx[952]
  PIN sx[953]
    DIRECTION INPUT ;
    USE SIGNAL ;
    PORT
      LAYER M5 ;
        RECT  53.808 0 53.832 0.084 ;
    END
  END sx[953]
  PIN sx[954]
    DIRECTION INPUT ;
    USE SIGNAL ;
    PORT
      LAYER M5 ;
        RECT  53.904 0 53.928 0.084 ;
    END
  END sx[954]
  PIN sx[955]
    DIRECTION INPUT ;
    USE SIGNAL ;
    PORT
      LAYER M5 ;
        RECT  54 0 54.024 0.084 ;
    END
  END sx[955]
  PIN sx[956]
    DIRECTION INPUT ;
    USE SIGNAL ;
    PORT
      LAYER M5 ;
        RECT  54.096 0 54.12 0.084 ;
    END
  END sx[956]
  PIN sx[957]
    DIRECTION INPUT ;
    USE SIGNAL ;
    PORT
      LAYER M5 ;
        RECT  54.192 0 54.216 0.084 ;
    END
  END sx[957]
  PIN sx[958]
    DIRECTION INPUT ;
    USE SIGNAL ;
    PORT
      LAYER M5 ;
        RECT  54.288 0 54.312 0.084 ;
    END
  END sx[958]
  PIN sx[959]
    DIRECTION INPUT ;
    USE SIGNAL ;
    PORT
      LAYER M5 ;
        RECT  54.384 0 54.408 0.084 ;
    END
  END sx[959]
  PIN sx[95]
    DIRECTION INPUT ;
    USE SIGNAL ;
    PORT
      LAYER M5 ;
        RECT  29.04 0 29.064 0.084 ;
    END
  END sx[95]
  PIN sx[960]
    DIRECTION INPUT ;
    USE SIGNAL ;
    PORT
      LAYER M3 ;
        RECT  17.244 0 17.262 0.037 ;
    END
  END sx[960]
  PIN sx[961]
    DIRECTION INPUT ;
    USE SIGNAL ;
    PORT
      LAYER M3 ;
        RECT  17.316 0 17.334 0.037 ;
    END
  END sx[961]
  PIN sx[962]
    DIRECTION INPUT ;
    USE SIGNAL ;
    PORT
      LAYER M3 ;
        RECT  17.388 0 17.406 0.037 ;
    END
  END sx[962]
  PIN sx[963]
    DIRECTION INPUT ;
    USE SIGNAL ;
    PORT
      LAYER M3 ;
        RECT  17.46 0 17.478 0.037 ;
    END
  END sx[963]
  PIN sx[964]
    DIRECTION INPUT ;
    USE SIGNAL ;
    PORT
      LAYER M3 ;
        RECT  17.532 0 17.55 0.037 ;
    END
  END sx[964]
  PIN sx[965]
    DIRECTION INPUT ;
    USE SIGNAL ;
    PORT
      LAYER M3 ;
        RECT  17.604 0 17.622 0.037 ;
    END
  END sx[965]
  PIN sx[966]
    DIRECTION INPUT ;
    USE SIGNAL ;
    PORT
      LAYER M3 ;
        RECT  17.676 0 17.694 0.037 ;
    END
  END sx[966]
  PIN sx[967]
    DIRECTION INPUT ;
    USE SIGNAL ;
    PORT
      LAYER M3 ;
        RECT  17.748 0 17.766 0.037 ;
    END
  END sx[967]
  PIN sx[968]
    DIRECTION INPUT ;
    USE SIGNAL ;
    PORT
      LAYER M3 ;
        RECT  17.82 0 17.838 0.037 ;
    END
  END sx[968]
  PIN sx[969]
    DIRECTION INPUT ;
    USE SIGNAL ;
    PORT
      LAYER M3 ;
        RECT  17.892 0 17.91 0.037 ;
    END
  END sx[969]
  PIN sx[96]
    DIRECTION INPUT ;
    USE SIGNAL ;
    PORT
      LAYER M3 ;
        RECT  77.148 0 77.166 0.037 ;
    END
  END sx[96]
  PIN sx[970]
    DIRECTION INPUT ;
    USE SIGNAL ;
    PORT
      LAYER M3 ;
        RECT  17.964 0 17.982 0.037 ;
    END
  END sx[970]
  PIN sx[971]
    DIRECTION INPUT ;
    USE SIGNAL ;
    PORT
      LAYER M3 ;
        RECT  18.036 0 18.054 0.037 ;
    END
  END sx[971]
  PIN sx[972]
    DIRECTION INPUT ;
    USE SIGNAL ;
    PORT
      LAYER M3 ;
        RECT  18.108 0 18.126 0.037 ;
    END
  END sx[972]
  PIN sx[973]
    DIRECTION INPUT ;
    USE SIGNAL ;
    PORT
      LAYER M3 ;
        RECT  18.18 0 18.198 0.037 ;
    END
  END sx[973]
  PIN sx[974]
    DIRECTION INPUT ;
    USE SIGNAL ;
    PORT
      LAYER M3 ;
        RECT  18.252 0 18.27 0.037 ;
    END
  END sx[974]
  PIN sx[975]
    DIRECTION INPUT ;
    USE SIGNAL ;
    PORT
      LAYER M3 ;
        RECT  18.324 0 18.342 0.037 ;
    END
  END sx[975]
  PIN sx[976]
    DIRECTION INPUT ;
    USE SIGNAL ;
    PORT
      LAYER M3 ;
        RECT  18.396 0 18.414 0.037 ;
    END
  END sx[976]
  PIN sx[977]
    DIRECTION INPUT ;
    USE SIGNAL ;
    PORT
      LAYER M3 ;
        RECT  18.468 0 18.486 0.037 ;
    END
  END sx[977]
  PIN sx[978]
    DIRECTION INPUT ;
    USE SIGNAL ;
    PORT
      LAYER M3 ;
        RECT  18.54 0 18.558 0.037 ;
    END
  END sx[978]
  PIN sx[979]
    DIRECTION INPUT ;
    USE SIGNAL ;
    PORT
      LAYER M3 ;
        RECT  18.612 0 18.63 0.037 ;
    END
  END sx[979]
  PIN sx[97]
    DIRECTION INPUT ;
    USE SIGNAL ;
    PORT
      LAYER M3 ;
        RECT  77.22 0 77.238 0.037 ;
    END
  END sx[97]
  PIN sx[980]
    DIRECTION INPUT ;
    USE SIGNAL ;
    PORT
      LAYER M3 ;
        RECT  18.684 0 18.702 0.037 ;
    END
  END sx[980]
  PIN sx[981]
    DIRECTION INPUT ;
    USE SIGNAL ;
    PORT
      LAYER M3 ;
        RECT  18.756 0 18.774 0.037 ;
    END
  END sx[981]
  PIN sx[982]
    DIRECTION INPUT ;
    USE SIGNAL ;
    PORT
      LAYER M3 ;
        RECT  18.828 0 18.846 0.037 ;
    END
  END sx[982]
  PIN sx[983]
    DIRECTION INPUT ;
    USE SIGNAL ;
    PORT
      LAYER M3 ;
        RECT  18.9 0 18.918 0.037 ;
    END
  END sx[983]
  PIN sx[984]
    DIRECTION INPUT ;
    USE SIGNAL ;
    PORT
      LAYER M3 ;
        RECT  18.972 0 18.99 0.037 ;
    END
  END sx[984]
  PIN sx[985]
    DIRECTION INPUT ;
    USE SIGNAL ;
    PORT
      LAYER M3 ;
        RECT  19.044 0 19.062 0.037 ;
    END
  END sx[985]
  PIN sx[986]
    DIRECTION INPUT ;
    USE SIGNAL ;
    PORT
      LAYER M3 ;
        RECT  19.116 0 19.134 0.037 ;
    END
  END sx[986]
  PIN sx[987]
    DIRECTION INPUT ;
    USE SIGNAL ;
    PORT
      LAYER M3 ;
        RECT  19.188 0 19.206 0.037 ;
    END
  END sx[987]
  PIN sx[988]
    DIRECTION INPUT ;
    USE SIGNAL ;
    PORT
      LAYER M3 ;
        RECT  19.26 0 19.278 0.037 ;
    END
  END sx[988]
  PIN sx[989]
    DIRECTION INPUT ;
    USE SIGNAL ;
    PORT
      LAYER M3 ;
        RECT  19.332 0 19.35 0.037 ;
    END
  END sx[989]
  PIN sx[98]
    DIRECTION INPUT ;
    USE SIGNAL ;
    PORT
      LAYER M3 ;
        RECT  77.292 0 77.31 0.037 ;
    END
  END sx[98]
  PIN sx[990]
    DIRECTION INPUT ;
    USE SIGNAL ;
    PORT
      LAYER M3 ;
        RECT  19.404 0 19.422 0.037 ;
    END
  END sx[990]
  PIN sx[991]
    DIRECTION INPUT ;
    USE SIGNAL ;
    PORT
      LAYER M3 ;
        RECT  19.476 0 19.494 0.037 ;
    END
  END sx[991]
  PIN sx[992]
    DIRECTION INPUT ;
    USE SIGNAL ;
    PORT
      LAYER M3 ;
        RECT  38.556 0 38.574 0.037 ;
    END
  END sx[992]
  PIN sx[993]
    DIRECTION INPUT ;
    USE SIGNAL ;
    PORT
      LAYER M3 ;
        RECT  38.628 0 38.646 0.037 ;
    END
  END sx[993]
  PIN sx[994]
    DIRECTION INPUT ;
    USE SIGNAL ;
    PORT
      LAYER M3 ;
        RECT  38.7 0 38.718 0.037 ;
    END
  END sx[994]
  PIN sx[995]
    DIRECTION INPUT ;
    USE SIGNAL ;
    PORT
      LAYER M3 ;
        RECT  38.772 0 38.79 0.037 ;
    END
  END sx[995]
  PIN sx[996]
    DIRECTION INPUT ;
    USE SIGNAL ;
    PORT
      LAYER M3 ;
        RECT  38.844 0 38.862 0.037 ;
    END
  END sx[996]
  PIN sx[997]
    DIRECTION INPUT ;
    USE SIGNAL ;
    PORT
      LAYER M3 ;
        RECT  38.916 0 38.934 0.037 ;
    END
  END sx[997]
  PIN sx[998]
    DIRECTION INPUT ;
    USE SIGNAL ;
    PORT
      LAYER M3 ;
        RECT  38.988 0 39.006 0.037 ;
    END
  END sx[998]
  PIN sx[999]
    DIRECTION INPUT ;
    USE SIGNAL ;
    PORT
      LAYER M3 ;
        RECT  39.06 0 39.078 0.037 ;
    END
  END sx[999]
  PIN sx[99]
    DIRECTION INPUT ;
    USE SIGNAL ;
    PORT
      LAYER M3 ;
        RECT  77.364 0 77.382 0.037 ;
    END
  END sx[99]
  PIN sx[9]
    DIRECTION INPUT ;
    USE SIGNAL ;
    PORT
      LAYER M3 ;
        RECT  8.1 0 8.118 0.037 ;
    END
  END sx[9]
  PIN VDD
    DIRECTION INOUT ;
    USE POWER ;
    PORT
      LAYER M5 ;
        RECT  83.592 2.151 83.712 19.449 ;
        RECT  78.192 2.151 78.312 19.449 ;
        RECT  72.792 2.151 72.912 19.449 ;
        RECT  67.392 2.151 67.512 19.449 ;
        RECT  61.992 2.151 62.112 19.449 ;
        RECT  56.592 2.151 56.712 19.449 ;
        RECT  51.192 2.151 51.312 19.449 ;
        RECT  45.792 2.151 45.912 19.449 ;
        RECT  40.392 2.151 40.512 19.449 ;
        RECT  34.992 2.151 35.112 19.449 ;
        RECT  29.592 2.151 29.712 19.449 ;
        RECT  24.192 2.151 24.312 19.449 ;
        RECT  18.792 2.151 18.912 19.449 ;
        RECT  13.392 2.151 13.512 19.449 ;
        RECT  7.992 2.151 8.112 19.449 ;
        RECT  2.592 2.151 2.712 19.449 ;
    END
  END VDD
  PIN VSS
    DIRECTION INOUT ;
    USE GROUND ;
    PORT
      LAYER M5 ;
        RECT  83.4 2.137 83.52 19.463 ;
        RECT  78 2.137 78.12 19.463 ;
        RECT  72.6 2.137 72.72 19.463 ;
        RECT  67.2 2.137 67.32 19.463 ;
        RECT  61.8 2.137 61.92 19.463 ;
        RECT  56.4 2.137 56.52 19.463 ;
        RECT  51 2.137 51.12 19.463 ;
        RECT  45.6 2.137 45.72 19.463 ;
        RECT  40.2 2.137 40.32 19.463 ;
        RECT  34.8 2.137 34.92 19.463 ;
        RECT  29.4 2.137 29.52 19.463 ;
        RECT  24 2.137 24.12 19.463 ;
        RECT  18.6 2.137 18.72 19.463 ;
        RECT  13.2 2.137 13.32 19.463 ;
        RECT  7.8 2.137 7.92 19.463 ;
        RECT  2.4 2.137 2.52 19.463 ;
    END
  END VSS
  OBS
    LAYER RVTN ;
     RECT  2.16 2.16 84.24 2.295 ;
     RECT  2.16 2.565 84.24 2.835 ;
     RECT  2.16 3.105 84.24 3.375 ;
     RECT  2.16 3.645 84.24 3.915 ;
     RECT  2.16 4.185 84.24 4.455 ;
     RECT  2.16 4.725 84.24 4.995 ;
     RECT  2.16 5.265 84.24 5.535 ;
     RECT  2.16 5.805 84.24 6.075 ;
     RECT  2.16 6.345 84.24 6.615 ;
     RECT  2.16 6.885 84.24 7.155 ;
     RECT  2.16 7.425 84.24 7.695 ;
     RECT  2.16 7.965 84.24 8.235 ;
     RECT  2.16 8.505 84.24 8.775 ;
     RECT  2.16 9.045 84.24 9.315 ;
     RECT  2.16 9.585 84.24 9.855 ;
     RECT  2.16 10.125 84.24 10.395 ;
     RECT  2.16 10.665 84.24 10.935 ;
     RECT  2.16 11.205 84.24 11.475 ;
     RECT  2.16 11.745 84.24 12.015 ;
     RECT  2.16 12.285 84.24 12.555 ;
     RECT  2.16 12.825 84.24 13.095 ;
     RECT  2.16 13.365 84.24 13.635 ;
     RECT  2.16 13.905 84.24 14.175 ;
     RECT  2.16 14.445 84.24 14.715 ;
     RECT  2.16 14.985 84.24 15.255 ;
     RECT  2.16 15.525 84.24 15.795 ;
     RECT  2.16 16.065 84.24 16.335 ;
     RECT  2.16 16.605 84.24 16.875 ;
     RECT  2.16 17.145 84.24 17.415 ;
     RECT  2.16 17.685 84.24 17.955 ;
     RECT  2.16 18.225 84.24 18.495 ;
     RECT  2.16 18.765 84.24 19.035 ;
     RECT  2.16 19.305 84.24 19.44 ;
    LAYER RVTP ;
     RECT  2.16 2.295 84.24 2.565 ;
     RECT  2.16 2.835 84.24 3.105 ;
     RECT  2.16 3.375 84.24 3.645 ;
     RECT  2.16 3.915 84.24 4.185 ;
     RECT  2.16 4.455 84.24 4.725 ;
     RECT  2.16 4.995 84.24 5.265 ;
     RECT  2.16 5.535 84.24 5.805 ;
     RECT  2.16 6.075 84.24 6.345 ;
     RECT  2.16 6.615 84.24 6.885 ;
     RECT  2.16 7.155 84.24 7.425 ;
     RECT  2.16 7.695 84.24 7.965 ;
     RECT  2.16 8.235 84.24 8.505 ;
     RECT  2.16 8.775 84.24 9.045 ;
     RECT  2.16 9.315 84.24 9.585 ;
     RECT  2.16 9.855 84.24 10.125 ;
     RECT  2.16 10.395 84.24 10.665 ;
     RECT  2.16 10.935 84.24 11.205 ;
     RECT  2.16 11.475 84.24 11.745 ;
     RECT  2.16 12.015 84.24 12.285 ;
     RECT  2.16 12.555 84.24 12.825 ;
     RECT  2.16 13.095 84.24 13.365 ;
     RECT  2.16 13.635 84.24 13.905 ;
     RECT  2.16 14.175 84.24 14.445 ;
     RECT  2.16 14.715 84.24 14.985 ;
     RECT  2.16 15.255 84.24 15.525 ;
     RECT  2.16 15.795 84.24 16.065 ;
     RECT  2.16 16.335 84.24 16.605 ;
     RECT  2.16 16.875 84.24 17.145 ;
     RECT  2.16 17.415 84.24 17.685 ;
     RECT  2.16 17.955 84.24 18.225 ;
     RECT  2.16 18.495 84.24 18.765 ;
     RECT  2.16 19.035 84.24 19.305 ;
    LAYER M1 ;
     RECT  2.16 2.151 84.24 19.449 ;
    LAYER M2 ;
     RECT  0.103 15.3 2.16 15.318 ;
     RECT  2.16 2.151 3.379 19.449 ;
     RECT  3.811 0.036 4.243 0.054 ;
     RECT  4.567 21.474 4.603 21.492 ;
     RECT  3.379 1.962 4.639 19.449 ;
     RECT  4.639 1.926 4.711 19.449 ;
     RECT  4.603 21.474 4.783 21.564 ;
     RECT  4.783 21.366 4.811 21.564 ;
     RECT  4.811 21.366 4.883 21.492 ;
     RECT  4.711 1.926 4.955 19.494 ;
     RECT  4.883 21.366 4.955 21.384 ;
     RECT  4.955 1.926 5.575 19.449 ;
     RECT  5.791 21.474 5.863 21.492 ;
     RECT  5.575 1.881 6.043 19.449 ;
     RECT  5.863 21.474 6.179 21.564 ;
     RECT  6.043 1.764 6.187 19.449 ;
     RECT  4.243 0.036 6.259 0.396 ;
     RECT  6.187 1.764 7.555 19.566 ;
     RECT  6.259 0.036 7.591 0.432 ;
     RECT  7.555 21.546 7.699 21.564 ;
     RECT  7.555 1.692 8.051 19.566 ;
     RECT  7.591 0.036 8.563 0.594 ;
     RECT  8.051 1.692 8.563 19.449 ;
     RECT  7.699 21.474 8.671 21.564 ;
     RECT  8.671 21.366 8.771 21.564 ;
     RECT  8.771 21.474 9.131 21.564 ;
     RECT  9.131 21.546 9.311 21.564 ;
     RECT  8.563 0.036 9.715 19.449 ;
     RECT  9.715 0.036 9.923 19.494 ;
     RECT  10.075 21.546 10.831 21.564 ;
     RECT  10.831 21.474 10.931 21.564 ;
     RECT  9.923 0.036 11.075 19.449 ;
     RECT  11.075 1.656 11.147 19.449 ;
     RECT  11.075 0.036 11.543 0.774 ;
     RECT  10.931 21.546 11.615 21.564 ;
     RECT  11.543 0.108 11.795 0.774 ;
     RECT  11.147 1.728 11.867 19.449 ;
     RECT  11.867 1.8 11.939 19.449 ;
     RECT  11.795 0.108 12.191 0.126 ;
     RECT  11.939 1.881 13.091 19.449 ;
     RECT  13.091 1.962 13.819 19.449 ;
     RECT  15.475 0.036 15.727 0.054 ;
     RECT  15.727 0.036 15.827 0.63 ;
     RECT  15.827 0.108 15.971 0.63 ;
     RECT  15.971 0.108 16.591 0.198 ;
     RECT  16.591 0.036 16.979 0.198 ;
     RECT  13.819 1.881 17.123 19.449 ;
     RECT  16.979 0.036 17.959 0.054 ;
     RECT  17.959 0.036 17.995 0.126 ;
     RECT  17.123 1.962 18.211 19.449 ;
     RECT  17.995 0.036 19.579 0.324 ;
     RECT  18.211 1.836 19.939 19.449 ;
     RECT  19.939 1.728 20.075 19.449 ;
     RECT  19.579 0.036 20.587 0.396 ;
     RECT  20.075 1.764 21.091 19.449 ;
     RECT  20.587 0.036 21.371 0.468 ;
     RECT  21.091 1.728 21.379 19.449 ;
     RECT  21.379 1.728 21.515 19.494 ;
     RECT  21.451 21.546 21.559 21.564 ;
     RECT  21.559 21.474 21.883 21.564 ;
     RECT  21.883 21.402 22.207 21.564 ;
     RECT  21.371 0.036 22.279 0.198 ;
     RECT  22.207 21.366 22.343 21.564 ;
     RECT  22.279 0.036 22.379 0.234 ;
     RECT  22.343 21.474 23.215 21.564 ;
     RECT  22.379 0.036 23.251 0.09 ;
     RECT  23.251 0.036 23.287 0.324 ;
     RECT  21.515 1.728 23.899 19.449 ;
     RECT  23.899 1.728 24.035 19.53 ;
     RECT  24.035 1.728 24.107 19.449 ;
     RECT  23.215 21.366 24.151 21.564 ;
     RECT  23.287 0.036 24.251 0.468 ;
     RECT  24.151 21.321 24.359 21.564 ;
     RECT  24.359 21.366 24.971 21.564 ;
     RECT  24.251 0.036 25.187 0.396 ;
     RECT  24.107 1.962 25.195 19.449 ;
     RECT  25.195 1.836 25.231 19.449 ;
     RECT  25.187 0.036 25.475 0.198 ;
     RECT  24.971 21.474 25.547 21.564 ;
     RECT  25.231 1.836 26.195 19.494 ;
     RECT  26.195 2.106 26.311 19.494 ;
     RECT  25.547 21.546 26.383 21.564 ;
     RECT  25.475 0.036 26.411 0.126 ;
     RECT  26.383 21.474 26.483 21.564 ;
     RECT  26.311 2.106 26.635 19.566 ;
     RECT  26.483 21.546 26.735 21.564 ;
     RECT  26.635 2.106 26.771 20.259 ;
     RECT  26.771 2.106 26.807 20.214 ;
     RECT  26.807 2.106 27.535 19.494 ;
     RECT  27.535 2.034 27.679 19.494 ;
     RECT  27.535 21.474 27.679 21.492 ;
     RECT  27.679 21.474 27.707 21.564 ;
     RECT  27.707 21.546 27.815 21.564 ;
     RECT  27.679 1.881 28.103 19.494 ;
     RECT  28.103 1.962 28.355 19.494 ;
     RECT  28.355 1.962 29.083 19.449 ;
     RECT  29.227 0.036 29.371 0.054 ;
     RECT  29.083 1.962 29.435 19.53 ;
     RECT  29.435 1.962 29.587 19.494 ;
     RECT  29.371 0.036 29.731 0.126 ;
     RECT  28.723 21.546 29.839 21.564 ;
     RECT  29.731 0.036 30.127 0.279 ;
     RECT  29.587 1.881 30.227 19.494 ;
     RECT  30.127 0.036 30.263 0.324 ;
     RECT  30.227 1.881 30.299 19.449 ;
     RECT  29.839 21.474 30.343 21.564 ;
     RECT  30.263 0.036 30.371 0.279 ;
     RECT  30.343 21.321 30.443 21.564 ;
     RECT  30.443 21.402 30.479 21.564 ;
     RECT  30.299 2.034 31.243 19.449 ;
     RECT  30.371 0.036 31.351 0.198 ;
     RECT  31.243 2.034 31.379 19.494 ;
     RECT  31.351 0.036 31.523 0.234 ;
     RECT  31.379 2.034 31.711 19.449 ;
     RECT  30.479 21.474 31.711 21.564 ;
     RECT  31.523 0.036 31.775 0.198 ;
     RECT  31.775 0.036 31.847 0.126 ;
     RECT  31.711 21.402 31.883 21.564 ;
     RECT  31.711 1.728 32.495 19.449 ;
     RECT  31.883 21.474 32.719 21.564 ;
     RECT  31.847 0.036 32.863 0.054 ;
     RECT  32.863 0.036 33.179 0.126 ;
     RECT  33.179 0.036 33.287 0.054 ;
     RECT  32.495 2.106 33.367 19.449 ;
     RECT  33.367 1.728 33.503 19.449 ;
     RECT  33.503 2.034 33.763 19.449 ;
     RECT  33.943 0.108 33.979 0.126 ;
     RECT  33.979 0.108 34.015 0.198 ;
     RECT  34.051 1.152 34.231 1.17 ;
     RECT  34.231 1.152 34.403 1.242 ;
     RECT  32.719 21.366 34.403 21.564 ;
     RECT  34.015 0.036 34.619 0.198 ;
     RECT  33.763 2.034 34.663 19.494 ;
     RECT  34.663 2.034 34.879 19.566 ;
     RECT  34.879 1.341 34.951 19.566 ;
     RECT  34.771 20.511 34.951 20.529 ;
     RECT  34.951 1.341 35.131 20.529 ;
     RECT  35.131 1.26 35.167 20.529 ;
     RECT  34.403 21.402 35.303 21.564 ;
     RECT  35.167 1.152 35.555 20.529 ;
     RECT  34.619 0.036 35.671 0.126 ;
     RECT  35.303 21.474 35.699 21.564 ;
     RECT  35.699 21.546 35.807 21.564 ;
     RECT  35.671 0.036 35.887 0.234 ;
     RECT  35.887 0.036 36.023 0.324 ;
     RECT  36.023 0.036 36.203 0.279 ;
     RECT  35.555 2.034 36.203 20.529 ;
     RECT  35.555 1.152 36.607 1.242 ;
     RECT  36.203 2.034 36.607 19.449 ;
     RECT  36.203 20.466 36.779 20.529 ;
     RECT  36.203 0.036 36.851 0.126 ;
     RECT  36.607 1.152 37.031 19.449 ;
     RECT  37.031 1.728 37.499 19.449 ;
     RECT  36.779 20.511 37.931 20.529 ;
     RECT  36.851 0.036 38.263 0.054 ;
     RECT  37.499 2.151 38.443 19.449 ;
     RECT  38.263 0.036 38.615 0.234 ;
     RECT  38.443 2.106 38.983 19.449 ;
     RECT  38.983 1.728 39.227 19.449 ;
     RECT  38.615 0.036 39.703 0.054 ;
     RECT  39.703 0.036 39.955 0.126 ;
     RECT  39.227 2.106 40.063 19.449 ;
     RECT  40.063 2.034 40.207 19.449 ;
     RECT  39.955 0.036 40.279 0.198 ;
     RECT  40.279 0.036 41.207 0.594 ;
     RECT  41.207 0.036 41.243 0.234 ;
     RECT  41.243 0.036 42.079 0.126 ;
     RECT  42.079 0.036 42.179 0.234 ;
     RECT  42.179 0.036 42.539 0.198 ;
     RECT  42.539 0.036 43.187 0.126 ;
     RECT  43.187 0.108 43.259 0.126 ;
     RECT  40.207 1.728 43.295 19.449 ;
     RECT  43.295 1.998 43.447 19.449 ;
     RECT  43.447 1.998 43.519 19.494 ;
     RECT  43.519 1.998 43.591 19.566 ;
     RECT  43.591 1.998 43.799 20.034 ;
     RECT  44.059 21.546 44.311 21.564 ;
     RECT  43.951 20.511 44.339 20.61 ;
     RECT  44.311 21.474 44.411 21.564 ;
     RECT  43.799 1.998 44.959 19.638 ;
     RECT  44.959 1.998 45.023 19.674 ;
     RECT  44.411 21.546 45.175 21.564 ;
     RECT  45.175 21.474 45.283 21.564 ;
     RECT  44.339 20.511 45.491 20.529 ;
     RECT  45.283 21.402 45.607 21.564 ;
     RECT  45.023 2.151 45.751 19.674 ;
     RECT  45.607 21.366 46.175 21.564 ;
     RECT  45.751 2.106 46.211 19.674 ;
     RECT  46.211 2.151 46.283 19.674 ;
     RECT  46.175 21.402 46.975 21.564 ;
     RECT  46.283 2.151 47.011 19.494 ;
     RECT  47.011 2.106 47.047 19.494 ;
     RECT  47.047 2.034 47.111 19.494 ;
     RECT  46.975 21.366 47.839 21.564 ;
     RECT  47.839 21.321 47.975 21.564 ;
     RECT  47.111 2.034 48.055 19.449 ;
     RECT  47.975 21.402 48.119 21.564 ;
     RECT  48.055 2.034 48.199 19.494 ;
     RECT  48.199 2.034 48.307 19.566 ;
     RECT  48.307 2.034 48.515 19.638 ;
     RECT  48.119 21.474 48.875 21.564 ;
     RECT  48.515 2.151 49.055 19.638 ;
     RECT  48.271 20.511 49.387 20.529 ;
     RECT  49.387 20.511 49.595 20.61 ;
     RECT  49.055 2.151 49.783 19.566 ;
     RECT  49.783 2.151 49.855 19.638 ;
     RECT  49.855 2.151 49.927 19.719 ;
     RECT  49.927 2.151 50.027 19.8 ;
     RECT  50.027 2.151 50.179 19.449 ;
     RECT  50.179 2.106 50.503 19.449 ;
     RECT  50.503 2.034 50.719 19.449 ;
     RECT  50.719 0.108 50.791 0.126 ;
     RECT  50.791 0.036 51.079 0.126 ;
     RECT  50.719 1.728 51.151 19.449 ;
     RECT  51.079 0.036 52.087 0.198 ;
     RECT  52.087 0.036 52.663 0.279 ;
     RECT  51.151 1.152 52.663 19.449 ;
     RECT  52.663 0.036 52.943 19.449 ;
     RECT  52.943 0.036 53.591 1.242 ;
     RECT  52.943 2.034 53.743 19.449 ;
     RECT  53.743 1.998 53.815 19.449 ;
     RECT  53.591 0.036 54.787 0.936 ;
     RECT  53.815 1.8 54.787 19.449 ;
     RECT  54.787 0.036 58.135 19.449 ;
     RECT  58.135 0.036 58.171 19.53 ;
     RECT  58.171 0.036 58.423 19.638 ;
     RECT  58.207 21.546 58.531 21.564 ;
     RECT  58.531 21.51 58.667 21.564 ;
     RECT  58.423 0.036 58.783 20.034 ;
     RECT  58.783 0.036 58.919 20.529 ;
     RECT  58.919 0.036 59.171 0.9 ;
     RECT  59.171 0.036 59.315 0.234 ;
     RECT  58.919 1.728 59.567 20.529 ;
     RECT  59.567 1.962 59.747 20.529 ;
     RECT  59.315 0.036 60.475 0.054 ;
     RECT  59.747 1.962 60.619 19.602 ;
     RECT  60.619 1.728 60.691 19.602 ;
     RECT  60.691 1.152 60.791 19.602 ;
     RECT  59.747 20.511 60.799 20.529 ;
     RECT  60.791 1.26 60.899 19.602 ;
     RECT  60.899 1.26 60.935 1.278 ;
     RECT  58.667 21.546 61.015 21.564 ;
     RECT  60.475 0.036 61.123 0.198 ;
     RECT  60.799 20.511 61.159 20.574 ;
     RECT  60.899 2.151 61.231 19.602 ;
     RECT  61.159 20.394 61.231 20.574 ;
     RECT  61.231 2.151 61.303 20.574 ;
     RECT  61.015 21.366 61.303 21.564 ;
     RECT  61.123 0.036 61.835 0.279 ;
     RECT  61.303 2.151 61.951 21.564 ;
     RECT  61.835 0.036 62.051 0.126 ;
     RECT  61.951 1.728 62.051 21.564 ;
     RECT  62.051 2.151 62.779 21.564 ;
     RECT  62.051 0.036 62.879 0.054 ;
     RECT  62.779 1.728 63.095 21.564 ;
     RECT  63.095 21.276 63.347 21.564 ;
     RECT  63.095 1.728 63.671 20.529 ;
     RECT  63.859 0.036 63.895 0.054 ;
     RECT  63.671 2.034 63.923 20.529 ;
     RECT  63.895 0.036 63.995 0.126 ;
     RECT  63.923 2.106 64.391 20.529 ;
     RECT  63.347 21.321 64.679 21.564 ;
     RECT  63.995 0.036 64.975 0.054 ;
     RECT  64.679 21.402 65.003 21.564 ;
     RECT  65.003 21.546 65.543 21.564 ;
     RECT  64.391 2.106 65.623 19.944 ;
     RECT  64.975 0.036 65.867 0.126 ;
     RECT  65.623 1.728 66.119 19.944 ;
     RECT  65.867 0.036 66.847 0.054 ;
     RECT  66.775 21.546 66.883 21.564 ;
     RECT  66.847 0.036 66.955 0.126 ;
     RECT  66.119 1.728 67.127 19.449 ;
     RECT  66.955 0.036 67.235 0.198 ;
     RECT  66.883 21.402 67.235 21.564 ;
     RECT  67.127 2.034 67.243 19.449 ;
     RECT  67.235 0.036 67.379 0.054 ;
     RECT  67.243 2.034 67.639 19.53 ;
     RECT  67.235 21.438 68.431 21.564 ;
     RECT  67.639 2.034 68.459 19.989 ;
     RECT  68.459 2.034 68.675 19.494 ;
     RECT  68.431 21.321 68.855 21.564 ;
     RECT  68.855 21.321 68.891 21.492 ;
     RECT  68.675 2.106 69.259 19.494 ;
     RECT  69.259 2.106 69.503 19.638 ;
     RECT  69.503 2.151 69.799 19.638 ;
     RECT  70.303 21.474 70.519 21.492 ;
     RECT  70.519 21.474 70.547 21.564 ;
     RECT  70.547 21.546 70.655 21.564 ;
     RECT  69.799 2.151 70.879 20.034 ;
     RECT  70.879 2.151 71.087 20.106 ;
     RECT  71.087 2.151 71.987 19.674 ;
     RECT  71.987 2.151 72.139 19.449 ;
     RECT  72.139 2.106 73.607 19.449 ;
     RECT  73.607 2.151 74.371 19.449 ;
     RECT  74.191 21.546 74.407 21.564 ;
     RECT  74.371 2.151 74.767 19.494 ;
     RECT  74.767 0.108 74.803 0.126 ;
     RECT  74.659 1.152 74.803 1.17 ;
     RECT  74.803 0.036 74.911 0.126 ;
     RECT  74.911 0.036 74.947 0.198 ;
     RECT  74.407 21.474 74.983 21.564 ;
     RECT  74.947 0.036 75.227 0.279 ;
     RECT  74.983 21.402 75.227 21.564 ;
     RECT  74.803 1.152 75.271 1.242 ;
     RECT  74.767 2.151 75.271 19.908 ;
     RECT  75.271 1.152 75.371 19.908 ;
     RECT  75.371 2.151 75.487 19.908 ;
     RECT  75.487 2.151 75.703 20.142 ;
     RECT  75.227 0.036 76.135 0.126 ;
     RECT  75.371 1.152 76.171 1.242 ;
     RECT  75.847 21.366 76.207 21.384 ;
     RECT  76.171 1.152 76.243 1.278 ;
     RECT  75.703 2.151 76.315 20.259 ;
     RECT  76.135 0.036 76.495 0.198 ;
     RECT  76.243 1.152 76.847 1.359 ;
     RECT  76.495 0.036 76.883 0.279 ;
     RECT  76.207 21.366 76.919 21.564 ;
     RECT  76.883 0.036 76.955 0.126 ;
     RECT  76.919 21.366 76.955 21.456 ;
     RECT  76.315 2.106 77.071 20.259 ;
     RECT  76.847 1.224 77.575 1.278 ;
     RECT  77.071 2.034 77.575 20.259 ;
     RECT  76.955 0.036 77.791 0.054 ;
     RECT  77.755 21.546 77.863 21.564 ;
     RECT  77.575 1.224 77.899 20.259 ;
     RECT  77.791 0.036 77.935 0.126 ;
     RECT  77.899 1.152 77.963 20.259 ;
     RECT  77.863 21.474 77.963 21.564 ;
     RECT  77.935 0.036 78.079 0.198 ;
     RECT  78.079 0.036 78.907 0.279 ;
     RECT  77.963 1.152 79.015 1.278 ;
     RECT  77.963 2.034 79.015 20.259 ;
     RECT  78.907 0.036 79.115 0.324 ;
     RECT  79.015 1.152 79.403 20.259 ;
     RECT  79.403 1.152 79.439 20.214 ;
     RECT  79.439 1.152 79.763 19.944 ;
     RECT  79.115 0.036 80.383 0.198 ;
     RECT  80.383 0.036 80.591 0.279 ;
     RECT  79.763 1.152 80.635 1.242 ;
     RECT  80.591 0.036 80.663 0.234 ;
     RECT  79.763 2.151 80.743 19.944 ;
     RECT  80.635 1.152 80.815 1.359 ;
     RECT  80.743 2.106 80.815 19.944 ;
     RECT  80.815 1.152 80.915 19.944 ;
     RECT  80.915 1.728 80.951 19.944 ;
     RECT  80.663 0.036 81.275 0.198 ;
     RECT  80.951 2.106 81.383 19.944 ;
     RECT  81.383 2.106 81.815 19.719 ;
     RECT  81.815 2.106 81.995 19.674 ;
     RECT  81.275 0.036 82.067 0.09 ;
     RECT  82.067 0.036 82.103 0.054 ;
     RECT  81.995 2.106 82.139 19.449 ;
     RECT  82.139 2.151 84.24 19.449 ;
     RECT  84.24 14.22 85.523 14.238 ;
    LAYER M3 ;
     RECT  7.452 0.012 12.006 0.031 ;
     RECT  29.34 0.012 43.11 0.031 ;
     RECT  60.444 0.012 67.302 0.031 ;
     RECT  74.844 0.012 81.702 0.031 ;
     RECT  7.416 0.031 12.006 0.043 ;
     RECT  50.652 0.012 57.51 0.067 ;
     RECT  7.416 0.043 12.15 0.091 ;
     RECT  7.416 0.091 12.366 0.103 ;
     RECT  29.232 0.031 43.182 0.103 ;
     RECT  58.788 0.043 58.806 0.103 ;
     RECT  74.808 0.031 82.098 0.103 ;
     RECT  7.2 0.103 12.366 0.175 ;
     RECT  58.536 0.103 58.806 0.211 ;
     RECT  14.94 0.012 26.406 0.235 ;
     RECT  6.696 0.175 12.366 0.331 ;
     RECT  29.232 0.103 43.254 0.331 ;
     RECT  3.816 0.031 3.834 0.373 ;
     RECT  5.544 0.091 5.562 0.409 ;
     RECT  6.624 0.331 12.366 0.409 ;
     RECT  27.72 0.379 27.738 0.427 ;
     RECT  28.512 0.331 43.254 0.427 ;
     RECT  27.72 0.427 43.254 0.475 ;
     RECT  60.444 0.031 67.374 0.475 ;
     RECT  49.896 0.475 49.914 0.523 ;
     RECT  48.024 0.091 48.042 0.571 ;
     RECT  49.356 0.523 49.914 0.571 ;
     RECT  71.712 0.523 71.73 0.571 ;
     RECT  73.44 0.091 73.458 0.571 ;
     RECT  13.284 0.571 13.302 0.619 ;
     RECT  14.328 0.235 26.406 0.619 ;
     RECT  5.544 0.409 12.366 0.667 ;
     RECT  13.284 0.619 26.406 0.667 ;
     RECT  58.536 0.211 59.31 0.841 ;
     RECT  50.652 0.067 57.546 0.913 ;
     RECT  58.284 0.841 59.31 0.913 ;
     RECT  71.712 0.571 72.45 1.051 ;
     RECT  73.44 0.571 73.602 1.051 ;
     RECT  5.544 0.667 26.406 1.099 ;
     RECT  27.144 0.475 43.254 1.099 ;
     RECT  48.024 0.571 49.914 1.147 ;
     RECT  50.652 0.913 59.31 1.147 ;
     RECT  71.712 1.051 73.602 1.147 ;
     RECT  74.772 0.103 82.098 1.147 ;
     RECT  60.444 0.475 67.914 1.675 ;
     RECT  68.832 1.099 68.85 1.675 ;
     RECT  5.544 1.099 43.254 1.723 ;
     RECT  45.792 1.387 45.81 1.723 ;
     RECT  47.088 0.523 47.106 1.723 ;
     RECT  48.024 1.147 59.31 1.723 ;
     RECT  60.444 1.675 68.85 1.723 ;
     RECT  71.244 1.147 73.602 1.723 ;
     RECT  74.664 1.147 82.098 1.723 ;
     RECT  45.396 1.723 59.562 1.771 ;
     RECT  3.816 0.373 4.266 1.921 ;
     RECT  5.544 1.723 43.29 1.921 ;
     RECT  3.816 1.921 43.29 1.957 ;
     RECT  45.324 1.771 59.562 1.957 ;
     RECT  60.444 1.723 82.098 1.957 ;
     RECT  45.324 1.957 82.098 1.993 ;
     RECT  3.384 1.957 43.29 2.065 ;
     RECT  3.384 2.065 43.794 2.101 ;
     RECT  45 1.993 82.098 2.101 ;
     RECT  2.415 2.143 2.505 2.191 ;
     RECT  45 2.101 82.134 2.191 ;
     RECT  83.415 2.143 83.505 2.191 ;
     RECT  2.415 2.191 2.574 2.263 ;
     RECT  3.384 2.101 44.046 2.263 ;
     RECT  44.892 2.191 82.314 2.263 ;
     RECT  2.415 2.263 82.314 2.299 ;
     RECT  2.415 2.299 82.35 2.335 ;
     RECT  83.088 2.191 83.505 2.335 ;
     RECT  2.415 2.335 83.505 2.413 ;
     RECT  2.415 2.413 83.697 3.685 ;
     RECT  2.376 3.685 83.697 4.109 ;
     RECT  2.415 4.109 83.697 4.531 ;
     RECT  2.415 4.531 83.79 4.721 ;
     RECT  2.415 4.721 83.697 5.611 ;
     RECT  2.415 5.611 83.934 7.223 ;
     RECT  2.415 7.223 83.697 7.231 ;
     RECT  2.376 7.231 83.697 7.421 ;
     RECT  2.415 7.421 83.697 8.311 ;
     RECT  2.376 8.311 83.697 8.581 ;
     RECT  2.376 8.581 83.826 9.391 ;
     RECT  2.376 9.391 84.006 9.509 ;
     RECT  2.415 9.509 84.006 9.851 ;
     RECT  2.415 9.851 83.697 11.281 ;
     RECT  2.415 11.281 83.862 11.435 ;
     RECT  2.415 11.435 83.79 11.551 ;
     RECT  2.376 11.551 83.79 11.669 ;
     RECT  2.376 11.669 83.697 12.631 ;
     RECT  2.376 12.631 83.754 12.901 ;
     RECT  2.376 12.901 83.826 13.369 ;
     RECT  2.34 13.369 83.826 13.441 ;
     RECT  2.34 13.441 83.898 13.667 ;
     RECT  2.415 13.667 83.898 13.909 ;
     RECT  2.415 13.909 84.042 14.099 ;
     RECT  85.5 14.215 85.518 14.381 ;
     RECT  2.415 14.099 83.697 15.601 ;
     RECT  2.415 15.601 83.898 15.755 ;
     RECT  0.108 15.295 0.126 16.013 ;
     RECT  2.415 15.755 83.697 16.537 ;
     RECT  2.412 16.537 83.697 16.681 ;
     RECT  2.412 16.681 84.114 16.943 ;
     RECT  2.412 16.943 83.697 17.117 ;
     RECT  2.415 17.117 83.697 17.995 ;
     RECT  2.415 17.995 84.114 18.149 ;
     RECT  2.415 18.149 84.042 18.419 ;
     RECT  2.415 18.419 83.898 18.455 ;
     RECT  3.672 18.455 83.697 19.103 ;
     RECT  2.415 18.455 2.697 19.187 ;
     RECT  3.816 19.103 83.697 19.187 ;
     RECT  3.816 19.187 83.505 19.265 ;
     RECT  4.104 19.265 83.505 19.301 ;
     RECT  4.104 19.301 82.314 19.373 ;
     RECT  37.872 19.373 38.682 19.421 ;
     RECT  2.415 19.187 2.505 19.457 ;
     RECT  51.015 19.373 53.478 19.457 ;
     RECT  83.415 19.301 83.505 19.457 ;
     RECT  54.216 19.373 80.118 19.469 ;
     RECT  40.176 19.373 50.094 19.613 ;
     RECT  80.964 19.373 81.99 19.661 ;
     RECT  54.288 19.469 80.118 19.679 ;
     RECT  81.36 19.661 81.99 19.679 ;
     RECT  72.432 19.679 80.118 19.709 ;
     RECT  81.36 19.679 81.81 19.724 ;
     RECT  54.288 19.679 71.406 19.949 ;
     RECT  73.476 19.709 80.118 19.949 ;
     RECT  81.36 19.724 81.378 19.949 ;
     RECT  37.872 19.421 38.43 20.237 ;
     RECT  73.512 19.949 80.118 20.264 ;
     RECT  80.1 20.264 80.118 20.381 ;
     RECT  4.572 19.373 36.774 20.429 ;
     RECT  4.572 20.429 18.234 20.477 ;
     RECT  72.432 19.709 72.594 20.477 ;
     RECT  18.972 20.429 36.774 20.489 ;
     RECT  4.572 20.477 17.91 20.525 ;
     RECT  18.972 20.489 36.414 20.525 ;
     RECT  40.752 19.613 50.094 20.525 ;
     RECT  51.156 19.457 53.478 20.525 ;
     RECT  54.288 19.949 55.206 20.525 ;
     RECT  56.16 19.949 65.538 20.525 ;
     RECT  72.432 20.477 72.45 20.525 ;
     RECT  73.512 20.264 78.894 20.525 ;
     RECT  37.872 20.237 37.926 20.534 ;
     RECT  4.572 20.525 12.834 20.573 ;
     RECT  14.004 20.525 14.022 20.573 ;
     RECT  42.804 20.525 50.094 20.573 ;
     RECT  52.164 20.525 52.758 20.573 ;
     RECT  54.288 20.525 54.954 20.573 ;
     RECT  15.876 20.525 17.226 20.621 ;
     RECT  19.512 20.525 35.982 20.765 ;
     RECT  37.872 20.534 37.89 21.259 ;
     RECT  57.636 20.525 65.538 21.425 ;
     RECT  37.872 21.259 38.754 21.437 ;
     RECT  4.572 20.573 11.862 21.485 ;
     RECT  12.816 20.573 12.834 21.485 ;
     RECT  14.94 20.525 14.958 21.485 ;
     RECT  15.876 20.621 16.866 21.485 ;
     RECT  19.512 20.765 35.874 21.485 ;
     RECT  37.872 21.437 38.502 21.485 ;
     RECT  40.752 20.525 41.958 21.485 ;
     RECT  52.74 20.573 52.758 21.485 ;
     RECT  54.936 20.573 54.954 21.485 ;
     RECT  72.252 21.307 72.27 21.485 ;
     RECT  4.572 21.485 11.61 21.497 ;
     RECT  37.872 21.485 37.89 21.533 ;
     RECT  57.636 21.425 64.71 21.533 ;
     RECT  4.608 21.497 11.61 21.569 ;
     RECT  21.348 21.485 35.802 21.569 ;
     RECT  65.52 21.425 65.538 21.569 ;
     RECT  66.78 19.949 71.406 21.569 ;
     RECT  74.196 20.525 78.894 21.569 ;
     RECT  4.644 21.569 11.502 21.581 ;
     RECT  21.348 21.569 35.694 21.581 ;
     RECT  43.236 20.573 50.094 21.581 ;
     RECT  57.636 21.533 64.494 21.581 ;
     RECT  66.852 21.569 71.406 21.581 ;
     RECT  74.34 21.569 78.894 21.581 ;
    LAYER M4 ;
     RECT  0.06 15.888 0.137 16.008 ;
     RECT  0.137 15.888 0.179 15.912 ;
     RECT  0.133 12.816 2.329 12.84 ;
     RECT  2.365 7.392 2.408 7.416 ;
     RECT  2.365 8.832 2.408 8.856 ;
     RECT  2.329 12.816 2.408 13.656 ;
     RECT  2.401 16.56 2.408 17.112 ;
     RECT  2.408 2.148 2.512 19.452 ;
     RECT  2.512 2.148 2.704 19.182 ;
     RECT  2.704 12.672 2.915 17.112 ;
     RECT  2.915 12.672 3.089 15.96 ;
     RECT  2.704 8.832 3.197 9.048 ;
     RECT  2.704 7.344 3.269 7.416 ;
     RECT  2.704 2.148 3.397 4.152 ;
     RECT  2.704 5.664 3.449 6.312 ;
     RECT  2.704 10.608 3.697 10.872 ;
     RECT  2.915 17.088 3.805 17.112 ;
     RECT  3.697 10.608 3.845 11.016 ;
     RECT  3.089 12.672 3.917 15.384 ;
     RECT  3.917 14.352 3.971 15.384 ;
     RECT  3.805 17.088 4.021 17.16 ;
     RECT  3.269 7.344 4.093 7.368 ;
     RECT  3.397 2.112 4.172 4.152 ;
     RECT  4.172 2.112 4.259 4.632 ;
     RECT  4.093 6.864 4.277 7.368 ;
     RECT  4.021 17.088 4.417 17.688 ;
     RECT  4.417 17.088 4.525 18.072 ;
     RECT  4.525 17.088 4.633 18.552 ;
     RECT  3.971 14.448 4.849 15.384 ;
     RECT  3.917 12.672 5.029 13.368 ;
     RECT  4.633 17.088 5.033 19.32 ;
     RECT  3.449 5.664 5.065 5.688 ;
     RECT  3.845 10.608 5.137 10.824 ;
     RECT  5.033 17.088 5.173 18.552 ;
     RECT  5.173 16.944 5.177 18.552 ;
     RECT  3.197 9.024 5.276 9.048 ;
     RECT  5.137 10.176 5.276 10.824 ;
     RECT  5.276 9.024 5.363 10.824 ;
     RECT  4.849 14.448 5.425 15.96 ;
     RECT  5.177 16.944 5.425 18.024 ;
     RECT  4.259 2.112 5.533 4.152 ;
     RECT  5.065 5.232 5.533 5.688 ;
     RECT  4.277 7.344 5.608 7.368 ;
     RECT  5.608 7.344 5.609 7.416 ;
     RECT  5.029 11.952 5.641 13.368 ;
     RECT  5.425 14.448 5.641 18.024 ;
     RECT  5.533 2.112 5.645 5.688 ;
     RECT  5.641 11.952 5.681 18.024 ;
     RECT  5.645 2.112 5.785 5.496 ;
     RECT  5.363 10.176 5.821 10.824 ;
     RECT  5.681 11.952 5.821 14.328 ;
     RECT  5.821 10.176 6.221 14.328 ;
     RECT  6.221 10.176 6.227 10.728 ;
     RECT  6.001 19.008 6.253 19.032 ;
     RECT  5.681 15.36 6.433 18.024 ;
     RECT  6.253 19.008 6.433 19.416 ;
     RECT  5.533 0.096 6.613 0.12 ;
     RECT  5.363 9.024 6.613 9.048 ;
     RECT  5.785 2.016 6.649 5.496 ;
     RECT  6.613 8.544 6.653 9.048 ;
     RECT  6.613 0.096 6.805 0.36 ;
     RECT  5.609 7.392 6.865 7.416 ;
     RECT  6.653 8.544 6.865 8.568 ;
     RECT  6.649 1.728 6.901 5.496 ;
     RECT  6.901 1.728 6.973 5.592 ;
     RECT  6.227 10.224 7.189 10.728 ;
     RECT  6.865 7.392 7.225 8.568 ;
     RECT  6.973 1.728 7.381 6.312 ;
     RECT  7.225 7.344 7.381 8.568 ;
     RECT  6.805 0.048 7.429 0.36 ;
     RECT  7.429 0.048 7.765 0.504 ;
     RECT  7.381 1.728 7.808 8.568 ;
     RECT  7.189 9.744 7.808 10.728 ;
     RECT  6.221 11.952 7.808 14.328 ;
     RECT  6.433 15.36 7.808 19.416 ;
     RECT  7.808 1.728 7.912 19.452 ;
     RECT  7.912 1.728 8.104 19.182 ;
     RECT  8.104 18.768 8.417 18.792 ;
     RECT  7.765 0.048 8.485 0.552 ;
     RECT  8.104 1.728 8.675 9.144 ;
     RECT  8.104 12.816 8.921 17.64 ;
     RECT  8.845 21.504 8.989 21.528 ;
     RECT  8.989 20.544 9.029 21.528 ;
     RECT  8.104 10.272 9.173 11.544 ;
     RECT  8.675 7.392 9.457 9.144 ;
     RECT  8.485 0.048 9.637 0.6 ;
     RECT  8.675 1.728 9.637 6.36 ;
     RECT  8.921 15.456 9.637 17.64 ;
     RECT  9.601 18.624 9.637 18.648 ;
     RECT  9.637 15.456 9.673 18.648 ;
     RECT  9.637 0.048 9.781 6.36 ;
     RECT  9.457 7.392 9.781 9.768 ;
     RECT  8.921 12.816 9.781 14.136 ;
     RECT  9.029 20.544 9.829 21.48 ;
     RECT  9.781 12.528 9.865 14.136 ;
     RECT  9.673 15.456 9.925 18.696 ;
     RECT  9.925 15.456 9.961 19.368 ;
     RECT  9.865 12.816 9.965 14.136 ;
     RECT  9.829 20.496 9.965 21.48 ;
     RECT  9.781 0.048 10.141 9.768 ;
     RECT  9.173 10.848 10.141 11.544 ;
     RECT  9.965 12.816 10.145 14.088 ;
     RECT  9.961 15.408 10.309 19.368 ;
     RECT  10.141 0.048 10.469 11.544 ;
     RECT  10.309 15.408 10.469 19.464 ;
     RECT  10.469 15.408 10.541 17.016 ;
     RECT  10.469 0.048 10.835 11.448 ;
     RECT  10.835 9.648 10.973 11.448 ;
     RECT  10.145 12.816 11.329 13.944 ;
     RECT  10.835 0.048 11.333 8.232 ;
     RECT  11.329 12.576 11.401 13.944 ;
     RECT  10.541 15.408 11.401 16.92 ;
     RECT  10.973 9.648 11.411 9.816 ;
     RECT  10.973 10.848 11.411 11.448 ;
     RECT  10.469 18 11.413 19.464 ;
     RECT  11.333 6.192 11.441 8.232 ;
     RECT  11.411 9.648 11.441 9.72 ;
     RECT  11.413 19.248 11.461 19.464 ;
     RECT  11.401 12.576 11.581 16.92 ;
     RECT  11.413 18 11.581 18.072 ;
     RECT  11.333 0.048 11.621 5.208 ;
     RECT  11.461 19.248 11.653 19.944 ;
     RECT  9.965 21.456 11.653 21.48 ;
     RECT  11.411 11.232 11.761 11.448 ;
     RECT  11.581 12.576 11.761 18.072 ;
     RECT  11.761 11.232 12.089 18.072 ;
     RECT  12.089 11.232 12.153 17.688 ;
     RECT  11.621 0.048 12.161 4.44 ;
     RECT  11.441 9.648 12.233 9.672 ;
     RECT  11.653 19.248 12.313 21.48 ;
     RECT  12.313 19.248 12.517 19.452 ;
     RECT  12.161 0.096 12.563 4.44 ;
     RECT  12.313 20.448 12.845 21.48 ;
     RECT  11.441 6.192 12.877 6.84 ;
     RECT  12.877 6.192 13.093 7.224 ;
     RECT  11.441 8.208 13.093 8.232 ;
     RECT  12.153 15.696 13.093 17.688 ;
     RECT  12.517 18.768 13.093 19.452 ;
     RECT  12.563 0.576 13.208 4.44 ;
     RECT  13.093 6.192 13.208 8.232 ;
     RECT  12.153 11.232 13.208 14.472 ;
     RECT  13.093 15.696 13.208 19.452 ;
     RECT  13.208 0.576 13.429 19.452 ;
     RECT  12.845 20.448 13.429 21.432 ;
     RECT  13.429 0.576 13.504 21.432 ;
     RECT  13.504 19.296 13.619 21.432 ;
     RECT  13.504 9.648 13.817 11.736 ;
     RECT  13.504 13.824 14.105 17.736 ;
     RECT  13.504 0.576 14.317 4.44 ;
     RECT  13.817 9.648 14.321 10.392 ;
     RECT  14.105 15.552 14.339 17.736 ;
     RECT  13.619 19.296 14.429 20.568 ;
     RECT  13.817 11.376 14.569 11.736 ;
     RECT  13.504 12.816 14.569 12.84 ;
     RECT  13.504 6.288 14.605 7.512 ;
     RECT  14.605 5.712 14.645 7.512 ;
     RECT  14.317 0.24 14.732 4.44 ;
     RECT  14.732 0.24 14.773 4.536 ;
     RECT  14.773 0.144 14.819 4.536 ;
     RECT  14.321 9.696 14.819 10.392 ;
     RECT  14.429 19.344 14.821 20.568 ;
     RECT  14.569 11.376 14.965 12.84 ;
     RECT  14.105 13.824 14.965 14.232 ;
     RECT  14.965 11.376 15.052 14.232 ;
     RECT  15.052 13.824 15.073 14.232 ;
     RECT  14.339 15.552 15.073 17.64 ;
     RECT  15.073 13.824 15.221 17.64 ;
     RECT  15.221 15.456 15.325 17.64 ;
     RECT  14.819 0.144 15.329 4.44 ;
     RECT  14.819 10.368 15.445 10.392 ;
     RECT  15.052 11.376 15.445 12.84 ;
     RECT  15.221 13.824 15.473 14.136 ;
     RECT  14.821 19.344 15.493 21.48 ;
     RECT  15.493 18.768 15.797 21.48 ;
     RECT  15.329 0.48 15.827 4.44 ;
     RECT  14.645 5.712 15.865 5.736 ;
     RECT  14.645 6.768 15.865 7.512 ;
     RECT  15.827 0.48 15.905 1.224 ;
     RECT  15.905 0.576 15.923 1.224 ;
     RECT  15.827 2.496 15.925 4.44 ;
     RECT  15.865 5.712 15.925 7.512 ;
     RECT  15.923 0.576 15.941 0.648 ;
     RECT  15.941 0.624 16.301 0.648 ;
     RECT  15.797 19.344 16.517 21.48 ;
     RECT  15.473 14.112 16.733 14.136 ;
     RECT  15.925 2.496 16.805 7.512 ;
     RECT  15.445 10.368 16.837 12.84 ;
     RECT  16.517 19.392 16.921 21.48 ;
     RECT  16.805 2.496 16.945 5.16 ;
     RECT  16.805 6.72 16.985 7.512 ;
     RECT  15.325 15.456 17.075 17.736 ;
     RECT  16.981 0.096 17.077 0.12 ;
     RECT  16.985 6.816 17.077 7.512 ;
     RECT  16.837 10.368 17.077 13.08 ;
     RECT  16.945 1.728 17.123 5.16 ;
     RECT  17.075 15.456 17.221 17.64 ;
     RECT  17.077 0.048 17.273 0.12 ;
     RECT  17.077 10.272 17.309 13.08 ;
     RECT  17.077 6.816 17.345 7.704 ;
     RECT  16.921 19.392 17.363 20.616 ;
     RECT  17.273 0.096 17.561 0.12 ;
     RECT  17.363 19.392 17.585 20.52 ;
     RECT  16.225 8.832 17.708 8.856 ;
     RECT  17.708 8.832 17.74 9.048 ;
     RECT  17.585 19.344 17.917 20.52 ;
     RECT  17.221 15.024 18.037 17.64 ;
     RECT  17.123 2.4 18.085 5.16 ;
     RECT  17.309 11.424 18.092 13.08 ;
     RECT  17.917 18.816 18.325 20.52 ;
     RECT  18.092 11.424 18.341 13.8 ;
     RECT  17.309 10.272 18.449 10.392 ;
     RECT  18.341 11.376 18.449 13.8 ;
     RECT  17.345 6.96 18.565 7.704 ;
     RECT  17.74 8.784 18.565 9.048 ;
     RECT  18.085 2.256 18.608 5.16 ;
     RECT  18.565 6.96 18.608 9.048 ;
     RECT  18.449 10.272 18.608 13.8 ;
     RECT  18.037 15.024 18.608 17.688 ;
     RECT  18.325 18.816 18.608 21.432 ;
     RECT  18.608 2.148 18.712 21.432 ;
     RECT  18.712 2.208 18.904 21.432 ;
     RECT  18.904 2.208 19.217 15.048 ;
     RECT  18.904 18.816 19.253 21.432 ;
     RECT  19.217 2.208 19.289 11.784 ;
     RECT  19.253 18.816 19.289 19.416 ;
     RECT  19.289 18.912 19.324 19.416 ;
     RECT  19.324 18.912 19.379 19.368 ;
     RECT  19.289 6.864 19.397 11.784 ;
     RECT  19.253 20.448 19.429 21.432 ;
     RECT  19.397 7.344 19.757 11.784 ;
     RECT  19.289 2.208 19.861 5.832 ;
     RECT  19.429 20.448 19.865 21.48 ;
     RECT  19.217 12.816 19.897 15.048 ;
     RECT  18.904 16.08 19.897 17.64 ;
     RECT  19.757 9.36 20.051 11.784 ;
     RECT  19.897 12.816 20.077 17.64 ;
     RECT  19.861 1.968 20.081 5.832 ;
     RECT  19.757 7.344 20.081 7.992 ;
     RECT  20.081 1.968 20.153 5.304 ;
     RECT  20.077 12.816 20.153 17.88 ;
     RECT  20.153 1.968 20.261 4.68 ;
     RECT  20.051 10.848 20.3 11.784 ;
     RECT  20.153 12.816 20.3 13.704 ;
     RECT  19.379 19.104 20.365 19.368 ;
     RECT  20.3 10.848 20.387 13.704 ;
     RECT  20.365 19.104 20.627 19.416 ;
     RECT  20.153 14.784 20.677 17.88 ;
     RECT  20.627 19.104 20.677 19.368 ;
     RECT  20.081 7.872 20.725 7.992 ;
     RECT  20.725 7.872 20.873 8.184 ;
     RECT  20.873 7.872 21.053 7.992 ;
     RECT  19.865 20.544 21.053 21.48 ;
     RECT  20.387 10.848 21.205 11.4 ;
     RECT  21.049 6.288 21.301 6.312 ;
     RECT  21.053 7.872 21.337 7.896 ;
     RECT  21.301 6.288 21.341 6.408 ;
     RECT  20.261 4.656 21.481 4.68 ;
     RECT  20.387 12.576 21.553 13.704 ;
     RECT  20.677 14.784 21.553 19.368 ;
     RECT  21.553 12.576 21.557 19.368 ;
     RECT  21.557 18.192 21.637 19.368 ;
     RECT  21.553 20.4 21.637 20.52 ;
     RECT  20.051 9.36 21.665 9.384 ;
     RECT  21.205 10.752 21.737 11.4 ;
     RECT  21.481 4.656 21.769 4.92 ;
     RECT  21.637 18.192 21.809 20.52 ;
     RECT  21.769 4.512 21.884 4.92 ;
     RECT  21.809 18.192 21.917 20.424 ;
     RECT  21.557 12.576 21.923 17.208 ;
     RECT  20.261 1.968 21.953 3.432 ;
     RECT  21.884 4.512 21.971 5.4 ;
     RECT  21.917 18.672 22.061 20.424 ;
     RECT  21.337 7.488 22.129 7.896 ;
     RECT  21.971 4.512 22.133 4.92 ;
     RECT  22.061 18.672 22.133 19.368 ;
     RECT  22.133 18.672 22.169 18.696 ;
     RECT  22.133 4.512 22.205 4.68 ;
     RECT  21.737 10.848 22.237 11.4 ;
     RECT  21.923 12.576 22.237 13.08 ;
     RECT  22.061 20.4 22.241 20.424 ;
     RECT  21.949 21.504 22.241 21.528 ;
     RECT  22.237 10.848 22.313 13.08 ;
     RECT  22.237 0.048 22.385 0.072 ;
     RECT  22.313 12.288 22.385 13.08 ;
     RECT  22.385 12.384 22.457 13.08 ;
     RECT  21.923 14.256 22.457 17.208 ;
     RECT  21.953 1.968 22.601 2.904 ;
     RECT  22.457 15.552 22.645 17.208 ;
     RECT  22.313 10.848 22.849 10.872 ;
     RECT  22.601 2.256 22.853 2.904 ;
     RECT  22.525 3.888 22.853 4.488 ;
     RECT  22.129 7.392 22.885 7.896 ;
     RECT  22.853 2.448 22.889 2.904 ;
     RECT  22.645 15.552 23.101 17.688 ;
     RECT  22.885 7.392 23.137 7.992 ;
     RECT  22.981 9.12 23.137 9.144 ;
     RECT  23.101 15.552 23.173 17.784 ;
     RECT  23.173 15.552 23.245 18.264 ;
     RECT  22.849 10.704 23.281 10.872 ;
     RECT  23.281 10.704 23.425 11.4 ;
     RECT  23.101 19.968 23.537 19.992 ;
     RECT  23.425 10.272 23.677 11.4 ;
     RECT  22.457 12.384 23.677 12.84 ;
     RECT  23.137 7.392 23.852 9.144 ;
     RECT  23.677 10.272 23.852 12.84 ;
     RECT  22.853 4.176 23.857 4.488 ;
     RECT  22.457 14.256 23.893 14.28 ;
     RECT  22.889 2.736 24.008 2.904 ;
     RECT  23.857 4.176 24.008 4.776 ;
     RECT  21.341 6.384 24.008 6.408 ;
     RECT  23.852 7.392 24.008 12.84 ;
     RECT  23.893 13.872 24.008 14.28 ;
     RECT  23.245 15.552 24.008 18.936 ;
     RECT  24.008 2.148 24.112 19.452 ;
     RECT  24.112 2.418 24.304 19.182 ;
     RECT  24.304 9.648 24.419 14.088 ;
     RECT  24.304 15.36 24.467 18.744 ;
     RECT  24.467 18.72 24.617 18.744 ;
     RECT  24.62 0.048 24.707 0.072 ;
     RECT  24.419 9.648 24.761 10.968 ;
     RECT  24.829 21.504 24.977 21.528 ;
     RECT  24.761 9.648 25.049 10.872 ;
     RECT  24.304 3.6 25.193 6.12 ;
     RECT  25.193 5.856 25.265 6.12 ;
     RECT  25.049 9.648 25.331 10.296 ;
     RECT  24.419 11.952 25.513 14.088 ;
     RECT  24.467 15.36 25.513 17.64 ;
     RECT  25.193 3.6 25.549 4.872 ;
     RECT  25.549 2.256 25.697 4.872 ;
     RECT  24.304 7.344 25.801 8.28 ;
     RECT  25.697 2.256 25.837 3.624 ;
     RECT  25.837 1.68 25.909 3.624 ;
     RECT  25.405 18.816 26.045 18.84 ;
     RECT  25.909 1.104 26.125 3.624 ;
     RECT  25.513 11.952 26.125 17.64 ;
     RECT  25.697 4.848 26.273 4.872 ;
     RECT  25.331 10.272 26.341 10.296 ;
     RECT  26.125 11.328 26.341 17.64 ;
     RECT  26.125 0.528 26.345 3.624 ;
     RECT  25.265 5.856 26.377 5.88 ;
     RECT  26.345 0.528 26.387 2.28 ;
     RECT  26.377 5.136 26.417 5.88 ;
     RECT  26.387 0.528 26.483 2.232 ;
     RECT  25.801 7.344 26.521 9.144 ;
     RECT  26.045 18.816 26.521 18.936 ;
     RECT  26.521 18.768 26.629 18.936 ;
     RECT  26.341 10.272 26.741 17.64 ;
     RECT  26.629 18.768 26.777 19.032 ;
     RECT  26.741 10.272 26.921 16.488 ;
     RECT  26.777 18.768 26.963 18.84 ;
     RECT  26.483 0.528 27.133 1.752 ;
     RECT  26.921 12.576 27.173 16.488 ;
     RECT  26.521 7.344 27.241 9.24 ;
     RECT  26.921 10.272 27.241 11.448 ;
     RECT  26.417 5.136 27.245 5.688 ;
     RECT  27.241 7.344 27.317 11.448 ;
     RECT  27.317 8.976 27.395 11.448 ;
     RECT  27.133 0.48 27.457 1.752 ;
     RECT  27.457 0.48 27.493 2.088 ;
     RECT  27.317 7.344 27.565 7.992 ;
     RECT  27.395 9.024 27.569 9.24 ;
     RECT  26.741 17.616 27.601 17.64 ;
     RECT  26.963 18.768 27.601 18.792 ;
     RECT  27.493 0.48 27.637 2.184 ;
     RECT  27.637 0.48 27.673 2.28 ;
     RECT  27.601 17.616 27.685 18.792 ;
     RECT  27.673 0.48 27.709 2.328 ;
     RECT  27.245 5.184 27.745 5.688 ;
     RECT  27.173 14.256 27.745 16.488 ;
     RECT  27.569 9.024 27.749 9.144 ;
     RECT  27.745 5.184 27.829 5.736 ;
     RECT  27.709 0.384 27.923 2.328 ;
     RECT  27.685 17.616 28.037 17.64 ;
     RECT  27.745 14.256 28.357 16.536 ;
     RECT  27.395 10.368 28.397 11.448 ;
     RECT  27.173 12.576 28.429 13.224 ;
     RECT  28.357 14.256 28.429 16.968 ;
     RECT  27.923 0.384 28.501 2.28 ;
     RECT  28.501 0.336 28.513 2.28 ;
     RECT  27.565 6.816 28.717 7.992 ;
     RECT  27.749 9.12 28.717 9.144 ;
     RECT  27.685 18.672 28.753 18.792 ;
     RECT  26.345 3.6 28.825 3.624 ;
     RECT  27.829 5.184 28.897 5.64 ;
     RECT  28.717 6.816 28.897 9.144 ;
     RECT  28.429 12.576 29.013 16.968 ;
     RECT  29.013 12.576 29.132 17.112 ;
     RECT  28.753 18.096 29.132 18.792 ;
     RECT  29.132 12.576 29.173 18.792 ;
     RECT  28.897 5.184 29.257 9.144 ;
     RECT  29.173 12.576 29.269 19.032 ;
     RECT  28.513 0.336 29.293 0.6 ;
     RECT  29.269 12.576 29.329 19.272 ;
     RECT  28.397 10.368 29.365 11.16 ;
     RECT  29.329 12.576 29.365 19.368 ;
     RECT  28.513 1.632 29.408 2.28 ;
     RECT  28.825 3.6 29.408 3.72 ;
     RECT  29.257 5.136 29.408 9.144 ;
     RECT  29.365 10.368 29.408 19.368 ;
     RECT  29.408 1.632 29.512 19.452 ;
     RECT  29.512 1.632 29.657 19.272 ;
     RECT  29.657 1.632 29.704 19.182 ;
     RECT  29.293 0.096 29.797 0.6 ;
     RECT  29.704 1.632 29.797 3.72 ;
     RECT  29.704 5.184 29.801 19.032 ;
     RECT  29.801 5.184 29.873 18.792 ;
     RECT  29.797 0.096 29.881 3.72 ;
     RECT  29.881 0.096 29.905 0.6 ;
     RECT  29.873 9.888 29.987 18.792 ;
     RECT  29.905 0.048 30.053 0.6 ;
     RECT  29.873 5.184 30.053 8.856 ;
     RECT  30.409 21.504 30.557 21.528 ;
     RECT  29.881 1.68 30.805 3.72 ;
     RECT  30.053 5.472 30.851 8.856 ;
     RECT  30.851 5.472 30.989 7.656 ;
     RECT  30.053 0.096 31.021 0.6 ;
     RECT  30.805 1.68 31.021 4.008 ;
     RECT  29.987 9.888 31.057 18.6 ;
     RECT  31.021 0.096 31.105 4.008 ;
     RECT  30.989 5.472 31.165 6.408 ;
     RECT  31.057 9.888 31.169 18.696 ;
     RECT  31.169 9.888 31.241 16.008 ;
     RECT  30.851 8.832 31.285 8.856 ;
     RECT  31.241 9.888 31.285 12.84 ;
     RECT  31.165 5.04 31.313 6.408 ;
     RECT  31.169 17.136 31.349 18.696 ;
     RECT  31.105 1.728 31.421 4.008 ;
     RECT  31.421 1.728 31.475 2.28 ;
     RECT  31.285 8.832 31.523 12.84 ;
     RECT  31.105 0.096 31.561 0.696 ;
     RECT  31.475 1.728 31.667 2.232 ;
     RECT  31.667 1.728 31.763 1.848 ;
     RECT  31.349 17.424 31.813 18.696 ;
     RECT  31.813 17.424 32.005 18.84 ;
     RECT  31.313 6.288 32.137 6.408 ;
     RECT  30.989 7.392 32.137 7.656 ;
     RECT  31.763 1.776 32.147 1.848 ;
     RECT  31.241 13.872 32.207 16.008 ;
     RECT  32.207 13.872 32.249 16.152 ;
     RECT  32.005 17.424 32.317 19.368 ;
     RECT  31.561 0.048 32.357 0.696 ;
     RECT  32.317 17.136 32.435 19.992 ;
     RECT  31.421 3.936 32.461 4.008 ;
     RECT  31.523 8.832 32.485 9.384 ;
     RECT  31.523 10.368 32.485 12.84 ;
     RECT  32.485 8.832 32.533 12.84 ;
     RECT  32.533 8.688 32.629 12.84 ;
     RECT  32.249 13.872 32.629 14.952 ;
     RECT  32.249 15.984 32.677 16.152 ;
     RECT  32.435 17.136 32.677 19.368 ;
     RECT  32.461 3.408 32.749 4.008 ;
     RECT  32.357 0.048 32.771 0.12 ;
     RECT  32.749 3.408 32.821 4.296 ;
     RECT  32.771 0.096 32.867 0.12 ;
     RECT  32.137 6.288 32.965 7.656 ;
     RECT  32.629 8.688 32.965 14.952 ;
     RECT  32.821 2.88 33.001 4.296 ;
     RECT  32.965 6.288 33.011 14.952 ;
     RECT  32.725 1.728 33.113 1.752 ;
     RECT  33.061 21.456 33.205 21.48 ;
     RECT  33.205 21.408 33.253 21.48 ;
     RECT  33.001 2.832 33.289 4.296 ;
     RECT  33.289 2.832 33.409 5.16 ;
     RECT  33.011 9.36 33.433 14.952 ;
     RECT  32.677 15.984 33.433 19.368 ;
     RECT  33.253 21.264 33.445 21.48 ;
     RECT  33.011 8.016 34.045 8.04 ;
     RECT  33.433 9.36 34.117 19.368 ;
     RECT  33.445 20.736 34.117 21.48 ;
     RECT  34.117 9.36 34.261 21.48 ;
     RECT  34.045 7.92 34.333 8.04 ;
     RECT  34.261 9.072 34.333 21.48 ;
     RECT  33.409 2.832 34.441 2.856 ;
     RECT  34.441 2.304 34.808 2.856 ;
     RECT  33.409 3.84 34.808 5.16 ;
     RECT  33.011 6.288 34.808 6.312 ;
     RECT  34.333 7.392 34.808 8.04 ;
     RECT  34.333 9.072 34.808 21.528 ;
     RECT  34.808 2.148 34.912 21.528 ;
     RECT  34.912 2.418 35.104 21.528 ;
     RECT  35.104 6.288 35.165 7.944 ;
     RECT  35.165 6.288 35.219 7.416 ;
     RECT  35.104 2.592 35.309 5.16 ;
     RECT  35.219 6.288 35.381 6.312 ;
     RECT  35.104 9.12 35.507 21.528 ;
     RECT  35.309 2.928 35.633 5.16 ;
     RECT  35.485 0.048 35.737 0.072 ;
     RECT  35.737 0.048 35.849 0.12 ;
     RECT  35.633 3.36 35.849 5.16 ;
     RECT  35.849 0.048 35.921 0.072 ;
     RECT  35.507 12.48 35.932 21.528 ;
     RECT  35.219 7.392 36.277 7.416 ;
     RECT  35.507 9.12 36.281 11.256 ;
     RECT  36.281 9.12 36.385 10.2 ;
     RECT  36.241 1.152 36.389 1.176 ;
     RECT  35.849 5.136 36.421 5.16 ;
     RECT  36.277 6.768 36.421 7.416 ;
     RECT  36.313 2.304 36.425 2.328 ;
     RECT  36.421 5.136 36.461 7.992 ;
     RECT  36.461 7.392 36.713 7.992 ;
     RECT  35.849 3.408 36.817 3.864 ;
     RECT  36.461 5.136 36.893 6.264 ;
     RECT  35.932 12.576 37.043 21.528 ;
     RECT  36.893 5.328 37.289 6.264 ;
     RECT  37.388 0.048 37.465 0.072 ;
     RECT  36.281 11.232 37.465 11.256 ;
     RECT  37.465 0.048 37.532 0.12 ;
     RECT  36.817 2.4 37.573 3.864 ;
     RECT  37.532 0.048 37.619 0.216 ;
     RECT  36.713 7.968 37.645 7.992 ;
     RECT  36.385 9.072 37.645 10.2 ;
     RECT  37.645 7.968 37.669 10.2 ;
     RECT  37.465 11.232 37.669 11.304 ;
     RECT  37.573 2.208 37.717 3.864 ;
     RECT  37.645 6.624 37.717 6.648 ;
     RECT  37.669 7.968 37.9 11.304 ;
     RECT  37.717 6.624 37.901 6.888 ;
     RECT  37.043 21.504 37.901 21.528 ;
     RECT  37.901 6.864 37.933 6.888 ;
     RECT  37.933 6.864 37.969 6.984 ;
     RECT  37.9 7.968 37.969 7.992 ;
     RECT  37.969 6.864 38.009 7.992 ;
     RECT  37.9 9.072 38.401 11.304 ;
     RECT  37.043 12.576 38.437 20.232 ;
     RECT  37.289 5.328 38.441 5.352 ;
     RECT  38.437 12.576 38.441 21.48 ;
     RECT  38.441 12.576 38.483 19.464 ;
     RECT  37.619 0.048 38.585 0.072 ;
     RECT  38.441 20.496 38.675 21.48 ;
     RECT  38.009 6.864 38.693 7.608 ;
     RECT  38.483 12.576 38.693 19.416 ;
     RECT  37.717 1.728 38.729 3.864 ;
     RECT  38.729 1.728 38.765 1.752 ;
     RECT  38.675 20.496 38.771 21.432 ;
     RECT  38.729 2.832 38.789 3.864 ;
     RECT  38.789 2.832 38.873 3.96 ;
     RECT  38.725 5.376 39.061 5.4 ;
     RECT  39.061 5.376 39.107 6.264 ;
     RECT  38.401 9.072 39.157 11.544 ;
     RECT  38.693 12.576 39.157 19.368 ;
     RECT  39.157 9.072 39.164 19.368 ;
     RECT  38.693 7.584 39.205 7.608 ;
     RECT  39.164 8.64 39.205 19.368 ;
     RECT  38.771 20.496 39.589 20.52 ;
     RECT  39.589 20.448 39.925 20.52 ;
     RECT  39.107 6.24 39.949 6.264 ;
     RECT  39.205 7.584 39.949 19.368 ;
     RECT  38.873 2.832 40.069 3.864 ;
     RECT  40.021 0.048 40.133 0.072 ;
     RECT  39.949 6.24 40.165 19.368 ;
     RECT  39.925 20.448 40.165 21.432 ;
     RECT  40.069 2.832 40.208 4.776 ;
     RECT  40.165 6.24 40.208 21.432 ;
     RECT  40.208 2.148 40.261 21.432 ;
     RECT  40.261 2.148 40.312 21.48 ;
     RECT  40.312 2.256 40.504 21.48 ;
     RECT  40.504 7.728 40.643 9.144 ;
     RECT  40.504 10.224 40.643 21.48 ;
     RECT  40.504 5.472 40.645 6.264 ;
     RECT  40.643 10.224 40.787 19.416 ;
     RECT  40.645 5.472 41.075 6.072 ;
     RECT  41.075 5.712 41.113 6.072 ;
     RECT  40.504 2.256 41.149 4.056 ;
     RECT  41.149 2.544 41.177 4.056 ;
     RECT  40.643 20.448 41.177 21.48 ;
     RECT  41.177 2.88 41.465 4.056 ;
     RECT  40.787 12.432 41.465 19.416 ;
     RECT  41.465 3.072 41.533 4.056 ;
     RECT  40.643 7.968 41.573 9.144 ;
     RECT  41.573 7.968 41.692 9.096 ;
     RECT  40.787 10.224 41.785 10.968 ;
     RECT  41.465 12.432 41.785 12.84 ;
     RECT  41.785 10.224 41.825 12.84 ;
     RECT  41.692 7.968 41.929 7.992 ;
     RECT  41.929 7.872 41.969 7.992 ;
     RECT  41.177 21.36 41.969 21.48 ;
     RECT  41.533 3.072 42.109 4.536 ;
     RECT  41.113 5.712 42.109 5.736 ;
     RECT  42.109 3.072 42.325 5.736 ;
     RECT  42.325 3.072 42.329 6.312 ;
     RECT  42.181 20.496 42.373 20.568 ;
     RECT  42.329 3.072 42.505 4.824 ;
     RECT  42.505 2.928 42.517 4.824 ;
     RECT  41.465 14.016 42.565 19.416 ;
     RECT  42.373 20.448 42.565 20.568 ;
     RECT  41.825 10.656 42.613 12.84 ;
     RECT  42.565 14.016 42.613 20.568 ;
     RECT  41.692 9.072 42.617 9.096 ;
     RECT  41.42 0.048 42.733 0.072 ;
     RECT  42.613 10.656 42.829 20.568 ;
     RECT  42.329 6.288 42.901 6.312 ;
     RECT  42.517 2.88 42.977 4.824 ;
     RECT  42.661 1.728 43.049 1.752 ;
     RECT  42.977 2.88 43.049 4.152 ;
     RECT  42.829 10.416 43.085 20.568 ;
     RECT  43.085 14.688 43.091 20.568 ;
     RECT  42.901 6.288 43.121 6.888 ;
     RECT  43.121 6.288 43.157 6.696 ;
     RECT  41.969 7.872 43.157 7.896 ;
     RECT  43.091 14.688 43.193 20.52 ;
     RECT  43.049 2.88 43.229 3.72 ;
     RECT  43.229 3.36 43.265 3.72 ;
     RECT  43.265 3.36 43.337 3.432 ;
     RECT  43.085 10.416 43.409 13.512 ;
     RECT  43.409 10.416 43.481 12.6 ;
     RECT  43.481 12.432 43.553 12.6 ;
     RECT  43.193 16.416 43.553 20.52 ;
     RECT  43.553 16.512 43.625 20.52 ;
     RECT  43.628 5.616 43.715 5.64 ;
     RECT  43.625 16.512 43.769 19.464 ;
     RECT  43.481 10.416 43.837 10.824 ;
     RECT  43.625 20.496 43.985 20.52 ;
     RECT  44.081 21.456 44.165 21.48 ;
     RECT  43.477 2.256 44.291 2.28 ;
     RECT  43.769 16.512 44.309 19.368 ;
     RECT  43.157 6.672 44.377 6.696 ;
     RECT  43.337 3.36 44.387 3.384 ;
     RECT  43.837 10.176 44.629 10.824 ;
     RECT  43.193 14.688 44.665 14.952 ;
     RECT  44.629 10.176 44.737 11.016 ;
     RECT  43.553 12.576 44.737 12.6 ;
     RECT  44.665 14.688 44.737 15.288 ;
     RECT  44.089 4.656 44.773 4.68 ;
     RECT  44.732 21.504 44.819 21.528 ;
     RECT  44.737 10.176 45.169 12.6 ;
     RECT  45.169 9.504 45.277 12.6 ;
     RECT  45.253 1.728 45.308 1.752 ;
     RECT  44.737 14.4 45.493 15.288 ;
     RECT  44.309 16.512 45.493 19.272 ;
     RECT  45.308 1.728 45.608 2.28 ;
     RECT  44.773 4.416 45.608 4.68 ;
     RECT  44.377 6.672 45.608 7.656 ;
     RECT  45.277 9.456 45.608 12.6 ;
     RECT  45.493 14.4 45.608 19.272 ;
     RECT  45.608 1.728 45.637 19.452 ;
     RECT  45.637 1.392 45.821 19.452 ;
     RECT  45.821 1.728 45.853 19.452 ;
     RECT  45.421 20.496 45.853 20.52 ;
     RECT  45.853 1.728 45.904 20.52 ;
     RECT  45.904 4.416 46.019 7.416 ;
     RECT  45.904 10.608 46.037 20.52 ;
     RECT  45.904 1.728 46.081 1.944 ;
     RECT  45.853 21.504 46.145 21.528 ;
     RECT  46.037 15.456 46.577 20.52 ;
     RECT  45.904 3.408 46.835 3.432 ;
     RECT  45.904 9.504 46.892 9.528 ;
     RECT  46.019 6.48 46.933 7.416 ;
     RECT  46.019 4.416 47.029 4.68 ;
     RECT  46.933 6.48 47.077 7.848 ;
     RECT  46.037 10.608 47.113 14.424 ;
     RECT  46.577 15.456 47.113 19.224 ;
     RECT  47.077 6.192 47.171 7.848 ;
     RECT  47.113 10.608 47.189 19.224 ;
     RECT  46.892 9.168 47.257 9.528 ;
     RECT  47.189 10.608 47.26 11.4 ;
     RECT  47.257 8.976 47.297 9.528 ;
     RECT  47.077 0.528 47.411 0.552 ;
     RECT  47.26 10.608 47.437 10.92 ;
     RECT  47.171 6.528 47.473 7.848 ;
     RECT  47.297 8.976 47.473 9.192 ;
     RECT  47.189 12.48 47.477 19.224 ;
     RECT  47.477 12.576 47.617 19.224 ;
     RECT  47.617 12.576 47.801 19.272 ;
     RECT  46.933 2.928 47.833 3.048 ;
     RECT  47.029 4.416 47.833 5.112 ;
     RECT  46.081 1.728 47.845 1.896 ;
     RECT  47.509 21.504 47.873 21.528 ;
     RECT  47.833 2.928 47.917 5.112 ;
     RECT  47.845 1.728 47.933 1.944 ;
     RECT  47.917 2.928 47.933 3.048 ;
     RECT  46.577 20.496 47.981 20.52 ;
     RECT  47.917 4.512 48.157 5.112 ;
     RECT  47.473 6.528 48.157 9.192 ;
     RECT  48.157 4.512 48.161 9.192 ;
     RECT  48.161 4.512 48.323 6.984 ;
     RECT  48.013 0.096 48.371 0.12 ;
     RECT  47.801 12.576 48.385 14.472 ;
     RECT  47.801 15.456 48.449 19.272 ;
     RECT  48.161 8.064 48.469 9.192 ;
     RECT  47.437 10.224 48.469 10.92 ;
     RECT  48.469 8.064 48.485 10.92 ;
     RECT  47.933 1.728 48.593 3.048 ;
     RECT  48.323 6.528 48.593 6.984 ;
     RECT  48.517 0.576 48.661 0.6 ;
     RECT  48.593 1.728 48.661 2.856 ;
     RECT  48.593 6.672 48.773 6.984 ;
     RECT  48.773 6.672 48.845 6.888 ;
     RECT  48.449 15.744 49.201 19.272 ;
     RECT  48.485 8.208 49.273 10.92 ;
     RECT  48.661 0.576 49.345 2.856 ;
     RECT  48.385 13.824 49.417 14.472 ;
     RECT  49.201 15.744 49.417 19.368 ;
     RECT  48.323 4.944 49.597 5.16 ;
     RECT  48.845 6.672 49.597 6.696 ;
     RECT  49.273 8.208 49.633 11.016 ;
     RECT  49.345 0.528 49.637 2.856 ;
     RECT  49.637 0.528 49.709 2.52 ;
     RECT  49.597 4.944 49.813 6.696 ;
     RECT  49.709 0.528 49.885 2.28 ;
     RECT  48.385 12.576 49.993 12.6 ;
     RECT  49.417 13.824 49.993 19.368 ;
     RECT  49.921 21.504 50.051 21.528 ;
     RECT  49.813 4.224 50.053 6.696 ;
     RECT  49.633 8.016 50.053 11.016 ;
     RECT  50.053 4.224 50.605 11.016 ;
     RECT  49.885 0.48 50.677 2.28 ;
     RECT  50.605 3.408 50.677 11.016 ;
     RECT  50.677 0.48 50.749 11.016 ;
     RECT  49.993 12.576 50.749 19.368 ;
     RECT  50.749 0.48 50.869 19.368 ;
     RECT  50.869 0.144 51.008 19.368 ;
     RECT  51.008 0.144 51.205 19.452 ;
     RECT  51.101 20.496 51.205 20.52 ;
     RECT  51.205 0.144 51.304 20.52 ;
     RECT  51.304 0.144 51.469 4.344 ;
     RECT  51.469 0.096 51.725 4.344 ;
     RECT  51.304 8.976 51.797 14.424 ;
     RECT  51.725 0.096 51.827 4.248 ;
     RECT  51.304 15.408 51.868 20.52 ;
     RECT  51.868 15.408 51.875 18.216 ;
     RECT  51.797 9.12 51.905 14.424 ;
     RECT  51.868 19.2 52.153 20.52 ;
     RECT  51.304 5.616 52.204 6.888 ;
     RECT  52.204 6.048 52.301 6.888 ;
     RECT  51.827 0.096 52.517 2.52 ;
     RECT  51.304 7.92 52.553 7.944 ;
     RECT  52.517 0.096 52.633 0.552 ;
     RECT  52.153 19.2 52.645 20.568 ;
     RECT  51.827 3.984 52.661 4.248 ;
     RECT  52.301 6.048 52.769 6.696 ;
     RECT  52.645 19.2 52.769 21.48 ;
     RECT  51.875 15.408 52.801 17.4 ;
     RECT  52.517 1.728 52.873 2.52 ;
     RECT  52.661 3.984 52.873 4.008 ;
     RECT  52.769 19.2 52.892 20.52 ;
     RECT  51.905 9.12 52.909 14.232 ;
     RECT  52.801 15.264 52.909 17.4 ;
     RECT  52.909 9.12 53.057 17.4 ;
     RECT  53.057 9.792 53.123 13.848 ;
     RECT  53.057 15.264 53.201 17.4 ;
     RECT  52.633 0.528 53.267 0.552 ;
     RECT  52.769 6.048 53.377 6.072 ;
     RECT  52.892 18.816 53.417 20.52 ;
     RECT  52.873 1.728 53.521 4.008 ;
     RECT  53.201 15.504 53.549 17.4 ;
     RECT  53.549 15.504 53.593 17.688 ;
     RECT  53.417 18.816 53.593 19.464 ;
     RECT  53.605 7.248 53.665 7.272 ;
     RECT  53.521 1.68 53.699 4.008 ;
     RECT  53.593 15.504 53.993 19.464 ;
     RECT  53.377 5.712 54.092 6.072 ;
     RECT  53.665 7.248 54.092 7.896 ;
     RECT  53.699 3.984 54.097 4.008 ;
     RECT  54.097 3.984 54.137 4.488 ;
     RECT  53.123 9.792 54.169 12.6 ;
     RECT  54.092 5.712 54.179 7.896 ;
     RECT  53.417 20.496 54.236 20.52 ;
     RECT  54.169 9.168 54.241 12.6 ;
     RECT  53.699 1.68 54.389 2.856 ;
     RECT  53.993 15.696 54.461 19.464 ;
     RECT  54.241 9.072 54.637 12.6 ;
     RECT  53.123 13.68 54.637 13.848 ;
     RECT  54.236 20.496 54.757 20.568 ;
     RECT  54.461 18.048 54.781 19.464 ;
     RECT  54.757 20.496 54.781 21.48 ;
     RECT  54.781 18.048 54.785 21.48 ;
     RECT  54.785 18.24 54.965 21.48 ;
     RECT  54.137 4.464 55.177 4.488 ;
     RECT  55.177 4.464 55.283 5.16 ;
     RECT  54.637 9.072 55.289 13.848 ;
     RECT  54.179 6.24 55.429 7.896 ;
     RECT  54.461 15.696 55.429 16.92 ;
     RECT  54.389 1.68 55.501 2.376 ;
     RECT  55.501 1.68 55.645 2.52 ;
     RECT  54.965 18.24 55.649 20.52 ;
     RECT  55.645 0.192 55.717 2.52 ;
     RECT  55.429 6.24 55.717 7.992 ;
     RECT  55.717 0.048 55.763 2.712 ;
     RECT  55.429 15.216 55.813 16.92 ;
     RECT  55.813 15.216 55.969 17.064 ;
     RECT  55.649 18.24 55.969 19.452 ;
     RECT  55.763 1.152 56.189 2.712 ;
     RECT  55.649 20.496 56.245 20.52 ;
     RECT  56.189 1.68 56.408 2.712 ;
     RECT  55.283 4.464 56.408 5.112 ;
     RECT  55.717 6.096 56.408 7.992 ;
     RECT  55.289 9.072 56.408 9.096 ;
     RECT  55.289 10.32 56.408 13.848 ;
     RECT  55.969 15.216 56.408 19.452 ;
     RECT  56.408 1.68 56.512 19.452 ;
     RECT  56.512 1.68 56.585 19.368 ;
     RECT  56.585 2.064 56.704 19.368 ;
     RECT  56.704 6.096 56.801 6.264 ;
     RECT  56.245 20.496 57.157 21.432 ;
     RECT  57.157 20.448 57.161 21.432 ;
     RECT  56.704 13.68 57.269 19.368 ;
     RECT  55.763 0.048 57.373 0.072 ;
     RECT  57.161 20.448 57.485 20.472 ;
     RECT  57.373 0.048 57.521 0.168 ;
     RECT  56.704 2.064 57.521 4.536 ;
     RECT  56.704 7.344 57.587 7.992 ;
     RECT  56.801 6.24 57.769 6.264 ;
     RECT  57.587 7.344 57.769 7.896 ;
     RECT  57.637 21.456 57.845 21.48 ;
     RECT  57.521 2.208 57.881 4.536 ;
     RECT  57.269 15.552 57.913 19.368 ;
     RECT  57.769 6.24 57.985 7.896 ;
     RECT  57.913 15.552 58.117 19.464 ;
     RECT  57.881 2.4 58.133 4.536 ;
     RECT  58.133 2.736 58.165 4.536 ;
     RECT  57.985 5.712 58.165 7.896 ;
     RECT  56.704 11.424 58.165 12.696 ;
     RECT  57.269 13.68 58.165 14.28 ;
     RECT  56.704 10.32 58.169 10.344 ;
     RECT  58.165 2.736 58.241 7.896 ;
     RECT  56.704 9.072 58.241 9.096 ;
     RECT  58.165 11.424 58.273 14.28 ;
     RECT  58.241 2.736 58.277 6.312 ;
     RECT  58.277 2.736 58.385 4.536 ;
     RECT  58.273 10.944 58.412 14.28 ;
     RECT  58.385 2.736 58.457 3.816 ;
     RECT  58.412 10.944 58.556 14.328 ;
     RECT  58.117 15.552 58.556 19.944 ;
     RECT  58.457 2.736 58.565 3.432 ;
     RECT  58.556 10.944 58.693 19.944 ;
     RECT  58.309 21.264 58.693 21.432 ;
     RECT  57.521 0.048 58.817 0.072 ;
     RECT  58.693 10.944 58.817 21.432 ;
     RECT  58.817 15.84 58.853 19.464 ;
     RECT  58.853 15.84 58.961 19.368 ;
     RECT  58.885 9.696 59.173 9.72 ;
     RECT  58.817 10.944 59.173 14.328 ;
     RECT  58.241 7.296 59.269 7.896 ;
     RECT  59.173 9.696 59.315 14.328 ;
     RECT  58.817 20.496 59.353 21.432 ;
     RECT  59.413 2.256 59.501 2.28 ;
     RECT  58.277 5.712 59.569 6.312 ;
     RECT  59.569 5.088 59.641 6.312 ;
     RECT  59.269 7.296 59.641 8.376 ;
     RECT  59.641 5.088 59.644 8.376 ;
     RECT  59.315 9.696 59.651 13.128 ;
     RECT  59.651 10.848 59.681 13.128 ;
     RECT  59.315 14.208 59.797 14.328 ;
     RECT  59.644 5.088 59.897 7.896 ;
     RECT  58.961 15.84 59.941 19.272 ;
     RECT  59.353 20.496 59.941 21.528 ;
     RECT  59.797 14.208 59.996 14.568 ;
     RECT  59.941 15.84 59.996 21.528 ;
     RECT  59.897 5.376 60.113 7.896 ;
     RECT  60.113 5.568 60.329 7.896 ;
     RECT  59.996 14.208 60.365 21.528 ;
     RECT  59.681 10.896 60.373 13.128 ;
     RECT  60.365 14.208 60.373 19.224 ;
     RECT  59.651 9.696 60.433 9.768 ;
     RECT  60.329 5.568 60.473 5.736 ;
     RECT  60.433 9.6 60.473 9.768 ;
     RECT  60.365 20.496 60.653 21.528 ;
     RECT  60.373 10.896 60.709 19.224 ;
     RECT  60.757 1.248 60.805 1.272 ;
     RECT  60.805 1.152 60.851 1.272 ;
     RECT  60.851 1.152 60.892 1.176 ;
     RECT  58.565 3.408 60.901 3.432 ;
     RECT  60.329 6.864 60.937 7.896 ;
     RECT  60.901 3.408 61.045 3.96 ;
     RECT  61.045 2.832 61.693 3.96 ;
     RECT  60.937 6.864 61.729 7.992 ;
     RECT  61.693 2.832 61.808 4.152 ;
     RECT  60.473 5.568 61.808 5.592 ;
     RECT  61.729 6.816 61.808 7.992 ;
     RECT  60.473 9.6 61.808 9.624 ;
     RECT  60.709 10.704 61.808 19.224 ;
     RECT  61.808 2.148 61.912 19.452 ;
     RECT  61.912 2.418 62.104 19.416 ;
     RECT  61.765 0.048 62.129 0.072 ;
     RECT  62.104 3.888 62.129 6.936 ;
     RECT  62.104 8.976 62.165 9.624 ;
     RECT  62.104 7.968 62.237 7.992 ;
     RECT  60.653 20.496 62.237 20.52 ;
     RECT  62.129 3.888 62.309 6.888 ;
     RECT  62.309 6.768 62.381 6.888 ;
     RECT  60.653 21.504 62.531 21.528 ;
     RECT  62.381 6.816 62.597 6.888 ;
     RECT  62.581 0.528 62.705 0.552 ;
     RECT  62.104 10.8 62.705 13.032 ;
     RECT  62.705 10.8 62.741 11.976 ;
     RECT  62.597 6.816 62.849 6.84 ;
     RECT  62.309 3.888 63.065 5.064 ;
     RECT  62.917 2.256 63.133 2.28 ;
     RECT  62.705 13.008 63.385 13.032 ;
     RECT  62.104 14.112 63.385 19.416 ;
     RECT  62.741 11.952 63.569 11.976 ;
     RECT  63.133 2.256 63.635 2.856 ;
     RECT  62.165 8.976 63.74 9 ;
     RECT  62.741 10.8 63.749 10.824 ;
     RECT  63.385 13.008 63.749 19.416 ;
     RECT  63.635 2.256 63.781 2.28 ;
     RECT  63.74 8.976 63.781 9.384 ;
     RECT  63.565 21.504 63.785 21.528 ;
     RECT  63.781 2.208 63.923 2.28 ;
     RECT  63.749 13.008 63.965 14.328 ;
     RECT  63.884 7.776 63.971 7.8 ;
     RECT  63.965 13.008 64.001 14.232 ;
     RECT  63.923 2.256 64.145 2.28 ;
     RECT  64.177 5.28 64.285 5.304 ;
     RECT  64.001 13.008 64.357 13.56 ;
     RECT  64.069 6.624 64.393 6.888 ;
     RECT  63.749 15.36 64.396 19.416 ;
     RECT  63.781 8.976 64.501 10.056 ;
     RECT  64.789 2.832 64.937 2.856 ;
     RECT  64.357 12.912 64.981 13.56 ;
     RECT  64.396 15.36 65.077 19.368 ;
     RECT  64.285 4.944 65.132 5.304 ;
     RECT  64.393 6.288 65.132 6.888 ;
     RECT  65.077 15.264 65.189 19.368 ;
     RECT  64.981 12.816 65.329 13.56 ;
     RECT  65.221 11.808 65.473 11.832 ;
     RECT  65.329 12.816 65.473 14.232 ;
     RECT  65.473 11.808 65.509 14.232 ;
     RECT  65.189 15.264 65.513 19.32 ;
     RECT  65.132 4.944 65.549 6.888 ;
     RECT  65.509 11.472 65.555 14.232 ;
     RECT  65.555 11.472 65.557 13.176 ;
     RECT  64.501 8.496 65.581 10.056 ;
     RECT  65.581 8.208 65.605 10.056 ;
     RECT  65.549 6.576 65.837 6.888 ;
     RECT  65.837 6.672 65.909 6.888 ;
     RECT  65.605 7.92 65.945 10.056 ;
     RECT  65.557 11.472 66.277 12.024 ;
     RECT  65.557 13.152 66.589 13.176 ;
     RECT  65.555 14.208 66.589 14.232 ;
     RECT  65.513 15.264 66.733 15.432 ;
     RECT  66.733 15.264 66.764 15.96 ;
     RECT  65.513 16.944 66.764 19.32 ;
     RECT  66.589 13.152 66.877 14.232 ;
     RECT  66.764 15.264 66.877 19.32 ;
     RECT  66.877 13.152 66.913 19.32 ;
     RECT  66.725 2.832 66.949 2.856 ;
     RECT  66.277 11.328 67.021 12.024 ;
     RECT  66.913 13.056 67.021 19.32 ;
     RECT  67.021 11.328 67.057 19.32 ;
     RECT  65.945 8.208 67.165 10.056 ;
     RECT  66.949 2.304 67.208 2.904 ;
     RECT  66.157 3.888 67.208 3.912 ;
     RECT  65.549 4.944 67.208 5.496 ;
     RECT  65.909 6.672 67.208 6.696 ;
     RECT  67.165 7.728 67.208 10.056 ;
     RECT  67.057 11.184 67.208 19.32 ;
     RECT  67.208 2.148 67.504 19.452 ;
     RECT  67.504 2.148 67.525 10.248 ;
     RECT  67.504 12 67.777 19.452 ;
     RECT  67.597 20.496 67.777 20.52 ;
     RECT  67.633 0.528 67.858 0.552 ;
     RECT  67.858 0.48 67.859 0.552 ;
     RECT  67.859 0.48 67.955 0.504 ;
     RECT  67.525 2.016 67.993 10.248 ;
     RECT  67.993 1.776 67.997 10.248 ;
     RECT  67.997 1.776 68.005 4.536 ;
     RECT  67.777 12 68.033 20.52 ;
     RECT  68.005 1.728 68.101 4.536 ;
     RECT  68.033 12 68.213 19.992 ;
     RECT  68.101 1.68 68.321 4.536 ;
     RECT  68.213 12 68.339 19.416 ;
     RECT  67.997 5.952 68.401 10.248 ;
     RECT  68.321 3.984 68.465 4.536 ;
     RECT  68.401 7.728 68.537 10.248 ;
     RECT  68.537 9.216 68.572 10.248 ;
     RECT  68.321 1.68 68.821 2.952 ;
     RECT  68.572 9.312 68.825 10.248 ;
     RECT  68.78 21.36 68.886 21.48 ;
     RECT  68.339 12 68.897 19.224 ;
     RECT  68.537 7.728 68.933 8.232 ;
     RECT  68.886 21.36 68.969 21.384 ;
     RECT  68.897 12 69.059 19.176 ;
     RECT  68.821 1.104 69.157 2.952 ;
     RECT  69.059 13.056 69.185 19.176 ;
     RECT  68.465 4.512 69.325 4.536 ;
     RECT  68.401 5.952 69.325 6.696 ;
     RECT  69.059 12 69.433 12.024 ;
     RECT  68.825 9.504 69.437 10.248 ;
     RECT  69.157 1.104 69.491 2.28 ;
     RECT  69.325 4.512 69.541 6.696 ;
     RECT  69.185 13.056 69.545 15.72 ;
     RECT  69.433 11.376 69.548 12.024 ;
     RECT  69.437 9.552 69.689 10.248 ;
     RECT  69.541 3.552 69.905 6.696 ;
     RECT  69.545 15.024 70.067 15.72 ;
     RECT  69.185 16.992 70.309 19.176 ;
     RECT  70.309 16.992 70.369 19.272 ;
     RECT  69.689 9.648 70.477 10.248 ;
     RECT  69.548 11.28 70.477 12.024 ;
     RECT  69.545 13.056 70.513 13.848 ;
     RECT  70.477 9.648 70.625 12.024 ;
     RECT  68.933 7.872 70.657 8.232 ;
     RECT  70.625 9.648 70.661 10.728 ;
     RECT  70.661 9.648 70.691 10.248 ;
     RECT  70.067 15.024 70.729 15.192 ;
     RECT  69.905 3.552 70.873 6.552 ;
     RECT  70.873 3.408 70.949 6.552 ;
     RECT  69.491 1.728 70.981 2.28 ;
     RECT  70.949 3.408 70.981 4.248 ;
     RECT  70.981 1.728 71.065 4.248 ;
     RECT  70.693 20.496 71.077 20.52 ;
     RECT  70.949 5.472 71.197 6.552 ;
     RECT  70.657 7.872 71.197 8.568 ;
     RECT  71.065 1.728 71.233 2.28 ;
     RECT  71.197 5.472 71.237 8.568 ;
     RECT  70.625 11.76 71.269 12.024 ;
     RECT  70.513 13.008 71.269 13.848 ;
     RECT  71.233 1.152 71.317 2.28 ;
     RECT  71.269 11.76 71.377 13.848 ;
     RECT  70.729 14.832 71.377 15.192 ;
     RECT  70.369 16.992 71.413 19.416 ;
     RECT  71.237 8.544 71.417 8.568 ;
     RECT  71.413 16.56 71.593 19.416 ;
     RECT  71.377 11.76 71.737 15.192 ;
     RECT  71.593 16.224 71.749 19.416 ;
     RECT  71.077 20.448 71.749 20.52 ;
     RECT  71.701 0.528 71.891 0.552 ;
     RECT  71.065 3.552 72.061 4.248 ;
     RECT  71.237 5.472 72.061 7.464 ;
     RECT  71.749 16.224 72.133 20.52 ;
     RECT  71.317 1.728 72.169 2.28 ;
     RECT  72.061 3.552 72.169 7.464 ;
     RECT  71.737 11.424 72.205 15.192 ;
     RECT  72.133 16.224 72.205 21.432 ;
     RECT  72.205 11.424 72.241 21.432 ;
     RECT  72.169 1.728 72.349 7.464 ;
     RECT  72.349 0.576 72.38 7.464 ;
     RECT  70.691 9.792 72.385 9.816 ;
     RECT  72.241 11.424 72.385 21.48 ;
     RECT  72.385 9.216 72.413 9.816 ;
     RECT  72.38 0.576 72.469 7.608 ;
     RECT  72.413 9.12 72.469 9.816 ;
     RECT  72.469 0.576 72.608 9.816 ;
     RECT  72.385 10.8 72.608 21.48 ;
     RECT  72.608 0.576 72.904 21.48 ;
     RECT  72.904 11.952 72.965 21.48 ;
     RECT  72.904 0.576 72.997 7.944 ;
     RECT  72.997 0.096 73.073 7.944 ;
     RECT  73.073 5.856 73.091 7.944 ;
     RECT  73.073 0.096 73.235 4.152 ;
     RECT  73.235 1.728 73.289 4.152 ;
     RECT  73.235 0.096 73.469 0.6 ;
     RECT  73.091 6.288 73.475 7.944 ;
     RECT  73.475 6.288 73.577 6.6 ;
     RECT  73.469 0.576 73.657 0.6 ;
     RECT  72.965 13.104 73.865 21.48 ;
     RECT  72.904 10.848 73.909 10.92 ;
     RECT  72.965 11.952 73.909 11.976 ;
     RECT  73.865 13.104 74.009 20.472 ;
     RECT  74.009 15.024 74.051 20.472 ;
     RECT  73.289 4.128 74.101 4.152 ;
     RECT  73.475 7.632 74.221 7.944 ;
     RECT  72.904 9.36 74.221 9.384 ;
     RECT  73.289 1.728 74.233 2.856 ;
     RECT  73.909 10.848 74.257 11.976 ;
     RECT  74.009 13.104 74.257 13.704 ;
     RECT  74.221 7.632 74.261 9.576 ;
     RECT  74.233 1.728 74.291 2.76 ;
     RECT  74.261 9.552 74.365 9.576 ;
     RECT  74.257 10.848 74.365 13.704 ;
     RECT  74.261 7.632 74.387 8.568 ;
     RECT  74.101 4.128 74.761 5.112 ;
     RECT  73.865 21.456 74.765 21.48 ;
     RECT  74.051 15.648 74.833 20.472 ;
     RECT  74.365 9.552 74.909 13.704 ;
     RECT  74.909 12.864 75.121 13.704 ;
     RECT  74.761 4.128 75.157 5.16 ;
     RECT  73.577 6.288 75.301 6.552 ;
     RECT  75.301 6.192 75.385 6.552 ;
     RECT  74.833 15.648 75.445 20.52 ;
     RECT  75.157 3.984 75.491 5.16 ;
     RECT  74.291 1.728 75.493 1.944 ;
     RECT  74.909 9.552 75.517 11.544 ;
     RECT  75.121 12.864 75.625 13.848 ;
     RECT  75.445 14.832 75.625 20.52 ;
     RECT  75.625 12.864 75.773 20.52 ;
     RECT  75.773 14.832 75.779 20.52 ;
     RECT  75.491 3.984 75.827 4.008 ;
     RECT  75.773 12.864 75.881 13.848 ;
     RECT  75.493 1.728 75.884 2.904 ;
     RECT  74.387 7.632 76.025 7.992 ;
     RECT  75.517 9.504 76.115 11.544 ;
     RECT  76.201 0.576 76.273 0.6 ;
     RECT  76.273 0.096 76.385 0.6 ;
     RECT  76.115 10.704 76.417 11.544 ;
     RECT  76.115 9.504 76.525 9.72 ;
     RECT  75.491 5.04 76.561 5.16 ;
     RECT  75.385 6.288 76.561 6.552 ;
     RECT  75.884 1.728 76.573 3.432 ;
     RECT  76.573 1.728 76.745 3.336 ;
     RECT  76.417 10.704 76.837 11.88 ;
     RECT  75.881 12.864 76.837 13.32 ;
     RECT  76.385 0.576 76.925 0.6 ;
     RECT  76.561 5.04 76.933 6.552 ;
     RECT  76.025 7.632 76.933 7.656 ;
     RECT  76.837 10.704 76.993 13.32 ;
     RECT  75.779 14.832 77.065 14.856 ;
     RECT  75.779 15.84 77.065 20.52 ;
     RECT  76.933 5.04 77.209 7.656 ;
     RECT  76.993 10.704 77.461 13.656 ;
     RECT  77.065 14.832 77.461 20.52 ;
     RECT  77.353 1.152 77.501 1.176 ;
     RECT  76.525 9.072 77.612 9.72 ;
     RECT  77.461 10.704 78.005 20.52 ;
     RECT  76.745 2.304 78.008 3.336 ;
     RECT  77.209 4.416 78.008 7.656 ;
     RECT  77.612 8.64 78.008 9.72 ;
     RECT  78.005 10.704 78.008 20.472 ;
     RECT  78.008 2.148 78.077 20.472 ;
     RECT  78.077 2.148 78.112 20.376 ;
     RECT  77.893 0.048 78.289 0.072 ;
     RECT  78.112 2.208 78.304 20.376 ;
     RECT  78.289 0.048 78.617 0.216 ;
     RECT  78.304 3.456 78.617 7.656 ;
     RECT  78.973 1.152 79.085 1.176 ;
     RECT  78.617 0.048 79.121 0.168 ;
     RECT  78.304 2.208 79.297 2.232 ;
     RECT  78.617 3.456 79.297 4.584 ;
     RECT  78.304 10.032 79.585 20.376 ;
     RECT  79.585 9.648 79.697 20.376 ;
     RECT  79.297 2.208 79.763 4.584 ;
     RECT  79.697 9.648 79.813 13.704 ;
     RECT  79.763 2.496 79.837 4.584 ;
     RECT  78.617 5.664 79.837 7.656 ;
     RECT  79.813 9.168 79.837 13.704 ;
     RECT  79.837 2.496 79.945 4.632 ;
     RECT  79.837 5.664 79.945 13.704 ;
     RECT  79.121 0.048 79.955 0.12 ;
     RECT  79.697 14.688 80.129 20.376 ;
     RECT  79.945 2.496 80.165 13.704 ;
     RECT  80.053 1.152 80.201 1.176 ;
     RECT  80.165 7.2 80.201 13.704 ;
     RECT  80.201 10.272 80.701 13.704 ;
     RECT  80.129 14.688 80.701 19.656 ;
     RECT  80.701 10.272 80.705 19.656 ;
     RECT  80.705 18.768 80.741 19.656 ;
     RECT  80.705 10.272 80.777 17.688 ;
     RECT  80.777 15.456 80.867 17.688 ;
     RECT  79.955 0.048 80.989 0.072 ;
     RECT  80.741 19.008 80.993 19.656 ;
     RECT  80.867 16.56 81.073 17.688 ;
     RECT  80.989 0.048 81.137 0.12 ;
     RECT  80.777 10.272 81.173 14.328 ;
     RECT  80.201 7.2 81.205 9.144 ;
     RECT  81.137 0.048 81.389 0.072 ;
     RECT  81.173 11.376 81.491 14.328 ;
     RECT  80.165 2.496 81.497 6.024 ;
     RECT  81.073 16.56 81.497 17.112 ;
     RECT  81.205 7.2 81.565 9.192 ;
     RECT  81.565 6.384 81.713 9.192 ;
     RECT  81.713 6.384 81.749 6.84 ;
     RECT  81.497 2.496 81.893 5.304 ;
     RECT  81.893 3.408 81.965 5.304 ;
     RECT  80.867 15.456 81.965 15.528 ;
     RECT  81.491 11.376 82.109 13.848 ;
     RECT  81.713 7.872 82.145 9.192 ;
     RECT  82.109 11.376 82.181 11.928 ;
     RECT  81.173 10.272 82.249 10.296 ;
     RECT  81.965 3.408 82.325 5.16 ;
     RECT  80.993 19.008 82.357 19.032 ;
     RECT  82.249 10.176 82.429 10.296 ;
     RECT  81.497 17.04 82.885 17.064 ;
     RECT  82.357 18.24 82.885 19.032 ;
     RECT  82.885 17.04 82.981 19.032 ;
     RECT  82.325 3.408 83.408 3.432 ;
     RECT  82.325 4.512 83.408 5.16 ;
     RECT  81.749 6.48 83.408 6.84 ;
     RECT  82.145 7.872 83.408 9.096 ;
     RECT  82.429 10.176 83.408 10.392 ;
     RECT  82.181 11.376 83.408 11.88 ;
     RECT  82.109 13.104 83.408 13.848 ;
     RECT  81.965 15.456 83.408 15.48 ;
     RECT  82.981 16.512 83.408 19.032 ;
     RECT  83.408 2.148 83.512 19.452 ;
     RECT  83.512 2.418 83.704 19.182 ;
    LAYER M5 ;
     RECT  26.064 0.016 32.136 0.037 ;
     RECT  17.088 0.037 17.112 0.085 ;
     RECT  26.064 0.037 32.76 0.085 ;
     RECT  6.816 0.037 6.84 0.181 ;
     RECT  55.728 0.037 55.752 0.227 ;
     RECT  6.768 0.181 6.84 0.277 ;
     RECT  7.968 0.085 7.992 0.277 ;
     RECT  9.936 0.016 16.008 0.325 ;
     RECT  9.648 0.325 16.008 0.659 ;
     RECT  9.648 0.659 15.912 1.235 ;
     RECT  60.816 1.141 60.84 1.283 ;
     RECT  16.992 0.085 17.112 1.763 ;
     RECT  26.064 0.085 32.856 1.763 ;
     RECT  42.528 0.037 42.696 1.763 ;
     RECT  45.264 0.016 54.408 1.763 ;
     RECT  9.648 1.235 15.816 1.811 ;
     RECT  45.36 1.763 54.408 1.859 ;
     RECT  45.36 1.859 54.12 1.907 ;
     RECT  47.856 1.907 54.12 1.955 ;
     RECT  3.408 2.101 3.432 2.137 ;
     RECT  24.672 0.037 24.696 2.137 ;
     RECT  40.032 0.037 40.056 2.137 ;
     RECT  62.592 0.517 62.616 2.137 ;
     RECT  67.536 0.016 76.68 2.137 ;
     RECT  9.648 1.811 15.24 2.149 ;
     RECT  6.768 0.277 7.992 2.151 ;
     RECT  18.6 2.137 18.72 2.151 ;
     RECT  34.8 2.137 34.92 2.151 ;
     RECT  40.032 2.137 40.32 2.151 ;
     RECT  41.472 0.037 41.496 2.151 ;
     RECT  56.4 2.137 56.52 2.151 ;
     RECT  78 2.137 78.12 2.151 ;
     RECT  83.4 2.137 83.52 2.151 ;
     RECT  27.6 1.763 32.856 2.195 ;
     RECT  18.6 2.151 18.912 2.197 ;
     RECT  37.44 0.037 38.04 2.197 ;
     RECT  79.92 0.085 79.944 2.197 ;
     RECT  26.064 1.763 26.472 2.243 ;
     RECT  5.76 2.149 5.784 2.245 ;
     RECT  18.6 2.197 20.328 2.245 ;
     RECT  24 2.137 24.696 2.245 ;
     RECT  26.064 2.243 26.376 2.245 ;
     RECT  56.4 2.151 56.712 2.245 ;
     RECT  61.8 2.137 62.616 2.245 ;
     RECT  63.888 2.197 63.912 2.245 ;
     RECT  9.552 2.149 15.24 2.291 ;
     RECT  24 2.245 26.376 2.291 ;
     RECT  27.648 2.195 32.856 2.291 ;
     RECT  45.36 1.907 46.824 2.291 ;
     RECT  67.2 2.137 76.68 2.291 ;
     RECT  27.648 2.291 30.744 2.339 ;
     RECT  47.952 1.955 54.12 2.339 ;
     RECT  37.44 2.197 38.088 2.389 ;
     RECT  47.952 2.339 52.008 2.531 ;
     RECT  16.992 1.763 17.016 2.579 ;
     RECT  9.552 2.291 15.144 2.677 ;
     RECT  72.24 2.291 76.68 2.677 ;
     RECT  78 2.151 78.312 2.677 ;
     RECT  5.664 2.245 5.784 2.725 ;
     RECT  6.768 2.151 8.112 2.725 ;
     RECT  18.096 2.245 20.328 2.773 ;
     RECT  2.4 2.137 3.432 2.821 ;
     RECT  5.664 2.725 8.112 2.821 ;
     RECT  9.504 2.677 15.144 2.821 ;
     RECT  18.048 2.773 20.328 2.821 ;
     RECT  32.352 2.291 32.856 2.821 ;
     RECT  34.8 2.151 35.112 2.821 ;
     RECT  40.032 2.151 41.496 2.821 ;
     RECT  53.136 2.339 54.12 2.821 ;
     RECT  56.016 2.245 57.336 2.821 ;
     RECT  61.8 2.245 64.104 2.821 ;
     RECT  67.2 2.291 69.144 2.821 ;
     RECT  81.024 2.821 81.048 2.869 ;
     RECT  42.528 1.763 42.552 2.915 ;
     RECT  47.952 2.531 51.816 2.917 ;
     RECT  17.616 2.821 20.472 2.963 ;
     RECT  9.36 2.821 15.144 2.965 ;
     RECT  5.424 2.821 8.112 3.013 ;
     RECT  9.312 2.965 15.144 3.013 ;
     RECT  21.552 2.917 21.576 3.107 ;
     RECT  36.96 2.389 38.088 3.109 ;
     RECT  39.408 2.821 41.496 3.109 ;
     RECT  5.424 3.013 15.144 3.203 ;
     RECT  13.008 3.203 15.144 3.301 ;
     RECT  32.352 2.821 35.112 3.349 ;
     RECT  44.256 2.245 44.28 3.349 ;
     RECT  81.024 2.869 81.432 3.349 ;
     RECT  2.4 2.821 3.96 3.397 ;
     RECT  32.352 3.349 35.832 3.397 ;
     RECT  36.96 3.109 41.496 3.397 ;
     RECT  53.136 2.821 54.36 3.397 ;
     RECT  70.992 2.291 71.016 3.397 ;
     RECT  83.4 2.151 83.712 3.397 ;
     RECT  45.6 2.291 46.824 3.443 ;
     RECT  47.856 2.917 51.816 3.443 ;
     RECT  32.352 3.397 41.496 3.491 ;
     RECT  2.4 3.397 4.104 3.589 ;
     RECT  47.856 3.443 51.672 3.827 ;
     RECT  13.008 3.301 15.576 3.925 ;
     RECT  28.8 2.339 30.744 3.925 ;
     RECT  32.352 3.491 36.744 3.925 ;
     RECT  61.056 2.821 64.104 3.925 ;
     RECT  79.728 2.197 79.944 3.925 ;
     RECT  81.024 3.349 81.768 3.925 ;
     RECT  2.4 3.589 4.248 4.163 ;
     RECT  48.288 3.827 51.672 4.355 ;
     RECT  43.296 3.349 44.376 4.405 ;
     RECT  45.6 3.443 45.912 4.405 ;
     RECT  22.656 2.245 22.68 4.501 ;
     RECT  38.064 3.491 41.496 4.501 ;
     RECT  52.896 3.397 54.36 4.501 ;
     RECT  56.016 2.821 57.96 4.501 ;
     RECT  3.936 4.163 4.248 4.643 ;
     RECT  79.728 3.925 81.768 4.883 ;
     RECT  66.768 2.821 69.144 4.979 ;
     RECT  52.896 4.501 57.96 5.171 ;
     RECT  59.424 2.245 59.448 5.365 ;
     RECT  43.296 4.405 45.912 5.557 ;
     RECT  27.648 2.339 27.816 5.605 ;
     RECT  28.8 3.925 36.744 5.605 ;
     RECT  48.288 4.355 51.432 5.605 ;
     RECT  52.896 5.171 54.36 5.605 ;
     RECT  48.288 5.605 54.36 5.747 ;
     RECT  65.184 5.461 65.208 5.747 ;
     RECT  48.672 5.747 54.36 6.083 ;
     RECT  47.04 5.077 47.064 6.181 ;
     RECT  27.648 5.605 36.744 6.371 ;
     RECT  21.936 4.501 22.68 6.419 ;
     RECT  43.296 5.557 46.008 6.469 ;
     RECT  47.04 6.181 47.16 6.469 ;
     RECT  43.296 6.469 47.16 6.563 ;
     RECT  43.296 6.563 46.968 6.707 ;
     RECT  56.016 5.171 57.96 7.285 ;
     RECT  59.424 5.365 59.64 7.285 ;
     RECT  56.016 7.285 59.64 7.427 ;
     RECT  13.008 3.925 16.488 7.429 ;
     RECT  17.616 2.963 20.328 7.429 ;
     RECT  27.648 6.371 31.512 7.957 ;
     RECT  38.064 4.501 41.592 7.957 ;
     RECT  27.36 7.957 31.512 8.003 ;
     RECT  13.008 7.429 20.328 8.149 ;
     RECT  24 2.291 26.328 8.293 ;
     RECT  27.36 8.003 27.672 8.293 ;
     RECT  38.064 7.957 41.64 8.437 ;
     RECT  72.24 2.677 78.312 8.579 ;
     RECT  67.2 4.979 69.144 8.675 ;
     RECT  37.824 8.437 41.64 8.723 ;
     RECT  24 8.293 27.672 8.963 ;
     RECT  37.824 8.723 41.592 9.107 ;
     RECT  22.656 6.419 22.68 9.109 ;
     RECT  48.672 6.083 51.432 9.157 ;
     RECT  46.944 6.707 46.968 9.203 ;
     RECT  79.728 4.883 81.048 9.203 ;
     RECT  65.616 7.909 65.64 9.541 ;
     RECT  52.896 6.083 54.36 9.589 ;
     RECT  5.424 3.203 11.832 9.637 ;
     RECT  22.656 9.109 23.016 9.637 ;
     RECT  24 8.963 26.328 9.637 ;
     RECT  70.896 3.397 71.016 9.637 ;
     RECT  28.8 8.003 31.512 9.683 ;
     RECT  13.008 8.149 20.76 9.731 ;
     RECT  48.48 9.157 51.432 9.781 ;
     RECT  52.464 9.589 54.36 9.781 ;
     RECT  32.496 6.371 36.744 9.827 ;
     RECT  68.496 8.675 69.144 9.923 ;
     RECT  75.168 8.579 78.312 10.021 ;
     RECT  79.728 9.203 79.848 10.021 ;
     RECT  65.088 9.541 65.64 10.067 ;
     RECT  56.016 7.427 59.592 10.069 ;
     RECT  32.832 9.827 36.744 10.165 ;
     RECT  38.064 9.107 41.592 10.165 ;
     RECT  48.48 9.781 54.36 10.213 ;
     RECT  72.24 8.579 74.184 10.213 ;
     RECT  75.168 10.021 79.848 10.213 ;
     RECT  70.656 9.637 71.016 10.259 ;
     RECT  15.552 9.731 20.76 10.307 ;
     RECT  22.656 9.637 26.328 10.307 ;
     RECT  72.24 10.213 79.848 10.307 ;
     RECT  5.328 9.637 11.832 10.643 ;
     RECT  60.912 3.925 64.104 10.693 ;
     RECT  17.616 10.307 20.76 10.741 ;
     RECT  15.552 10.307 16.488 10.789 ;
     RECT  32.832 10.165 41.592 10.883 ;
     RECT  47.904 10.213 54.36 10.931 ;
     RECT  32.832 10.883 38.328 10.979 ;
     RECT  24 10.307 26.328 11.269 ;
     RECT  27.36 8.963 27.672 11.269 ;
     RECT  43.296 6.707 45.912 11.269 ;
     RECT  69.12 9.923 69.144 11.269 ;
     RECT  5.424 10.643 11.832 11.317 ;
     RECT  13.008 9.731 14.328 11.317 ;
     RECT  32.832 10.979 36.744 11.317 ;
     RECT  56.016 10.069 59.64 11.317 ;
     RECT  60.72 10.693 64.104 11.317 ;
     RECT  67.2 8.675 67.512 11.317 ;
     RECT  72.24 10.307 79.752 11.317 ;
     RECT  22.656 10.307 23.016 11.365 ;
     RECT  24 11.269 27.672 11.365 ;
     RECT  72.24 11.317 79.848 11.411 ;
     RECT  75.456 11.411 79.848 11.651 ;
     RECT  15.456 10.789 16.488 11.747 ;
     RECT  69.12 11.269 69.624 11.989 ;
     RECT  66.288 11.317 67.512 12.035 ;
     RECT  69.024 11.989 69.624 12.035 ;
     RECT  79.344 11.651 79.848 12.275 ;
     RECT  39.408 10.883 41.304 12.325 ;
     RECT  42.48 11.269 45.912 12.325 ;
     RECT  38.064 10.979 38.328 12.469 ;
     RECT  39.408 12.325 45.912 12.469 ;
     RECT  47.184 11.365 47.208 12.469 ;
     RECT  65.088 10.067 65.112 12.517 ;
     RECT  67.2 12.035 67.512 12.517 ;
     RECT  69.024 12.035 69.144 12.517 ;
     RECT  56.016 11.317 64.104 12.805 ;
     RECT  65.088 12.517 65.544 12.805 ;
     RECT  17.616 10.741 21.24 12.997 ;
     RECT  22.656 11.365 27.672 12.997 ;
     RECT  16.464 11.747 16.488 13.045 ;
     RECT  17.616 12.997 27.672 13.045 ;
     RECT  48.672 10.931 54.36 13.045 ;
     RECT  72.24 11.411 74.232 13.093 ;
     RECT  16.464 13.045 27.672 13.139 ;
     RECT  56.016 12.805 65.544 13.187 ;
     RECT  70.896 10.259 71.016 13.187 ;
     RECT  72.24 13.093 74.328 13.379 ;
     RECT  5.424 11.317 14.328 13.477 ;
     RECT  15.456 11.747 15.48 13.477 ;
     RECT  38.064 12.469 47.208 13.523 ;
     RECT  16.464 13.139 25.8 13.715 ;
     RECT  75.456 11.651 78.312 13.813 ;
     RECT  80.832 9.203 81.048 13.813 ;
     RECT  48.336 13.045 54.36 13.859 ;
     RECT  3.936 4.643 4.104 13.957 ;
     RECT  38.064 13.523 47.16 14.099 ;
     RECT  79.344 12.275 79.752 14.101 ;
     RECT  5.424 13.477 15.48 14.147 ;
     RECT  39.408 14.099 47.16 14.195 ;
     RECT  28.8 9.683 31.32 14.197 ;
     RECT  32.304 11.317 36.744 14.197 ;
     RECT  5.424 14.147 14.328 14.339 ;
     RECT  80.832 13.813 81.48 14.339 ;
     RECT  3.84 13.957 4.104 14.341 ;
     RECT  39.408 14.195 46.872 14.435 ;
     RECT  70.992 13.187 71.016 14.485 ;
     RECT  72.24 13.379 74.232 14.485 ;
     RECT  25.584 13.715 25.8 14.773 ;
     RECT  26.832 13.139 27.672 14.773 ;
     RECT  3.744 14.341 4.104 14.819 ;
     RECT  28.8 14.197 36.744 14.821 ;
     RECT  38.064 14.099 38.328 14.821 ;
     RECT  7.632 14.339 14.328 14.867 ;
     RECT  39.408 14.435 46.824 14.867 ;
     RECT  70.992 14.485 74.232 14.867 ;
     RECT  12 14.867 14.328 15.107 ;
     RECT  67.2 12.517 69.144 15.157 ;
     RECT  71.808 14.867 74.232 15.203 ;
     RECT  56.016 13.187 64.104 15.205 ;
     RECT  67.2 15.157 70.056 15.253 ;
     RECT  28.8 14.821 38.328 15.299 ;
     RECT  65.52 13.187 65.544 15.299 ;
     RECT  48.432 13.859 54.36 15.443 ;
     RECT  16.464 13.715 24.408 15.587 ;
     RECT  25.584 14.773 27.672 15.589 ;
     RECT  28.8 15.299 36.744 15.589 ;
     RECT  5.424 14.339 6.648 15.637 ;
     RECT  7.632 14.867 10.968 15.637 ;
     RECT  75.312 13.813 78.312 15.685 ;
     RECT  79.296 14.101 79.752 15.685 ;
     RECT  66.816 15.253 70.056 15.731 ;
     RECT  75.312 15.685 79.752 15.779 ;
     RECT  48.432 15.443 51.432 15.877 ;
     RECT  0.144 12.805 0.168 15.923 ;
     RECT  2.4 4.163 2.712 15.925 ;
     RECT  3.84 14.819 4.104 15.925 ;
     RECT  17.616 15.587 24.408 16.019 ;
     RECT  48.288 15.877 51.432 16.019 ;
     RECT  52.416 15.443 54.36 16.019 ;
     RECT  55.584 15.205 64.104 16.019 ;
     RECT  66.816 15.731 69.144 16.019 ;
     RECT  75.744 15.779 79.752 16.067 ;
     RECT  22.656 16.019 24.408 16.117 ;
     RECT  78 16.067 79.752 16.165 ;
     RECT  38.064 15.299 38.328 16.357 ;
     RECT  39.456 14.867 46.824 16.357 ;
     RECT  15.456 14.147 15.48 16.501 ;
     RECT  16.464 15.587 16.488 16.501 ;
     RECT  2.4 15.925 4.104 16.595 ;
     RECT  38.064 16.357 46.824 16.595 ;
     RECT  53.568 16.019 54.36 16.595 ;
     RECT  78 16.165 79.8 16.789 ;
     RECT  80.832 14.339 81.048 16.789 ;
     RECT  72.24 15.203 74.232 16.837 ;
     RECT  72.048 16.837 74.328 16.885 ;
     RECT  18.048 16.019 21.48 16.931 ;
     RECT  67.2 16.019 69.144 16.981 ;
     RECT  71.472 16.885 74.328 16.981 ;
     RECT  12 15.107 12.024 17.029 ;
     RECT  13.008 15.107 14.328 17.029 ;
     RECT  49.488 16.019 51.432 17.029 ;
     RECT  18.048 16.931 21.384 17.075 ;
     RECT  25.584 15.589 36.744 17.075 ;
     RECT  78 16.789 81.048 17.075 ;
     RECT  5.424 15.637 10.968 17.077 ;
     RECT  71.472 16.981 74.568 17.077 ;
     RECT  75.744 16.067 76.92 17.077 ;
     RECT  18.048 17.075 21.24 17.123 ;
     RECT  25.776 17.075 36.744 17.123 ;
     RECT  55.824 16.019 64.104 17.123 ;
     RECT  78 17.075 79.752 17.123 ;
     RECT  3.84 16.595 4.104 17.171 ;
     RECT  12 17.029 14.328 17.171 ;
     RECT  18.048 17.123 19.944 17.171 ;
     RECT  38.736 16.595 46.824 17.171 ;
     RECT  61.68 17.123 64.104 17.171 ;
     RECT  5.136 17.077 10.968 17.219 ;
     RECT  5.424 17.219 8.112 17.267 ;
     RECT  67.2 16.981 69.528 17.269 ;
     RECT  9.6 17.219 10.968 17.315 ;
     RECT  48.288 16.019 48.408 17.317 ;
     RECT  49.488 17.029 51.864 17.317 ;
     RECT  71.472 17.077 76.92 17.365 ;
     RECT  78 17.123 78.744 17.365 ;
     RECT  71.472 17.365 78.744 17.555 ;
     RECT  26.16 17.123 36.744 17.605 ;
     RECT  26.16 17.605 36.888 17.651 ;
     RECT  61.68 17.171 63.768 17.651 ;
     RECT  4.08 17.171 4.104 17.699 ;
     RECT  7.536 17.267 8.112 17.699 ;
     RECT  12.048 17.171 14.328 17.699 ;
     RECT  15.456 16.501 16.488 17.699 ;
     RECT  18.048 17.171 18.912 17.699 ;
     RECT  22.656 16.117 24.456 17.699 ;
     RECT  26.928 17.651 36.888 17.699 ;
     RECT  48.288 17.317 51.864 17.699 ;
     RECT  53.568 16.595 53.688 17.699 ;
     RECT  61.8 17.651 63.768 17.699 ;
     RECT  81.024 17.075 81.048 17.699 ;
     RECT  82.896 3.397 83.712 17.699 ;
     RECT  16.368 17.699 16.488 17.701 ;
     RECT  13.104 17.699 14.328 17.747 ;
     RECT  48.288 17.699 48.984 17.747 ;
     RECT  63.6 17.699 63.768 17.747 ;
     RECT  5.424 17.267 5.448 17.795 ;
     RECT  67.2 17.269 69.96 17.795 ;
     RECT  26.928 17.699 35.496 17.843 ;
     RECT  79.728 17.123 79.752 17.843 ;
     RECT  23.232 17.699 24.456 17.987 ;
     RECT  36.864 17.699 36.888 18.037 ;
     RECT  12.048 17.699 12.072 18.083 ;
     RECT  23.232 17.987 24.408 18.131 ;
     RECT  23.28 18.131 24.408 18.179 ;
     RECT  82.992 17.699 83.712 18.179 ;
     RECT  38.736 17.171 43.416 18.181 ;
     RECT  71.472 17.555 76.392 18.181 ;
     RECT  50.016 17.699 51.864 18.227 ;
     RECT  55.824 17.123 56.808 18.229 ;
     RECT  26.928 17.843 30.6 18.275 ;
     RECT  57.84 17.123 60.696 18.275 ;
     RECT  53.808 18.037 53.832 18.277 ;
     RECT  77.472 17.555 78.744 18.323 ;
     RECT  69.936 17.795 69.96 18.421 ;
     RECT  71.376 18.181 76.392 18.421 ;
     RECT  48.96 17.747 48.984 18.515 ;
     RECT  69.936 18.421 76.392 18.515 ;
     RECT  63.744 17.747 63.768 18.611 ;
     RECT  77.472 18.323 78.408 18.611 ;
     RECT  50.016 18.227 51.816 18.661 ;
     RECT  31.824 17.843 35.496 18.709 ;
     RECT  13.104 17.747 13.608 18.757 ;
     RECT  16.368 17.701 17.064 18.757 ;
     RECT  19.92 17.171 19.944 18.757 ;
     RECT  21.216 17.123 21.24 18.757 ;
     RECT  38.736 18.181 43.704 18.757 ;
     RECT  53.808 18.277 54.216 18.757 ;
     RECT  28.368 18.275 29.976 18.803 ;
     RECT  18.336 17.699 18.912 18.805 ;
     RECT  19.92 18.757 21.24 18.805 ;
     RECT  26.928 18.275 26.952 18.805 ;
     RECT  36.864 18.037 37.512 18.805 ;
     RECT  38.736 18.757 43.752 18.805 ;
     RECT  53.808 18.757 54.696 18.805 ;
     RECT  55.824 18.229 56.856 18.805 ;
     RECT  57.84 18.275 60.312 18.805 ;
     RECT  26.064 18.805 26.952 18.851 ;
     RECT  31.824 18.709 35.784 18.851 ;
     RECT  44.784 17.171 46.824 18.851 ;
     RECT  31.92 18.851 35.784 18.853 ;
     RECT  36.864 18.805 43.752 18.853 ;
     RECT  18.096 18.805 18.912 18.901 ;
     RECT  19.92 18.805 21.576 18.901 ;
     RECT  23.28 18.179 24.312 18.947 ;
     RECT  26.064 18.851 26.088 18.947 ;
     RECT  70.32 18.515 76.392 18.949 ;
     RECT  49.392 18.661 51.816 18.995 ;
     RECT  9.648 17.315 10.968 18.997 ;
     RECT  29.184 18.803 29.712 19.043 ;
     RECT  64.32 18.997 64.632 19.139 ;
     RECT  70.32 18.949 76.872 19.187 ;
     RECT  77.904 18.611 78.408 19.187 ;
     RECT  78 19.187 78.408 19.235 ;
     RECT  9.648 18.997 11.4 19.237 ;
     RECT  12.528 18.757 13.608 19.237 ;
     RECT  31.92 18.853 43.752 19.237 ;
     RECT  44.784 18.851 46.008 19.237 ;
     RECT  29.28 19.043 29.712 19.283 ;
     RECT  9.648 19.237 13.608 19.285 ;
     RECT  9.648 19.285 14.28 19.333 ;
     RECT  15.504 18.757 17.064 19.333 ;
     RECT  18.096 18.901 21.576 19.333 ;
     RECT  50.016 18.995 51.816 19.333 ;
     RECT  52.944 18.805 60.312 19.333 ;
     RECT  50.016 19.333 60.312 19.379 ;
     RECT  31.92 19.237 46.008 19.427 ;
     RECT  64.32 19.139 64.344 19.427 ;
     RECT  67.2 17.795 68.856 19.427 ;
     RECT  2.4 16.595 2.712 19.449 ;
     RECT  7.8 17.699 8.112 19.449 ;
     RECT  24 18.947 24.312 19.449 ;
     RECT  29.4 19.283 29.712 19.449 ;
     RECT  31.92 19.427 45.912 19.449 ;
     RECT  67.2 19.427 67.512 19.449 ;
     RECT  78 19.235 78.312 19.449 ;
     RECT  83.4 18.179 83.712 19.449 ;
     RECT  2.4 19.449 2.52 19.463 ;
     RECT  7.8 19.449 7.92 19.463 ;
     RECT  24 19.449 24.12 19.463 ;
     RECT  29.4 19.449 29.52 19.463 ;
     RECT  31.92 19.449 45.72 19.463 ;
     RECT  50.016 19.379 60.264 19.463 ;
     RECT  61.8 17.699 62.52 19.463 ;
     RECT  67.2 19.449 67.32 19.463 ;
     RECT  78 19.449 78.12 19.463 ;
     RECT  83.4 19.449 83.52 19.463 ;
     RECT  51.216 19.463 60.264 20.485 ;
     RECT  68.832 19.427 68.856 21.491 ;
     RECT  31.92 19.463 44.808 21.539 ;
     RECT  50.016 19.463 50.04 21.539 ;
     RECT  62.496 19.463 62.52 21.539 ;
     RECT  9.648 19.333 21.864 21.584 ;
     RECT  31.92 21.539 44.136 21.584 ;
     RECT  51.12 20.485 60.264 21.584 ;
     RECT  70.32 19.187 76.392 21.584 ;
  END
END ot_qfd_vm_su1024_t
END LIBRARY
